VERSION 5.8 ;
BUSBITCHARS "[]" ;
DIVIDERCHAR "/" ;
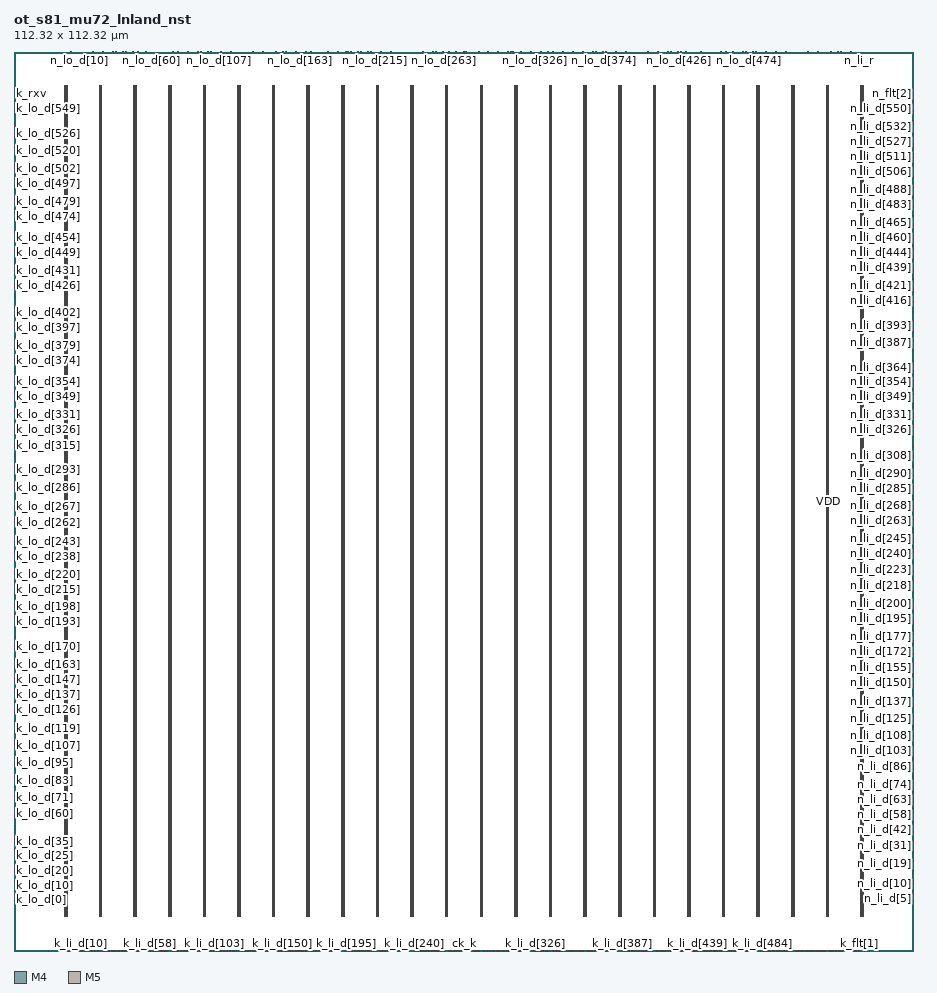
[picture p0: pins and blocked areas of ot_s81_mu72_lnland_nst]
MACRO ot_s81_mu72_lnland_nst
 CLASS BLOCK ;
 ORIGIN 0 0 ;
 SIZE 112.32 BY 112.32 ;
 SYMMETRY X Y ;
 PIN k_lo_v
  DIRECTION INPUT ;
  USE SIGNAL ;
  PORT
   LAYER M4 ;
   RECT 0.000000 6.240000 0.084000 6.264000 ;
  END
 END k_lo_v
 PIN k_lo_d[0]
  DIRECTION INPUT ;
  USE SIGNAL ;
  PORT
   LAYER M4 ;
   RECT 0.000000 6.384000 0.084000 6.408000 ;
  END
 END k_lo_d[0]
 PIN k_lo_d[1]
  DIRECTION INPUT ;
  USE SIGNAL ;
  PORT
   LAYER M4 ;
   RECT 0.000000 6.576000 0.084000 6.600000 ;
  END
 END k_lo_d[1]
 PIN k_lo_d[2]
  DIRECTION INPUT ;
  USE SIGNAL ;
  PORT
   LAYER M4 ;
   RECT 0.000000 6.768000 0.084000 6.792000 ;
  END
 END k_lo_d[2]
 PIN k_lo_d[3]
  DIRECTION INPUT ;
  USE SIGNAL ;
  PORT
   LAYER M4 ;
   RECT 0.000000 6.960000 0.084000 6.984000 ;
  END
 END k_lo_d[3]
 PIN k_lo_d[4]
  DIRECTION INPUT ;
  USE SIGNAL ;
  PORT
   LAYER M4 ;
   RECT 0.000000 7.104000 0.084000 7.128000 ;
  END
 END k_lo_d[4]
 PIN k_lo_d[5]
  DIRECTION INPUT ;
  USE SIGNAL ;
  PORT
   LAYER M4 ;
   RECT 0.000000 7.296000 0.084000 7.320000 ;
  END
 END k_lo_d[5]
 PIN k_lo_d[6]
  DIRECTION INPUT ;
  USE SIGNAL ;
  PORT
   LAYER M4 ;
   RECT 0.000000 7.488000 0.084000 7.512000 ;
  END
 END k_lo_d[6]
 PIN k_lo_d[7]
  DIRECTION INPUT ;
  USE SIGNAL ;
  PORT
   LAYER M4 ;
   RECT 0.000000 7.680000 0.084000 7.704000 ;
  END
 END k_lo_d[7]
 PIN k_lo_d[8]
  DIRECTION INPUT ;
  USE SIGNAL ;
  PORT
   LAYER M4 ;
   RECT 0.000000 7.824000 0.084000 7.848000 ;
  END
 END k_lo_d[8]
 PIN k_lo_d[9]
  DIRECTION INPUT ;
  USE SIGNAL ;
  PORT
   LAYER M4 ;
   RECT 0.000000 8.016000 0.084000 8.040000 ;
  END
 END k_lo_d[9]
 PIN k_lo_d[10]
  DIRECTION INPUT ;
  USE SIGNAL ;
  PORT
   LAYER M4 ;
   RECT 0.000000 8.208000 0.084000 8.232000 ;
  END
 END k_lo_d[10]
 PIN k_lo_d[11]
  DIRECTION INPUT ;
  USE SIGNAL ;
  PORT
   LAYER M4 ;
   RECT 0.000000 8.400000 0.084000 8.424000 ;
  END
 END k_lo_d[11]
 PIN k_lo_d[12]
  DIRECTION INPUT ;
  USE SIGNAL ;
  PORT
   LAYER M4 ;
   RECT 0.000000 8.544000 0.084000 8.568000 ;
  END
 END k_lo_d[12]
 PIN k_lo_d[13]
  DIRECTION INPUT ;
  USE SIGNAL ;
  PORT
   LAYER M4 ;
   RECT 0.000000 8.736000 0.084000 8.760000 ;
  END
 END k_lo_d[13]
 PIN k_lo_d[14]
  DIRECTION INPUT ;
  USE SIGNAL ;
  PORT
   LAYER M4 ;
   RECT 0.000000 8.928000 0.084000 8.952000 ;
  END
 END k_lo_d[14]
 PIN k_lo_d[15]
  DIRECTION INPUT ;
  USE SIGNAL ;
  PORT
   LAYER M4 ;
   RECT 0.000000 9.120000 0.084000 9.144000 ;
  END
 END k_lo_d[15]
 PIN k_lo_d[16]
  DIRECTION INPUT ;
  USE SIGNAL ;
  PORT
   LAYER M4 ;
   RECT 0.000000 9.264000 0.084000 9.288000 ;
  END
 END k_lo_d[16]
 PIN k_lo_d[17]
  DIRECTION INPUT ;
  USE SIGNAL ;
  PORT
   LAYER M4 ;
   RECT 0.000000 9.456000 0.084000 9.480000 ;
  END
 END k_lo_d[17]
 PIN k_lo_d[18]
  DIRECTION INPUT ;
  USE SIGNAL ;
  PORT
   LAYER M4 ;
   RECT 0.000000 9.648000 0.084000 9.672000 ;
  END
 END k_lo_d[18]
 PIN k_lo_d[19]
  DIRECTION INPUT ;
  USE SIGNAL ;
  PORT
   LAYER M4 ;
   RECT 0.000000 9.840000 0.084000 9.864000 ;
  END
 END k_lo_d[19]
 PIN k_lo_d[20]
  DIRECTION INPUT ;
  USE SIGNAL ;
  PORT
   LAYER M4 ;
   RECT 0.000000 9.984000 0.084000 10.008000 ;
  END
 END k_lo_d[20]
 PIN k_lo_d[21]
  DIRECTION INPUT ;
  USE SIGNAL ;
  PORT
   LAYER M4 ;
   RECT 0.000000 10.176000 0.084000 10.200000 ;
  END
 END k_lo_d[21]
 PIN k_lo_d[22]
  DIRECTION INPUT ;
  USE SIGNAL ;
  PORT
   LAYER M4 ;
   RECT 0.000000 10.368000 0.084000 10.392000 ;
  END
 END k_lo_d[22]
 PIN k_lo_d[23]
  DIRECTION INPUT ;
  USE SIGNAL ;
  PORT
   LAYER M4 ;
   RECT 0.000000 10.560000 0.084000 10.584000 ;
  END
 END k_lo_d[23]
 PIN k_lo_d[24]
  DIRECTION INPUT ;
  USE SIGNAL ;
  PORT
   LAYER M4 ;
   RECT 0.000000 10.704000 0.084000 10.728000 ;
  END
 END k_lo_d[24]
 PIN k_lo_d[25]
  DIRECTION INPUT ;
  USE SIGNAL ;
  PORT
   LAYER M4 ;
   RECT 0.000000 10.896000 0.084000 10.920000 ;
  END
 END k_lo_d[25]
 PIN k_lo_d[26]
  DIRECTION INPUT ;
  USE SIGNAL ;
  PORT
   LAYER M4 ;
   RECT 0.000000 11.088000 0.084000 11.112000 ;
  END
 END k_lo_d[26]
 PIN k_lo_d[27]
  DIRECTION INPUT ;
  USE SIGNAL ;
  PORT
   LAYER M4 ;
   RECT 0.000000 11.280000 0.084000 11.304000 ;
  END
 END k_lo_d[27]
 PIN k_lo_d[28]
  DIRECTION INPUT ;
  USE SIGNAL ;
  PORT
   LAYER M4 ;
   RECT 0.000000 11.424000 0.084000 11.448000 ;
  END
 END k_lo_d[28]
 PIN k_lo_d[29]
  DIRECTION INPUT ;
  USE SIGNAL ;
  PORT
   LAYER M4 ;
   RECT 0.000000 11.616000 0.084000 11.640000 ;
  END
 END k_lo_d[29]
 PIN k_lo_d[30]
  DIRECTION INPUT ;
  USE SIGNAL ;
  PORT
   LAYER M4 ;
   RECT 0.000000 11.808000 0.084000 11.832000 ;
  END
 END k_lo_d[30]
 PIN k_lo_d[31]
  DIRECTION INPUT ;
  USE SIGNAL ;
  PORT
   LAYER M4 ;
   RECT 0.000000 12.000000 0.084000 12.024000 ;
  END
 END k_lo_d[31]
 PIN k_lo_d[32]
  DIRECTION INPUT ;
  USE SIGNAL ;
  PORT
   LAYER M4 ;
   RECT 0.000000 12.144000 0.084000 12.168000 ;
  END
 END k_lo_d[32]
 PIN k_lo_d[33]
  DIRECTION INPUT ;
  USE SIGNAL ;
  PORT
   LAYER M4 ;
   RECT 0.000000 12.336000 0.084000 12.360000 ;
  END
 END k_lo_d[33]
 PIN k_lo_d[34]
  DIRECTION INPUT ;
  USE SIGNAL ;
  PORT
   LAYER M4 ;
   RECT 0.000000 12.528000 0.084000 12.552000 ;
  END
 END k_lo_d[34]
 PIN k_lo_d[35]
  DIRECTION INPUT ;
  USE SIGNAL ;
  PORT
   LAYER M4 ;
   RECT 0.000000 12.720000 0.084000 12.744000 ;
  END
 END k_lo_d[35]
 PIN k_lo_d[36]
  DIRECTION INPUT ;
  USE SIGNAL ;
  PORT
   LAYER M4 ;
   RECT 0.000000 12.864000 0.084000 12.888000 ;
  END
 END k_lo_d[36]
 PIN k_lo_d[37]
  DIRECTION INPUT ;
  USE SIGNAL ;
  PORT
   LAYER M4 ;
   RECT 0.000000 13.056000 0.084000 13.080000 ;
  END
 END k_lo_d[37]
 PIN k_lo_d[38]
  DIRECTION INPUT ;
  USE SIGNAL ;
  PORT
   LAYER M4 ;
   RECT 0.000000 13.248000 0.084000 13.272000 ;
  END
 END k_lo_d[38]
 PIN k_lo_d[39]
  DIRECTION INPUT ;
  USE SIGNAL ;
  PORT
   LAYER M4 ;
   RECT 0.000000 13.440000 0.084000 13.464000 ;
  END
 END k_lo_d[39]
 PIN k_lo_d[40]
  DIRECTION INPUT ;
  USE SIGNAL ;
  PORT
   LAYER M4 ;
   RECT 0.000000 13.584000 0.084000 13.608000 ;
  END
 END k_lo_d[40]
 PIN k_lo_d[41]
  DIRECTION INPUT ;
  USE SIGNAL ;
  PORT
   LAYER M4 ;
   RECT 0.000000 13.776000 0.084000 13.800000 ;
  END
 END k_lo_d[41]
 PIN k_lo_d[42]
  DIRECTION INPUT ;
  USE SIGNAL ;
  PORT
   LAYER M4 ;
   RECT 0.000000 13.968000 0.084000 13.992000 ;
  END
 END k_lo_d[42]
 PIN k_lo_d[43]
  DIRECTION INPUT ;
  USE SIGNAL ;
  PORT
   LAYER M4 ;
   RECT 0.000000 14.160000 0.084000 14.184000 ;
  END
 END k_lo_d[43]
 PIN k_lo_d[44]
  DIRECTION INPUT ;
  USE SIGNAL ;
  PORT
   LAYER M4 ;
   RECT 0.000000 14.304000 0.084000 14.328000 ;
  END
 END k_lo_d[44]
 PIN k_lo_d[45]
  DIRECTION INPUT ;
  USE SIGNAL ;
  PORT
   LAYER M4 ;
   RECT 0.000000 14.496000 0.084000 14.520000 ;
  END
 END k_lo_d[45]
 PIN k_lo_d[46]
  DIRECTION INPUT ;
  USE SIGNAL ;
  PORT
   LAYER M4 ;
   RECT 0.000000 14.688000 0.084000 14.712000 ;
  END
 END k_lo_d[46]
 PIN k_lo_d[47]
  DIRECTION INPUT ;
  USE SIGNAL ;
  PORT
   LAYER M4 ;
   RECT 0.000000 14.880000 0.084000 14.904000 ;
  END
 END k_lo_d[47]
 PIN k_lo_d[48]
  DIRECTION INPUT ;
  USE SIGNAL ;
  PORT
   LAYER M4 ;
   RECT 0.000000 15.024000 0.084000 15.048000 ;
  END
 END k_lo_d[48]
 PIN k_lo_d[49]
  DIRECTION INPUT ;
  USE SIGNAL ;
  PORT
   LAYER M4 ;
   RECT 0.000000 15.216000 0.084000 15.240000 ;
  END
 END k_lo_d[49]
 PIN k_lo_d[50]
  DIRECTION INPUT ;
  USE SIGNAL ;
  PORT
   LAYER M4 ;
   RECT 0.000000 15.408000 0.084000 15.432000 ;
  END
 END k_lo_d[50]
 PIN k_lo_d[51]
  DIRECTION INPUT ;
  USE SIGNAL ;
  PORT
   LAYER M4 ;
   RECT 0.000000 15.600000 0.084000 15.624000 ;
  END
 END k_lo_d[51]
 PIN k_lo_d[52]
  DIRECTION INPUT ;
  USE SIGNAL ;
  PORT
   LAYER M4 ;
   RECT 0.000000 15.744000 0.084000 15.768000 ;
  END
 END k_lo_d[52]
 PIN k_lo_d[53]
  DIRECTION INPUT ;
  USE SIGNAL ;
  PORT
   LAYER M4 ;
   RECT 0.000000 15.936000 0.084000 15.960000 ;
  END
 END k_lo_d[53]
 PIN k_lo_d[54]
  DIRECTION INPUT ;
  USE SIGNAL ;
  PORT
   LAYER M4 ;
   RECT 0.000000 16.128000 0.084000 16.152000 ;
  END
 END k_lo_d[54]
 PIN k_lo_d[55]
  DIRECTION INPUT ;
  USE SIGNAL ;
  PORT
   LAYER M4 ;
   RECT 0.000000 16.320000 0.084000 16.344000 ;
  END
 END k_lo_d[55]
 PIN k_lo_d[56]
  DIRECTION INPUT ;
  USE SIGNAL ;
  PORT
   LAYER M4 ;
   RECT 0.000000 16.464000 0.084000 16.488000 ;
  END
 END k_lo_d[56]
 PIN k_lo_d[57]
  DIRECTION INPUT ;
  USE SIGNAL ;
  PORT
   LAYER M4 ;
   RECT 0.000000 16.656000 0.084000 16.680000 ;
  END
 END k_lo_d[57]
 PIN k_lo_d[58]
  DIRECTION INPUT ;
  USE SIGNAL ;
  PORT
   LAYER M4 ;
   RECT 0.000000 16.848000 0.084000 16.872000 ;
  END
 END k_lo_d[58]
 PIN k_lo_d[59]
  DIRECTION INPUT ;
  USE SIGNAL ;
  PORT
   LAYER M4 ;
   RECT 0.000000 17.040000 0.084000 17.064000 ;
  END
 END k_lo_d[59]
 PIN k_lo_d[60]
  DIRECTION INPUT ;
  USE SIGNAL ;
  PORT
   LAYER M4 ;
   RECT 0.000000 17.184000 0.084000 17.208000 ;
  END
 END k_lo_d[60]
 PIN k_lo_d[61]
  DIRECTION INPUT ;
  USE SIGNAL ;
  PORT
   LAYER M4 ;
   RECT 0.000000 17.376000 0.084000 17.400000 ;
  END
 END k_lo_d[61]
 PIN k_lo_d[62]
  DIRECTION INPUT ;
  USE SIGNAL ;
  PORT
   LAYER M4 ;
   RECT 0.000000 17.568000 0.084000 17.592000 ;
  END
 END k_lo_d[62]
 PIN k_lo_d[63]
  DIRECTION INPUT ;
  USE SIGNAL ;
  PORT
   LAYER M4 ;
   RECT 0.000000 17.760000 0.084000 17.784000 ;
  END
 END k_lo_d[63]
 PIN k_lo_d[64]
  DIRECTION INPUT ;
  USE SIGNAL ;
  PORT
   LAYER M4 ;
   RECT 0.000000 17.904000 0.084000 17.928000 ;
  END
 END k_lo_d[64]
 PIN k_lo_d[65]
  DIRECTION INPUT ;
  USE SIGNAL ;
  PORT
   LAYER M4 ;
   RECT 0.000000 18.096000 0.084000 18.120000 ;
  END
 END k_lo_d[65]
 PIN k_lo_d[66]
  DIRECTION INPUT ;
  USE SIGNAL ;
  PORT
   LAYER M4 ;
   RECT 0.000000 18.288000 0.084000 18.312000 ;
  END
 END k_lo_d[66]
 PIN k_lo_d[67]
  DIRECTION INPUT ;
  USE SIGNAL ;
  PORT
   LAYER M4 ;
   RECT 0.000000 18.480000 0.084000 18.504000 ;
  END
 END k_lo_d[67]
 PIN k_lo_d[68]
  DIRECTION INPUT ;
  USE SIGNAL ;
  PORT
   LAYER M4 ;
   RECT 0.000000 18.624000 0.084000 18.648000 ;
  END
 END k_lo_d[68]
 PIN k_lo_d[69]
  DIRECTION INPUT ;
  USE SIGNAL ;
  PORT
   LAYER M4 ;
   RECT 0.000000 18.816000 0.084000 18.840000 ;
  END
 END k_lo_d[69]
 PIN k_lo_d[70]
  DIRECTION INPUT ;
  USE SIGNAL ;
  PORT
   LAYER M4 ;
   RECT 0.000000 19.008000 0.084000 19.032000 ;
  END
 END k_lo_d[70]
 PIN k_lo_d[71]
  DIRECTION INPUT ;
  USE SIGNAL ;
  PORT
   LAYER M4 ;
   RECT 0.000000 19.152000 0.084000 19.176000 ;
  END
 END k_lo_d[71]
 PIN k_lo_d[72]
  DIRECTION INPUT ;
  USE SIGNAL ;
  PORT
   LAYER M4 ;
   RECT 0.000000 19.344000 0.084000 19.368000 ;
  END
 END k_lo_d[72]
 PIN k_lo_d[73]
  DIRECTION INPUT ;
  USE SIGNAL ;
  PORT
   LAYER M4 ;
   RECT 0.000000 19.536000 0.084000 19.560000 ;
  END
 END k_lo_d[73]
 PIN k_lo_d[74]
  DIRECTION INPUT ;
  USE SIGNAL ;
  PORT
   LAYER M4 ;
   RECT 0.000000 19.728000 0.084000 19.752000 ;
  END
 END k_lo_d[74]
 PIN k_lo_d[75]
  DIRECTION INPUT ;
  USE SIGNAL ;
  PORT
   LAYER M4 ;
   RECT 0.000000 19.872000 0.084000 19.896000 ;
  END
 END k_lo_d[75]
 PIN k_lo_d[76]
  DIRECTION INPUT ;
  USE SIGNAL ;
  PORT
   LAYER M4 ;
   RECT 0.000000 20.064000 0.084000 20.088000 ;
  END
 END k_lo_d[76]
 PIN k_lo_d[77]
  DIRECTION INPUT ;
  USE SIGNAL ;
  PORT
   LAYER M4 ;
   RECT 0.000000 20.256000 0.084000 20.280000 ;
  END
 END k_lo_d[77]
 PIN k_lo_d[78]
  DIRECTION INPUT ;
  USE SIGNAL ;
  PORT
   LAYER M4 ;
   RECT 0.000000 20.448000 0.084000 20.472000 ;
  END
 END k_lo_d[78]
 PIN k_lo_d[79]
  DIRECTION INPUT ;
  USE SIGNAL ;
  PORT
   LAYER M4 ;
   RECT 0.000000 20.592000 0.084000 20.616000 ;
  END
 END k_lo_d[79]
 PIN k_lo_d[80]
  DIRECTION INPUT ;
  USE SIGNAL ;
  PORT
   LAYER M4 ;
   RECT 0.000000 20.784000 0.084000 20.808000 ;
  END
 END k_lo_d[80]
 PIN k_lo_d[81]
  DIRECTION INPUT ;
  USE SIGNAL ;
  PORT
   LAYER M4 ;
   RECT 0.000000 20.976000 0.084000 21.000000 ;
  END
 END k_lo_d[81]
 PIN k_lo_d[82]
  DIRECTION INPUT ;
  USE SIGNAL ;
  PORT
   LAYER M4 ;
   RECT 0.000000 21.168000 0.084000 21.192000 ;
  END
 END k_lo_d[82]
 PIN k_lo_d[83]
  DIRECTION INPUT ;
  USE SIGNAL ;
  PORT
   LAYER M4 ;
   RECT 0.000000 21.312000 0.084000 21.336000 ;
  END
 END k_lo_d[83]
 PIN k_lo_d[84]
  DIRECTION INPUT ;
  USE SIGNAL ;
  PORT
   LAYER M4 ;
   RECT 0.000000 21.504000 0.084000 21.528000 ;
  END
 END k_lo_d[84]
 PIN k_lo_d[85]
  DIRECTION INPUT ;
  USE SIGNAL ;
  PORT
   LAYER M4 ;
   RECT 0.000000 21.696000 0.084000 21.720000 ;
  END
 END k_lo_d[85]
 PIN k_lo_d[86]
  DIRECTION INPUT ;
  USE SIGNAL ;
  PORT
   LAYER M4 ;
   RECT 0.000000 21.888000 0.084000 21.912000 ;
  END
 END k_lo_d[86]
 PIN k_lo_d[87]
  DIRECTION INPUT ;
  USE SIGNAL ;
  PORT
   LAYER M4 ;
   RECT 0.000000 22.032000 0.084000 22.056000 ;
  END
 END k_lo_d[87]
 PIN k_lo_d[88]
  DIRECTION INPUT ;
  USE SIGNAL ;
  PORT
   LAYER M4 ;
   RECT 0.000000 22.224000 0.084000 22.248000 ;
  END
 END k_lo_d[88]
 PIN k_lo_d[89]
  DIRECTION INPUT ;
  USE SIGNAL ;
  PORT
   LAYER M4 ;
   RECT 0.000000 22.416000 0.084000 22.440000 ;
  END
 END k_lo_d[89]
 PIN k_lo_d[90]
  DIRECTION INPUT ;
  USE SIGNAL ;
  PORT
   LAYER M4 ;
   RECT 0.000000 22.608000 0.084000 22.632000 ;
  END
 END k_lo_d[90]
 PIN k_lo_d[91]
  DIRECTION INPUT ;
  USE SIGNAL ;
  PORT
   LAYER M4 ;
   RECT 0.000000 22.752000 0.084000 22.776000 ;
  END
 END k_lo_d[91]
 PIN k_lo_d[92]
  DIRECTION INPUT ;
  USE SIGNAL ;
  PORT
   LAYER M4 ;
   RECT 0.000000 22.944000 0.084000 22.968000 ;
  END
 END k_lo_d[92]
 PIN k_lo_d[93]
  DIRECTION INPUT ;
  USE SIGNAL ;
  PORT
   LAYER M4 ;
   RECT 0.000000 23.136000 0.084000 23.160000 ;
  END
 END k_lo_d[93]
 PIN k_lo_d[94]
  DIRECTION INPUT ;
  USE SIGNAL ;
  PORT
   LAYER M4 ;
   RECT 0.000000 23.328000 0.084000 23.352000 ;
  END
 END k_lo_d[94]
 PIN k_lo_d[95]
  DIRECTION INPUT ;
  USE SIGNAL ;
  PORT
   LAYER M4 ;
   RECT 0.000000 23.472000 0.084000 23.496000 ;
  END
 END k_lo_d[95]
 PIN k_lo_d[96]
  DIRECTION INPUT ;
  USE SIGNAL ;
  PORT
   LAYER M4 ;
   RECT 0.000000 23.664000 0.084000 23.688000 ;
  END
 END k_lo_d[96]
 PIN k_lo_d[97]
  DIRECTION INPUT ;
  USE SIGNAL ;
  PORT
   LAYER M4 ;
   RECT 0.000000 23.856000 0.084000 23.880000 ;
  END
 END k_lo_d[97]
 PIN k_lo_d[98]
  DIRECTION INPUT ;
  USE SIGNAL ;
  PORT
   LAYER M4 ;
   RECT 0.000000 24.048000 0.084000 24.072000 ;
  END
 END k_lo_d[98]
 PIN k_lo_d[99]
  DIRECTION INPUT ;
  USE SIGNAL ;
  PORT
   LAYER M4 ;
   RECT 0.000000 24.192000 0.084000 24.216000 ;
  END
 END k_lo_d[99]
 PIN k_lo_d[100]
  DIRECTION INPUT ;
  USE SIGNAL ;
  PORT
   LAYER M4 ;
   RECT 0.000000 24.384000 0.084000 24.408000 ;
  END
 END k_lo_d[100]
 PIN k_lo_d[101]
  DIRECTION INPUT ;
  USE SIGNAL ;
  PORT
   LAYER M4 ;
   RECT 0.000000 24.576000 0.084000 24.600000 ;
  END
 END k_lo_d[101]
 PIN k_lo_d[102]
  DIRECTION INPUT ;
  USE SIGNAL ;
  PORT
   LAYER M4 ;
   RECT 0.000000 24.768000 0.084000 24.792000 ;
  END
 END k_lo_d[102]
 PIN k_lo_d[103]
  DIRECTION INPUT ;
  USE SIGNAL ;
  PORT
   LAYER M4 ;
   RECT 0.000000 24.912000 0.084000 24.936000 ;
  END
 END k_lo_d[103]
 PIN k_lo_d[104]
  DIRECTION INPUT ;
  USE SIGNAL ;
  PORT
   LAYER M4 ;
   RECT 0.000000 25.104000 0.084000 25.128000 ;
  END
 END k_lo_d[104]
 PIN k_lo_d[105]
  DIRECTION INPUT ;
  USE SIGNAL ;
  PORT
   LAYER M4 ;
   RECT 0.000000 25.296000 0.084000 25.320000 ;
  END
 END k_lo_d[105]
 PIN k_lo_d[106]
  DIRECTION INPUT ;
  USE SIGNAL ;
  PORT
   LAYER M4 ;
   RECT 0.000000 25.488000 0.084000 25.512000 ;
  END
 END k_lo_d[106]
 PIN k_lo_d[107]
  DIRECTION INPUT ;
  USE SIGNAL ;
  PORT
   LAYER M4 ;
   RECT 0.000000 25.632000 0.084000 25.656000 ;
  END
 END k_lo_d[107]
 PIN k_lo_d[108]
  DIRECTION INPUT ;
  USE SIGNAL ;
  PORT
   LAYER M4 ;
   RECT 0.000000 25.824000 0.084000 25.848000 ;
  END
 END k_lo_d[108]
 PIN k_lo_d[109]
  DIRECTION INPUT ;
  USE SIGNAL ;
  PORT
   LAYER M4 ;
   RECT 0.000000 26.016000 0.084000 26.040000 ;
  END
 END k_lo_d[109]
 PIN k_lo_d[110]
  DIRECTION INPUT ;
  USE SIGNAL ;
  PORT
   LAYER M4 ;
   RECT 0.000000 26.208000 0.084000 26.232000 ;
  END
 END k_lo_d[110]
 PIN k_lo_d[111]
  DIRECTION INPUT ;
  USE SIGNAL ;
  PORT
   LAYER M4 ;
   RECT 0.000000 26.352000 0.084000 26.376000 ;
  END
 END k_lo_d[111]
 PIN k_lo_d[112]
  DIRECTION INPUT ;
  USE SIGNAL ;
  PORT
   LAYER M4 ;
   RECT 0.000000 26.544000 0.084000 26.568000 ;
  END
 END k_lo_d[112]
 PIN k_lo_d[113]
  DIRECTION INPUT ;
  USE SIGNAL ;
  PORT
   LAYER M4 ;
   RECT 0.000000 26.736000 0.084000 26.760000 ;
  END
 END k_lo_d[113]
 PIN k_lo_d[114]
  DIRECTION INPUT ;
  USE SIGNAL ;
  PORT
   LAYER M4 ;
   RECT 0.000000 26.928000 0.084000 26.952000 ;
  END
 END k_lo_d[114]
 PIN k_lo_d[115]
  DIRECTION INPUT ;
  USE SIGNAL ;
  PORT
   LAYER M4 ;
   RECT 0.000000 27.072000 0.084000 27.096000 ;
  END
 END k_lo_d[115]
 PIN k_lo_d[116]
  DIRECTION INPUT ;
  USE SIGNAL ;
  PORT
   LAYER M4 ;
   RECT 0.000000 27.264000 0.084000 27.288000 ;
  END
 END k_lo_d[116]
 PIN k_lo_d[117]
  DIRECTION INPUT ;
  USE SIGNAL ;
  PORT
   LAYER M4 ;
   RECT 0.000000 27.456000 0.084000 27.480000 ;
  END
 END k_lo_d[117]
 PIN k_lo_d[118]
  DIRECTION INPUT ;
  USE SIGNAL ;
  PORT
   LAYER M4 ;
   RECT 0.000000 27.648000 0.084000 27.672000 ;
  END
 END k_lo_d[118]
 PIN k_lo_d[119]
  DIRECTION INPUT ;
  USE SIGNAL ;
  PORT
   LAYER M4 ;
   RECT 0.000000 27.792000 0.084000 27.816000 ;
  END
 END k_lo_d[119]
 PIN k_lo_d[120]
  DIRECTION INPUT ;
  USE SIGNAL ;
  PORT
   LAYER M4 ;
   RECT 0.000000 27.984000 0.084000 28.008000 ;
  END
 END k_lo_d[120]
 PIN k_lo_d[121]
  DIRECTION INPUT ;
  USE SIGNAL ;
  PORT
   LAYER M4 ;
   RECT 0.000000 28.176000 0.084000 28.200000 ;
  END
 END k_lo_d[121]
 PIN k_lo_d[122]
  DIRECTION INPUT ;
  USE SIGNAL ;
  PORT
   LAYER M4 ;
   RECT 0.000000 28.368000 0.084000 28.392000 ;
  END
 END k_lo_d[122]
 PIN k_lo_d[123]
  DIRECTION INPUT ;
  USE SIGNAL ;
  PORT
   LAYER M4 ;
   RECT 0.000000 28.512000 0.084000 28.536000 ;
  END
 END k_lo_d[123]
 PIN k_lo_d[124]
  DIRECTION INPUT ;
  USE SIGNAL ;
  PORT
   LAYER M4 ;
   RECT 0.000000 28.704000 0.084000 28.728000 ;
  END
 END k_lo_d[124]
 PIN k_lo_d[125]
  DIRECTION INPUT ;
  USE SIGNAL ;
  PORT
   LAYER M4 ;
   RECT 0.000000 28.896000 0.084000 28.920000 ;
  END
 END k_lo_d[125]
 PIN k_lo_d[126]
  DIRECTION INPUT ;
  USE SIGNAL ;
  PORT
   LAYER M4 ;
   RECT 0.000000 29.088000 0.084000 29.112000 ;
  END
 END k_lo_d[126]
 PIN k_lo_d[127]
  DIRECTION INPUT ;
  USE SIGNAL ;
  PORT
   LAYER M4 ;
   RECT 0.000000 29.232000 0.084000 29.256000 ;
  END
 END k_lo_d[127]
 PIN k_lo_d[128]
  DIRECTION INPUT ;
  USE SIGNAL ;
  PORT
   LAYER M4 ;
   RECT 0.000000 29.424000 0.084000 29.448000 ;
  END
 END k_lo_d[128]
 PIN k_lo_d[129]
  DIRECTION INPUT ;
  USE SIGNAL ;
  PORT
   LAYER M4 ;
   RECT 0.000000 29.616000 0.084000 29.640000 ;
  END
 END k_lo_d[129]
 PIN k_lo_d[130]
  DIRECTION INPUT ;
  USE SIGNAL ;
  PORT
   LAYER M4 ;
   RECT 0.000000 29.808000 0.084000 29.832000 ;
  END
 END k_lo_d[130]
 PIN k_lo_d[131]
  DIRECTION INPUT ;
  USE SIGNAL ;
  PORT
   LAYER M4 ;
   RECT 0.000000 29.952000 0.084000 29.976000 ;
  END
 END k_lo_d[131]
 PIN k_lo_d[132]
  DIRECTION INPUT ;
  USE SIGNAL ;
  PORT
   LAYER M4 ;
   RECT 0.000000 30.144000 0.084000 30.168000 ;
  END
 END k_lo_d[132]
 PIN k_lo_d[133]
  DIRECTION INPUT ;
  USE SIGNAL ;
  PORT
   LAYER M4 ;
   RECT 0.000000 30.336000 0.084000 30.360000 ;
  END
 END k_lo_d[133]
 PIN k_lo_d[134]
  DIRECTION INPUT ;
  USE SIGNAL ;
  PORT
   LAYER M4 ;
   RECT 0.000000 30.528000 0.084000 30.552000 ;
  END
 END k_lo_d[134]
 PIN k_lo_d[135]
  DIRECTION INPUT ;
  USE SIGNAL ;
  PORT
   LAYER M4 ;
   RECT 0.000000 30.672000 0.084000 30.696000 ;
  END
 END k_lo_d[135]
 PIN k_lo_d[136]
  DIRECTION INPUT ;
  USE SIGNAL ;
  PORT
   LAYER M4 ;
   RECT 0.000000 30.864000 0.084000 30.888000 ;
  END
 END k_lo_d[136]
 PIN k_lo_d[137]
  DIRECTION INPUT ;
  USE SIGNAL ;
  PORT
   LAYER M4 ;
   RECT 0.000000 31.056000 0.084000 31.080000 ;
  END
 END k_lo_d[137]
 PIN k_lo_d[138]
  DIRECTION INPUT ;
  USE SIGNAL ;
  PORT
   LAYER M4 ;
   RECT 0.000000 31.248000 0.084000 31.272000 ;
  END
 END k_lo_d[138]
 PIN k_lo_d[139]
  DIRECTION INPUT ;
  USE SIGNAL ;
  PORT
   LAYER M4 ;
   RECT 0.000000 31.392000 0.084000 31.416000 ;
  END
 END k_lo_d[139]
 PIN k_lo_d[140]
  DIRECTION INPUT ;
  USE SIGNAL ;
  PORT
   LAYER M4 ;
   RECT 0.000000 31.584000 0.084000 31.608000 ;
  END
 END k_lo_d[140]
 PIN k_lo_d[141]
  DIRECTION INPUT ;
  USE SIGNAL ;
  PORT
   LAYER M4 ;
   RECT 0.000000 31.776000 0.084000 31.800000 ;
  END
 END k_lo_d[141]
 PIN k_lo_d[142]
  DIRECTION INPUT ;
  USE SIGNAL ;
  PORT
   LAYER M4 ;
   RECT 0.000000 31.968000 0.084000 31.992000 ;
  END
 END k_lo_d[142]
 PIN k_lo_d[143]
  DIRECTION INPUT ;
  USE SIGNAL ;
  PORT
   LAYER M4 ;
   RECT 0.000000 32.112000 0.084000 32.136000 ;
  END
 END k_lo_d[143]
 PIN k_lo_d[144]
  DIRECTION INPUT ;
  USE SIGNAL ;
  PORT
   LAYER M4 ;
   RECT 0.000000 32.304000 0.084000 32.328000 ;
  END
 END k_lo_d[144]
 PIN k_lo_d[145]
  DIRECTION INPUT ;
  USE SIGNAL ;
  PORT
   LAYER M4 ;
   RECT 0.000000 32.496000 0.084000 32.520000 ;
  END
 END k_lo_d[145]
 PIN k_lo_d[146]
  DIRECTION INPUT ;
  USE SIGNAL ;
  PORT
   LAYER M4 ;
   RECT 0.000000 32.688000 0.084000 32.712000 ;
  END
 END k_lo_d[146]
 PIN k_lo_d[147]
  DIRECTION INPUT ;
  USE SIGNAL ;
  PORT
   LAYER M4 ;
   RECT 0.000000 32.832000 0.084000 32.856000 ;
  END
 END k_lo_d[147]
 PIN k_lo_d[148]
  DIRECTION INPUT ;
  USE SIGNAL ;
  PORT
   LAYER M4 ;
   RECT 0.000000 33.024000 0.084000 33.048000 ;
  END
 END k_lo_d[148]
 PIN k_lo_d[149]
  DIRECTION INPUT ;
  USE SIGNAL ;
  PORT
   LAYER M4 ;
   RECT 0.000000 33.216000 0.084000 33.240000 ;
  END
 END k_lo_d[149]
 PIN k_lo_d[150]
  DIRECTION INPUT ;
  USE SIGNAL ;
  PORT
   LAYER M4 ;
   RECT 0.000000 33.408000 0.084000 33.432000 ;
  END
 END k_lo_d[150]
 PIN k_lo_d[151]
  DIRECTION INPUT ;
  USE SIGNAL ;
  PORT
   LAYER M4 ;
   RECT 0.000000 33.552000 0.084000 33.576000 ;
  END
 END k_lo_d[151]
 PIN k_lo_d[152]
  DIRECTION INPUT ;
  USE SIGNAL ;
  PORT
   LAYER M4 ;
   RECT 0.000000 33.744000 0.084000 33.768000 ;
  END
 END k_lo_d[152]
 PIN k_lo_d[153]
  DIRECTION INPUT ;
  USE SIGNAL ;
  PORT
   LAYER M4 ;
   RECT 0.000000 33.936000 0.084000 33.960000 ;
  END
 END k_lo_d[153]
 PIN k_lo_d[154]
  DIRECTION INPUT ;
  USE SIGNAL ;
  PORT
   LAYER M4 ;
   RECT 0.000000 34.128000 0.084000 34.152000 ;
  END
 END k_lo_d[154]
 PIN k_lo_d[155]
  DIRECTION INPUT ;
  USE SIGNAL ;
  PORT
   LAYER M4 ;
   RECT 0.000000 34.272000 0.084000 34.296000 ;
  END
 END k_lo_d[155]
 PIN k_lo_d[156]
  DIRECTION INPUT ;
  USE SIGNAL ;
  PORT
   LAYER M4 ;
   RECT 0.000000 34.464000 0.084000 34.488000 ;
  END
 END k_lo_d[156]
 PIN k_lo_d[157]
  DIRECTION INPUT ;
  USE SIGNAL ;
  PORT
   LAYER M4 ;
   RECT 0.000000 34.656000 0.084000 34.680000 ;
  END
 END k_lo_d[157]
 PIN k_lo_d[158]
  DIRECTION INPUT ;
  USE SIGNAL ;
  PORT
   LAYER M4 ;
   RECT 0.000000 34.848000 0.084000 34.872000 ;
  END
 END k_lo_d[158]
 PIN k_lo_d[159]
  DIRECTION INPUT ;
  USE SIGNAL ;
  PORT
   LAYER M4 ;
   RECT 0.000000 34.992000 0.084000 35.016000 ;
  END
 END k_lo_d[159]
 PIN k_lo_d[160]
  DIRECTION INPUT ;
  USE SIGNAL ;
  PORT
   LAYER M4 ;
   RECT 0.000000 35.184000 0.084000 35.208000 ;
  END
 END k_lo_d[160]
 PIN k_lo_d[161]
  DIRECTION INPUT ;
  USE SIGNAL ;
  PORT
   LAYER M4 ;
   RECT 0.000000 35.376000 0.084000 35.400000 ;
  END
 END k_lo_d[161]
 PIN k_lo_d[162]
  DIRECTION INPUT ;
  USE SIGNAL ;
  PORT
   LAYER M4 ;
   RECT 0.000000 35.568000 0.084000 35.592000 ;
  END
 END k_lo_d[162]
 PIN k_lo_d[163]
  DIRECTION INPUT ;
  USE SIGNAL ;
  PORT
   LAYER M4 ;
   RECT 0.000000 35.712000 0.084000 35.736000 ;
  END
 END k_lo_d[163]
 PIN k_lo_d[164]
  DIRECTION INPUT ;
  USE SIGNAL ;
  PORT
   LAYER M4 ;
   RECT 0.000000 35.904000 0.084000 35.928000 ;
  END
 END k_lo_d[164]
 PIN k_lo_d[165]
  DIRECTION INPUT ;
  USE SIGNAL ;
  PORT
   LAYER M4 ;
   RECT 0.000000 36.096000 0.084000 36.120000 ;
  END
 END k_lo_d[165]
 PIN k_lo_d[166]
  DIRECTION INPUT ;
  USE SIGNAL ;
  PORT
   LAYER M4 ;
   RECT 0.000000 36.288000 0.084000 36.312000 ;
  END
 END k_lo_d[166]
 PIN k_lo_d[167]
  DIRECTION INPUT ;
  USE SIGNAL ;
  PORT
   LAYER M4 ;
   RECT 0.000000 36.432000 0.084000 36.456000 ;
  END
 END k_lo_d[167]
 PIN k_lo_d[168]
  DIRECTION INPUT ;
  USE SIGNAL ;
  PORT
   LAYER M4 ;
   RECT 0.000000 36.624000 0.084000 36.648000 ;
  END
 END k_lo_d[168]
 PIN k_lo_d[169]
  DIRECTION INPUT ;
  USE SIGNAL ;
  PORT
   LAYER M4 ;
   RECT 0.000000 36.816000 0.084000 36.840000 ;
  END
 END k_lo_d[169]
 PIN k_lo_d[170]
  DIRECTION INPUT ;
  USE SIGNAL ;
  PORT
   LAYER M4 ;
   RECT 0.000000 37.008000 0.084000 37.032000 ;
  END
 END k_lo_d[170]
 PIN k_lo_d[171]
  DIRECTION INPUT ;
  USE SIGNAL ;
  PORT
   LAYER M4 ;
   RECT 0.000000 37.152000 0.084000 37.176000 ;
  END
 END k_lo_d[171]
 PIN k_lo_d[172]
  DIRECTION INPUT ;
  USE SIGNAL ;
  PORT
   LAYER M4 ;
   RECT 0.000000 37.344000 0.084000 37.368000 ;
  END
 END k_lo_d[172]
 PIN k_lo_d[173]
  DIRECTION INPUT ;
  USE SIGNAL ;
  PORT
   LAYER M4 ;
   RECT 0.000000 37.536000 0.084000 37.560000 ;
  END
 END k_lo_d[173]
 PIN k_lo_d[174]
  DIRECTION INPUT ;
  USE SIGNAL ;
  PORT
   LAYER M4 ;
   RECT 0.000000 37.728000 0.084000 37.752000 ;
  END
 END k_lo_d[174]
 PIN k_lo_d[175]
  DIRECTION INPUT ;
  USE SIGNAL ;
  PORT
   LAYER M4 ;
   RECT 0.000000 37.872000 0.084000 37.896000 ;
  END
 END k_lo_d[175]
 PIN k_lo_d[176]
  DIRECTION INPUT ;
  USE SIGNAL ;
  PORT
   LAYER M4 ;
   RECT 0.000000 38.064000 0.084000 38.088000 ;
  END
 END k_lo_d[176]
 PIN k_lo_d[177]
  DIRECTION INPUT ;
  USE SIGNAL ;
  PORT
   LAYER M4 ;
   RECT 0.000000 38.256000 0.084000 38.280000 ;
  END
 END k_lo_d[177]
 PIN k_lo_d[178]
  DIRECTION INPUT ;
  USE SIGNAL ;
  PORT
   LAYER M4 ;
   RECT 0.000000 38.448000 0.084000 38.472000 ;
  END
 END k_lo_d[178]
 PIN k_lo_d[179]
  DIRECTION INPUT ;
  USE SIGNAL ;
  PORT
   LAYER M4 ;
   RECT 0.000000 38.592000 0.084000 38.616000 ;
  END
 END k_lo_d[179]
 PIN k_lo_d[180]
  DIRECTION INPUT ;
  USE SIGNAL ;
  PORT
   LAYER M4 ;
   RECT 0.000000 38.784000 0.084000 38.808000 ;
  END
 END k_lo_d[180]
 PIN k_lo_d[181]
  DIRECTION INPUT ;
  USE SIGNAL ;
  PORT
   LAYER M4 ;
   RECT 0.000000 38.976000 0.084000 39.000000 ;
  END
 END k_lo_d[181]
 PIN k_lo_d[182]
  DIRECTION INPUT ;
  USE SIGNAL ;
  PORT
   LAYER M4 ;
   RECT 0.000000 39.168000 0.084000 39.192000 ;
  END
 END k_lo_d[182]
 PIN k_lo_d[183]
  DIRECTION INPUT ;
  USE SIGNAL ;
  PORT
   LAYER M4 ;
   RECT 0.000000 39.312000 0.084000 39.336000 ;
  END
 END k_lo_d[183]
 PIN k_lo_d[184]
  DIRECTION INPUT ;
  USE SIGNAL ;
  PORT
   LAYER M4 ;
   RECT 0.000000 39.504000 0.084000 39.528000 ;
  END
 END k_lo_d[184]
 PIN k_lo_d[185]
  DIRECTION INPUT ;
  USE SIGNAL ;
  PORT
   LAYER M4 ;
   RECT 0.000000 39.696000 0.084000 39.720000 ;
  END
 END k_lo_d[185]
 PIN k_lo_d[186]
  DIRECTION INPUT ;
  USE SIGNAL ;
  PORT
   LAYER M4 ;
   RECT 0.000000 39.888000 0.084000 39.912000 ;
  END
 END k_lo_d[186]
 PIN k_lo_d[187]
  DIRECTION INPUT ;
  USE SIGNAL ;
  PORT
   LAYER M4 ;
   RECT 0.000000 40.032000 0.084000 40.056000 ;
  END
 END k_lo_d[187]
 PIN k_lo_d[188]
  DIRECTION INPUT ;
  USE SIGNAL ;
  PORT
   LAYER M4 ;
   RECT 0.000000 40.224000 0.084000 40.248000 ;
  END
 END k_lo_d[188]
 PIN k_lo_d[189]
  DIRECTION INPUT ;
  USE SIGNAL ;
  PORT
   LAYER M4 ;
   RECT 0.000000 40.416000 0.084000 40.440000 ;
  END
 END k_lo_d[189]
 PIN k_lo_d[190]
  DIRECTION INPUT ;
  USE SIGNAL ;
  PORT
   LAYER M4 ;
   RECT 0.000000 40.608000 0.084000 40.632000 ;
  END
 END k_lo_d[190]
 PIN k_lo_d[191]
  DIRECTION INPUT ;
  USE SIGNAL ;
  PORT
   LAYER M4 ;
   RECT 0.000000 40.752000 0.084000 40.776000 ;
  END
 END k_lo_d[191]
 PIN k_lo_d[192]
  DIRECTION INPUT ;
  USE SIGNAL ;
  PORT
   LAYER M4 ;
   RECT 0.000000 40.944000 0.084000 40.968000 ;
  END
 END k_lo_d[192]
 PIN k_lo_d[193]
  DIRECTION INPUT ;
  USE SIGNAL ;
  PORT
   LAYER M4 ;
   RECT 0.000000 41.136000 0.084000 41.160000 ;
  END
 END k_lo_d[193]
 PIN k_lo_d[194]
  DIRECTION INPUT ;
  USE SIGNAL ;
  PORT
   LAYER M4 ;
   RECT 0.000000 41.328000 0.084000 41.352000 ;
  END
 END k_lo_d[194]
 PIN k_lo_d[195]
  DIRECTION INPUT ;
  USE SIGNAL ;
  PORT
   LAYER M4 ;
   RECT 0.000000 41.472000 0.084000 41.496000 ;
  END
 END k_lo_d[195]
 PIN k_lo_d[196]
  DIRECTION INPUT ;
  USE SIGNAL ;
  PORT
   LAYER M4 ;
   RECT 0.000000 41.664000 0.084000 41.688000 ;
  END
 END k_lo_d[196]
 PIN k_lo_d[197]
  DIRECTION INPUT ;
  USE SIGNAL ;
  PORT
   LAYER M4 ;
   RECT 0.000000 41.856000 0.084000 41.880000 ;
  END
 END k_lo_d[197]
 PIN k_lo_d[198]
  DIRECTION INPUT ;
  USE SIGNAL ;
  PORT
   LAYER M4 ;
   RECT 0.000000 42.048000 0.084000 42.072000 ;
  END
 END k_lo_d[198]
 PIN k_lo_d[199]
  DIRECTION INPUT ;
  USE SIGNAL ;
  PORT
   LAYER M4 ;
   RECT 0.000000 42.192000 0.084000 42.216000 ;
  END
 END k_lo_d[199]
 PIN k_lo_d[200]
  DIRECTION INPUT ;
  USE SIGNAL ;
  PORT
   LAYER M4 ;
   RECT 0.000000 42.384000 0.084000 42.408000 ;
  END
 END k_lo_d[200]
 PIN k_lo_d[201]
  DIRECTION INPUT ;
  USE SIGNAL ;
  PORT
   LAYER M4 ;
   RECT 0.000000 42.576000 0.084000 42.600000 ;
  END
 END k_lo_d[201]
 PIN k_lo_d[202]
  DIRECTION INPUT ;
  USE SIGNAL ;
  PORT
   LAYER M4 ;
   RECT 0.000000 42.768000 0.084000 42.792000 ;
  END
 END k_lo_d[202]
 PIN k_lo_d[203]
  DIRECTION INPUT ;
  USE SIGNAL ;
  PORT
   LAYER M4 ;
   RECT 0.000000 42.912000 0.084000 42.936000 ;
  END
 END k_lo_d[203]
 PIN k_lo_d[204]
  DIRECTION INPUT ;
  USE SIGNAL ;
  PORT
   LAYER M4 ;
   RECT 0.000000 43.104000 0.084000 43.128000 ;
  END
 END k_lo_d[204]
 PIN k_lo_d[205]
  DIRECTION INPUT ;
  USE SIGNAL ;
  PORT
   LAYER M4 ;
   RECT 0.000000 43.296000 0.084000 43.320000 ;
  END
 END k_lo_d[205]
 PIN k_lo_d[206]
  DIRECTION INPUT ;
  USE SIGNAL ;
  PORT
   LAYER M4 ;
   RECT 0.000000 43.488000 0.084000 43.512000 ;
  END
 END k_lo_d[206]
 PIN k_lo_d[207]
  DIRECTION INPUT ;
  USE SIGNAL ;
  PORT
   LAYER M4 ;
   RECT 0.000000 43.632000 0.084000 43.656000 ;
  END
 END k_lo_d[207]
 PIN k_lo_d[208]
  DIRECTION INPUT ;
  USE SIGNAL ;
  PORT
   LAYER M4 ;
   RECT 0.000000 43.824000 0.084000 43.848000 ;
  END
 END k_lo_d[208]
 PIN k_lo_d[209]
  DIRECTION INPUT ;
  USE SIGNAL ;
  PORT
   LAYER M4 ;
   RECT 0.000000 44.016000 0.084000 44.040000 ;
  END
 END k_lo_d[209]
 PIN k_lo_d[210]
  DIRECTION INPUT ;
  USE SIGNAL ;
  PORT
   LAYER M4 ;
   RECT 0.000000 44.160000 0.084000 44.184000 ;
  END
 END k_lo_d[210]
 PIN k_lo_d[211]
  DIRECTION INPUT ;
  USE SIGNAL ;
  PORT
   LAYER M4 ;
   RECT 0.000000 44.352000 0.084000 44.376000 ;
  END
 END k_lo_d[211]
 PIN k_lo_d[212]
  DIRECTION INPUT ;
  USE SIGNAL ;
  PORT
   LAYER M4 ;
   RECT 0.000000 44.544000 0.084000 44.568000 ;
  END
 END k_lo_d[212]
 PIN k_lo_d[213]
  DIRECTION INPUT ;
  USE SIGNAL ;
  PORT
   LAYER M4 ;
   RECT 0.000000 44.736000 0.084000 44.760000 ;
  END
 END k_lo_d[213]
 PIN k_lo_d[214]
  DIRECTION INPUT ;
  USE SIGNAL ;
  PORT
   LAYER M4 ;
   RECT 0.000000 44.880000 0.084000 44.904000 ;
  END
 END k_lo_d[214]
 PIN k_lo_d[215]
  DIRECTION INPUT ;
  USE SIGNAL ;
  PORT
   LAYER M4 ;
   RECT 0.000000 45.072000 0.084000 45.096000 ;
  END
 END k_lo_d[215]
 PIN k_lo_d[216]
  DIRECTION INPUT ;
  USE SIGNAL ;
  PORT
   LAYER M4 ;
   RECT 0.000000 45.264000 0.084000 45.288000 ;
  END
 END k_lo_d[216]
 PIN k_lo_d[217]
  DIRECTION INPUT ;
  USE SIGNAL ;
  PORT
   LAYER M4 ;
   RECT 0.000000 45.456000 0.084000 45.480000 ;
  END
 END k_lo_d[217]
 PIN k_lo_d[218]
  DIRECTION INPUT ;
  USE SIGNAL ;
  PORT
   LAYER M4 ;
   RECT 0.000000 45.600000 0.084000 45.624000 ;
  END
 END k_lo_d[218]
 PIN k_lo_d[219]
  DIRECTION INPUT ;
  USE SIGNAL ;
  PORT
   LAYER M4 ;
   RECT 0.000000 45.792000 0.084000 45.816000 ;
  END
 END k_lo_d[219]
 PIN k_lo_d[220]
  DIRECTION INPUT ;
  USE SIGNAL ;
  PORT
   LAYER M4 ;
   RECT 0.000000 45.984000 0.084000 46.008000 ;
  END
 END k_lo_d[220]
 PIN k_lo_d[221]
  DIRECTION INPUT ;
  USE SIGNAL ;
  PORT
   LAYER M4 ;
   RECT 0.000000 46.176000 0.084000 46.200000 ;
  END
 END k_lo_d[221]
 PIN k_lo_d[222]
  DIRECTION INPUT ;
  USE SIGNAL ;
  PORT
   LAYER M4 ;
   RECT 0.000000 46.320000 0.084000 46.344000 ;
  END
 END k_lo_d[222]
 PIN k_lo_d[223]
  DIRECTION INPUT ;
  USE SIGNAL ;
  PORT
   LAYER M4 ;
   RECT 0.000000 46.512000 0.084000 46.536000 ;
  END
 END k_lo_d[223]
 PIN k_lo_d[224]
  DIRECTION INPUT ;
  USE SIGNAL ;
  PORT
   LAYER M4 ;
   RECT 0.000000 46.704000 0.084000 46.728000 ;
  END
 END k_lo_d[224]
 PIN k_lo_d[225]
  DIRECTION INPUT ;
  USE SIGNAL ;
  PORT
   LAYER M4 ;
   RECT 0.000000 46.896000 0.084000 46.920000 ;
  END
 END k_lo_d[225]
 PIN k_lo_d[226]
  DIRECTION INPUT ;
  USE SIGNAL ;
  PORT
   LAYER M4 ;
   RECT 0.000000 47.040000 0.084000 47.064000 ;
  END
 END k_lo_d[226]
 PIN k_lo_d[227]
  DIRECTION INPUT ;
  USE SIGNAL ;
  PORT
   LAYER M4 ;
   RECT 0.000000 47.232000 0.084000 47.256000 ;
  END
 END k_lo_d[227]
 PIN k_lo_d[228]
  DIRECTION INPUT ;
  USE SIGNAL ;
  PORT
   LAYER M4 ;
   RECT 0.000000 47.424000 0.084000 47.448000 ;
  END
 END k_lo_d[228]
 PIN k_lo_d[229]
  DIRECTION INPUT ;
  USE SIGNAL ;
  PORT
   LAYER M4 ;
   RECT 0.000000 47.616000 0.084000 47.640000 ;
  END
 END k_lo_d[229]
 PIN k_lo_d[230]
  DIRECTION INPUT ;
  USE SIGNAL ;
  PORT
   LAYER M4 ;
   RECT 0.000000 47.760000 0.084000 47.784000 ;
  END
 END k_lo_d[230]
 PIN k_lo_d[231]
  DIRECTION INPUT ;
  USE SIGNAL ;
  PORT
   LAYER M4 ;
   RECT 0.000000 47.952000 0.084000 47.976000 ;
  END
 END k_lo_d[231]
 PIN k_lo_d[232]
  DIRECTION INPUT ;
  USE SIGNAL ;
  PORT
   LAYER M4 ;
   RECT 0.000000 48.144000 0.084000 48.168000 ;
  END
 END k_lo_d[232]
 PIN k_lo_d[233]
  DIRECTION INPUT ;
  USE SIGNAL ;
  PORT
   LAYER M4 ;
   RECT 0.000000 48.336000 0.084000 48.360000 ;
  END
 END k_lo_d[233]
 PIN k_lo_d[234]
  DIRECTION INPUT ;
  USE SIGNAL ;
  PORT
   LAYER M4 ;
   RECT 0.000000 48.480000 0.084000 48.504000 ;
  END
 END k_lo_d[234]
 PIN k_lo_d[235]
  DIRECTION INPUT ;
  USE SIGNAL ;
  PORT
   LAYER M4 ;
   RECT 0.000000 48.672000 0.084000 48.696000 ;
  END
 END k_lo_d[235]
 PIN k_lo_d[236]
  DIRECTION INPUT ;
  USE SIGNAL ;
  PORT
   LAYER M4 ;
   RECT 0.000000 48.864000 0.084000 48.888000 ;
  END
 END k_lo_d[236]
 PIN k_lo_d[237]
  DIRECTION INPUT ;
  USE SIGNAL ;
  PORT
   LAYER M4 ;
   RECT 0.000000 49.056000 0.084000 49.080000 ;
  END
 END k_lo_d[237]
 PIN k_lo_d[238]
  DIRECTION INPUT ;
  USE SIGNAL ;
  PORT
   LAYER M4 ;
   RECT 0.000000 49.200000 0.084000 49.224000 ;
  END
 END k_lo_d[238]
 PIN k_lo_d[239]
  DIRECTION INPUT ;
  USE SIGNAL ;
  PORT
   LAYER M4 ;
   RECT 0.000000 49.392000 0.084000 49.416000 ;
  END
 END k_lo_d[239]
 PIN k_lo_d[240]
  DIRECTION INPUT ;
  USE SIGNAL ;
  PORT
   LAYER M4 ;
   RECT 0.000000 49.584000 0.084000 49.608000 ;
  END
 END k_lo_d[240]
 PIN k_lo_d[241]
  DIRECTION INPUT ;
  USE SIGNAL ;
  PORT
   LAYER M4 ;
   RECT 0.000000 49.776000 0.084000 49.800000 ;
  END
 END k_lo_d[241]
 PIN k_lo_d[242]
  DIRECTION INPUT ;
  USE SIGNAL ;
  PORT
   LAYER M4 ;
   RECT 0.000000 49.920000 0.084000 49.944000 ;
  END
 END k_lo_d[242]
 PIN k_lo_d[243]
  DIRECTION INPUT ;
  USE SIGNAL ;
  PORT
   LAYER M4 ;
   RECT 0.000000 50.112000 0.084000 50.136000 ;
  END
 END k_lo_d[243]
 PIN k_lo_d[244]
  DIRECTION INPUT ;
  USE SIGNAL ;
  PORT
   LAYER M4 ;
   RECT 0.000000 50.304000 0.084000 50.328000 ;
  END
 END k_lo_d[244]
 PIN k_lo_d[245]
  DIRECTION INPUT ;
  USE SIGNAL ;
  PORT
   LAYER M4 ;
   RECT 0.000000 50.496000 0.084000 50.520000 ;
  END
 END k_lo_d[245]
 PIN k_lo_d[246]
  DIRECTION INPUT ;
  USE SIGNAL ;
  PORT
   LAYER M4 ;
   RECT 0.000000 50.640000 0.084000 50.664000 ;
  END
 END k_lo_d[246]
 PIN k_lo_d[247]
  DIRECTION INPUT ;
  USE SIGNAL ;
  PORT
   LAYER M4 ;
   RECT 0.000000 50.832000 0.084000 50.856000 ;
  END
 END k_lo_d[247]
 PIN k_lo_d[248]
  DIRECTION INPUT ;
  USE SIGNAL ;
  PORT
   LAYER M4 ;
   RECT 0.000000 51.024000 0.084000 51.048000 ;
  END
 END k_lo_d[248]
 PIN k_lo_d[249]
  DIRECTION INPUT ;
  USE SIGNAL ;
  PORT
   LAYER M4 ;
   RECT 0.000000 51.216000 0.084000 51.240000 ;
  END
 END k_lo_d[249]
 PIN k_lo_d[250]
  DIRECTION INPUT ;
  USE SIGNAL ;
  PORT
   LAYER M4 ;
   RECT 0.000000 51.360000 0.084000 51.384000 ;
  END
 END k_lo_d[250]
 PIN k_lo_d[251]
  DIRECTION INPUT ;
  USE SIGNAL ;
  PORT
   LAYER M4 ;
   RECT 0.000000 51.552000 0.084000 51.576000 ;
  END
 END k_lo_d[251]
 PIN k_lo_d[252]
  DIRECTION INPUT ;
  USE SIGNAL ;
  PORT
   LAYER M4 ;
   RECT 0.000000 51.744000 0.084000 51.768000 ;
  END
 END k_lo_d[252]
 PIN k_lo_d[253]
  DIRECTION INPUT ;
  USE SIGNAL ;
  PORT
   LAYER M4 ;
   RECT 0.000000 51.936000 0.084000 51.960000 ;
  END
 END k_lo_d[253]
 PIN k_lo_d[254]
  DIRECTION INPUT ;
  USE SIGNAL ;
  PORT
   LAYER M4 ;
   RECT 0.000000 52.080000 0.084000 52.104000 ;
  END
 END k_lo_d[254]
 PIN k_lo_d[255]
  DIRECTION INPUT ;
  USE SIGNAL ;
  PORT
   LAYER M4 ;
   RECT 0.000000 52.272000 0.084000 52.296000 ;
  END
 END k_lo_d[255]
 PIN k_lo_d[256]
  DIRECTION INPUT ;
  USE SIGNAL ;
  PORT
   LAYER M4 ;
   RECT 0.000000 52.464000 0.084000 52.488000 ;
  END
 END k_lo_d[256]
 PIN k_lo_d[257]
  DIRECTION INPUT ;
  USE SIGNAL ;
  PORT
   LAYER M4 ;
   RECT 0.000000 52.656000 0.084000 52.680000 ;
  END
 END k_lo_d[257]
 PIN k_lo_d[258]
  DIRECTION INPUT ;
  USE SIGNAL ;
  PORT
   LAYER M4 ;
   RECT 0.000000 52.800000 0.084000 52.824000 ;
  END
 END k_lo_d[258]
 PIN k_lo_d[259]
  DIRECTION INPUT ;
  USE SIGNAL ;
  PORT
   LAYER M4 ;
   RECT 0.000000 52.992000 0.084000 53.016000 ;
  END
 END k_lo_d[259]
 PIN k_lo_d[260]
  DIRECTION INPUT ;
  USE SIGNAL ;
  PORT
   LAYER M4 ;
   RECT 0.000000 53.184000 0.084000 53.208000 ;
  END
 END k_lo_d[260]
 PIN k_lo_d[261]
  DIRECTION INPUT ;
  USE SIGNAL ;
  PORT
   LAYER M4 ;
   RECT 0.000000 53.376000 0.084000 53.400000 ;
  END
 END k_lo_d[261]
 PIN k_lo_d[262]
  DIRECTION INPUT ;
  USE SIGNAL ;
  PORT
   LAYER M4 ;
   RECT 0.000000 53.520000 0.084000 53.544000 ;
  END
 END k_lo_d[262]
 PIN k_lo_d[263]
  DIRECTION INPUT ;
  USE SIGNAL ;
  PORT
   LAYER M4 ;
   RECT 0.000000 53.712000 0.084000 53.736000 ;
  END
 END k_lo_d[263]
 PIN k_lo_d[264]
  DIRECTION INPUT ;
  USE SIGNAL ;
  PORT
   LAYER M4 ;
   RECT 0.000000 53.904000 0.084000 53.928000 ;
  END
 END k_lo_d[264]
 PIN k_lo_d[265]
  DIRECTION INPUT ;
  USE SIGNAL ;
  PORT
   LAYER M4 ;
   RECT 0.000000 54.096000 0.084000 54.120000 ;
  END
 END k_lo_d[265]
 PIN k_lo_d[266]
  DIRECTION INPUT ;
  USE SIGNAL ;
  PORT
   LAYER M4 ;
   RECT 0.000000 54.240000 0.084000 54.264000 ;
  END
 END k_lo_d[266]
 PIN k_lo_d[267]
  DIRECTION INPUT ;
  USE SIGNAL ;
  PORT
   LAYER M4 ;
   RECT 0.000000 54.432000 0.084000 54.456000 ;
  END
 END k_lo_d[267]
 PIN k_lo_d[268]
  DIRECTION INPUT ;
  USE SIGNAL ;
  PORT
   LAYER M4 ;
   RECT 0.000000 54.624000 0.084000 54.648000 ;
  END
 END k_lo_d[268]
 PIN k_lo_d[269]
  DIRECTION INPUT ;
  USE SIGNAL ;
  PORT
   LAYER M4 ;
   RECT 0.000000 54.816000 0.084000 54.840000 ;
  END
 END k_lo_d[269]
 PIN k_lo_d[270]
  DIRECTION INPUT ;
  USE SIGNAL ;
  PORT
   LAYER M4 ;
   RECT 0.000000 54.960000 0.084000 54.984000 ;
  END
 END k_lo_d[270]
 PIN k_lo_d[271]
  DIRECTION INPUT ;
  USE SIGNAL ;
  PORT
   LAYER M4 ;
   RECT 0.000000 55.152000 0.084000 55.176000 ;
  END
 END k_lo_d[271]
 PIN k_lo_d[272]
  DIRECTION INPUT ;
  USE SIGNAL ;
  PORT
   LAYER M4 ;
   RECT 0.000000 55.344000 0.084000 55.368000 ;
  END
 END k_lo_d[272]
 PIN k_lo_d[273]
  DIRECTION INPUT ;
  USE SIGNAL ;
  PORT
   LAYER M4 ;
   RECT 0.000000 55.536000 0.084000 55.560000 ;
  END
 END k_lo_d[273]
 PIN k_lo_d[274]
  DIRECTION INPUT ;
  USE SIGNAL ;
  PORT
   LAYER M4 ;
   RECT 0.000000 55.680000 0.084000 55.704000 ;
  END
 END k_lo_d[274]
 PIN k_lo_d[275]
  DIRECTION INPUT ;
  USE SIGNAL ;
  PORT
   LAYER M4 ;
   RECT 0.000000 55.872000 0.084000 55.896000 ;
  END
 END k_lo_d[275]
 PIN k_lo_d[276]
  DIRECTION INPUT ;
  USE SIGNAL ;
  PORT
   LAYER M4 ;
   RECT 0.000000 56.064000 0.084000 56.088000 ;
  END
 END k_lo_d[276]
 PIN k_lo_d[277]
  DIRECTION INPUT ;
  USE SIGNAL ;
  PORT
   LAYER M4 ;
   RECT 0.000000 56.256000 0.084000 56.280000 ;
  END
 END k_lo_d[277]
 PIN k_lo_d[278]
  DIRECTION INPUT ;
  USE SIGNAL ;
  PORT
   LAYER M4 ;
   RECT 0.000000 56.400000 0.084000 56.424000 ;
  END
 END k_lo_d[278]
 PIN k_lo_d[279]
  DIRECTION INPUT ;
  USE SIGNAL ;
  PORT
   LAYER M4 ;
   RECT 0.000000 56.592000 0.084000 56.616000 ;
  END
 END k_lo_d[279]
 PIN k_lo_d[280]
  DIRECTION INPUT ;
  USE SIGNAL ;
  PORT
   LAYER M4 ;
   RECT 0.000000 56.784000 0.084000 56.808000 ;
  END
 END k_lo_d[280]
 PIN k_lo_d[281]
  DIRECTION INPUT ;
  USE SIGNAL ;
  PORT
   LAYER M4 ;
   RECT 0.000000 56.976000 0.084000 57.000000 ;
  END
 END k_lo_d[281]
 PIN k_lo_d[282]
  DIRECTION INPUT ;
  USE SIGNAL ;
  PORT
   LAYER M4 ;
   RECT 0.000000 57.120000 0.084000 57.144000 ;
  END
 END k_lo_d[282]
 PIN k_lo_d[283]
  DIRECTION INPUT ;
  USE SIGNAL ;
  PORT
   LAYER M4 ;
   RECT 0.000000 57.312000 0.084000 57.336000 ;
  END
 END k_lo_d[283]
 PIN k_lo_d[284]
  DIRECTION INPUT ;
  USE SIGNAL ;
  PORT
   LAYER M4 ;
   RECT 0.000000 57.504000 0.084000 57.528000 ;
  END
 END k_lo_d[284]
 PIN k_lo_d[285]
  DIRECTION INPUT ;
  USE SIGNAL ;
  PORT
   LAYER M4 ;
   RECT 0.000000 57.696000 0.084000 57.720000 ;
  END
 END k_lo_d[285]
 PIN k_lo_d[286]
  DIRECTION INPUT ;
  USE SIGNAL ;
  PORT
   LAYER M4 ;
   RECT 0.000000 57.840000 0.084000 57.864000 ;
  END
 END k_lo_d[286]
 PIN k_lo_d[287]
  DIRECTION INPUT ;
  USE SIGNAL ;
  PORT
   LAYER M4 ;
   RECT 0.000000 58.032000 0.084000 58.056000 ;
  END
 END k_lo_d[287]
 PIN k_lo_d[288]
  DIRECTION INPUT ;
  USE SIGNAL ;
  PORT
   LAYER M4 ;
   RECT 0.000000 58.224000 0.084000 58.248000 ;
  END
 END k_lo_d[288]
 PIN k_lo_d[289]
  DIRECTION INPUT ;
  USE SIGNAL ;
  PORT
   LAYER M4 ;
   RECT 0.000000 58.416000 0.084000 58.440000 ;
  END
 END k_lo_d[289]
 PIN k_lo_d[290]
  DIRECTION INPUT ;
  USE SIGNAL ;
  PORT
   LAYER M4 ;
   RECT 0.000000 58.560000 0.084000 58.584000 ;
  END
 END k_lo_d[290]
 PIN k_lo_d[291]
  DIRECTION INPUT ;
  USE SIGNAL ;
  PORT
   LAYER M4 ;
   RECT 0.000000 58.752000 0.084000 58.776000 ;
  END
 END k_lo_d[291]
 PIN k_lo_d[292]
  DIRECTION INPUT ;
  USE SIGNAL ;
  PORT
   LAYER M4 ;
   RECT 0.000000 58.944000 0.084000 58.968000 ;
  END
 END k_lo_d[292]
 PIN k_lo_d[293]
  DIRECTION INPUT ;
  USE SIGNAL ;
  PORT
   LAYER M4 ;
   RECT 0.000000 59.136000 0.084000 59.160000 ;
  END
 END k_lo_d[293]
 PIN k_lo_d[294]
  DIRECTION INPUT ;
  USE SIGNAL ;
  PORT
   LAYER M4 ;
   RECT 0.000000 59.280000 0.084000 59.304000 ;
  END
 END k_lo_d[294]
 PIN k_lo_d[295]
  DIRECTION INPUT ;
  USE SIGNAL ;
  PORT
   LAYER M4 ;
   RECT 0.000000 59.472000 0.084000 59.496000 ;
  END
 END k_lo_d[295]
 PIN k_lo_d[296]
  DIRECTION INPUT ;
  USE SIGNAL ;
  PORT
   LAYER M4 ;
   RECT 0.000000 59.664000 0.084000 59.688000 ;
  END
 END k_lo_d[296]
 PIN k_lo_d[297]
  DIRECTION INPUT ;
  USE SIGNAL ;
  PORT
   LAYER M4 ;
   RECT 0.000000 59.856000 0.084000 59.880000 ;
  END
 END k_lo_d[297]
 PIN k_lo_d[298]
  DIRECTION INPUT ;
  USE SIGNAL ;
  PORT
   LAYER M4 ;
   RECT 0.000000 60.000000 0.084000 60.024000 ;
  END
 END k_lo_d[298]
 PIN k_lo_d[299]
  DIRECTION INPUT ;
  USE SIGNAL ;
  PORT
   LAYER M4 ;
   RECT 0.000000 60.192000 0.084000 60.216000 ;
  END
 END k_lo_d[299]
 PIN k_lo_d[300]
  DIRECTION INPUT ;
  USE SIGNAL ;
  PORT
   LAYER M4 ;
   RECT 0.000000 60.384000 0.084000 60.408000 ;
  END
 END k_lo_d[300]
 PIN k_lo_d[301]
  DIRECTION INPUT ;
  USE SIGNAL ;
  PORT
   LAYER M4 ;
   RECT 0.000000 60.576000 0.084000 60.600000 ;
  END
 END k_lo_d[301]
 PIN k_lo_d[302]
  DIRECTION INPUT ;
  USE SIGNAL ;
  PORT
   LAYER M4 ;
   RECT 0.000000 60.720000 0.084000 60.744000 ;
  END
 END k_lo_d[302]
 PIN k_lo_d[303]
  DIRECTION INPUT ;
  USE SIGNAL ;
  PORT
   LAYER M4 ;
   RECT 0.000000 60.912000 0.084000 60.936000 ;
  END
 END k_lo_d[303]
 PIN k_lo_d[304]
  DIRECTION INPUT ;
  USE SIGNAL ;
  PORT
   LAYER M4 ;
   RECT 0.000000 61.104000 0.084000 61.128000 ;
  END
 END k_lo_d[304]
 PIN k_lo_d[305]
  DIRECTION INPUT ;
  USE SIGNAL ;
  PORT
   LAYER M4 ;
   RECT 0.000000 61.296000 0.084000 61.320000 ;
  END
 END k_lo_d[305]
 PIN k_lo_d[306]
  DIRECTION INPUT ;
  USE SIGNAL ;
  PORT
   LAYER M4 ;
   RECT 0.000000 61.440000 0.084000 61.464000 ;
  END
 END k_lo_d[306]
 PIN k_lo_d[307]
  DIRECTION INPUT ;
  USE SIGNAL ;
  PORT
   LAYER M4 ;
   RECT 0.000000 61.632000 0.084000 61.656000 ;
  END
 END k_lo_d[307]
 PIN k_lo_d[308]
  DIRECTION INPUT ;
  USE SIGNAL ;
  PORT
   LAYER M4 ;
   RECT 0.000000 61.824000 0.084000 61.848000 ;
  END
 END k_lo_d[308]
 PIN k_lo_d[309]
  DIRECTION INPUT ;
  USE SIGNAL ;
  PORT
   LAYER M4 ;
   RECT 0.000000 62.016000 0.084000 62.040000 ;
  END
 END k_lo_d[309]
 PIN k_lo_d[310]
  DIRECTION INPUT ;
  USE SIGNAL ;
  PORT
   LAYER M4 ;
   RECT 0.000000 62.160000 0.084000 62.184000 ;
  END
 END k_lo_d[310]
 PIN k_lo_d[311]
  DIRECTION INPUT ;
  USE SIGNAL ;
  PORT
   LAYER M4 ;
   RECT 0.000000 62.352000 0.084000 62.376000 ;
  END
 END k_lo_d[311]
 PIN k_lo_d[312]
  DIRECTION INPUT ;
  USE SIGNAL ;
  PORT
   LAYER M4 ;
   RECT 0.000000 62.544000 0.084000 62.568000 ;
  END
 END k_lo_d[312]
 PIN k_lo_d[313]
  DIRECTION INPUT ;
  USE SIGNAL ;
  PORT
   LAYER M4 ;
   RECT 0.000000 62.736000 0.084000 62.760000 ;
  END
 END k_lo_d[313]
 PIN k_lo_d[314]
  DIRECTION INPUT ;
  USE SIGNAL ;
  PORT
   LAYER M4 ;
   RECT 0.000000 62.880000 0.084000 62.904000 ;
  END
 END k_lo_d[314]
 PIN k_lo_d[315]
  DIRECTION INPUT ;
  USE SIGNAL ;
  PORT
   LAYER M4 ;
   RECT 0.000000 63.072000 0.084000 63.096000 ;
  END
 END k_lo_d[315]
 PIN k_lo_d[316]
  DIRECTION INPUT ;
  USE SIGNAL ;
  PORT
   LAYER M4 ;
   RECT 0.000000 63.264000 0.084000 63.288000 ;
  END
 END k_lo_d[316]
 PIN k_lo_d[317]
  DIRECTION INPUT ;
  USE SIGNAL ;
  PORT
   LAYER M4 ;
   RECT 0.000000 63.456000 0.084000 63.480000 ;
  END
 END k_lo_d[317]
 PIN k_lo_d[318]
  DIRECTION INPUT ;
  USE SIGNAL ;
  PORT
   LAYER M4 ;
   RECT 0.000000 63.600000 0.084000 63.624000 ;
  END
 END k_lo_d[318]
 PIN k_lo_d[319]
  DIRECTION INPUT ;
  USE SIGNAL ;
  PORT
   LAYER M4 ;
   RECT 0.000000 63.792000 0.084000 63.816000 ;
  END
 END k_lo_d[319]
 PIN k_lo_d[320]
  DIRECTION INPUT ;
  USE SIGNAL ;
  PORT
   LAYER M4 ;
   RECT 0.000000 63.984000 0.084000 64.008000 ;
  END
 END k_lo_d[320]
 PIN k_lo_d[321]
  DIRECTION INPUT ;
  USE SIGNAL ;
  PORT
   LAYER M4 ;
   RECT 0.000000 64.176000 0.084000 64.200000 ;
  END
 END k_lo_d[321]
 PIN k_lo_d[322]
  DIRECTION INPUT ;
  USE SIGNAL ;
  PORT
   LAYER M4 ;
   RECT 0.000000 64.320000 0.084000 64.344000 ;
  END
 END k_lo_d[322]
 PIN k_lo_d[323]
  DIRECTION INPUT ;
  USE SIGNAL ;
  PORT
   LAYER M4 ;
   RECT 0.000000 64.512000 0.084000 64.536000 ;
  END
 END k_lo_d[323]
 PIN k_lo_d[324]
  DIRECTION INPUT ;
  USE SIGNAL ;
  PORT
   LAYER M4 ;
   RECT 0.000000 64.704000 0.084000 64.728000 ;
  END
 END k_lo_d[324]
 PIN k_lo_d[325]
  DIRECTION INPUT ;
  USE SIGNAL ;
  PORT
   LAYER M4 ;
   RECT 0.000000 64.896000 0.084000 64.920000 ;
  END
 END k_lo_d[325]
 PIN k_lo_d[326]
  DIRECTION INPUT ;
  USE SIGNAL ;
  PORT
   LAYER M4 ;
   RECT 0.000000 65.040000 0.084000 65.064000 ;
  END
 END k_lo_d[326]
 PIN k_lo_d[327]
  DIRECTION INPUT ;
  USE SIGNAL ;
  PORT
   LAYER M4 ;
   RECT 0.000000 65.232000 0.084000 65.256000 ;
  END
 END k_lo_d[327]
 PIN k_lo_d[328]
  DIRECTION INPUT ;
  USE SIGNAL ;
  PORT
   LAYER M4 ;
   RECT 0.000000 65.424000 0.084000 65.448000 ;
  END
 END k_lo_d[328]
 PIN k_lo_d[329]
  DIRECTION INPUT ;
  USE SIGNAL ;
  PORT
   LAYER M4 ;
   RECT 0.000000 65.616000 0.084000 65.640000 ;
  END
 END k_lo_d[329]
 PIN k_lo_d[330]
  DIRECTION INPUT ;
  USE SIGNAL ;
  PORT
   LAYER M4 ;
   RECT 0.000000 65.760000 0.084000 65.784000 ;
  END
 END k_lo_d[330]
 PIN k_lo_d[331]
  DIRECTION INPUT ;
  USE SIGNAL ;
  PORT
   LAYER M4 ;
   RECT 0.000000 65.952000 0.084000 65.976000 ;
  END
 END k_lo_d[331]
 PIN k_lo_d[332]
  DIRECTION INPUT ;
  USE SIGNAL ;
  PORT
   LAYER M4 ;
   RECT 0.000000 66.144000 0.084000 66.168000 ;
  END
 END k_lo_d[332]
 PIN k_lo_d[333]
  DIRECTION INPUT ;
  USE SIGNAL ;
  PORT
   LAYER M4 ;
   RECT 0.000000 66.336000 0.084000 66.360000 ;
  END
 END k_lo_d[333]
 PIN k_lo_d[334]
  DIRECTION INPUT ;
  USE SIGNAL ;
  PORT
   LAYER M4 ;
   RECT 0.000000 66.480000 0.084000 66.504000 ;
  END
 END k_lo_d[334]
 PIN k_lo_d[335]
  DIRECTION INPUT ;
  USE SIGNAL ;
  PORT
   LAYER M4 ;
   RECT 0.000000 66.672000 0.084000 66.696000 ;
  END
 END k_lo_d[335]
 PIN k_lo_d[336]
  DIRECTION INPUT ;
  USE SIGNAL ;
  PORT
   LAYER M4 ;
   RECT 0.000000 66.864000 0.084000 66.888000 ;
  END
 END k_lo_d[336]
 PIN k_lo_d[337]
  DIRECTION INPUT ;
  USE SIGNAL ;
  PORT
   LAYER M4 ;
   RECT 0.000000 67.056000 0.084000 67.080000 ;
  END
 END k_lo_d[337]
 PIN k_lo_d[338]
  DIRECTION INPUT ;
  USE SIGNAL ;
  PORT
   LAYER M4 ;
   RECT 0.000000 67.200000 0.084000 67.224000 ;
  END
 END k_lo_d[338]
 PIN k_lo_d[339]
  DIRECTION INPUT ;
  USE SIGNAL ;
  PORT
   LAYER M4 ;
   RECT 0.000000 67.392000 0.084000 67.416000 ;
  END
 END k_lo_d[339]
 PIN k_lo_d[340]
  DIRECTION INPUT ;
  USE SIGNAL ;
  PORT
   LAYER M4 ;
   RECT 0.000000 67.584000 0.084000 67.608000 ;
  END
 END k_lo_d[340]
 PIN k_lo_d[341]
  DIRECTION INPUT ;
  USE SIGNAL ;
  PORT
   LAYER M4 ;
   RECT 0.000000 67.776000 0.084000 67.800000 ;
  END
 END k_lo_d[341]
 PIN k_lo_d[342]
  DIRECTION INPUT ;
  USE SIGNAL ;
  PORT
   LAYER M4 ;
   RECT 0.000000 67.920000 0.084000 67.944000 ;
  END
 END k_lo_d[342]
 PIN k_lo_d[343]
  DIRECTION INPUT ;
  USE SIGNAL ;
  PORT
   LAYER M4 ;
   RECT 0.000000 68.112000 0.084000 68.136000 ;
  END
 END k_lo_d[343]
 PIN k_lo_d[344]
  DIRECTION INPUT ;
  USE SIGNAL ;
  PORT
   LAYER M4 ;
   RECT 0.000000 68.304000 0.084000 68.328000 ;
  END
 END k_lo_d[344]
 PIN k_lo_d[345]
  DIRECTION INPUT ;
  USE SIGNAL ;
  PORT
   LAYER M4 ;
   RECT 0.000000 68.496000 0.084000 68.520000 ;
  END
 END k_lo_d[345]
 PIN k_lo_d[346]
  DIRECTION INPUT ;
  USE SIGNAL ;
  PORT
   LAYER M4 ;
   RECT 0.000000 68.640000 0.084000 68.664000 ;
  END
 END k_lo_d[346]
 PIN k_lo_d[347]
  DIRECTION INPUT ;
  USE SIGNAL ;
  PORT
   LAYER M4 ;
   RECT 0.000000 68.832000 0.084000 68.856000 ;
  END
 END k_lo_d[347]
 PIN k_lo_d[348]
  DIRECTION INPUT ;
  USE SIGNAL ;
  PORT
   LAYER M4 ;
   RECT 0.000000 69.024000 0.084000 69.048000 ;
  END
 END k_lo_d[348]
 PIN k_lo_d[349]
  DIRECTION INPUT ;
  USE SIGNAL ;
  PORT
   LAYER M4 ;
   RECT 0.000000 69.168000 0.084000 69.192000 ;
  END
 END k_lo_d[349]
 PIN k_lo_d[350]
  DIRECTION INPUT ;
  USE SIGNAL ;
  PORT
   LAYER M4 ;
   RECT 0.000000 69.360000 0.084000 69.384000 ;
  END
 END k_lo_d[350]
 PIN k_lo_d[351]
  DIRECTION INPUT ;
  USE SIGNAL ;
  PORT
   LAYER M4 ;
   RECT 0.000000 69.552000 0.084000 69.576000 ;
  END
 END k_lo_d[351]
 PIN k_lo_d[352]
  DIRECTION INPUT ;
  USE SIGNAL ;
  PORT
   LAYER M4 ;
   RECT 0.000000 69.744000 0.084000 69.768000 ;
  END
 END k_lo_d[352]
 PIN k_lo_d[353]
  DIRECTION INPUT ;
  USE SIGNAL ;
  PORT
   LAYER M4 ;
   RECT 0.000000 69.888000 0.084000 69.912000 ;
  END
 END k_lo_d[353]
 PIN k_lo_d[354]
  DIRECTION INPUT ;
  USE SIGNAL ;
  PORT
   LAYER M4 ;
   RECT 0.000000 70.080000 0.084000 70.104000 ;
  END
 END k_lo_d[354]
 PIN k_lo_d[355]
  DIRECTION INPUT ;
  USE SIGNAL ;
  PORT
   LAYER M4 ;
   RECT 0.000000 70.272000 0.084000 70.296000 ;
  END
 END k_lo_d[355]
 PIN k_lo_d[356]
  DIRECTION INPUT ;
  USE SIGNAL ;
  PORT
   LAYER M4 ;
   RECT 0.000000 70.464000 0.084000 70.488000 ;
  END
 END k_lo_d[356]
 PIN k_lo_d[357]
  DIRECTION INPUT ;
  USE SIGNAL ;
  PORT
   LAYER M4 ;
   RECT 0.000000 70.608000 0.084000 70.632000 ;
  END
 END k_lo_d[357]
 PIN k_lo_d[358]
  DIRECTION INPUT ;
  USE SIGNAL ;
  PORT
   LAYER M4 ;
   RECT 0.000000 70.800000 0.084000 70.824000 ;
  END
 END k_lo_d[358]
 PIN k_lo_d[359]
  DIRECTION INPUT ;
  USE SIGNAL ;
  PORT
   LAYER M4 ;
   RECT 0.000000 70.992000 0.084000 71.016000 ;
  END
 END k_lo_d[359]
 PIN k_lo_d[360]
  DIRECTION INPUT ;
  USE SIGNAL ;
  PORT
   LAYER M4 ;
   RECT 0.000000 71.184000 0.084000 71.208000 ;
  END
 END k_lo_d[360]
 PIN k_lo_d[361]
  DIRECTION INPUT ;
  USE SIGNAL ;
  PORT
   LAYER M4 ;
   RECT 0.000000 71.328000 0.084000 71.352000 ;
  END
 END k_lo_d[361]
 PIN k_lo_d[362]
  DIRECTION INPUT ;
  USE SIGNAL ;
  PORT
   LAYER M4 ;
   RECT 0.000000 71.520000 0.084000 71.544000 ;
  END
 END k_lo_d[362]
 PIN k_lo_d[363]
  DIRECTION INPUT ;
  USE SIGNAL ;
  PORT
   LAYER M4 ;
   RECT 0.000000 71.712000 0.084000 71.736000 ;
  END
 END k_lo_d[363]
 PIN k_lo_d[364]
  DIRECTION INPUT ;
  USE SIGNAL ;
  PORT
   LAYER M4 ;
   RECT 0.000000 71.904000 0.084000 71.928000 ;
  END
 END k_lo_d[364]
 PIN k_lo_d[365]
  DIRECTION INPUT ;
  USE SIGNAL ;
  PORT
   LAYER M4 ;
   RECT 0.000000 72.048000 0.084000 72.072000 ;
  END
 END k_lo_d[365]
 PIN k_lo_d[366]
  DIRECTION INPUT ;
  USE SIGNAL ;
  PORT
   LAYER M4 ;
   RECT 0.000000 72.240000 0.084000 72.264000 ;
  END
 END k_lo_d[366]
 PIN k_lo_d[367]
  DIRECTION INPUT ;
  USE SIGNAL ;
  PORT
   LAYER M4 ;
   RECT 0.000000 72.432000 0.084000 72.456000 ;
  END
 END k_lo_d[367]
 PIN k_lo_d[368]
  DIRECTION INPUT ;
  USE SIGNAL ;
  PORT
   LAYER M4 ;
   RECT 0.000000 72.624000 0.084000 72.648000 ;
  END
 END k_lo_d[368]
 PIN k_lo_d[369]
  DIRECTION INPUT ;
  USE SIGNAL ;
  PORT
   LAYER M4 ;
   RECT 0.000000 72.768000 0.084000 72.792000 ;
  END
 END k_lo_d[369]
 PIN k_lo_d[370]
  DIRECTION INPUT ;
  USE SIGNAL ;
  PORT
   LAYER M4 ;
   RECT 0.000000 72.960000 0.084000 72.984000 ;
  END
 END k_lo_d[370]
 PIN k_lo_d[371]
  DIRECTION INPUT ;
  USE SIGNAL ;
  PORT
   LAYER M4 ;
   RECT 0.000000 73.152000 0.084000 73.176000 ;
  END
 END k_lo_d[371]
 PIN k_lo_d[372]
  DIRECTION INPUT ;
  USE SIGNAL ;
  PORT
   LAYER M4 ;
   RECT 0.000000 73.344000 0.084000 73.368000 ;
  END
 END k_lo_d[372]
 PIN k_lo_d[373]
  DIRECTION INPUT ;
  USE SIGNAL ;
  PORT
   LAYER M4 ;
   RECT 0.000000 73.488000 0.084000 73.512000 ;
  END
 END k_lo_d[373]
 PIN k_lo_d[374]
  DIRECTION INPUT ;
  USE SIGNAL ;
  PORT
   LAYER M4 ;
   RECT 0.000000 73.680000 0.084000 73.704000 ;
  END
 END k_lo_d[374]
 PIN k_lo_d[375]
  DIRECTION INPUT ;
  USE SIGNAL ;
  PORT
   LAYER M4 ;
   RECT 0.000000 73.872000 0.084000 73.896000 ;
  END
 END k_lo_d[375]
 PIN k_lo_d[376]
  DIRECTION INPUT ;
  USE SIGNAL ;
  PORT
   LAYER M4 ;
   RECT 0.000000 74.064000 0.084000 74.088000 ;
  END
 END k_lo_d[376]
 PIN k_lo_d[377]
  DIRECTION INPUT ;
  USE SIGNAL ;
  PORT
   LAYER M4 ;
   RECT 0.000000 74.208000 0.084000 74.232000 ;
  END
 END k_lo_d[377]
 PIN k_lo_d[378]
  DIRECTION INPUT ;
  USE SIGNAL ;
  PORT
   LAYER M4 ;
   RECT 0.000000 74.400000 0.084000 74.424000 ;
  END
 END k_lo_d[378]
 PIN k_lo_d[379]
  DIRECTION INPUT ;
  USE SIGNAL ;
  PORT
   LAYER M4 ;
   RECT 0.000000 74.592000 0.084000 74.616000 ;
  END
 END k_lo_d[379]
 PIN k_lo_d[380]
  DIRECTION INPUT ;
  USE SIGNAL ;
  PORT
   LAYER M4 ;
   RECT 0.000000 74.784000 0.084000 74.808000 ;
  END
 END k_lo_d[380]
 PIN k_lo_d[381]
  DIRECTION INPUT ;
  USE SIGNAL ;
  PORT
   LAYER M4 ;
   RECT 0.000000 74.928000 0.084000 74.952000 ;
  END
 END k_lo_d[381]
 PIN k_lo_d[382]
  DIRECTION INPUT ;
  USE SIGNAL ;
  PORT
   LAYER M4 ;
   RECT 0.000000 75.120000 0.084000 75.144000 ;
  END
 END k_lo_d[382]
 PIN k_lo_d[383]
  DIRECTION INPUT ;
  USE SIGNAL ;
  PORT
   LAYER M4 ;
   RECT 0.000000 75.312000 0.084000 75.336000 ;
  END
 END k_lo_d[383]
 PIN k_lo_d[384]
  DIRECTION INPUT ;
  USE SIGNAL ;
  PORT
   LAYER M4 ;
   RECT 0.000000 75.504000 0.084000 75.528000 ;
  END
 END k_lo_d[384]
 PIN k_lo_d[385]
  DIRECTION INPUT ;
  USE SIGNAL ;
  PORT
   LAYER M4 ;
   RECT 0.000000 75.648000 0.084000 75.672000 ;
  END
 END k_lo_d[385]
 PIN k_lo_d[386]
  DIRECTION INPUT ;
  USE SIGNAL ;
  PORT
   LAYER M4 ;
   RECT 0.000000 75.840000 0.084000 75.864000 ;
  END
 END k_lo_d[386]
 PIN k_lo_d[387]
  DIRECTION INPUT ;
  USE SIGNAL ;
  PORT
   LAYER M4 ;
   RECT 0.000000 76.032000 0.084000 76.056000 ;
  END
 END k_lo_d[387]
 PIN k_lo_d[388]
  DIRECTION INPUT ;
  USE SIGNAL ;
  PORT
   LAYER M4 ;
   RECT 0.000000 76.224000 0.084000 76.248000 ;
  END
 END k_lo_d[388]
 PIN k_lo_d[389]
  DIRECTION INPUT ;
  USE SIGNAL ;
  PORT
   LAYER M4 ;
   RECT 0.000000 76.368000 0.084000 76.392000 ;
  END
 END k_lo_d[389]
 PIN k_lo_d[390]
  DIRECTION INPUT ;
  USE SIGNAL ;
  PORT
   LAYER M4 ;
   RECT 0.000000 76.560000 0.084000 76.584000 ;
  END
 END k_lo_d[390]
 PIN k_lo_d[391]
  DIRECTION INPUT ;
  USE SIGNAL ;
  PORT
   LAYER M4 ;
   RECT 0.000000 76.752000 0.084000 76.776000 ;
  END
 END k_lo_d[391]
 PIN k_lo_d[392]
  DIRECTION INPUT ;
  USE SIGNAL ;
  PORT
   LAYER M4 ;
   RECT 0.000000 76.944000 0.084000 76.968000 ;
  END
 END k_lo_d[392]
 PIN k_lo_d[393]
  DIRECTION INPUT ;
  USE SIGNAL ;
  PORT
   LAYER M4 ;
   RECT 0.000000 77.088000 0.084000 77.112000 ;
  END
 END k_lo_d[393]
 PIN k_lo_d[394]
  DIRECTION INPUT ;
  USE SIGNAL ;
  PORT
   LAYER M4 ;
   RECT 0.000000 77.280000 0.084000 77.304000 ;
  END
 END k_lo_d[394]
 PIN k_lo_d[395]
  DIRECTION INPUT ;
  USE SIGNAL ;
  PORT
   LAYER M4 ;
   RECT 0.000000 77.472000 0.084000 77.496000 ;
  END
 END k_lo_d[395]
 PIN k_lo_d[396]
  DIRECTION INPUT ;
  USE SIGNAL ;
  PORT
   LAYER M4 ;
   RECT 0.000000 77.664000 0.084000 77.688000 ;
  END
 END k_lo_d[396]
 PIN k_lo_d[397]
  DIRECTION INPUT ;
  USE SIGNAL ;
  PORT
   LAYER M4 ;
   RECT 0.000000 77.808000 0.084000 77.832000 ;
  END
 END k_lo_d[397]
 PIN k_lo_d[398]
  DIRECTION INPUT ;
  USE SIGNAL ;
  PORT
   LAYER M4 ;
   RECT 0.000000 78.000000 0.084000 78.024000 ;
  END
 END k_lo_d[398]
 PIN k_lo_d[399]
  DIRECTION INPUT ;
  USE SIGNAL ;
  PORT
   LAYER M4 ;
   RECT 0.000000 78.192000 0.084000 78.216000 ;
  END
 END k_lo_d[399]
 PIN k_lo_d[400]
  DIRECTION INPUT ;
  USE SIGNAL ;
  PORT
   LAYER M4 ;
   RECT 0.000000 78.384000 0.084000 78.408000 ;
  END
 END k_lo_d[400]
 PIN k_lo_d[401]
  DIRECTION INPUT ;
  USE SIGNAL ;
  PORT
   LAYER M4 ;
   RECT 0.000000 78.528000 0.084000 78.552000 ;
  END
 END k_lo_d[401]
 PIN k_lo_d[402]
  DIRECTION INPUT ;
  USE SIGNAL ;
  PORT
   LAYER M4 ;
   RECT 0.000000 78.720000 0.084000 78.744000 ;
  END
 END k_lo_d[402]
 PIN k_lo_d[403]
  DIRECTION INPUT ;
  USE SIGNAL ;
  PORT
   LAYER M4 ;
   RECT 0.000000 78.912000 0.084000 78.936000 ;
  END
 END k_lo_d[403]
 PIN k_lo_d[404]
  DIRECTION INPUT ;
  USE SIGNAL ;
  PORT
   LAYER M4 ;
   RECT 0.000000 79.104000 0.084000 79.128000 ;
  END
 END k_lo_d[404]
 PIN k_lo_d[405]
  DIRECTION INPUT ;
  USE SIGNAL ;
  PORT
   LAYER M4 ;
   RECT 0.000000 79.248000 0.084000 79.272000 ;
  END
 END k_lo_d[405]
 PIN k_lo_d[406]
  DIRECTION INPUT ;
  USE SIGNAL ;
  PORT
   LAYER M4 ;
   RECT 0.000000 79.440000 0.084000 79.464000 ;
  END
 END k_lo_d[406]
 PIN k_lo_d[407]
  DIRECTION INPUT ;
  USE SIGNAL ;
  PORT
   LAYER M4 ;
   RECT 0.000000 79.632000 0.084000 79.656000 ;
  END
 END k_lo_d[407]
 PIN k_lo_d[408]
  DIRECTION INPUT ;
  USE SIGNAL ;
  PORT
   LAYER M4 ;
   RECT 0.000000 79.824000 0.084000 79.848000 ;
  END
 END k_lo_d[408]
 PIN k_lo_d[409]
  DIRECTION INPUT ;
  USE SIGNAL ;
  PORT
   LAYER M4 ;
   RECT 0.000000 79.968000 0.084000 79.992000 ;
  END
 END k_lo_d[409]
 PIN k_lo_d[410]
  DIRECTION INPUT ;
  USE SIGNAL ;
  PORT
   LAYER M4 ;
   RECT 0.000000 80.160000 0.084000 80.184000 ;
  END
 END k_lo_d[410]
 PIN k_lo_d[411]
  DIRECTION INPUT ;
  USE SIGNAL ;
  PORT
   LAYER M4 ;
   RECT 0.000000 80.352000 0.084000 80.376000 ;
  END
 END k_lo_d[411]
 PIN k_lo_d[412]
  DIRECTION INPUT ;
  USE SIGNAL ;
  PORT
   LAYER M4 ;
   RECT 0.000000 80.544000 0.084000 80.568000 ;
  END
 END k_lo_d[412]
 PIN k_lo_d[413]
  DIRECTION INPUT ;
  USE SIGNAL ;
  PORT
   LAYER M4 ;
   RECT 0.000000 80.688000 0.084000 80.712000 ;
  END
 END k_lo_d[413]
 PIN k_lo_d[414]
  DIRECTION INPUT ;
  USE SIGNAL ;
  PORT
   LAYER M4 ;
   RECT 0.000000 80.880000 0.084000 80.904000 ;
  END
 END k_lo_d[414]
 PIN k_lo_d[415]
  DIRECTION INPUT ;
  USE SIGNAL ;
  PORT
   LAYER M4 ;
   RECT 0.000000 81.072000 0.084000 81.096000 ;
  END
 END k_lo_d[415]
 PIN k_lo_d[416]
  DIRECTION INPUT ;
  USE SIGNAL ;
  PORT
   LAYER M4 ;
   RECT 0.000000 81.264000 0.084000 81.288000 ;
  END
 END k_lo_d[416]
 PIN k_lo_d[417]
  DIRECTION INPUT ;
  USE SIGNAL ;
  PORT
   LAYER M4 ;
   RECT 0.000000 81.408000 0.084000 81.432000 ;
  END
 END k_lo_d[417]
 PIN k_lo_d[418]
  DIRECTION INPUT ;
  USE SIGNAL ;
  PORT
   LAYER M4 ;
   RECT 0.000000 81.600000 0.084000 81.624000 ;
  END
 END k_lo_d[418]
 PIN k_lo_d[419]
  DIRECTION INPUT ;
  USE SIGNAL ;
  PORT
   LAYER M4 ;
   RECT 0.000000 81.792000 0.084000 81.816000 ;
  END
 END k_lo_d[419]
 PIN k_lo_d[420]
  DIRECTION INPUT ;
  USE SIGNAL ;
  PORT
   LAYER M4 ;
   RECT 0.000000 81.984000 0.084000 82.008000 ;
  END
 END k_lo_d[420]
 PIN k_lo_d[421]
  DIRECTION INPUT ;
  USE SIGNAL ;
  PORT
   LAYER M4 ;
   RECT 0.000000 82.128000 0.084000 82.152000 ;
  END
 END k_lo_d[421]
 PIN k_lo_d[422]
  DIRECTION INPUT ;
  USE SIGNAL ;
  PORT
   LAYER M4 ;
   RECT 0.000000 82.320000 0.084000 82.344000 ;
  END
 END k_lo_d[422]
 PIN k_lo_d[423]
  DIRECTION INPUT ;
  USE SIGNAL ;
  PORT
   LAYER M4 ;
   RECT 0.000000 82.512000 0.084000 82.536000 ;
  END
 END k_lo_d[423]
 PIN k_lo_d[424]
  DIRECTION INPUT ;
  USE SIGNAL ;
  PORT
   LAYER M4 ;
   RECT 0.000000 82.704000 0.084000 82.728000 ;
  END
 END k_lo_d[424]
 PIN k_lo_d[425]
  DIRECTION INPUT ;
  USE SIGNAL ;
  PORT
   LAYER M4 ;
   RECT 0.000000 82.848000 0.084000 82.872000 ;
  END
 END k_lo_d[425]
 PIN k_lo_d[426]
  DIRECTION INPUT ;
  USE SIGNAL ;
  PORT
   LAYER M4 ;
   RECT 0.000000 83.040000 0.084000 83.064000 ;
  END
 END k_lo_d[426]
 PIN k_lo_d[427]
  DIRECTION INPUT ;
  USE SIGNAL ;
  PORT
   LAYER M4 ;
   RECT 0.000000 83.232000 0.084000 83.256000 ;
  END
 END k_lo_d[427]
 PIN k_lo_d[428]
  DIRECTION INPUT ;
  USE SIGNAL ;
  PORT
   LAYER M4 ;
   RECT 0.000000 83.424000 0.084000 83.448000 ;
  END
 END k_lo_d[428]
 PIN k_lo_d[429]
  DIRECTION INPUT ;
  USE SIGNAL ;
  PORT
   LAYER M4 ;
   RECT 0.000000 83.568000 0.084000 83.592000 ;
  END
 END k_lo_d[429]
 PIN k_lo_d[430]
  DIRECTION INPUT ;
  USE SIGNAL ;
  PORT
   LAYER M4 ;
   RECT 0.000000 83.760000 0.084000 83.784000 ;
  END
 END k_lo_d[430]
 PIN k_lo_d[431]
  DIRECTION INPUT ;
  USE SIGNAL ;
  PORT
   LAYER M4 ;
   RECT 0.000000 83.952000 0.084000 83.976000 ;
  END
 END k_lo_d[431]
 PIN k_lo_d[432]
  DIRECTION INPUT ;
  USE SIGNAL ;
  PORT
   LAYER M4 ;
   RECT 0.000000 84.144000 0.084000 84.168000 ;
  END
 END k_lo_d[432]
 PIN k_lo_d[433]
  DIRECTION INPUT ;
  USE SIGNAL ;
  PORT
   LAYER M4 ;
   RECT 0.000000 84.288000 0.084000 84.312000 ;
  END
 END k_lo_d[433]
 PIN k_lo_d[434]
  DIRECTION INPUT ;
  USE SIGNAL ;
  PORT
   LAYER M4 ;
   RECT 0.000000 84.480000 0.084000 84.504000 ;
  END
 END k_lo_d[434]
 PIN k_lo_d[435]
  DIRECTION INPUT ;
  USE SIGNAL ;
  PORT
   LAYER M4 ;
   RECT 0.000000 84.672000 0.084000 84.696000 ;
  END
 END k_lo_d[435]
 PIN k_lo_d[436]
  DIRECTION INPUT ;
  USE SIGNAL ;
  PORT
   LAYER M4 ;
   RECT 0.000000 84.864000 0.084000 84.888000 ;
  END
 END k_lo_d[436]
 PIN k_lo_d[437]
  DIRECTION INPUT ;
  USE SIGNAL ;
  PORT
   LAYER M4 ;
   RECT 0.000000 85.008000 0.084000 85.032000 ;
  END
 END k_lo_d[437]
 PIN k_lo_d[438]
  DIRECTION INPUT ;
  USE SIGNAL ;
  PORT
   LAYER M4 ;
   RECT 0.000000 85.200000 0.084000 85.224000 ;
  END
 END k_lo_d[438]
 PIN k_lo_d[439]
  DIRECTION INPUT ;
  USE SIGNAL ;
  PORT
   LAYER M4 ;
   RECT 0.000000 85.392000 0.084000 85.416000 ;
  END
 END k_lo_d[439]
 PIN k_lo_d[440]
  DIRECTION INPUT ;
  USE SIGNAL ;
  PORT
   LAYER M4 ;
   RECT 0.000000 85.584000 0.084000 85.608000 ;
  END
 END k_lo_d[440]
 PIN k_lo_d[441]
  DIRECTION INPUT ;
  USE SIGNAL ;
  PORT
   LAYER M4 ;
   RECT 0.000000 85.728000 0.084000 85.752000 ;
  END
 END k_lo_d[441]
 PIN k_lo_d[442]
  DIRECTION INPUT ;
  USE SIGNAL ;
  PORT
   LAYER M4 ;
   RECT 0.000000 85.920000 0.084000 85.944000 ;
  END
 END k_lo_d[442]
 PIN k_lo_d[443]
  DIRECTION INPUT ;
  USE SIGNAL ;
  PORT
   LAYER M4 ;
   RECT 0.000000 86.112000 0.084000 86.136000 ;
  END
 END k_lo_d[443]
 PIN k_lo_d[444]
  DIRECTION INPUT ;
  USE SIGNAL ;
  PORT
   LAYER M4 ;
   RECT 0.000000 86.304000 0.084000 86.328000 ;
  END
 END k_lo_d[444]
 PIN k_lo_d[445]
  DIRECTION INPUT ;
  USE SIGNAL ;
  PORT
   LAYER M4 ;
   RECT 0.000000 86.448000 0.084000 86.472000 ;
  END
 END k_lo_d[445]
 PIN k_lo_d[446]
  DIRECTION INPUT ;
  USE SIGNAL ;
  PORT
   LAYER M4 ;
   RECT 0.000000 86.640000 0.084000 86.664000 ;
  END
 END k_lo_d[446]
 PIN k_lo_d[447]
  DIRECTION INPUT ;
  USE SIGNAL ;
  PORT
   LAYER M4 ;
   RECT 0.000000 86.832000 0.084000 86.856000 ;
  END
 END k_lo_d[447]
 PIN k_lo_d[448]
  DIRECTION INPUT ;
  USE SIGNAL ;
  PORT
   LAYER M4 ;
   RECT 0.000000 87.024000 0.084000 87.048000 ;
  END
 END k_lo_d[448]
 PIN k_lo_d[449]
  DIRECTION INPUT ;
  USE SIGNAL ;
  PORT
   LAYER M4 ;
   RECT 0.000000 87.168000 0.084000 87.192000 ;
  END
 END k_lo_d[449]
 PIN k_lo_d[450]
  DIRECTION INPUT ;
  USE SIGNAL ;
  PORT
   LAYER M4 ;
   RECT 0.000000 87.360000 0.084000 87.384000 ;
  END
 END k_lo_d[450]
 PIN k_lo_d[451]
  DIRECTION INPUT ;
  USE SIGNAL ;
  PORT
   LAYER M4 ;
   RECT 0.000000 87.552000 0.084000 87.576000 ;
  END
 END k_lo_d[451]
 PIN k_lo_d[452]
  DIRECTION INPUT ;
  USE SIGNAL ;
  PORT
   LAYER M4 ;
   RECT 0.000000 87.744000 0.084000 87.768000 ;
  END
 END k_lo_d[452]
 PIN k_lo_d[453]
  DIRECTION INPUT ;
  USE SIGNAL ;
  PORT
   LAYER M4 ;
   RECT 0.000000 87.888000 0.084000 87.912000 ;
  END
 END k_lo_d[453]
 PIN k_lo_d[454]
  DIRECTION INPUT ;
  USE SIGNAL ;
  PORT
   LAYER M4 ;
   RECT 0.000000 88.080000 0.084000 88.104000 ;
  END
 END k_lo_d[454]
 PIN k_lo_d[455]
  DIRECTION INPUT ;
  USE SIGNAL ;
  PORT
   LAYER M4 ;
   RECT 0.000000 88.272000 0.084000 88.296000 ;
  END
 END k_lo_d[455]
 PIN k_lo_d[456]
  DIRECTION INPUT ;
  USE SIGNAL ;
  PORT
   LAYER M4 ;
   RECT 0.000000 88.464000 0.084000 88.488000 ;
  END
 END k_lo_d[456]
 PIN k_lo_d[457]
  DIRECTION INPUT ;
  USE SIGNAL ;
  PORT
   LAYER M4 ;
   RECT 0.000000 88.608000 0.084000 88.632000 ;
  END
 END k_lo_d[457]
 PIN k_lo_d[458]
  DIRECTION INPUT ;
  USE SIGNAL ;
  PORT
   LAYER M4 ;
   RECT 0.000000 88.800000 0.084000 88.824000 ;
  END
 END k_lo_d[458]
 PIN k_lo_d[459]
  DIRECTION INPUT ;
  USE SIGNAL ;
  PORT
   LAYER M4 ;
   RECT 0.000000 88.992000 0.084000 89.016000 ;
  END
 END k_lo_d[459]
 PIN k_lo_d[460]
  DIRECTION INPUT ;
  USE SIGNAL ;
  PORT
   LAYER M4 ;
   RECT 0.000000 89.184000 0.084000 89.208000 ;
  END
 END k_lo_d[460]
 PIN k_lo_d[461]
  DIRECTION INPUT ;
  USE SIGNAL ;
  PORT
   LAYER M4 ;
   RECT 0.000000 89.328000 0.084000 89.352000 ;
  END
 END k_lo_d[461]
 PIN k_lo_d[462]
  DIRECTION INPUT ;
  USE SIGNAL ;
  PORT
   LAYER M4 ;
   RECT 0.000000 89.520000 0.084000 89.544000 ;
  END
 END k_lo_d[462]
 PIN k_lo_d[463]
  DIRECTION INPUT ;
  USE SIGNAL ;
  PORT
   LAYER M4 ;
   RECT 0.000000 89.712000 0.084000 89.736000 ;
  END
 END k_lo_d[463]
 PIN k_lo_d[464]
  DIRECTION INPUT ;
  USE SIGNAL ;
  PORT
   LAYER M4 ;
   RECT 0.000000 89.904000 0.084000 89.928000 ;
  END
 END k_lo_d[464]
 PIN k_lo_d[465]
  DIRECTION INPUT ;
  USE SIGNAL ;
  PORT
   LAYER M4 ;
   RECT 0.000000 90.048000 0.084000 90.072000 ;
  END
 END k_lo_d[465]
 PIN k_lo_d[466]
  DIRECTION INPUT ;
  USE SIGNAL ;
  PORT
   LAYER M4 ;
   RECT 0.000000 90.240000 0.084000 90.264000 ;
  END
 END k_lo_d[466]
 PIN k_lo_d[467]
  DIRECTION INPUT ;
  USE SIGNAL ;
  PORT
   LAYER M4 ;
   RECT 0.000000 90.432000 0.084000 90.456000 ;
  END
 END k_lo_d[467]
 PIN k_lo_d[468]
  DIRECTION INPUT ;
  USE SIGNAL ;
  PORT
   LAYER M4 ;
   RECT 0.000000 90.624000 0.084000 90.648000 ;
  END
 END k_lo_d[468]
 PIN k_lo_d[469]
  DIRECTION INPUT ;
  USE SIGNAL ;
  PORT
   LAYER M4 ;
   RECT 0.000000 90.768000 0.084000 90.792000 ;
  END
 END k_lo_d[469]
 PIN k_lo_d[470]
  DIRECTION INPUT ;
  USE SIGNAL ;
  PORT
   LAYER M4 ;
   RECT 0.000000 90.960000 0.084000 90.984000 ;
  END
 END k_lo_d[470]
 PIN k_lo_d[471]
  DIRECTION INPUT ;
  USE SIGNAL ;
  PORT
   LAYER M4 ;
   RECT 0.000000 91.152000 0.084000 91.176000 ;
  END
 END k_lo_d[471]
 PIN k_lo_d[472]
  DIRECTION INPUT ;
  USE SIGNAL ;
  PORT
   LAYER M4 ;
   RECT 0.000000 91.344000 0.084000 91.368000 ;
  END
 END k_lo_d[472]
 PIN k_lo_d[473]
  DIRECTION INPUT ;
  USE SIGNAL ;
  PORT
   LAYER M4 ;
   RECT 0.000000 91.488000 0.084000 91.512000 ;
  END
 END k_lo_d[473]
 PIN k_lo_d[474]
  DIRECTION INPUT ;
  USE SIGNAL ;
  PORT
   LAYER M4 ;
   RECT 0.000000 91.680000 0.084000 91.704000 ;
  END
 END k_lo_d[474]
 PIN k_lo_d[475]
  DIRECTION INPUT ;
  USE SIGNAL ;
  PORT
   LAYER M4 ;
   RECT 0.000000 91.872000 0.084000 91.896000 ;
  END
 END k_lo_d[475]
 PIN k_lo_d[476]
  DIRECTION INPUT ;
  USE SIGNAL ;
  PORT
   LAYER M4 ;
   RECT 0.000000 92.064000 0.084000 92.088000 ;
  END
 END k_lo_d[476]
 PIN k_lo_d[477]
  DIRECTION INPUT ;
  USE SIGNAL ;
  PORT
   LAYER M4 ;
   RECT 0.000000 92.208000 0.084000 92.232000 ;
  END
 END k_lo_d[477]
 PIN k_lo_d[478]
  DIRECTION INPUT ;
  USE SIGNAL ;
  PORT
   LAYER M4 ;
   RECT 0.000000 92.400000 0.084000 92.424000 ;
  END
 END k_lo_d[478]
 PIN k_lo_d[479]
  DIRECTION INPUT ;
  USE SIGNAL ;
  PORT
   LAYER M4 ;
   RECT 0.000000 92.592000 0.084000 92.616000 ;
  END
 END k_lo_d[479]
 PIN k_lo_d[480]
  DIRECTION INPUT ;
  USE SIGNAL ;
  PORT
   LAYER M4 ;
   RECT 0.000000 92.784000 0.084000 92.808000 ;
  END
 END k_lo_d[480]
 PIN k_lo_d[481]
  DIRECTION INPUT ;
  USE SIGNAL ;
  PORT
   LAYER M4 ;
   RECT 0.000000 92.928000 0.084000 92.952000 ;
  END
 END k_lo_d[481]
 PIN k_lo_d[482]
  DIRECTION INPUT ;
  USE SIGNAL ;
  PORT
   LAYER M4 ;
   RECT 0.000000 93.120000 0.084000 93.144000 ;
  END
 END k_lo_d[482]
 PIN k_lo_d[483]
  DIRECTION INPUT ;
  USE SIGNAL ;
  PORT
   LAYER M4 ;
   RECT 0.000000 93.312000 0.084000 93.336000 ;
  END
 END k_lo_d[483]
 PIN k_lo_d[484]
  DIRECTION INPUT ;
  USE SIGNAL ;
  PORT
   LAYER M4 ;
   RECT 0.000000 93.504000 0.084000 93.528000 ;
  END
 END k_lo_d[484]
 PIN k_lo_d[485]
  DIRECTION INPUT ;
  USE SIGNAL ;
  PORT
   LAYER M4 ;
   RECT 0.000000 93.648000 0.084000 93.672000 ;
  END
 END k_lo_d[485]
 PIN k_lo_d[486]
  DIRECTION INPUT ;
  USE SIGNAL ;
  PORT
   LAYER M4 ;
   RECT 0.000000 93.840000 0.084000 93.864000 ;
  END
 END k_lo_d[486]
 PIN k_lo_d[487]
  DIRECTION INPUT ;
  USE SIGNAL ;
  PORT
   LAYER M4 ;
   RECT 0.000000 94.032000 0.084000 94.056000 ;
  END
 END k_lo_d[487]
 PIN k_lo_d[488]
  DIRECTION INPUT ;
  USE SIGNAL ;
  PORT
   LAYER M4 ;
   RECT 0.000000 94.176000 0.084000 94.200000 ;
  END
 END k_lo_d[488]
 PIN k_lo_d[489]
  DIRECTION INPUT ;
  USE SIGNAL ;
  PORT
   LAYER M4 ;
   RECT 0.000000 94.368000 0.084000 94.392000 ;
  END
 END k_lo_d[489]
 PIN k_lo_d[490]
  DIRECTION INPUT ;
  USE SIGNAL ;
  PORT
   LAYER M4 ;
   RECT 0.000000 94.560000 0.084000 94.584000 ;
  END
 END k_lo_d[490]
 PIN k_lo_d[491]
  DIRECTION INPUT ;
  USE SIGNAL ;
  PORT
   LAYER M4 ;
   RECT 0.000000 94.752000 0.084000 94.776000 ;
  END
 END k_lo_d[491]
 PIN k_lo_d[492]
  DIRECTION INPUT ;
  USE SIGNAL ;
  PORT
   LAYER M4 ;
   RECT 0.000000 94.896000 0.084000 94.920000 ;
  END
 END k_lo_d[492]
 PIN k_lo_d[493]
  DIRECTION INPUT ;
  USE SIGNAL ;
  PORT
   LAYER M4 ;
   RECT 0.000000 95.088000 0.084000 95.112000 ;
  END
 END k_lo_d[493]
 PIN k_lo_d[494]
  DIRECTION INPUT ;
  USE SIGNAL ;
  PORT
   LAYER M4 ;
   RECT 0.000000 95.280000 0.084000 95.304000 ;
  END
 END k_lo_d[494]
 PIN k_lo_d[495]
  DIRECTION INPUT ;
  USE SIGNAL ;
  PORT
   LAYER M4 ;
   RECT 0.000000 95.472000 0.084000 95.496000 ;
  END
 END k_lo_d[495]
 PIN k_lo_d[496]
  DIRECTION INPUT ;
  USE SIGNAL ;
  PORT
   LAYER M4 ;
   RECT 0.000000 95.616000 0.084000 95.640000 ;
  END
 END k_lo_d[496]
 PIN k_lo_d[497]
  DIRECTION INPUT ;
  USE SIGNAL ;
  PORT
   LAYER M4 ;
   RECT 0.000000 95.808000 0.084000 95.832000 ;
  END
 END k_lo_d[497]
 PIN k_lo_d[498]
  DIRECTION INPUT ;
  USE SIGNAL ;
  PORT
   LAYER M4 ;
   RECT 0.000000 96.000000 0.084000 96.024000 ;
  END
 END k_lo_d[498]
 PIN k_lo_d[499]
  DIRECTION INPUT ;
  USE SIGNAL ;
  PORT
   LAYER M4 ;
   RECT 0.000000 96.192000 0.084000 96.216000 ;
  END
 END k_lo_d[499]
 PIN k_lo_d[500]
  DIRECTION INPUT ;
  USE SIGNAL ;
  PORT
   LAYER M4 ;
   RECT 0.000000 96.336000 0.084000 96.360000 ;
  END
 END k_lo_d[500]
 PIN k_lo_d[501]
  DIRECTION INPUT ;
  USE SIGNAL ;
  PORT
   LAYER M4 ;
   RECT 0.000000 96.528000 0.084000 96.552000 ;
  END
 END k_lo_d[501]
 PIN k_lo_d[502]
  DIRECTION INPUT ;
  USE SIGNAL ;
  PORT
   LAYER M4 ;
   RECT 0.000000 96.720000 0.084000 96.744000 ;
  END
 END k_lo_d[502]
 PIN k_lo_d[503]
  DIRECTION INPUT ;
  USE SIGNAL ;
  PORT
   LAYER M4 ;
   RECT 0.000000 96.912000 0.084000 96.936000 ;
  END
 END k_lo_d[503]
 PIN k_lo_d[504]
  DIRECTION INPUT ;
  USE SIGNAL ;
  PORT
   LAYER M4 ;
   RECT 0.000000 97.056000 0.084000 97.080000 ;
  END
 END k_lo_d[504]
 PIN k_lo_d[505]
  DIRECTION INPUT ;
  USE SIGNAL ;
  PORT
   LAYER M4 ;
   RECT 0.000000 97.248000 0.084000 97.272000 ;
  END
 END k_lo_d[505]
 PIN k_lo_d[506]
  DIRECTION INPUT ;
  USE SIGNAL ;
  PORT
   LAYER M4 ;
   RECT 0.000000 97.440000 0.084000 97.464000 ;
  END
 END k_lo_d[506]
 PIN k_lo_d[507]
  DIRECTION INPUT ;
  USE SIGNAL ;
  PORT
   LAYER M4 ;
   RECT 0.000000 97.632000 0.084000 97.656000 ;
  END
 END k_lo_d[507]
 PIN k_lo_d[508]
  DIRECTION INPUT ;
  USE SIGNAL ;
  PORT
   LAYER M4 ;
   RECT 0.000000 97.776000 0.084000 97.800000 ;
  END
 END k_lo_d[508]
 PIN k_lo_d[509]
  DIRECTION INPUT ;
  USE SIGNAL ;
  PORT
   LAYER M4 ;
   RECT 0.000000 97.968000 0.084000 97.992000 ;
  END
 END k_lo_d[509]
 PIN k_lo_d[510]
  DIRECTION INPUT ;
  USE SIGNAL ;
  PORT
   LAYER M4 ;
   RECT 0.000000 98.160000 0.084000 98.184000 ;
  END
 END k_lo_d[510]
 PIN k_lo_d[511]
  DIRECTION INPUT ;
  USE SIGNAL ;
  PORT
   LAYER M4 ;
   RECT 0.000000 98.352000 0.084000 98.376000 ;
  END
 END k_lo_d[511]
 PIN k_lo_d[512]
  DIRECTION INPUT ;
  USE SIGNAL ;
  PORT
   LAYER M4 ;
   RECT 0.000000 98.496000 0.084000 98.520000 ;
  END
 END k_lo_d[512]
 PIN k_lo_d[513]
  DIRECTION INPUT ;
  USE SIGNAL ;
  PORT
   LAYER M4 ;
   RECT 0.000000 98.688000 0.084000 98.712000 ;
  END
 END k_lo_d[513]
 PIN k_lo_d[514]
  DIRECTION INPUT ;
  USE SIGNAL ;
  PORT
   LAYER M4 ;
   RECT 0.000000 98.880000 0.084000 98.904000 ;
  END
 END k_lo_d[514]
 PIN k_lo_d[515]
  DIRECTION INPUT ;
  USE SIGNAL ;
  PORT
   LAYER M4 ;
   RECT 0.000000 99.072000 0.084000 99.096000 ;
  END
 END k_lo_d[515]
 PIN k_lo_d[516]
  DIRECTION INPUT ;
  USE SIGNAL ;
  PORT
   LAYER M4 ;
   RECT 0.000000 99.216000 0.084000 99.240000 ;
  END
 END k_lo_d[516]
 PIN k_lo_d[517]
  DIRECTION INPUT ;
  USE SIGNAL ;
  PORT
   LAYER M4 ;
   RECT 0.000000 99.408000 0.084000 99.432000 ;
  END
 END k_lo_d[517]
 PIN k_lo_d[518]
  DIRECTION INPUT ;
  USE SIGNAL ;
  PORT
   LAYER M4 ;
   RECT 0.000000 99.600000 0.084000 99.624000 ;
  END
 END k_lo_d[518]
 PIN k_lo_d[519]
  DIRECTION INPUT ;
  USE SIGNAL ;
  PORT
   LAYER M4 ;
   RECT 0.000000 99.792000 0.084000 99.816000 ;
  END
 END k_lo_d[519]
 PIN k_lo_d[520]
  DIRECTION INPUT ;
  USE SIGNAL ;
  PORT
   LAYER M4 ;
   RECT 0.000000 99.936000 0.084000 99.960000 ;
  END
 END k_lo_d[520]
 PIN k_lo_d[521]
  DIRECTION INPUT ;
  USE SIGNAL ;
  PORT
   LAYER M4 ;
   RECT 0.000000 100.128000 0.084000 100.152000 ;
  END
 END k_lo_d[521]
 PIN k_lo_d[522]
  DIRECTION INPUT ;
  USE SIGNAL ;
  PORT
   LAYER M4 ;
   RECT 0.000000 100.320000 0.084000 100.344000 ;
  END
 END k_lo_d[522]
 PIN k_lo_d[523]
  DIRECTION INPUT ;
  USE SIGNAL ;
  PORT
   LAYER M4 ;
   RECT 0.000000 100.512000 0.084000 100.536000 ;
  END
 END k_lo_d[523]
 PIN k_lo_d[524]
  DIRECTION INPUT ;
  USE SIGNAL ;
  PORT
   LAYER M4 ;
   RECT 0.000000 100.656000 0.084000 100.680000 ;
  END
 END k_lo_d[524]
 PIN k_lo_d[525]
  DIRECTION INPUT ;
  USE SIGNAL ;
  PORT
   LAYER M4 ;
   RECT 0.000000 100.848000 0.084000 100.872000 ;
  END
 END k_lo_d[525]
 PIN k_lo_d[526]
  DIRECTION INPUT ;
  USE SIGNAL ;
  PORT
   LAYER M4 ;
   RECT 0.000000 101.040000 0.084000 101.064000 ;
  END
 END k_lo_d[526]
 PIN k_lo_d[527]
  DIRECTION INPUT ;
  USE SIGNAL ;
  PORT
   LAYER M4 ;
   RECT 0.000000 101.232000 0.084000 101.256000 ;
  END
 END k_lo_d[527]
 PIN k_lo_d[528]
  DIRECTION INPUT ;
  USE SIGNAL ;
  PORT
   LAYER M4 ;
   RECT 0.000000 101.376000 0.084000 101.400000 ;
  END
 END k_lo_d[528]
 PIN k_lo_d[529]
  DIRECTION INPUT ;
  USE SIGNAL ;
  PORT
   LAYER M4 ;
   RECT 0.000000 101.568000 0.084000 101.592000 ;
  END
 END k_lo_d[529]
 PIN k_lo_d[530]
  DIRECTION INPUT ;
  USE SIGNAL ;
  PORT
   LAYER M4 ;
   RECT 0.000000 101.760000 0.084000 101.784000 ;
  END
 END k_lo_d[530]
 PIN k_lo_d[531]
  DIRECTION INPUT ;
  USE SIGNAL ;
  PORT
   LAYER M4 ;
   RECT 0.000000 101.952000 0.084000 101.976000 ;
  END
 END k_lo_d[531]
 PIN k_lo_d[532]
  DIRECTION INPUT ;
  USE SIGNAL ;
  PORT
   LAYER M4 ;
   RECT 0.000000 102.096000 0.084000 102.120000 ;
  END
 END k_lo_d[532]
 PIN k_lo_d[533]
  DIRECTION INPUT ;
  USE SIGNAL ;
  PORT
   LAYER M4 ;
   RECT 0.000000 102.288000 0.084000 102.312000 ;
  END
 END k_lo_d[533]
 PIN k_lo_d[534]
  DIRECTION INPUT ;
  USE SIGNAL ;
  PORT
   LAYER M4 ;
   RECT 0.000000 102.480000 0.084000 102.504000 ;
  END
 END k_lo_d[534]
 PIN k_lo_d[535]
  DIRECTION INPUT ;
  USE SIGNAL ;
  PORT
   LAYER M4 ;
   RECT 0.000000 102.672000 0.084000 102.696000 ;
  END
 END k_lo_d[535]
 PIN k_lo_d[536]
  DIRECTION INPUT ;
  USE SIGNAL ;
  PORT
   LAYER M4 ;
   RECT 0.000000 102.816000 0.084000 102.840000 ;
  END
 END k_lo_d[536]
 PIN k_lo_d[537]
  DIRECTION INPUT ;
  USE SIGNAL ;
  PORT
   LAYER M4 ;
   RECT 0.000000 103.008000 0.084000 103.032000 ;
  END
 END k_lo_d[537]
 PIN k_lo_d[538]
  DIRECTION INPUT ;
  USE SIGNAL ;
  PORT
   LAYER M4 ;
   RECT 0.000000 103.200000 0.084000 103.224000 ;
  END
 END k_lo_d[538]
 PIN k_lo_d[539]
  DIRECTION INPUT ;
  USE SIGNAL ;
  PORT
   LAYER M4 ;
   RECT 0.000000 103.392000 0.084000 103.416000 ;
  END
 END k_lo_d[539]
 PIN k_lo_d[540]
  DIRECTION INPUT ;
  USE SIGNAL ;
  PORT
   LAYER M4 ;
   RECT 0.000000 103.536000 0.084000 103.560000 ;
  END
 END k_lo_d[540]
 PIN k_lo_d[541]
  DIRECTION INPUT ;
  USE SIGNAL ;
  PORT
   LAYER M4 ;
   RECT 0.000000 103.728000 0.084000 103.752000 ;
  END
 END k_lo_d[541]
 PIN k_lo_d[542]
  DIRECTION INPUT ;
  USE SIGNAL ;
  PORT
   LAYER M4 ;
   RECT 0.000000 103.920000 0.084000 103.944000 ;
  END
 END k_lo_d[542]
 PIN k_lo_d[543]
  DIRECTION INPUT ;
  USE SIGNAL ;
  PORT
   LAYER M4 ;
   RECT 0.000000 104.112000 0.084000 104.136000 ;
  END
 END k_lo_d[543]
 PIN k_lo_d[544]
  DIRECTION INPUT ;
  USE SIGNAL ;
  PORT
   LAYER M4 ;
   RECT 0.000000 104.256000 0.084000 104.280000 ;
  END
 END k_lo_d[544]
 PIN k_lo_d[545]
  DIRECTION INPUT ;
  USE SIGNAL ;
  PORT
   LAYER M4 ;
   RECT 0.000000 104.448000 0.084000 104.472000 ;
  END
 END k_lo_d[545]
 PIN k_lo_d[546]
  DIRECTION INPUT ;
  USE SIGNAL ;
  PORT
   LAYER M4 ;
   RECT 0.000000 104.640000 0.084000 104.664000 ;
  END
 END k_lo_d[546]
 PIN k_lo_d[547]
  DIRECTION INPUT ;
  USE SIGNAL ;
  PORT
   LAYER M4 ;
   RECT 0.000000 104.832000 0.084000 104.856000 ;
  END
 END k_lo_d[547]
 PIN k_lo_d[548]
  DIRECTION INPUT ;
  USE SIGNAL ;
  PORT
   LAYER M4 ;
   RECT 0.000000 104.976000 0.084000 105.000000 ;
  END
 END k_lo_d[548]
 PIN k_lo_d[549]
  DIRECTION INPUT ;
  USE SIGNAL ;
  PORT
   LAYER M4 ;
   RECT 0.000000 105.168000 0.084000 105.192000 ;
  END
 END k_lo_d[549]
 PIN k_lo_d[550]
  DIRECTION INPUT ;
  USE SIGNAL ;
  PORT
   LAYER M4 ;
   RECT 0.000000 105.360000 0.084000 105.384000 ;
  END
 END k_lo_d[550]
 PIN k_lo_d[551]
  DIRECTION INPUT ;
  USE SIGNAL ;
  PORT
   LAYER M4 ;
   RECT 0.000000 105.552000 0.084000 105.576000 ;
  END
 END k_lo_d[551]
 PIN k_lo_d[552]
  DIRECTION INPUT ;
  USE SIGNAL ;
  PORT
   LAYER M4 ;
   RECT 0.000000 105.696000 0.084000 105.720000 ;
  END
 END k_lo_d[552]
 PIN k_li_r
  DIRECTION INPUT ;
  USE SIGNAL ;
  PORT
   LAYER M4 ;
   RECT 0.000000 105.888000 0.084000 105.912000 ;
  END
 END k_li_r
 PIN k_rxv
  DIRECTION INPUT ;
  USE SIGNAL ;
  PORT
   LAYER M4 ;
   RECT 0.000000 106.080000 0.084000 106.104000 ;
  END
 END k_rxv
 PIN k_lo_r
  DIRECTION OUTPUT ;
  USE SIGNAL ;
  PORT
   LAYER M5 ;
   RECT 6.192000 0.000000 6.216000 0.084000 ;
  END
 END k_lo_r
 PIN k_li_v
  DIRECTION OUTPUT ;
  USE SIGNAL ;
  PORT
   LAYER M5 ;
   RECT 6.768000 0.000000 6.792000 0.084000 ;
  END
 END k_li_v
 PIN k_li_d[0]
  DIRECTION OUTPUT ;
  USE SIGNAL ;
  PORT
   LAYER M5 ;
   RECT 6.816000 0.000000 6.840000 0.084000 ;
  END
 END k_li_d[0]
 PIN k_li_d[1]
  DIRECTION OUTPUT ;
  USE SIGNAL ;
  PORT
   LAYER M5 ;
   RECT 6.864000 0.000000 6.888000 0.084000 ;
  END
 END k_li_d[1]
 PIN k_li_d[2]
  DIRECTION OUTPUT ;
  USE SIGNAL ;
  PORT
   LAYER M5 ;
   RECT 6.960000 0.000000 6.984000 0.084000 ;
  END
 END k_li_d[2]
 PIN k_li_d[3]
  DIRECTION OUTPUT ;
  USE SIGNAL ;
  PORT
   LAYER M5 ;
   RECT 7.104000 0.000000 7.128000 0.084000 ;
  END
 END k_li_d[3]
 PIN k_li_d[4]
  DIRECTION OUTPUT ;
  USE SIGNAL ;
  PORT
   LAYER M5 ;
   RECT 7.296000 0.000000 7.320000 0.084000 ;
  END
 END k_li_d[4]
 PIN k_li_d[5]
  DIRECTION OUTPUT ;
  USE SIGNAL ;
  PORT
   LAYER M5 ;
   RECT 7.488000 0.000000 7.512000 0.084000 ;
  END
 END k_li_d[5]
 PIN k_li_d[6]
  DIRECTION OUTPUT ;
  USE SIGNAL ;
  PORT
   LAYER M5 ;
   RECT 7.632000 0.000000 7.656000 0.084000 ;
  END
 END k_li_d[6]
 PIN k_li_d[7]
  DIRECTION OUTPUT ;
  USE SIGNAL ;
  PORT
   LAYER M5 ;
   RECT 7.824000 0.000000 7.848000 0.084000 ;
  END
 END k_li_d[7]
 PIN k_li_d[8]
  DIRECTION OUTPUT ;
  USE SIGNAL ;
  PORT
   LAYER M5 ;
   RECT 8.016000 0.000000 8.040000 0.084000 ;
  END
 END k_li_d[8]
 PIN k_li_d[9]
  DIRECTION OUTPUT ;
  USE SIGNAL ;
  PORT
   LAYER M5 ;
   RECT 8.208000 0.000000 8.232000 0.084000 ;
  END
 END k_li_d[9]
 PIN k_li_d[10]
  DIRECTION OUTPUT ;
  USE SIGNAL ;
  PORT
   LAYER M5 ;
   RECT 8.352000 0.000000 8.376000 0.084000 ;
  END
 END k_li_d[10]
 PIN k_li_d[11]
  DIRECTION OUTPUT ;
  USE SIGNAL ;
  PORT
   LAYER M5 ;
   RECT 8.544000 0.000000 8.568000 0.084000 ;
  END
 END k_li_d[11]
 PIN k_li_d[12]
  DIRECTION OUTPUT ;
  USE SIGNAL ;
  PORT
   LAYER M5 ;
   RECT 8.736000 0.000000 8.760000 0.084000 ;
  END
 END k_li_d[12]
 PIN k_li_d[13]
  DIRECTION OUTPUT ;
  USE SIGNAL ;
  PORT
   LAYER M5 ;
   RECT 8.928000 0.000000 8.952000 0.084000 ;
  END
 END k_li_d[13]
 PIN k_li_d[14]
  DIRECTION OUTPUT ;
  USE SIGNAL ;
  PORT
   LAYER M5 ;
   RECT 9.072000 0.000000 9.096000 0.084000 ;
  END
 END k_li_d[14]
 PIN k_li_d[15]
  DIRECTION OUTPUT ;
  USE SIGNAL ;
  PORT
   LAYER M5 ;
   RECT 9.264000 0.000000 9.288000 0.084000 ;
  END
 END k_li_d[15]
 PIN k_li_d[16]
  DIRECTION OUTPUT ;
  USE SIGNAL ;
  PORT
   LAYER M5 ;
   RECT 9.456000 0.000000 9.480000 0.084000 ;
  END
 END k_li_d[16]
 PIN k_li_d[17]
  DIRECTION OUTPUT ;
  USE SIGNAL ;
  PORT
   LAYER M5 ;
   RECT 9.648000 0.000000 9.672000 0.084000 ;
  END
 END k_li_d[17]
 PIN k_li_d[18]
  DIRECTION OUTPUT ;
  USE SIGNAL ;
  PORT
   LAYER M5 ;
   RECT 9.792000 0.000000 9.816000 0.084000 ;
  END
 END k_li_d[18]
 PIN k_li_d[19]
  DIRECTION OUTPUT ;
  USE SIGNAL ;
  PORT
   LAYER M5 ;
   RECT 9.984000 0.000000 10.008000 0.084000 ;
  END
 END k_li_d[19]
 PIN k_li_d[20]
  DIRECTION OUTPUT ;
  USE SIGNAL ;
  PORT
   LAYER M5 ;
   RECT 10.176000 0.000000 10.200000 0.084000 ;
  END
 END k_li_d[20]
 PIN k_li_d[21]
  DIRECTION OUTPUT ;
  USE SIGNAL ;
  PORT
   LAYER M5 ;
   RECT 10.368000 0.000000 10.392000 0.084000 ;
  END
 END k_li_d[21]
 PIN k_li_d[22]
  DIRECTION OUTPUT ;
  USE SIGNAL ;
  PORT
   LAYER M5 ;
   RECT 10.512000 0.000000 10.536000 0.084000 ;
  END
 END k_li_d[22]
 PIN k_li_d[23]
  DIRECTION OUTPUT ;
  USE SIGNAL ;
  PORT
   LAYER M5 ;
   RECT 11.088000 0.000000 11.112000 0.084000 ;
  END
 END k_li_d[23]
 PIN k_li_d[24]
  DIRECTION OUTPUT ;
  USE SIGNAL ;
  PORT
   LAYER M5 ;
   RECT 11.136000 0.000000 11.160000 0.084000 ;
  END
 END k_li_d[24]
 PIN k_li_d[25]
  DIRECTION OUTPUT ;
  USE SIGNAL ;
  PORT
   LAYER M5 ;
   RECT 11.184000 0.000000 11.208000 0.084000 ;
  END
 END k_li_d[25]
 PIN k_li_d[26]
  DIRECTION OUTPUT ;
  USE SIGNAL ;
  PORT
   LAYER M5 ;
   RECT 11.232000 0.000000 11.256000 0.084000 ;
  END
 END k_li_d[26]
 PIN k_li_d[27]
  DIRECTION OUTPUT ;
  USE SIGNAL ;
  PORT
   LAYER M5 ;
   RECT 11.424000 0.000000 11.448000 0.084000 ;
  END
 END k_li_d[27]
 PIN k_li_d[28]
  DIRECTION OUTPUT ;
  USE SIGNAL ;
  PORT
   LAYER M5 ;
   RECT 11.616000 0.000000 11.640000 0.084000 ;
  END
 END k_li_d[28]
 PIN k_li_d[29]
  DIRECTION OUTPUT ;
  USE SIGNAL ;
  PORT
   LAYER M5 ;
   RECT 11.760000 0.000000 11.784000 0.084000 ;
  END
 END k_li_d[29]
 PIN k_li_d[30]
  DIRECTION OUTPUT ;
  USE SIGNAL ;
  PORT
   LAYER M5 ;
   RECT 11.952000 0.000000 11.976000 0.084000 ;
  END
 END k_li_d[30]
 PIN k_li_d[31]
  DIRECTION OUTPUT ;
  USE SIGNAL ;
  PORT
   LAYER M5 ;
   RECT 12.144000 0.000000 12.168000 0.084000 ;
  END
 END k_li_d[31]
 PIN k_li_d[32]
  DIRECTION OUTPUT ;
  USE SIGNAL ;
  PORT
   LAYER M5 ;
   RECT 12.336000 0.000000 12.360000 0.084000 ;
  END
 END k_li_d[32]
 PIN k_li_d[33]
  DIRECTION OUTPUT ;
  USE SIGNAL ;
  PORT
   LAYER M5 ;
   RECT 12.480000 0.000000 12.504000 0.084000 ;
  END
 END k_li_d[33]
 PIN k_li_d[34]
  DIRECTION OUTPUT ;
  USE SIGNAL ;
  PORT
   LAYER M5 ;
   RECT 12.672000 0.000000 12.696000 0.084000 ;
  END
 END k_li_d[34]
 PIN k_li_d[35]
  DIRECTION OUTPUT ;
  USE SIGNAL ;
  PORT
   LAYER M5 ;
   RECT 12.864000 0.000000 12.888000 0.084000 ;
  END
 END k_li_d[35]
 PIN k_li_d[36]
  DIRECTION OUTPUT ;
  USE SIGNAL ;
  PORT
   LAYER M5 ;
   RECT 13.056000 0.000000 13.080000 0.084000 ;
  END
 END k_li_d[36]
 PIN k_li_d[37]
  DIRECTION OUTPUT ;
  USE SIGNAL ;
  PORT
   LAYER M5 ;
   RECT 13.200000 0.000000 13.224000 0.084000 ;
  END
 END k_li_d[37]
 PIN k_li_d[38]
  DIRECTION OUTPUT ;
  USE SIGNAL ;
  PORT
   LAYER M5 ;
   RECT 13.392000 0.000000 13.416000 0.084000 ;
  END
 END k_li_d[38]
 PIN k_li_d[39]
  DIRECTION OUTPUT ;
  USE SIGNAL ;
  PORT
   LAYER M5 ;
   RECT 13.584000 0.000000 13.608000 0.084000 ;
  END
 END k_li_d[39]
 PIN k_li_d[40]
  DIRECTION OUTPUT ;
  USE SIGNAL ;
  PORT
   LAYER M5 ;
   RECT 13.728000 0.000000 13.752000 0.084000 ;
  END
 END k_li_d[40]
 PIN k_li_d[41]
  DIRECTION OUTPUT ;
  USE SIGNAL ;
  PORT
   LAYER M5 ;
   RECT 13.920000 0.000000 13.944000 0.084000 ;
  END
 END k_li_d[41]
 PIN k_li_d[42]
  DIRECTION OUTPUT ;
  USE SIGNAL ;
  PORT
   LAYER M5 ;
   RECT 14.112000 0.000000 14.136000 0.084000 ;
  END
 END k_li_d[42]
 PIN k_li_d[43]
  DIRECTION OUTPUT ;
  USE SIGNAL ;
  PORT
   LAYER M5 ;
   RECT 14.304000 0.000000 14.328000 0.084000 ;
  END
 END k_li_d[43]
 PIN k_li_d[44]
  DIRECTION OUTPUT ;
  USE SIGNAL ;
  PORT
   LAYER M5 ;
   RECT 14.448000 0.000000 14.472000 0.084000 ;
  END
 END k_li_d[44]
 PIN k_li_d[45]
  DIRECTION OUTPUT ;
  USE SIGNAL ;
  PORT
   LAYER M5 ;
   RECT 14.640000 0.000000 14.664000 0.084000 ;
  END
 END k_li_d[45]
 PIN k_li_d[46]
  DIRECTION OUTPUT ;
  USE SIGNAL ;
  PORT
   LAYER M5 ;
   RECT 14.832000 0.000000 14.856000 0.084000 ;
  END
 END k_li_d[46]
 PIN k_li_d[47]
  DIRECTION OUTPUT ;
  USE SIGNAL ;
  PORT
   LAYER M5 ;
   RECT 15.408000 0.000000 15.432000 0.084000 ;
  END
 END k_li_d[47]
 PIN k_li_d[48]
  DIRECTION OUTPUT ;
  USE SIGNAL ;
  PORT
   LAYER M5 ;
   RECT 15.456000 0.000000 15.480000 0.084000 ;
  END
 END k_li_d[48]
 PIN k_li_d[49]
  DIRECTION OUTPUT ;
  USE SIGNAL ;
  PORT
   LAYER M5 ;
   RECT 15.504000 0.000000 15.528000 0.084000 ;
  END
 END k_li_d[49]
 PIN k_li_d[50]
  DIRECTION OUTPUT ;
  USE SIGNAL ;
  PORT
   LAYER M5 ;
   RECT 15.552000 0.000000 15.576000 0.084000 ;
  END
 END k_li_d[50]
 PIN k_li_d[51]
  DIRECTION OUTPUT ;
  USE SIGNAL ;
  PORT
   LAYER M5 ;
   RECT 15.744000 0.000000 15.768000 0.084000 ;
  END
 END k_li_d[51]
 PIN k_li_d[52]
  DIRECTION OUTPUT ;
  USE SIGNAL ;
  PORT
   LAYER M5 ;
   RECT 15.888000 0.000000 15.912000 0.084000 ;
  END
 END k_li_d[52]
 PIN k_li_d[53]
  DIRECTION OUTPUT ;
  USE SIGNAL ;
  PORT
   LAYER M5 ;
   RECT 16.080000 0.000000 16.104000 0.084000 ;
  END
 END k_li_d[53]
 PIN k_li_d[54]
  DIRECTION OUTPUT ;
  USE SIGNAL ;
  PORT
   LAYER M5 ;
   RECT 16.272000 0.000000 16.296000 0.084000 ;
  END
 END k_li_d[54]
 PIN k_li_d[55]
  DIRECTION OUTPUT ;
  USE SIGNAL ;
  PORT
   LAYER M5 ;
   RECT 16.416000 0.000000 16.440000 0.084000 ;
  END
 END k_li_d[55]
 PIN k_li_d[56]
  DIRECTION OUTPUT ;
  USE SIGNAL ;
  PORT
   LAYER M5 ;
   RECT 16.608000 0.000000 16.632000 0.084000 ;
  END
 END k_li_d[56]
 PIN k_li_d[57]
  DIRECTION OUTPUT ;
  USE SIGNAL ;
  PORT
   LAYER M5 ;
   RECT 16.800000 0.000000 16.824000 0.084000 ;
  END
 END k_li_d[57]
 PIN k_li_d[58]
  DIRECTION OUTPUT ;
  USE SIGNAL ;
  PORT
   LAYER M5 ;
   RECT 16.992000 0.000000 17.016000 0.084000 ;
  END
 END k_li_d[58]
 PIN k_li_d[59]
  DIRECTION OUTPUT ;
  USE SIGNAL ;
  PORT
   LAYER M5 ;
   RECT 17.136000 0.000000 17.160000 0.084000 ;
  END
 END k_li_d[59]
 PIN k_li_d[60]
  DIRECTION OUTPUT ;
  USE SIGNAL ;
  PORT
   LAYER M5 ;
   RECT 17.328000 0.000000 17.352000 0.084000 ;
  END
 END k_li_d[60]
 PIN k_li_d[61]
  DIRECTION OUTPUT ;
  USE SIGNAL ;
  PORT
   LAYER M5 ;
   RECT 17.520000 0.000000 17.544000 0.084000 ;
  END
 END k_li_d[61]
 PIN k_li_d[62]
  DIRECTION OUTPUT ;
  USE SIGNAL ;
  PORT
   LAYER M5 ;
   RECT 17.712000 0.000000 17.736000 0.084000 ;
  END
 END k_li_d[62]
 PIN k_li_d[63]
  DIRECTION OUTPUT ;
  USE SIGNAL ;
  PORT
   LAYER M5 ;
   RECT 17.856000 0.000000 17.880000 0.084000 ;
  END
 END k_li_d[63]
 PIN k_li_d[64]
  DIRECTION OUTPUT ;
  USE SIGNAL ;
  PORT
   LAYER M5 ;
   RECT 18.048000 0.000000 18.072000 0.084000 ;
  END
 END k_li_d[64]
 PIN k_li_d[65]
  DIRECTION OUTPUT ;
  USE SIGNAL ;
  PORT
   LAYER M5 ;
   RECT 18.240000 0.000000 18.264000 0.084000 ;
  END
 END k_li_d[65]
 PIN k_li_d[66]
  DIRECTION OUTPUT ;
  USE SIGNAL ;
  PORT
   LAYER M5 ;
   RECT 18.432000 0.000000 18.456000 0.084000 ;
  END
 END k_li_d[66]
 PIN k_li_d[67]
  DIRECTION OUTPUT ;
  USE SIGNAL ;
  PORT
   LAYER M5 ;
   RECT 18.576000 0.000000 18.600000 0.084000 ;
  END
 END k_li_d[67]
 PIN k_li_d[68]
  DIRECTION OUTPUT ;
  USE SIGNAL ;
  PORT
   LAYER M5 ;
   RECT 18.768000 0.000000 18.792000 0.084000 ;
  END
 END k_li_d[68]
 PIN k_li_d[69]
  DIRECTION OUTPUT ;
  USE SIGNAL ;
  PORT
   LAYER M5 ;
   RECT 18.960000 0.000000 18.984000 0.084000 ;
  END
 END k_li_d[69]
 PIN k_li_d[70]
  DIRECTION OUTPUT ;
  USE SIGNAL ;
  PORT
   LAYER M5 ;
   RECT 19.152000 0.000000 19.176000 0.084000 ;
  END
 END k_li_d[70]
 PIN k_li_d[71]
  DIRECTION OUTPUT ;
  USE SIGNAL ;
  PORT
   LAYER M5 ;
   RECT 19.728000 0.000000 19.752000 0.084000 ;
  END
 END k_li_d[71]
 PIN k_li_d[72]
  DIRECTION OUTPUT ;
  USE SIGNAL ;
  PORT
   LAYER M5 ;
   RECT 19.776000 0.000000 19.800000 0.084000 ;
  END
 END k_li_d[72]
 PIN k_li_d[73]
  DIRECTION OUTPUT ;
  USE SIGNAL ;
  PORT
   LAYER M5 ;
   RECT 19.824000 0.000000 19.848000 0.084000 ;
  END
 END k_li_d[73]
 PIN k_li_d[74]
  DIRECTION OUTPUT ;
  USE SIGNAL ;
  PORT
   LAYER M5 ;
   RECT 19.872000 0.000000 19.896000 0.084000 ;
  END
 END k_li_d[74]
 PIN k_li_d[75]
  DIRECTION OUTPUT ;
  USE SIGNAL ;
  PORT
   LAYER M5 ;
   RECT 20.016000 0.000000 20.040000 0.084000 ;
  END
 END k_li_d[75]
 PIN k_li_d[76]
  DIRECTION OUTPUT ;
  USE SIGNAL ;
  PORT
   LAYER M5 ;
   RECT 20.208000 0.000000 20.232000 0.084000 ;
  END
 END k_li_d[76]
 PIN k_li_d[77]
  DIRECTION OUTPUT ;
  USE SIGNAL ;
  PORT
   LAYER M5 ;
   RECT 20.400000 0.000000 20.424000 0.084000 ;
  END
 END k_li_d[77]
 PIN k_li_d[78]
  DIRECTION OUTPUT ;
  USE SIGNAL ;
  PORT
   LAYER M5 ;
   RECT 20.544000 0.000000 20.568000 0.084000 ;
  END
 END k_li_d[78]
 PIN k_li_d[79]
  DIRECTION OUTPUT ;
  USE SIGNAL ;
  PORT
   LAYER M5 ;
   RECT 20.736000 0.000000 20.760000 0.084000 ;
  END
 END k_li_d[79]
 PIN k_li_d[80]
  DIRECTION OUTPUT ;
  USE SIGNAL ;
  PORT
   LAYER M5 ;
   RECT 20.928000 0.000000 20.952000 0.084000 ;
  END
 END k_li_d[80]
 PIN k_li_d[81]
  DIRECTION OUTPUT ;
  USE SIGNAL ;
  PORT
   LAYER M5 ;
   RECT 21.120000 0.000000 21.144000 0.084000 ;
  END
 END k_li_d[81]
 PIN k_li_d[82]
  DIRECTION OUTPUT ;
  USE SIGNAL ;
  PORT
   LAYER M5 ;
   RECT 21.264000 0.000000 21.288000 0.084000 ;
  END
 END k_li_d[82]
 PIN k_li_d[83]
  DIRECTION OUTPUT ;
  USE SIGNAL ;
  PORT
   LAYER M5 ;
   RECT 21.456000 0.000000 21.480000 0.084000 ;
  END
 END k_li_d[83]
 PIN k_li_d[84]
  DIRECTION OUTPUT ;
  USE SIGNAL ;
  PORT
   LAYER M5 ;
   RECT 21.648000 0.000000 21.672000 0.084000 ;
  END
 END k_li_d[84]
 PIN k_li_d[85]
  DIRECTION OUTPUT ;
  USE SIGNAL ;
  PORT
   LAYER M5 ;
   RECT 21.840000 0.000000 21.864000 0.084000 ;
  END
 END k_li_d[85]
 PIN k_li_d[86]
  DIRECTION OUTPUT ;
  USE SIGNAL ;
  PORT
   LAYER M5 ;
   RECT 21.984000 0.000000 22.008000 0.084000 ;
  END
 END k_li_d[86]
 PIN k_li_d[87]
  DIRECTION OUTPUT ;
  USE SIGNAL ;
  PORT
   LAYER M5 ;
   RECT 22.176000 0.000000 22.200000 0.084000 ;
  END
 END k_li_d[87]
 PIN k_li_d[88]
  DIRECTION OUTPUT ;
  USE SIGNAL ;
  PORT
   LAYER M5 ;
   RECT 22.368000 0.000000 22.392000 0.084000 ;
  END
 END k_li_d[88]
 PIN k_li_d[89]
  DIRECTION OUTPUT ;
  USE SIGNAL ;
  PORT
   LAYER M5 ;
   RECT 22.512000 0.000000 22.536000 0.084000 ;
  END
 END k_li_d[89]
 PIN k_li_d[90]
  DIRECTION OUTPUT ;
  USE SIGNAL ;
  PORT
   LAYER M5 ;
   RECT 22.704000 0.000000 22.728000 0.084000 ;
  END
 END k_li_d[90]
 PIN k_li_d[91]
  DIRECTION OUTPUT ;
  USE SIGNAL ;
  PORT
   LAYER M5 ;
   RECT 22.896000 0.000000 22.920000 0.084000 ;
  END
 END k_li_d[91]
 PIN k_li_d[92]
  DIRECTION OUTPUT ;
  USE SIGNAL ;
  PORT
   LAYER M5 ;
   RECT 23.088000 0.000000 23.112000 0.084000 ;
  END
 END k_li_d[92]
 PIN k_li_d[93]
  DIRECTION OUTPUT ;
  USE SIGNAL ;
  PORT
   LAYER M5 ;
   RECT 23.232000 0.000000 23.256000 0.084000 ;
  END
 END k_li_d[93]
 PIN k_li_d[94]
  DIRECTION OUTPUT ;
  USE SIGNAL ;
  PORT
   LAYER M5 ;
   RECT 23.424000 0.000000 23.448000 0.084000 ;
  END
 END k_li_d[94]
 PIN k_li_d[95]
  DIRECTION OUTPUT ;
  USE SIGNAL ;
  PORT
   LAYER M5 ;
   RECT 23.472000 0.000000 23.496000 0.084000 ;
  END
 END k_li_d[95]
 PIN k_li_d[96]
  DIRECTION OUTPUT ;
  USE SIGNAL ;
  PORT
   LAYER M5 ;
   RECT 24.048000 0.000000 24.072000 0.084000 ;
  END
 END k_li_d[96]
 PIN k_li_d[97]
  DIRECTION OUTPUT ;
  USE SIGNAL ;
  PORT
   LAYER M5 ;
   RECT 24.096000 0.000000 24.120000 0.084000 ;
  END
 END k_li_d[97]
 PIN k_li_d[98]
  DIRECTION OUTPUT ;
  USE SIGNAL ;
  PORT
   LAYER M5 ;
   RECT 24.144000 0.000000 24.168000 0.084000 ;
  END
 END k_li_d[98]
 PIN k_li_d[99]
  DIRECTION OUTPUT ;
  USE SIGNAL ;
  PORT
   LAYER M5 ;
   RECT 24.336000 0.000000 24.360000 0.084000 ;
  END
 END k_li_d[99]
 PIN k_li_d[100]
  DIRECTION OUTPUT ;
  USE SIGNAL ;
  PORT
   LAYER M5 ;
   RECT 24.528000 0.000000 24.552000 0.084000 ;
  END
 END k_li_d[100]
 PIN k_li_d[101]
  DIRECTION OUTPUT ;
  USE SIGNAL ;
  PORT
   LAYER M5 ;
   RECT 24.672000 0.000000 24.696000 0.084000 ;
  END
 END k_li_d[101]
 PIN k_li_d[102]
  DIRECTION OUTPUT ;
  USE SIGNAL ;
  PORT
   LAYER M5 ;
   RECT 24.864000 0.000000 24.888000 0.084000 ;
  END
 END k_li_d[102]
 PIN k_li_d[103]
  DIRECTION OUTPUT ;
  USE SIGNAL ;
  PORT
   LAYER M5 ;
   RECT 25.056000 0.000000 25.080000 0.084000 ;
  END
 END k_li_d[103]
 PIN k_li_d[104]
  DIRECTION OUTPUT ;
  USE SIGNAL ;
  PORT
   LAYER M5 ;
   RECT 25.248000 0.000000 25.272000 0.084000 ;
  END
 END k_li_d[104]
 PIN k_li_d[105]
  DIRECTION OUTPUT ;
  USE SIGNAL ;
  PORT
   LAYER M5 ;
   RECT 25.392000 0.000000 25.416000 0.084000 ;
  END
 END k_li_d[105]
 PIN k_li_d[106]
  DIRECTION OUTPUT ;
  USE SIGNAL ;
  PORT
   LAYER M5 ;
   RECT 25.584000 0.000000 25.608000 0.084000 ;
  END
 END k_li_d[106]
 PIN k_li_d[107]
  DIRECTION OUTPUT ;
  USE SIGNAL ;
  PORT
   LAYER M5 ;
   RECT 25.776000 0.000000 25.800000 0.084000 ;
  END
 END k_li_d[107]
 PIN k_li_d[108]
  DIRECTION OUTPUT ;
  USE SIGNAL ;
  PORT
   LAYER M5 ;
   RECT 25.920000 0.000000 25.944000 0.084000 ;
  END
 END k_li_d[108]
 PIN k_li_d[109]
  DIRECTION OUTPUT ;
  USE SIGNAL ;
  PORT
   LAYER M5 ;
   RECT 26.112000 0.000000 26.136000 0.084000 ;
  END
 END k_li_d[109]
 PIN k_li_d[110]
  DIRECTION OUTPUT ;
  USE SIGNAL ;
  PORT
   LAYER M5 ;
   RECT 26.304000 0.000000 26.328000 0.084000 ;
  END
 END k_li_d[110]
 PIN k_li_d[111]
  DIRECTION OUTPUT ;
  USE SIGNAL ;
  PORT
   LAYER M5 ;
   RECT 26.496000 0.000000 26.520000 0.084000 ;
  END
 END k_li_d[111]
 PIN k_li_d[112]
  DIRECTION OUTPUT ;
  USE SIGNAL ;
  PORT
   LAYER M5 ;
   RECT 26.640000 0.000000 26.664000 0.084000 ;
  END
 END k_li_d[112]
 PIN k_li_d[113]
  DIRECTION OUTPUT ;
  USE SIGNAL ;
  PORT
   LAYER M5 ;
   RECT 26.832000 0.000000 26.856000 0.084000 ;
  END
 END k_li_d[113]
 PIN k_li_d[114]
  DIRECTION OUTPUT ;
  USE SIGNAL ;
  PORT
   LAYER M5 ;
   RECT 27.024000 0.000000 27.048000 0.084000 ;
  END
 END k_li_d[114]
 PIN k_li_d[115]
  DIRECTION OUTPUT ;
  USE SIGNAL ;
  PORT
   LAYER M5 ;
   RECT 27.216000 0.000000 27.240000 0.084000 ;
  END
 END k_li_d[115]
 PIN k_li_d[116]
  DIRECTION OUTPUT ;
  USE SIGNAL ;
  PORT
   LAYER M5 ;
   RECT 27.360000 0.000000 27.384000 0.084000 ;
  END
 END k_li_d[116]
 PIN k_li_d[117]
  DIRECTION OUTPUT ;
  USE SIGNAL ;
  PORT
   LAYER M5 ;
   RECT 27.552000 0.000000 27.576000 0.084000 ;
  END
 END k_li_d[117]
 PIN k_li_d[118]
  DIRECTION OUTPUT ;
  USE SIGNAL ;
  PORT
   LAYER M5 ;
   RECT 27.744000 0.000000 27.768000 0.084000 ;
  END
 END k_li_d[118]
 PIN k_li_d[119]
  DIRECTION OUTPUT ;
  USE SIGNAL ;
  PORT
   LAYER M5 ;
   RECT 27.792000 0.000000 27.816000 0.084000 ;
  END
 END k_li_d[119]
 PIN k_li_d[120]
  DIRECTION OUTPUT ;
  USE SIGNAL ;
  PORT
   LAYER M5 ;
   RECT 28.368000 0.000000 28.392000 0.084000 ;
  END
 END k_li_d[120]
 PIN k_li_d[121]
  DIRECTION OUTPUT ;
  USE SIGNAL ;
  PORT
   LAYER M5 ;
   RECT 28.416000 0.000000 28.440000 0.084000 ;
  END
 END k_li_d[121]
 PIN k_li_d[122]
  DIRECTION OUTPUT ;
  USE SIGNAL ;
  PORT
   LAYER M5 ;
   RECT 28.464000 0.000000 28.488000 0.084000 ;
  END
 END k_li_d[122]
 PIN k_li_d[123]
  DIRECTION OUTPUT ;
  USE SIGNAL ;
  PORT
   LAYER M5 ;
   RECT 28.608000 0.000000 28.632000 0.084000 ;
  END
 END k_li_d[123]
 PIN k_li_d[124]
  DIRECTION OUTPUT ;
  USE SIGNAL ;
  PORT
   LAYER M5 ;
   RECT 28.800000 0.000000 28.824000 0.084000 ;
  END
 END k_li_d[124]
 PIN k_li_d[125]
  DIRECTION OUTPUT ;
  USE SIGNAL ;
  PORT
   LAYER M5 ;
   RECT 28.992000 0.000000 29.016000 0.084000 ;
  END
 END k_li_d[125]
 PIN k_li_d[126]
  DIRECTION OUTPUT ;
  USE SIGNAL ;
  PORT
   LAYER M5 ;
   RECT 29.184000 0.000000 29.208000 0.084000 ;
  END
 END k_li_d[126]
 PIN k_li_d[127]
  DIRECTION OUTPUT ;
  USE SIGNAL ;
  PORT
   LAYER M5 ;
   RECT 29.328000 0.000000 29.352000 0.084000 ;
  END
 END k_li_d[127]
 PIN k_li_d[128]
  DIRECTION OUTPUT ;
  USE SIGNAL ;
  PORT
   LAYER M5 ;
   RECT 29.520000 0.000000 29.544000 0.084000 ;
  END
 END k_li_d[128]
 PIN k_li_d[129]
  DIRECTION OUTPUT ;
  USE SIGNAL ;
  PORT
   LAYER M5 ;
   RECT 29.712000 0.000000 29.736000 0.084000 ;
  END
 END k_li_d[129]
 PIN k_li_d[130]
  DIRECTION OUTPUT ;
  USE SIGNAL ;
  PORT
   LAYER M5 ;
   RECT 29.904000 0.000000 29.928000 0.084000 ;
  END
 END k_li_d[130]
 PIN k_li_d[131]
  DIRECTION OUTPUT ;
  USE SIGNAL ;
  PORT
   LAYER M5 ;
   RECT 30.048000 0.000000 30.072000 0.084000 ;
  END
 END k_li_d[131]
 PIN k_li_d[132]
  DIRECTION OUTPUT ;
  USE SIGNAL ;
  PORT
   LAYER M5 ;
   RECT 30.240000 0.000000 30.264000 0.084000 ;
  END
 END k_li_d[132]
 PIN k_li_d[133]
  DIRECTION OUTPUT ;
  USE SIGNAL ;
  PORT
   LAYER M5 ;
   RECT 30.432000 0.000000 30.456000 0.084000 ;
  END
 END k_li_d[133]
 PIN k_li_d[134]
  DIRECTION OUTPUT ;
  USE SIGNAL ;
  PORT
   LAYER M5 ;
   RECT 30.624000 0.000000 30.648000 0.084000 ;
  END
 END k_li_d[134]
 PIN k_li_d[135]
  DIRECTION OUTPUT ;
  USE SIGNAL ;
  PORT
   LAYER M5 ;
   RECT 30.768000 0.000000 30.792000 0.084000 ;
  END
 END k_li_d[135]
 PIN k_li_d[136]
  DIRECTION OUTPUT ;
  USE SIGNAL ;
  PORT
   LAYER M5 ;
   RECT 30.960000 0.000000 30.984000 0.084000 ;
  END
 END k_li_d[136]
 PIN k_li_d[137]
  DIRECTION OUTPUT ;
  USE SIGNAL ;
  PORT
   LAYER M5 ;
   RECT 31.152000 0.000000 31.176000 0.084000 ;
  END
 END k_li_d[137]
 PIN k_li_d[138]
  DIRECTION OUTPUT ;
  USE SIGNAL ;
  PORT
   LAYER M5 ;
   RECT 31.296000 0.000000 31.320000 0.084000 ;
  END
 END k_li_d[138]
 PIN k_li_d[139]
  DIRECTION OUTPUT ;
  USE SIGNAL ;
  PORT
   LAYER M5 ;
   RECT 31.488000 0.000000 31.512000 0.084000 ;
  END
 END k_li_d[139]
 PIN k_li_d[140]
  DIRECTION OUTPUT ;
  USE SIGNAL ;
  PORT
   LAYER M5 ;
   RECT 31.680000 0.000000 31.704000 0.084000 ;
  END
 END k_li_d[140]
 PIN k_li_d[141]
  DIRECTION OUTPUT ;
  USE SIGNAL ;
  PORT
   LAYER M5 ;
   RECT 31.872000 0.000000 31.896000 0.084000 ;
  END
 END k_li_d[141]
 PIN k_li_d[142]
  DIRECTION OUTPUT ;
  USE SIGNAL ;
  PORT
   LAYER M5 ;
   RECT 32.016000 0.000000 32.040000 0.084000 ;
  END
 END k_li_d[142]
 PIN k_li_d[143]
  DIRECTION OUTPUT ;
  USE SIGNAL ;
  PORT
   LAYER M5 ;
   RECT 32.112000 0.000000 32.136000 0.084000 ;
  END
 END k_li_d[143]
 PIN k_li_d[144]
  DIRECTION OUTPUT ;
  USE SIGNAL ;
  PORT
   LAYER M5 ;
   RECT 32.688000 0.000000 32.712000 0.084000 ;
  END
 END k_li_d[144]
 PIN k_li_d[145]
  DIRECTION OUTPUT ;
  USE SIGNAL ;
  PORT
   LAYER M5 ;
   RECT 32.736000 0.000000 32.760000 0.084000 ;
  END
 END k_li_d[145]
 PIN k_li_d[146]
  DIRECTION OUTPUT ;
  USE SIGNAL ;
  PORT
   LAYER M5 ;
   RECT 32.784000 0.000000 32.808000 0.084000 ;
  END
 END k_li_d[146]
 PIN k_li_d[147]
  DIRECTION OUTPUT ;
  USE SIGNAL ;
  PORT
   LAYER M5 ;
   RECT 32.928000 0.000000 32.952000 0.084000 ;
  END
 END k_li_d[147]
 PIN k_li_d[148]
  DIRECTION OUTPUT ;
  USE SIGNAL ;
  PORT
   LAYER M5 ;
   RECT 33.120000 0.000000 33.144000 0.084000 ;
  END
 END k_li_d[148]
 PIN k_li_d[149]
  DIRECTION OUTPUT ;
  USE SIGNAL ;
  PORT
   LAYER M5 ;
   RECT 33.312000 0.000000 33.336000 0.084000 ;
  END
 END k_li_d[149]
 PIN k_li_d[150]
  DIRECTION OUTPUT ;
  USE SIGNAL ;
  PORT
   LAYER M5 ;
   RECT 33.456000 0.000000 33.480000 0.084000 ;
  END
 END k_li_d[150]
 PIN k_li_d[151]
  DIRECTION OUTPUT ;
  USE SIGNAL ;
  PORT
   LAYER M5 ;
   RECT 33.648000 0.000000 33.672000 0.084000 ;
  END
 END k_li_d[151]
 PIN k_li_d[152]
  DIRECTION OUTPUT ;
  USE SIGNAL ;
  PORT
   LAYER M5 ;
   RECT 33.840000 0.000000 33.864000 0.084000 ;
  END
 END k_li_d[152]
 PIN k_li_d[153]
  DIRECTION OUTPUT ;
  USE SIGNAL ;
  PORT
   LAYER M5 ;
   RECT 34.032000 0.000000 34.056000 0.084000 ;
  END
 END k_li_d[153]
 PIN k_li_d[154]
  DIRECTION OUTPUT ;
  USE SIGNAL ;
  PORT
   LAYER M5 ;
   RECT 34.176000 0.000000 34.200000 0.084000 ;
  END
 END k_li_d[154]
 PIN k_li_d[155]
  DIRECTION OUTPUT ;
  USE SIGNAL ;
  PORT
   LAYER M5 ;
   RECT 34.368000 0.000000 34.392000 0.084000 ;
  END
 END k_li_d[155]
 PIN k_li_d[156]
  DIRECTION OUTPUT ;
  USE SIGNAL ;
  PORT
   LAYER M5 ;
   RECT 34.560000 0.000000 34.584000 0.084000 ;
  END
 END k_li_d[156]
 PIN k_li_d[157]
  DIRECTION OUTPUT ;
  USE SIGNAL ;
  PORT
   LAYER M5 ;
   RECT 34.704000 0.000000 34.728000 0.084000 ;
  END
 END k_li_d[157]
 PIN k_li_d[158]
  DIRECTION OUTPUT ;
  USE SIGNAL ;
  PORT
   LAYER M5 ;
   RECT 34.896000 0.000000 34.920000 0.084000 ;
  END
 END k_li_d[158]
 PIN k_li_d[159]
  DIRECTION OUTPUT ;
  USE SIGNAL ;
  PORT
   LAYER M5 ;
   RECT 35.088000 0.000000 35.112000 0.084000 ;
  END
 END k_li_d[159]
 PIN k_li_d[160]
  DIRECTION OUTPUT ;
  USE SIGNAL ;
  PORT
   LAYER M5 ;
   RECT 35.280000 0.000000 35.304000 0.084000 ;
  END
 END k_li_d[160]
 PIN k_li_d[161]
  DIRECTION OUTPUT ;
  USE SIGNAL ;
  PORT
   LAYER M5 ;
   RECT 35.424000 0.000000 35.448000 0.084000 ;
  END
 END k_li_d[161]
 PIN k_li_d[162]
  DIRECTION OUTPUT ;
  USE SIGNAL ;
  PORT
   LAYER M5 ;
   RECT 35.616000 0.000000 35.640000 0.084000 ;
  END
 END k_li_d[162]
 PIN k_li_d[163]
  DIRECTION OUTPUT ;
  USE SIGNAL ;
  PORT
   LAYER M5 ;
   RECT 35.808000 0.000000 35.832000 0.084000 ;
  END
 END k_li_d[163]
 PIN k_li_d[164]
  DIRECTION OUTPUT ;
  USE SIGNAL ;
  PORT
   LAYER M5 ;
   RECT 36.000000 0.000000 36.024000 0.084000 ;
  END
 END k_li_d[164]
 PIN k_li_d[165]
  DIRECTION OUTPUT ;
  USE SIGNAL ;
  PORT
   LAYER M5 ;
   RECT 36.144000 0.000000 36.168000 0.084000 ;
  END
 END k_li_d[165]
 PIN k_li_d[166]
  DIRECTION OUTPUT ;
  USE SIGNAL ;
  PORT
   LAYER M5 ;
   RECT 36.336000 0.000000 36.360000 0.084000 ;
  END
 END k_li_d[166]
 PIN k_li_d[167]
  DIRECTION OUTPUT ;
  USE SIGNAL ;
  PORT
   LAYER M5 ;
   RECT 36.432000 0.000000 36.456000 0.084000 ;
  END
 END k_li_d[167]
 PIN k_li_d[168]
  DIRECTION OUTPUT ;
  USE SIGNAL ;
  PORT
   LAYER M5 ;
   RECT 37.008000 0.000000 37.032000 0.084000 ;
  END
 END k_li_d[168]
 PIN k_li_d[169]
  DIRECTION OUTPUT ;
  USE SIGNAL ;
  PORT
   LAYER M5 ;
   RECT 37.056000 0.000000 37.080000 0.084000 ;
  END
 END k_li_d[169]
 PIN k_li_d[170]
  DIRECTION OUTPUT ;
  USE SIGNAL ;
  PORT
   LAYER M5 ;
   RECT 37.104000 0.000000 37.128000 0.084000 ;
  END
 END k_li_d[170]
 PIN k_li_d[171]
  DIRECTION OUTPUT ;
  USE SIGNAL ;
  PORT
   LAYER M5 ;
   RECT 37.248000 0.000000 37.272000 0.084000 ;
  END
 END k_li_d[171]
 PIN k_li_d[172]
  DIRECTION OUTPUT ;
  USE SIGNAL ;
  PORT
   LAYER M5 ;
   RECT 37.392000 0.000000 37.416000 0.084000 ;
  END
 END k_li_d[172]
 PIN k_li_d[173]
  DIRECTION OUTPUT ;
  USE SIGNAL ;
  PORT
   LAYER M5 ;
   RECT 37.584000 0.000000 37.608000 0.084000 ;
  END
 END k_li_d[173]
 PIN k_li_d[174]
  DIRECTION OUTPUT ;
  USE SIGNAL ;
  PORT
   LAYER M5 ;
   RECT 37.776000 0.000000 37.800000 0.084000 ;
  END
 END k_li_d[174]
 PIN k_li_d[175]
  DIRECTION OUTPUT ;
  USE SIGNAL ;
  PORT
   LAYER M5 ;
   RECT 37.968000 0.000000 37.992000 0.084000 ;
  END
 END k_li_d[175]
 PIN k_li_d[176]
  DIRECTION OUTPUT ;
  USE SIGNAL ;
  PORT
   LAYER M5 ;
   RECT 38.112000 0.000000 38.136000 0.084000 ;
  END
 END k_li_d[176]
 PIN k_li_d[177]
  DIRECTION OUTPUT ;
  USE SIGNAL ;
  PORT
   LAYER M5 ;
   RECT 38.304000 0.000000 38.328000 0.084000 ;
  END
 END k_li_d[177]
 PIN k_li_d[178]
  DIRECTION OUTPUT ;
  USE SIGNAL ;
  PORT
   LAYER M5 ;
   RECT 38.496000 0.000000 38.520000 0.084000 ;
  END
 END k_li_d[178]
 PIN k_li_d[179]
  DIRECTION OUTPUT ;
  USE SIGNAL ;
  PORT
   LAYER M5 ;
   RECT 38.688000 0.000000 38.712000 0.084000 ;
  END
 END k_li_d[179]
 PIN k_li_d[180]
  DIRECTION OUTPUT ;
  USE SIGNAL ;
  PORT
   LAYER M5 ;
   RECT 38.832000 0.000000 38.856000 0.084000 ;
  END
 END k_li_d[180]
 PIN k_li_d[181]
  DIRECTION OUTPUT ;
  USE SIGNAL ;
  PORT
   LAYER M5 ;
   RECT 39.024000 0.000000 39.048000 0.084000 ;
  END
 END k_li_d[181]
 PIN k_li_d[182]
  DIRECTION OUTPUT ;
  USE SIGNAL ;
  PORT
   LAYER M5 ;
   RECT 39.216000 0.000000 39.240000 0.084000 ;
  END
 END k_li_d[182]
 PIN k_li_d[183]
  DIRECTION OUTPUT ;
  USE SIGNAL ;
  PORT
   LAYER M5 ;
   RECT 39.408000 0.000000 39.432000 0.084000 ;
  END
 END k_li_d[183]
 PIN k_li_d[184]
  DIRECTION OUTPUT ;
  USE SIGNAL ;
  PORT
   LAYER M5 ;
   RECT 39.552000 0.000000 39.576000 0.084000 ;
  END
 END k_li_d[184]
 PIN k_li_d[185]
  DIRECTION OUTPUT ;
  USE SIGNAL ;
  PORT
   LAYER M5 ;
   RECT 39.744000 0.000000 39.768000 0.084000 ;
  END
 END k_li_d[185]
 PIN k_li_d[186]
  DIRECTION OUTPUT ;
  USE SIGNAL ;
  PORT
   LAYER M5 ;
   RECT 39.936000 0.000000 39.960000 0.084000 ;
  END
 END k_li_d[186]
 PIN k_li_d[187]
  DIRECTION OUTPUT ;
  USE SIGNAL ;
  PORT
   LAYER M5 ;
   RECT 40.080000 0.000000 40.104000 0.084000 ;
  END
 END k_li_d[187]
 PIN k_li_d[188]
  DIRECTION OUTPUT ;
  USE SIGNAL ;
  PORT
   LAYER M5 ;
   RECT 40.272000 0.000000 40.296000 0.084000 ;
  END
 END k_li_d[188]
 PIN k_li_d[189]
  DIRECTION OUTPUT ;
  USE SIGNAL ;
  PORT
   LAYER M5 ;
   RECT 40.464000 0.000000 40.488000 0.084000 ;
  END
 END k_li_d[189]
 PIN k_li_d[190]
  DIRECTION OUTPUT ;
  USE SIGNAL ;
  PORT
   LAYER M5 ;
   RECT 40.656000 0.000000 40.680000 0.084000 ;
  END
 END k_li_d[190]
 PIN k_li_d[191]
  DIRECTION OUTPUT ;
  USE SIGNAL ;
  PORT
   LAYER M5 ;
   RECT 40.752000 0.000000 40.776000 0.084000 ;
  END
 END k_li_d[191]
 PIN k_li_d[192]
  DIRECTION OUTPUT ;
  USE SIGNAL ;
  PORT
   LAYER M5 ;
   RECT 41.328000 0.000000 41.352000 0.084000 ;
  END
 END k_li_d[192]
 PIN k_li_d[193]
  DIRECTION OUTPUT ;
  USE SIGNAL ;
  PORT
   LAYER M5 ;
   RECT 41.376000 0.000000 41.400000 0.084000 ;
  END
 END k_li_d[193]
 PIN k_li_d[194]
  DIRECTION OUTPUT ;
  USE SIGNAL ;
  PORT
   LAYER M5 ;
   RECT 41.424000 0.000000 41.448000 0.084000 ;
  END
 END k_li_d[194]
 PIN k_li_d[195]
  DIRECTION OUTPUT ;
  USE SIGNAL ;
  PORT
   LAYER M5 ;
   RECT 41.520000 0.000000 41.544000 0.084000 ;
  END
 END k_li_d[195]
 PIN k_li_d[196]
  DIRECTION OUTPUT ;
  USE SIGNAL ;
  PORT
   LAYER M5 ;
   RECT 41.712000 0.000000 41.736000 0.084000 ;
  END
 END k_li_d[196]
 PIN k_li_d[197]
  DIRECTION OUTPUT ;
  USE SIGNAL ;
  PORT
   LAYER M5 ;
   RECT 41.904000 0.000000 41.928000 0.084000 ;
  END
 END k_li_d[197]
 PIN k_li_d[198]
  DIRECTION OUTPUT ;
  USE SIGNAL ;
  PORT
   LAYER M5 ;
   RECT 42.096000 0.000000 42.120000 0.084000 ;
  END
 END k_li_d[198]
 PIN k_li_d[199]
  DIRECTION OUTPUT ;
  USE SIGNAL ;
  PORT
   LAYER M5 ;
   RECT 42.240000 0.000000 42.264000 0.084000 ;
  END
 END k_li_d[199]
 PIN k_li_d[200]
  DIRECTION OUTPUT ;
  USE SIGNAL ;
  PORT
   LAYER M5 ;
   RECT 42.432000 0.000000 42.456000 0.084000 ;
  END
 END k_li_d[200]
 PIN k_li_d[201]
  DIRECTION OUTPUT ;
  USE SIGNAL ;
  PORT
   LAYER M5 ;
   RECT 42.624000 0.000000 42.648000 0.084000 ;
  END
 END k_li_d[201]
 PIN k_li_d[202]
  DIRECTION OUTPUT ;
  USE SIGNAL ;
  PORT
   LAYER M5 ;
   RECT 42.816000 0.000000 42.840000 0.084000 ;
  END
 END k_li_d[202]
 PIN k_li_d[203]
  DIRECTION OUTPUT ;
  USE SIGNAL ;
  PORT
   LAYER M5 ;
   RECT 42.960000 0.000000 42.984000 0.084000 ;
  END
 END k_li_d[203]
 PIN k_li_d[204]
  DIRECTION OUTPUT ;
  USE SIGNAL ;
  PORT
   LAYER M5 ;
   RECT 43.152000 0.000000 43.176000 0.084000 ;
  END
 END k_li_d[204]
 PIN k_li_d[205]
  DIRECTION OUTPUT ;
  USE SIGNAL ;
  PORT
   LAYER M5 ;
   RECT 43.344000 0.000000 43.368000 0.084000 ;
  END
 END k_li_d[205]
 PIN k_li_d[206]
  DIRECTION OUTPUT ;
  USE SIGNAL ;
  PORT
   LAYER M5 ;
   RECT 43.488000 0.000000 43.512000 0.084000 ;
  END
 END k_li_d[206]
 PIN k_li_d[207]
  DIRECTION OUTPUT ;
  USE SIGNAL ;
  PORT
   LAYER M5 ;
   RECT 43.680000 0.000000 43.704000 0.084000 ;
  END
 END k_li_d[207]
 PIN k_li_d[208]
  DIRECTION OUTPUT ;
  USE SIGNAL ;
  PORT
   LAYER M5 ;
   RECT 43.872000 0.000000 43.896000 0.084000 ;
  END
 END k_li_d[208]
 PIN k_li_d[209]
  DIRECTION OUTPUT ;
  USE SIGNAL ;
  PORT
   LAYER M5 ;
   RECT 44.064000 0.000000 44.088000 0.084000 ;
  END
 END k_li_d[209]
 PIN k_li_d[210]
  DIRECTION OUTPUT ;
  USE SIGNAL ;
  PORT
   LAYER M5 ;
   RECT 44.208000 0.000000 44.232000 0.084000 ;
  END
 END k_li_d[210]
 PIN k_li_d[211]
  DIRECTION OUTPUT ;
  USE SIGNAL ;
  PORT
   LAYER M5 ;
   RECT 44.400000 0.000000 44.424000 0.084000 ;
  END
 END k_li_d[211]
 PIN k_li_d[212]
  DIRECTION OUTPUT ;
  USE SIGNAL ;
  PORT
   LAYER M5 ;
   RECT 44.592000 0.000000 44.616000 0.084000 ;
  END
 END k_li_d[212]
 PIN k_li_d[213]
  DIRECTION OUTPUT ;
  USE SIGNAL ;
  PORT
   LAYER M5 ;
   RECT 44.784000 0.000000 44.808000 0.084000 ;
  END
 END k_li_d[213]
 PIN k_li_d[214]
  DIRECTION OUTPUT ;
  USE SIGNAL ;
  PORT
   LAYER M5 ;
   RECT 44.928000 0.000000 44.952000 0.084000 ;
  END
 END k_li_d[214]
 PIN k_li_d[215]
  DIRECTION OUTPUT ;
  USE SIGNAL ;
  PORT
   LAYER M5 ;
   RECT 45.072000 0.000000 45.096000 0.084000 ;
  END
 END k_li_d[215]
 PIN k_li_d[216]
  DIRECTION OUTPUT ;
  USE SIGNAL ;
  PORT
   LAYER M5 ;
   RECT 45.648000 0.000000 45.672000 0.084000 ;
  END
 END k_li_d[216]
 PIN k_li_d[217]
  DIRECTION OUTPUT ;
  USE SIGNAL ;
  PORT
   LAYER M5 ;
   RECT 45.696000 0.000000 45.720000 0.084000 ;
  END
 END k_li_d[217]
 PIN k_li_d[218]
  DIRECTION OUTPUT ;
  USE SIGNAL ;
  PORT
   LAYER M5 ;
   RECT 45.744000 0.000000 45.768000 0.084000 ;
  END
 END k_li_d[218]
 PIN k_li_d[219]
  DIRECTION OUTPUT ;
  USE SIGNAL ;
  PORT
   LAYER M5 ;
   RECT 45.840000 0.000000 45.864000 0.084000 ;
  END
 END k_li_d[219]
 PIN k_li_d[220]
  DIRECTION OUTPUT ;
  USE SIGNAL ;
  PORT
   LAYER M5 ;
   RECT 46.032000 0.000000 46.056000 0.084000 ;
  END
 END k_li_d[220]
 PIN k_li_d[221]
  DIRECTION OUTPUT ;
  USE SIGNAL ;
  PORT
   LAYER M5 ;
   RECT 46.176000 0.000000 46.200000 0.084000 ;
  END
 END k_li_d[221]
 PIN k_li_d[222]
  DIRECTION OUTPUT ;
  USE SIGNAL ;
  PORT
   LAYER M5 ;
   RECT 46.368000 0.000000 46.392000 0.084000 ;
  END
 END k_li_d[222]
 PIN k_li_d[223]
  DIRECTION OUTPUT ;
  USE SIGNAL ;
  PORT
   LAYER M5 ;
   RECT 46.560000 0.000000 46.584000 0.084000 ;
  END
 END k_li_d[223]
 PIN k_li_d[224]
  DIRECTION OUTPUT ;
  USE SIGNAL ;
  PORT
   LAYER M5 ;
   RECT 46.752000 0.000000 46.776000 0.084000 ;
  END
 END k_li_d[224]
 PIN k_li_d[225]
  DIRECTION OUTPUT ;
  USE SIGNAL ;
  PORT
   LAYER M5 ;
   RECT 46.896000 0.000000 46.920000 0.084000 ;
  END
 END k_li_d[225]
 PIN k_li_d[226]
  DIRECTION OUTPUT ;
  USE SIGNAL ;
  PORT
   LAYER M5 ;
   RECT 47.088000 0.000000 47.112000 0.084000 ;
  END
 END k_li_d[226]
 PIN k_li_d[227]
  DIRECTION OUTPUT ;
  USE SIGNAL ;
  PORT
   LAYER M5 ;
   RECT 47.280000 0.000000 47.304000 0.084000 ;
  END
 END k_li_d[227]
 PIN k_li_d[228]
  DIRECTION OUTPUT ;
  USE SIGNAL ;
  PORT
   LAYER M5 ;
   RECT 47.472000 0.000000 47.496000 0.084000 ;
  END
 END k_li_d[228]
 PIN k_li_d[229]
  DIRECTION OUTPUT ;
  USE SIGNAL ;
  PORT
   LAYER M5 ;
   RECT 47.616000 0.000000 47.640000 0.084000 ;
  END
 END k_li_d[229]
 PIN k_li_d[230]
  DIRECTION OUTPUT ;
  USE SIGNAL ;
  PORT
   LAYER M5 ;
   RECT 47.808000 0.000000 47.832000 0.084000 ;
  END
 END k_li_d[230]
 PIN k_li_d[231]
  DIRECTION OUTPUT ;
  USE SIGNAL ;
  PORT
   LAYER M5 ;
   RECT 48.000000 0.000000 48.024000 0.084000 ;
  END
 END k_li_d[231]
 PIN k_li_d[232]
  DIRECTION OUTPUT ;
  USE SIGNAL ;
  PORT
   LAYER M5 ;
   RECT 48.192000 0.000000 48.216000 0.084000 ;
  END
 END k_li_d[232]
 PIN k_li_d[233]
  DIRECTION OUTPUT ;
  USE SIGNAL ;
  PORT
   LAYER M5 ;
   RECT 48.336000 0.000000 48.360000 0.084000 ;
  END
 END k_li_d[233]
 PIN k_li_d[234]
  DIRECTION OUTPUT ;
  USE SIGNAL ;
  PORT
   LAYER M5 ;
   RECT 48.528000 0.000000 48.552000 0.084000 ;
  END
 END k_li_d[234]
 PIN k_li_d[235]
  DIRECTION OUTPUT ;
  USE SIGNAL ;
  PORT
   LAYER M5 ;
   RECT 48.720000 0.000000 48.744000 0.084000 ;
  END
 END k_li_d[235]
 PIN k_li_d[236]
  DIRECTION OUTPUT ;
  USE SIGNAL ;
  PORT
   LAYER M5 ;
   RECT 48.864000 0.000000 48.888000 0.084000 ;
  END
 END k_li_d[236]
 PIN k_li_d[237]
  DIRECTION OUTPUT ;
  USE SIGNAL ;
  PORT
   LAYER M5 ;
   RECT 49.056000 0.000000 49.080000 0.084000 ;
  END
 END k_li_d[237]
 PIN k_li_d[238]
  DIRECTION OUTPUT ;
  USE SIGNAL ;
  PORT
   LAYER M5 ;
   RECT 49.248000 0.000000 49.272000 0.084000 ;
  END
 END k_li_d[238]
 PIN k_li_d[239]
  DIRECTION OUTPUT ;
  USE SIGNAL ;
  PORT
   LAYER M5 ;
   RECT 49.392000 0.000000 49.416000 0.084000 ;
  END
 END k_li_d[239]
 PIN k_li_d[240]
  DIRECTION OUTPUT ;
  USE SIGNAL ;
  PORT
   LAYER M5 ;
   RECT 49.968000 0.000000 49.992000 0.084000 ;
  END
 END k_li_d[240]
 PIN k_li_d[241]
  DIRECTION OUTPUT ;
  USE SIGNAL ;
  PORT
   LAYER M5 ;
   RECT 50.016000 0.000000 50.040000 0.084000 ;
  END
 END k_li_d[241]
 PIN k_li_d[242]
  DIRECTION OUTPUT ;
  USE SIGNAL ;
  PORT
   LAYER M5 ;
   RECT 50.064000 0.000000 50.088000 0.084000 ;
  END
 END k_li_d[242]
 PIN k_li_d[243]
  DIRECTION OUTPUT ;
  USE SIGNAL ;
  PORT
   LAYER M5 ;
   RECT 50.160000 0.000000 50.184000 0.084000 ;
  END
 END k_li_d[243]
 PIN k_li_d[244]
  DIRECTION OUTPUT ;
  USE SIGNAL ;
  PORT
   LAYER M5 ;
   RECT 50.304000 0.000000 50.328000 0.084000 ;
  END
 END k_li_d[244]
 PIN k_li_d[245]
  DIRECTION OUTPUT ;
  USE SIGNAL ;
  PORT
   LAYER M5 ;
   RECT 50.496000 0.000000 50.520000 0.084000 ;
  END
 END k_li_d[245]
 PIN k_li_d[246]
  DIRECTION OUTPUT ;
  USE SIGNAL ;
  PORT
   LAYER M5 ;
   RECT 50.688000 0.000000 50.712000 0.084000 ;
  END
 END k_li_d[246]
 PIN k_li_d[247]
  DIRECTION OUTPUT ;
  USE SIGNAL ;
  PORT
   LAYER M5 ;
   RECT 50.880000 0.000000 50.904000 0.084000 ;
  END
 END k_li_d[247]
 PIN k_li_d[248]
  DIRECTION OUTPUT ;
  USE SIGNAL ;
  PORT
   LAYER M5 ;
   RECT 51.024000 0.000000 51.048000 0.084000 ;
  END
 END k_li_d[248]
 PIN k_li_d[249]
  DIRECTION OUTPUT ;
  USE SIGNAL ;
  PORT
   LAYER M5 ;
   RECT 51.216000 0.000000 51.240000 0.084000 ;
  END
 END k_li_d[249]
 PIN k_li_d[250]
  DIRECTION OUTPUT ;
  USE SIGNAL ;
  PORT
   LAYER M5 ;
   RECT 51.408000 0.000000 51.432000 0.084000 ;
  END
 END k_li_d[250]
 PIN k_li_d[251]
  DIRECTION OUTPUT ;
  USE SIGNAL ;
  PORT
   LAYER M5 ;
   RECT 51.600000 0.000000 51.624000 0.084000 ;
  END
 END k_li_d[251]
 PIN k_li_d[252]
  DIRECTION OUTPUT ;
  USE SIGNAL ;
  PORT
   LAYER M5 ;
   RECT 51.744000 0.000000 51.768000 0.084000 ;
  END
 END k_li_d[252]
 PIN k_li_d[253]
  DIRECTION OUTPUT ;
  USE SIGNAL ;
  PORT
   LAYER M5 ;
   RECT 51.936000 0.000000 51.960000 0.084000 ;
  END
 END k_li_d[253]
 PIN k_li_d[254]
  DIRECTION OUTPUT ;
  USE SIGNAL ;
  PORT
   LAYER M5 ;
   RECT 52.128000 0.000000 52.152000 0.084000 ;
  END
 END k_li_d[254]
 PIN k_li_d[255]
  DIRECTION OUTPUT ;
  USE SIGNAL ;
  PORT
   LAYER M5 ;
   RECT 52.272000 0.000000 52.296000 0.084000 ;
  END
 END k_li_d[255]
 PIN k_li_d[256]
  DIRECTION OUTPUT ;
  USE SIGNAL ;
  PORT
   LAYER M5 ;
   RECT 52.464000 0.000000 52.488000 0.084000 ;
  END
 END k_li_d[256]
 PIN k_li_d[257]
  DIRECTION OUTPUT ;
  USE SIGNAL ;
  PORT
   LAYER M5 ;
   RECT 52.656000 0.000000 52.680000 0.084000 ;
  END
 END k_li_d[257]
 PIN k_li_d[258]
  DIRECTION OUTPUT ;
  USE SIGNAL ;
  PORT
   LAYER M5 ;
   RECT 52.848000 0.000000 52.872000 0.084000 ;
  END
 END k_li_d[258]
 PIN k_li_d[259]
  DIRECTION OUTPUT ;
  USE SIGNAL ;
  PORT
   LAYER M5 ;
   RECT 52.992000 0.000000 53.016000 0.084000 ;
  END
 END k_li_d[259]
 PIN k_li_d[260]
  DIRECTION OUTPUT ;
  USE SIGNAL ;
  PORT
   LAYER M5 ;
   RECT 53.184000 0.000000 53.208000 0.084000 ;
  END
 END k_li_d[260]
 PIN k_li_d[261]
  DIRECTION OUTPUT ;
  USE SIGNAL ;
  PORT
   LAYER M5 ;
   RECT 53.376000 0.000000 53.400000 0.084000 ;
  END
 END k_li_d[261]
 PIN k_li_d[262]
  DIRECTION OUTPUT ;
  USE SIGNAL ;
  PORT
   LAYER M5 ;
   RECT 53.568000 0.000000 53.592000 0.084000 ;
  END
 END k_li_d[262]
 PIN k_li_d[263]
  DIRECTION OUTPUT ;
  USE SIGNAL ;
  PORT
   LAYER M5 ;
   RECT 53.712000 0.000000 53.736000 0.084000 ;
  END
 END k_li_d[263]
 PIN k_li_d[264]
  DIRECTION OUTPUT ;
  USE SIGNAL ;
  PORT
   LAYER M5 ;
   RECT 54.288000 0.000000 54.312000 0.084000 ;
  END
 END k_li_d[264]
 PIN k_li_d[265]
  DIRECTION OUTPUT ;
  USE SIGNAL ;
  PORT
   LAYER M5 ;
   RECT 54.336000 0.000000 54.360000 0.084000 ;
  END
 END k_li_d[265]
 PIN k_li_d[266]
  DIRECTION OUTPUT ;
  USE SIGNAL ;
  PORT
   LAYER M5 ;
   RECT 54.384000 0.000000 54.408000 0.084000 ;
  END
 END k_li_d[266]
 PIN k_li_d[267]
  DIRECTION OUTPUT ;
  USE SIGNAL ;
  PORT
   LAYER M5 ;
   RECT 54.432000 0.000000 54.456000 0.084000 ;
  END
 END k_li_d[267]
 PIN k_li_d[268]
  DIRECTION OUTPUT ;
  USE SIGNAL ;
  PORT
   LAYER M5 ;
   RECT 54.624000 0.000000 54.648000 0.084000 ;
  END
 END k_li_d[268]
 PIN k_li_d[269]
  DIRECTION OUTPUT ;
  USE SIGNAL ;
  PORT
   LAYER M5 ;
   RECT 54.816000 0.000000 54.840000 0.084000 ;
  END
 END k_li_d[269]
 PIN k_li_d[270]
  DIRECTION OUTPUT ;
  USE SIGNAL ;
  PORT
   LAYER M5 ;
   RECT 54.960000 0.000000 54.984000 0.084000 ;
  END
 END k_li_d[270]
 PIN k_li_d[271]
  DIRECTION OUTPUT ;
  USE SIGNAL ;
  PORT
   LAYER M5 ;
   RECT 55.152000 0.000000 55.176000 0.084000 ;
  END
 END k_li_d[271]
 PIN k_li_d[272]
  DIRECTION OUTPUT ;
  USE SIGNAL ;
  PORT
   LAYER M5 ;
   RECT 55.344000 0.000000 55.368000 0.084000 ;
  END
 END k_li_d[272]
 PIN k_li_d[273]
  DIRECTION OUTPUT ;
  USE SIGNAL ;
  PORT
   LAYER M5 ;
   RECT 55.536000 0.000000 55.560000 0.084000 ;
  END
 END k_li_d[273]
 PIN k_li_d[274]
  DIRECTION OUTPUT ;
  USE SIGNAL ;
  PORT
   LAYER M5 ;
   RECT 55.680000 0.000000 55.704000 0.084000 ;
  END
 END k_li_d[274]
 PIN k_li_d[275]
  DIRECTION OUTPUT ;
  USE SIGNAL ;
  PORT
   LAYER M5 ;
   RECT 55.872000 0.000000 55.896000 0.084000 ;
  END
 END k_li_d[275]
 PIN k_li_d[276]
  DIRECTION OUTPUT ;
  USE SIGNAL ;
  PORT
   LAYER M5 ;
   RECT 56.064000 0.000000 56.088000 0.084000 ;
  END
 END k_li_d[276]
 PIN k_li_d[277]
  DIRECTION OUTPUT ;
  USE SIGNAL ;
  PORT
   LAYER M5 ;
   RECT 56.256000 0.000000 56.280000 0.084000 ;
  END
 END k_li_d[277]
 PIN k_li_d[278]
  DIRECTION OUTPUT ;
  USE SIGNAL ;
  PORT
   LAYER M5 ;
   RECT 56.400000 0.000000 56.424000 0.084000 ;
  END
 END k_li_d[278]
 PIN k_li_d[279]
  DIRECTION OUTPUT ;
  USE SIGNAL ;
  PORT
   LAYER M5 ;
   RECT 56.592000 0.000000 56.616000 0.084000 ;
  END
 END k_li_d[279]
 PIN k_li_d[280]
  DIRECTION OUTPUT ;
  USE SIGNAL ;
  PORT
   LAYER M5 ;
   RECT 56.784000 0.000000 56.808000 0.084000 ;
  END
 END k_li_d[280]
 PIN k_li_d[281]
  DIRECTION OUTPUT ;
  USE SIGNAL ;
  PORT
   LAYER M5 ;
   RECT 56.976000 0.000000 57.000000 0.084000 ;
  END
 END k_li_d[281]
 PIN k_li_d[282]
  DIRECTION OUTPUT ;
  USE SIGNAL ;
  PORT
   LAYER M5 ;
   RECT 57.120000 0.000000 57.144000 0.084000 ;
  END
 END k_li_d[282]
 PIN k_li_d[283]
  DIRECTION OUTPUT ;
  USE SIGNAL ;
  PORT
   LAYER M5 ;
   RECT 57.312000 0.000000 57.336000 0.084000 ;
  END
 END k_li_d[283]
 PIN k_li_d[284]
  DIRECTION OUTPUT ;
  USE SIGNAL ;
  PORT
   LAYER M5 ;
   RECT 57.504000 0.000000 57.528000 0.084000 ;
  END
 END k_li_d[284]
 PIN k_li_d[285]
  DIRECTION OUTPUT ;
  USE SIGNAL ;
  PORT
   LAYER M5 ;
   RECT 57.648000 0.000000 57.672000 0.084000 ;
  END
 END k_li_d[285]
 PIN k_li_d[286]
  DIRECTION OUTPUT ;
  USE SIGNAL ;
  PORT
   LAYER M5 ;
   RECT 57.840000 0.000000 57.864000 0.084000 ;
  END
 END k_li_d[286]
 PIN k_li_d[287]
  DIRECTION OUTPUT ;
  USE SIGNAL ;
  PORT
   LAYER M5 ;
   RECT 57.936000 0.000000 57.960000 0.084000 ;
  END
 END k_li_d[287]
 PIN k_li_d[288]
  DIRECTION OUTPUT ;
  USE SIGNAL ;
  PORT
   LAYER M5 ;
   RECT 57.984000 0.000000 58.008000 0.084000 ;
  END
 END k_li_d[288]
 PIN k_li_d[289]
  DIRECTION OUTPUT ;
  USE SIGNAL ;
  PORT
   LAYER M5 ;
   RECT 58.032000 0.000000 58.056000 0.084000 ;
  END
 END k_li_d[289]
 PIN k_li_d[290]
  DIRECTION OUTPUT ;
  USE SIGNAL ;
  PORT
   LAYER M5 ;
   RECT 58.608000 0.000000 58.632000 0.084000 ;
  END
 END k_li_d[290]
 PIN k_li_d[291]
  DIRECTION OUTPUT ;
  USE SIGNAL ;
  PORT
   LAYER M5 ;
   RECT 58.752000 0.000000 58.776000 0.084000 ;
  END
 END k_li_d[291]
 PIN k_li_d[292]
  DIRECTION OUTPUT ;
  USE SIGNAL ;
  PORT
   LAYER M5 ;
   RECT 58.944000 0.000000 58.968000 0.084000 ;
  END
 END k_li_d[292]
 PIN k_li_d[293]
  DIRECTION OUTPUT ;
  USE SIGNAL ;
  PORT
   LAYER M5 ;
   RECT 59.088000 0.000000 59.112000 0.084000 ;
  END
 END k_li_d[293]
 PIN k_li_d[294]
  DIRECTION OUTPUT ;
  USE SIGNAL ;
  PORT
   LAYER M5 ;
   RECT 59.280000 0.000000 59.304000 0.084000 ;
  END
 END k_li_d[294]
 PIN k_li_d[295]
  DIRECTION OUTPUT ;
  USE SIGNAL ;
  PORT
   LAYER M5 ;
   RECT 59.472000 0.000000 59.496000 0.084000 ;
  END
 END k_li_d[295]
 PIN k_li_d[296]
  DIRECTION OUTPUT ;
  USE SIGNAL ;
  PORT
   LAYER M5 ;
   RECT 59.664000 0.000000 59.688000 0.084000 ;
  END
 END k_li_d[296]
 PIN k_li_d[297]
  DIRECTION OUTPUT ;
  USE SIGNAL ;
  PORT
   LAYER M5 ;
   RECT 59.808000 0.000000 59.832000 0.084000 ;
  END
 END k_li_d[297]
 PIN k_li_d[298]
  DIRECTION OUTPUT ;
  USE SIGNAL ;
  PORT
   LAYER M5 ;
   RECT 60.000000 0.000000 60.024000 0.084000 ;
  END
 END k_li_d[298]
 PIN k_li_d[299]
  DIRECTION OUTPUT ;
  USE SIGNAL ;
  PORT
   LAYER M5 ;
   RECT 60.192000 0.000000 60.216000 0.084000 ;
  END
 END k_li_d[299]
 PIN k_li_d[300]
  DIRECTION OUTPUT ;
  USE SIGNAL ;
  PORT
   LAYER M5 ;
   RECT 60.384000 0.000000 60.408000 0.084000 ;
  END
 END k_li_d[300]
 PIN k_li_d[301]
  DIRECTION OUTPUT ;
  USE SIGNAL ;
  PORT
   LAYER M5 ;
   RECT 60.528000 0.000000 60.552000 0.084000 ;
  END
 END k_li_d[301]
 PIN k_li_d[302]
  DIRECTION OUTPUT ;
  USE SIGNAL ;
  PORT
   LAYER M5 ;
   RECT 60.720000 0.000000 60.744000 0.084000 ;
  END
 END k_li_d[302]
 PIN k_li_d[303]
  DIRECTION OUTPUT ;
  USE SIGNAL ;
  PORT
   LAYER M5 ;
   RECT 60.912000 0.000000 60.936000 0.084000 ;
  END
 END k_li_d[303]
 PIN k_li_d[304]
  DIRECTION OUTPUT ;
  USE SIGNAL ;
  PORT
   LAYER M5 ;
   RECT 61.056000 0.000000 61.080000 0.084000 ;
  END
 END k_li_d[304]
 PIN k_li_d[305]
  DIRECTION OUTPUT ;
  USE SIGNAL ;
  PORT
   LAYER M5 ;
   RECT 61.248000 0.000000 61.272000 0.084000 ;
  END
 END k_li_d[305]
 PIN k_li_d[306]
  DIRECTION OUTPUT ;
  USE SIGNAL ;
  PORT
   LAYER M5 ;
   RECT 61.440000 0.000000 61.464000 0.084000 ;
  END
 END k_li_d[306]
 PIN k_li_d[307]
  DIRECTION OUTPUT ;
  USE SIGNAL ;
  PORT
   LAYER M5 ;
   RECT 61.632000 0.000000 61.656000 0.084000 ;
  END
 END k_li_d[307]
 PIN k_li_d[308]
  DIRECTION OUTPUT ;
  USE SIGNAL ;
  PORT
   LAYER M5 ;
   RECT 61.776000 0.000000 61.800000 0.084000 ;
  END
 END k_li_d[308]
 PIN k_li_d[309]
  DIRECTION OUTPUT ;
  USE SIGNAL ;
  PORT
   LAYER M5 ;
   RECT 61.968000 0.000000 61.992000 0.084000 ;
  END
 END k_li_d[309]
 PIN k_li_d[310]
  DIRECTION OUTPUT ;
  USE SIGNAL ;
  PORT
   LAYER M5 ;
   RECT 62.160000 0.000000 62.184000 0.084000 ;
  END
 END k_li_d[310]
 PIN k_li_d[311]
  DIRECTION OUTPUT ;
  USE SIGNAL ;
  PORT
   LAYER M5 ;
   RECT 62.256000 0.000000 62.280000 0.084000 ;
  END
 END k_li_d[311]
 PIN k_li_d[312]
  DIRECTION OUTPUT ;
  USE SIGNAL ;
  PORT
   LAYER M5 ;
   RECT 62.304000 0.000000 62.328000 0.084000 ;
  END
 END k_li_d[312]
 PIN k_li_d[313]
  DIRECTION OUTPUT ;
  USE SIGNAL ;
  PORT
   LAYER M5 ;
   RECT 62.352000 0.000000 62.376000 0.084000 ;
  END
 END k_li_d[313]
 PIN k_li_d[314]
  DIRECTION OUTPUT ;
  USE SIGNAL ;
  PORT
   LAYER M5 ;
   RECT 62.928000 0.000000 62.952000 0.084000 ;
  END
 END k_li_d[314]
 PIN k_li_d[315]
  DIRECTION OUTPUT ;
  USE SIGNAL ;
  PORT
   LAYER M5 ;
   RECT 63.072000 0.000000 63.096000 0.084000 ;
  END
 END k_li_d[315]
 PIN k_li_d[316]
  DIRECTION OUTPUT ;
  USE SIGNAL ;
  PORT
   LAYER M5 ;
   RECT 63.216000 0.000000 63.240000 0.084000 ;
  END
 END k_li_d[316]
 PIN k_li_d[317]
  DIRECTION OUTPUT ;
  USE SIGNAL ;
  PORT
   LAYER M5 ;
   RECT 63.408000 0.000000 63.432000 0.084000 ;
  END
 END k_li_d[317]
 PIN k_li_d[318]
  DIRECTION OUTPUT ;
  USE SIGNAL ;
  PORT
   LAYER M5 ;
   RECT 63.600000 0.000000 63.624000 0.084000 ;
  END
 END k_li_d[318]
 PIN k_li_d[319]
  DIRECTION OUTPUT ;
  USE SIGNAL ;
  PORT
   LAYER M5 ;
   RECT 63.744000 0.000000 63.768000 0.084000 ;
  END
 END k_li_d[319]
 PIN k_li_d[320]
  DIRECTION OUTPUT ;
  USE SIGNAL ;
  PORT
   LAYER M5 ;
   RECT 63.936000 0.000000 63.960000 0.084000 ;
  END
 END k_li_d[320]
 PIN k_li_d[321]
  DIRECTION OUTPUT ;
  USE SIGNAL ;
  PORT
   LAYER M5 ;
   RECT 64.128000 0.000000 64.152000 0.084000 ;
  END
 END k_li_d[321]
 PIN k_li_d[322]
  DIRECTION OUTPUT ;
  USE SIGNAL ;
  PORT
   LAYER M5 ;
   RECT 64.320000 0.000000 64.344000 0.084000 ;
  END
 END k_li_d[322]
 PIN k_li_d[323]
  DIRECTION OUTPUT ;
  USE SIGNAL ;
  PORT
   LAYER M5 ;
   RECT 64.464000 0.000000 64.488000 0.084000 ;
  END
 END k_li_d[323]
 PIN k_li_d[324]
  DIRECTION OUTPUT ;
  USE SIGNAL ;
  PORT
   LAYER M5 ;
   RECT 64.656000 0.000000 64.680000 0.084000 ;
  END
 END k_li_d[324]
 PIN k_li_d[325]
  DIRECTION OUTPUT ;
  USE SIGNAL ;
  PORT
   LAYER M5 ;
   RECT 64.848000 0.000000 64.872000 0.084000 ;
  END
 END k_li_d[325]
 PIN k_li_d[326]
  DIRECTION OUTPUT ;
  USE SIGNAL ;
  PORT
   LAYER M5 ;
   RECT 65.040000 0.000000 65.064000 0.084000 ;
  END
 END k_li_d[326]
 PIN k_li_d[327]
  DIRECTION OUTPUT ;
  USE SIGNAL ;
  PORT
   LAYER M5 ;
   RECT 65.184000 0.000000 65.208000 0.084000 ;
  END
 END k_li_d[327]
 PIN k_li_d[328]
  DIRECTION OUTPUT ;
  USE SIGNAL ;
  PORT
   LAYER M5 ;
   RECT 65.376000 0.000000 65.400000 0.084000 ;
  END
 END k_li_d[328]
 PIN k_li_d[329]
  DIRECTION OUTPUT ;
  USE SIGNAL ;
  PORT
   LAYER M5 ;
   RECT 65.568000 0.000000 65.592000 0.084000 ;
  END
 END k_li_d[329]
 PIN k_li_d[330]
  DIRECTION OUTPUT ;
  USE SIGNAL ;
  PORT
   LAYER M5 ;
   RECT 65.760000 0.000000 65.784000 0.084000 ;
  END
 END k_li_d[330]
 PIN k_li_d[331]
  DIRECTION OUTPUT ;
  USE SIGNAL ;
  PORT
   LAYER M5 ;
   RECT 65.904000 0.000000 65.928000 0.084000 ;
  END
 END k_li_d[331]
 PIN k_li_d[332]
  DIRECTION OUTPUT ;
  USE SIGNAL ;
  PORT
   LAYER M5 ;
   RECT 66.096000 0.000000 66.120000 0.084000 ;
  END
 END k_li_d[332]
 PIN k_li_d[333]
  DIRECTION OUTPUT ;
  USE SIGNAL ;
  PORT
   LAYER M5 ;
   RECT 66.288000 0.000000 66.312000 0.084000 ;
  END
 END k_li_d[333]
 PIN k_li_d[334]
  DIRECTION OUTPUT ;
  USE SIGNAL ;
  PORT
   LAYER M5 ;
   RECT 66.432000 0.000000 66.456000 0.084000 ;
  END
 END k_li_d[334]
 PIN k_li_d[335]
  DIRECTION OUTPUT ;
  USE SIGNAL ;
  PORT
   LAYER M5 ;
   RECT 66.576000 0.000000 66.600000 0.084000 ;
  END
 END k_li_d[335]
 PIN k_li_d[336]
  DIRECTION OUTPUT ;
  USE SIGNAL ;
  PORT
   LAYER M5 ;
   RECT 66.624000 0.000000 66.648000 0.084000 ;
  END
 END k_li_d[336]
 PIN k_li_d[337]
  DIRECTION OUTPUT ;
  USE SIGNAL ;
  PORT
   LAYER M5 ;
   RECT 66.672000 0.000000 66.696000 0.084000 ;
  END
 END k_li_d[337]
 PIN k_li_d[338]
  DIRECTION OUTPUT ;
  USE SIGNAL ;
  PORT
   LAYER M5 ;
   RECT 67.248000 0.000000 67.272000 0.084000 ;
  END
 END k_li_d[338]
 PIN k_li_d[339]
  DIRECTION OUTPUT ;
  USE SIGNAL ;
  PORT
   LAYER M5 ;
   RECT 67.344000 0.000000 67.368000 0.084000 ;
  END
 END k_li_d[339]
 PIN k_li_d[340]
  DIRECTION OUTPUT ;
  USE SIGNAL ;
  PORT
   LAYER M5 ;
   RECT 67.536000 0.000000 67.560000 0.084000 ;
  END
 END k_li_d[340]
 PIN k_li_d[341]
  DIRECTION OUTPUT ;
  USE SIGNAL ;
  PORT
   LAYER M5 ;
   RECT 67.728000 0.000000 67.752000 0.084000 ;
  END
 END k_li_d[341]
 PIN k_li_d[342]
  DIRECTION OUTPUT ;
  USE SIGNAL ;
  PORT
   LAYER M5 ;
   RECT 67.872000 0.000000 67.896000 0.084000 ;
  END
 END k_li_d[342]
 PIN k_li_d[343]
  DIRECTION OUTPUT ;
  USE SIGNAL ;
  PORT
   LAYER M5 ;
   RECT 68.064000 0.000000 68.088000 0.084000 ;
  END
 END k_li_d[343]
 PIN k_li_d[344]
  DIRECTION OUTPUT ;
  USE SIGNAL ;
  PORT
   LAYER M5 ;
   RECT 68.256000 0.000000 68.280000 0.084000 ;
  END
 END k_li_d[344]
 PIN k_li_d[345]
  DIRECTION OUTPUT ;
  USE SIGNAL ;
  PORT
   LAYER M5 ;
   RECT 68.448000 0.000000 68.472000 0.084000 ;
  END
 END k_li_d[345]
 PIN k_li_d[346]
  DIRECTION OUTPUT ;
  USE SIGNAL ;
  PORT
   LAYER M5 ;
   RECT 68.592000 0.000000 68.616000 0.084000 ;
  END
 END k_li_d[346]
 PIN k_li_d[347]
  DIRECTION OUTPUT ;
  USE SIGNAL ;
  PORT
   LAYER M5 ;
   RECT 68.784000 0.000000 68.808000 0.084000 ;
  END
 END k_li_d[347]
 PIN k_li_d[348]
  DIRECTION OUTPUT ;
  USE SIGNAL ;
  PORT
   LAYER M5 ;
   RECT 68.976000 0.000000 69.000000 0.084000 ;
  END
 END k_li_d[348]
 PIN k_li_d[349]
  DIRECTION OUTPUT ;
  USE SIGNAL ;
  PORT
   LAYER M5 ;
   RECT 69.168000 0.000000 69.192000 0.084000 ;
  END
 END k_li_d[349]
 PIN k_li_d[350]
  DIRECTION OUTPUT ;
  USE SIGNAL ;
  PORT
   LAYER M5 ;
   RECT 69.312000 0.000000 69.336000 0.084000 ;
  END
 END k_li_d[350]
 PIN k_li_d[351]
  DIRECTION OUTPUT ;
  USE SIGNAL ;
  PORT
   LAYER M5 ;
   RECT 69.504000 0.000000 69.528000 0.084000 ;
  END
 END k_li_d[351]
 PIN k_li_d[352]
  DIRECTION OUTPUT ;
  USE SIGNAL ;
  PORT
   LAYER M5 ;
   RECT 69.696000 0.000000 69.720000 0.084000 ;
  END
 END k_li_d[352]
 PIN k_li_d[353]
  DIRECTION OUTPUT ;
  USE SIGNAL ;
  PORT
   LAYER M5 ;
   RECT 69.840000 0.000000 69.864000 0.084000 ;
  END
 END k_li_d[353]
 PIN k_li_d[354]
  DIRECTION OUTPUT ;
  USE SIGNAL ;
  PORT
   LAYER M5 ;
   RECT 70.032000 0.000000 70.056000 0.084000 ;
  END
 END k_li_d[354]
 PIN k_li_d[355]
  DIRECTION OUTPUT ;
  USE SIGNAL ;
  PORT
   LAYER M5 ;
   RECT 70.224000 0.000000 70.248000 0.084000 ;
  END
 END k_li_d[355]
 PIN k_li_d[356]
  DIRECTION OUTPUT ;
  USE SIGNAL ;
  PORT
   LAYER M5 ;
   RECT 70.416000 0.000000 70.440000 0.084000 ;
  END
 END k_li_d[356]
 PIN k_li_d[357]
  DIRECTION OUTPUT ;
  USE SIGNAL ;
  PORT
   LAYER M5 ;
   RECT 70.560000 0.000000 70.584000 0.084000 ;
  END
 END k_li_d[357]
 PIN k_li_d[358]
  DIRECTION OUTPUT ;
  USE SIGNAL ;
  PORT
   LAYER M5 ;
   RECT 70.752000 0.000000 70.776000 0.084000 ;
  END
 END k_li_d[358]
 PIN k_li_d[359]
  DIRECTION OUTPUT ;
  USE SIGNAL ;
  PORT
   LAYER M5 ;
   RECT 70.896000 0.000000 70.920000 0.084000 ;
  END
 END k_li_d[359]
 PIN k_li_d[360]
  DIRECTION OUTPUT ;
  USE SIGNAL ;
  PORT
   LAYER M5 ;
   RECT 70.944000 0.000000 70.968000 0.084000 ;
  END
 END k_li_d[360]
 PIN k_li_d[361]
  DIRECTION OUTPUT ;
  USE SIGNAL ;
  PORT
   LAYER M5 ;
   RECT 70.992000 0.000000 71.016000 0.084000 ;
  END
 END k_li_d[361]
 PIN k_li_d[362]
  DIRECTION OUTPUT ;
  USE SIGNAL ;
  PORT
   LAYER M5 ;
   RECT 71.568000 0.000000 71.592000 0.084000 ;
  END
 END k_li_d[362]
 PIN k_li_d[363]
  DIRECTION OUTPUT ;
  USE SIGNAL ;
  PORT
   LAYER M5 ;
   RECT 71.664000 0.000000 71.688000 0.084000 ;
  END
 END k_li_d[363]
 PIN k_li_d[364]
  DIRECTION OUTPUT ;
  USE SIGNAL ;
  PORT
   LAYER M5 ;
   RECT 71.856000 0.000000 71.880000 0.084000 ;
  END
 END k_li_d[364]
 PIN k_li_d[365]
  DIRECTION OUTPUT ;
  USE SIGNAL ;
  PORT
   LAYER M5 ;
   RECT 72.000000 0.000000 72.024000 0.084000 ;
  END
 END k_li_d[365]
 PIN k_li_d[366]
  DIRECTION OUTPUT ;
  USE SIGNAL ;
  PORT
   LAYER M5 ;
   RECT 72.192000 0.000000 72.216000 0.084000 ;
  END
 END k_li_d[366]
 PIN k_li_d[367]
  DIRECTION OUTPUT ;
  USE SIGNAL ;
  PORT
   LAYER M5 ;
   RECT 72.384000 0.000000 72.408000 0.084000 ;
  END
 END k_li_d[367]
 PIN k_li_d[368]
  DIRECTION OUTPUT ;
  USE SIGNAL ;
  PORT
   LAYER M5 ;
   RECT 72.528000 0.000000 72.552000 0.084000 ;
  END
 END k_li_d[368]
 PIN k_li_d[369]
  DIRECTION OUTPUT ;
  USE SIGNAL ;
  PORT
   LAYER M5 ;
   RECT 72.720000 0.000000 72.744000 0.084000 ;
  END
 END k_li_d[369]
 PIN k_li_d[370]
  DIRECTION OUTPUT ;
  USE SIGNAL ;
  PORT
   LAYER M5 ;
   RECT 72.912000 0.000000 72.936000 0.084000 ;
  END
 END k_li_d[370]
 PIN k_li_d[371]
  DIRECTION OUTPUT ;
  USE SIGNAL ;
  PORT
   LAYER M5 ;
   RECT 73.104000 0.000000 73.128000 0.084000 ;
  END
 END k_li_d[371]
 PIN k_li_d[372]
  DIRECTION OUTPUT ;
  USE SIGNAL ;
  PORT
   LAYER M5 ;
   RECT 73.248000 0.000000 73.272000 0.084000 ;
  END
 END k_li_d[372]
 PIN k_li_d[373]
  DIRECTION OUTPUT ;
  USE SIGNAL ;
  PORT
   LAYER M5 ;
   RECT 73.440000 0.000000 73.464000 0.084000 ;
  END
 END k_li_d[373]
 PIN k_li_d[374]
  DIRECTION OUTPUT ;
  USE SIGNAL ;
  PORT
   LAYER M5 ;
   RECT 73.632000 0.000000 73.656000 0.084000 ;
  END
 END k_li_d[374]
 PIN k_li_d[375]
  DIRECTION OUTPUT ;
  USE SIGNAL ;
  PORT
   LAYER M5 ;
   RECT 73.824000 0.000000 73.848000 0.084000 ;
  END
 END k_li_d[375]
 PIN k_li_d[376]
  DIRECTION OUTPUT ;
  USE SIGNAL ;
  PORT
   LAYER M5 ;
   RECT 73.968000 0.000000 73.992000 0.084000 ;
  END
 END k_li_d[376]
 PIN k_li_d[377]
  DIRECTION OUTPUT ;
  USE SIGNAL ;
  PORT
   LAYER M5 ;
   RECT 74.160000 0.000000 74.184000 0.084000 ;
  END
 END k_li_d[377]
 PIN k_li_d[378]
  DIRECTION OUTPUT ;
  USE SIGNAL ;
  PORT
   LAYER M5 ;
   RECT 74.352000 0.000000 74.376000 0.084000 ;
  END
 END k_li_d[378]
 PIN k_li_d[379]
  DIRECTION OUTPUT ;
  USE SIGNAL ;
  PORT
   LAYER M5 ;
   RECT 74.544000 0.000000 74.568000 0.084000 ;
  END
 END k_li_d[379]
 PIN k_li_d[380]
  DIRECTION OUTPUT ;
  USE SIGNAL ;
  PORT
   LAYER M5 ;
   RECT 74.688000 0.000000 74.712000 0.084000 ;
  END
 END k_li_d[380]
 PIN k_li_d[381]
  DIRECTION OUTPUT ;
  USE SIGNAL ;
  PORT
   LAYER M5 ;
   RECT 74.880000 0.000000 74.904000 0.084000 ;
  END
 END k_li_d[381]
 PIN k_li_d[382]
  DIRECTION OUTPUT ;
  USE SIGNAL ;
  PORT
   LAYER M5 ;
   RECT 75.072000 0.000000 75.096000 0.084000 ;
  END
 END k_li_d[382]
 PIN k_li_d[383]
  DIRECTION OUTPUT ;
  USE SIGNAL ;
  PORT
   LAYER M5 ;
   RECT 75.216000 0.000000 75.240000 0.084000 ;
  END
 END k_li_d[383]
 PIN k_li_d[384]
  DIRECTION OUTPUT ;
  USE SIGNAL ;
  PORT
   LAYER M5 ;
   RECT 75.264000 0.000000 75.288000 0.084000 ;
  END
 END k_li_d[384]
 PIN k_li_d[385]
  DIRECTION OUTPUT ;
  USE SIGNAL ;
  PORT
   LAYER M5 ;
   RECT 75.312000 0.000000 75.336000 0.084000 ;
  END
 END k_li_d[385]
 PIN k_li_d[386]
  DIRECTION OUTPUT ;
  USE SIGNAL ;
  PORT
   LAYER M5 ;
   RECT 75.888000 0.000000 75.912000 0.084000 ;
  END
 END k_li_d[386]
 PIN k_li_d[387]
  DIRECTION OUTPUT ;
  USE SIGNAL ;
  PORT
   LAYER M5 ;
   RECT 75.936000 0.000000 75.960000 0.084000 ;
  END
 END k_li_d[387]
 PIN k_li_d[388]
  DIRECTION OUTPUT ;
  USE SIGNAL ;
  PORT
   LAYER M5 ;
   RECT 76.128000 0.000000 76.152000 0.084000 ;
  END
 END k_li_d[388]
 PIN k_li_d[389]
  DIRECTION OUTPUT ;
  USE SIGNAL ;
  PORT
   LAYER M5 ;
   RECT 76.320000 0.000000 76.344000 0.084000 ;
  END
 END k_li_d[389]
 PIN k_li_d[390]
  DIRECTION OUTPUT ;
  USE SIGNAL ;
  PORT
   LAYER M5 ;
   RECT 76.512000 0.000000 76.536000 0.084000 ;
  END
 END k_li_d[390]
 PIN k_li_d[391]
  DIRECTION OUTPUT ;
  USE SIGNAL ;
  PORT
   LAYER M5 ;
   RECT 76.656000 0.000000 76.680000 0.084000 ;
  END
 END k_li_d[391]
 PIN k_li_d[392]
  DIRECTION OUTPUT ;
  USE SIGNAL ;
  PORT
   LAYER M5 ;
   RECT 76.848000 0.000000 76.872000 0.084000 ;
  END
 END k_li_d[392]
 PIN k_li_d[393]
  DIRECTION OUTPUT ;
  USE SIGNAL ;
  PORT
   LAYER M5 ;
   RECT 77.040000 0.000000 77.064000 0.084000 ;
  END
 END k_li_d[393]
 PIN k_li_d[394]
  DIRECTION OUTPUT ;
  USE SIGNAL ;
  PORT
   LAYER M5 ;
   RECT 77.232000 0.000000 77.256000 0.084000 ;
  END
 END k_li_d[394]
 PIN k_li_d[395]
  DIRECTION OUTPUT ;
  USE SIGNAL ;
  PORT
   LAYER M5 ;
   RECT 77.376000 0.000000 77.400000 0.084000 ;
  END
 END k_li_d[395]
 PIN k_li_d[396]
  DIRECTION OUTPUT ;
  USE SIGNAL ;
  PORT
   LAYER M5 ;
   RECT 77.568000 0.000000 77.592000 0.084000 ;
  END
 END k_li_d[396]
 PIN k_li_d[397]
  DIRECTION OUTPUT ;
  USE SIGNAL ;
  PORT
   LAYER M5 ;
   RECT 77.760000 0.000000 77.784000 0.084000 ;
  END
 END k_li_d[397]
 PIN k_li_d[398]
  DIRECTION OUTPUT ;
  USE SIGNAL ;
  PORT
   LAYER M5 ;
   RECT 77.952000 0.000000 77.976000 0.084000 ;
  END
 END k_li_d[398]
 PIN k_li_d[399]
  DIRECTION OUTPUT ;
  USE SIGNAL ;
  PORT
   LAYER M5 ;
   RECT 78.096000 0.000000 78.120000 0.084000 ;
  END
 END k_li_d[399]
 PIN k_li_d[400]
  DIRECTION OUTPUT ;
  USE SIGNAL ;
  PORT
   LAYER M5 ;
   RECT 78.288000 0.000000 78.312000 0.084000 ;
  END
 END k_li_d[400]
 PIN k_li_d[401]
  DIRECTION OUTPUT ;
  USE SIGNAL ;
  PORT
   LAYER M5 ;
   RECT 78.480000 0.000000 78.504000 0.084000 ;
  END
 END k_li_d[401]
 PIN k_li_d[402]
  DIRECTION OUTPUT ;
  USE SIGNAL ;
  PORT
   LAYER M5 ;
   RECT 78.624000 0.000000 78.648000 0.084000 ;
  END
 END k_li_d[402]
 PIN k_li_d[403]
  DIRECTION OUTPUT ;
  USE SIGNAL ;
  PORT
   LAYER M5 ;
   RECT 78.816000 0.000000 78.840000 0.084000 ;
  END
 END k_li_d[403]
 PIN k_li_d[404]
  DIRECTION OUTPUT ;
  USE SIGNAL ;
  PORT
   LAYER M5 ;
   RECT 79.008000 0.000000 79.032000 0.084000 ;
  END
 END k_li_d[404]
 PIN k_li_d[405]
  DIRECTION OUTPUT ;
  USE SIGNAL ;
  PORT
   LAYER M5 ;
   RECT 79.200000 0.000000 79.224000 0.084000 ;
  END
 END k_li_d[405]
 PIN k_li_d[406]
  DIRECTION OUTPUT ;
  USE SIGNAL ;
  PORT
   LAYER M5 ;
   RECT 79.344000 0.000000 79.368000 0.084000 ;
  END
 END k_li_d[406]
 PIN k_li_d[407]
  DIRECTION OUTPUT ;
  USE SIGNAL ;
  PORT
   LAYER M5 ;
   RECT 79.536000 0.000000 79.560000 0.084000 ;
  END
 END k_li_d[407]
 PIN k_li_d[408]
  DIRECTION OUTPUT ;
  USE SIGNAL ;
  PORT
   LAYER M5 ;
   RECT 79.584000 0.000000 79.608000 0.084000 ;
  END
 END k_li_d[408]
 PIN k_li_d[409]
  DIRECTION OUTPUT ;
  USE SIGNAL ;
  PORT
   LAYER M5 ;
   RECT 79.632000 0.000000 79.656000 0.084000 ;
  END
 END k_li_d[409]
 PIN k_li_d[410]
  DIRECTION OUTPUT ;
  USE SIGNAL ;
  PORT
   LAYER M5 ;
   RECT 80.208000 0.000000 80.232000 0.084000 ;
  END
 END k_li_d[410]
 PIN k_li_d[411]
  DIRECTION OUTPUT ;
  USE SIGNAL ;
  PORT
   LAYER M5 ;
   RECT 80.256000 0.000000 80.280000 0.084000 ;
  END
 END k_li_d[411]
 PIN k_li_d[412]
  DIRECTION OUTPUT ;
  USE SIGNAL ;
  PORT
   LAYER M5 ;
   RECT 80.448000 0.000000 80.472000 0.084000 ;
  END
 END k_li_d[412]
 PIN k_li_d[413]
  DIRECTION OUTPUT ;
  USE SIGNAL ;
  PORT
   LAYER M5 ;
   RECT 80.640000 0.000000 80.664000 0.084000 ;
  END
 END k_li_d[413]
 PIN k_li_d[414]
  DIRECTION OUTPUT ;
  USE SIGNAL ;
  PORT
   LAYER M5 ;
   RECT 80.784000 0.000000 80.808000 0.084000 ;
  END
 END k_li_d[414]
 PIN k_li_d[415]
  DIRECTION OUTPUT ;
  USE SIGNAL ;
  PORT
   LAYER M5 ;
   RECT 80.976000 0.000000 81.000000 0.084000 ;
  END
 END k_li_d[415]
 PIN k_li_d[416]
  DIRECTION OUTPUT ;
  USE SIGNAL ;
  PORT
   LAYER M5 ;
   RECT 81.168000 0.000000 81.192000 0.084000 ;
  END
 END k_li_d[416]
 PIN k_li_d[417]
  DIRECTION OUTPUT ;
  USE SIGNAL ;
  PORT
   LAYER M5 ;
   RECT 81.312000 0.000000 81.336000 0.084000 ;
  END
 END k_li_d[417]
 PIN k_li_d[418]
  DIRECTION OUTPUT ;
  USE SIGNAL ;
  PORT
   LAYER M5 ;
   RECT 81.504000 0.000000 81.528000 0.084000 ;
  END
 END k_li_d[418]
 PIN k_li_d[419]
  DIRECTION OUTPUT ;
  USE SIGNAL ;
  PORT
   LAYER M5 ;
   RECT 81.696000 0.000000 81.720000 0.084000 ;
  END
 END k_li_d[419]
 PIN k_li_d[420]
  DIRECTION OUTPUT ;
  USE SIGNAL ;
  PORT
   LAYER M5 ;
   RECT 81.888000 0.000000 81.912000 0.084000 ;
  END
 END k_li_d[420]
 PIN k_li_d[421]
  DIRECTION OUTPUT ;
  USE SIGNAL ;
  PORT
   LAYER M5 ;
   RECT 82.032000 0.000000 82.056000 0.084000 ;
  END
 END k_li_d[421]
 PIN k_li_d[422]
  DIRECTION OUTPUT ;
  USE SIGNAL ;
  PORT
   LAYER M5 ;
   RECT 82.224000 0.000000 82.248000 0.084000 ;
  END
 END k_li_d[422]
 PIN k_li_d[423]
  DIRECTION OUTPUT ;
  USE SIGNAL ;
  PORT
   LAYER M5 ;
   RECT 82.416000 0.000000 82.440000 0.084000 ;
  END
 END k_li_d[423]
 PIN k_li_d[424]
  DIRECTION OUTPUT ;
  USE SIGNAL ;
  PORT
   LAYER M5 ;
   RECT 82.608000 0.000000 82.632000 0.084000 ;
  END
 END k_li_d[424]
 PIN k_li_d[425]
  DIRECTION OUTPUT ;
  USE SIGNAL ;
  PORT
   LAYER M5 ;
   RECT 82.752000 0.000000 82.776000 0.084000 ;
  END
 END k_li_d[425]
 PIN k_li_d[426]
  DIRECTION OUTPUT ;
  USE SIGNAL ;
  PORT
   LAYER M5 ;
   RECT 82.944000 0.000000 82.968000 0.084000 ;
  END
 END k_li_d[426]
 PIN k_li_d[427]
  DIRECTION OUTPUT ;
  USE SIGNAL ;
  PORT
   LAYER M5 ;
   RECT 83.136000 0.000000 83.160000 0.084000 ;
  END
 END k_li_d[427]
 PIN k_li_d[428]
  DIRECTION OUTPUT ;
  USE SIGNAL ;
  PORT
   LAYER M5 ;
   RECT 83.328000 0.000000 83.352000 0.084000 ;
  END
 END k_li_d[428]
 PIN k_li_d[429]
  DIRECTION OUTPUT ;
  USE SIGNAL ;
  PORT
   LAYER M5 ;
   RECT 83.472000 0.000000 83.496000 0.084000 ;
  END
 END k_li_d[429]
 PIN k_li_d[430]
  DIRECTION OUTPUT ;
  USE SIGNAL ;
  PORT
   LAYER M5 ;
   RECT 83.664000 0.000000 83.688000 0.084000 ;
  END
 END k_li_d[430]
 PIN k_li_d[431]
  DIRECTION OUTPUT ;
  USE SIGNAL ;
  PORT
   LAYER M5 ;
   RECT 83.856000 0.000000 83.880000 0.084000 ;
  END
 END k_li_d[431]
 PIN k_li_d[432]
  DIRECTION OUTPUT ;
  USE SIGNAL ;
  PORT
   LAYER M5 ;
   RECT 83.904000 0.000000 83.928000 0.084000 ;
  END
 END k_li_d[432]
 PIN k_li_d[433]
  DIRECTION OUTPUT ;
  USE SIGNAL ;
  PORT
   LAYER M5 ;
   RECT 83.952000 0.000000 83.976000 0.084000 ;
  END
 END k_li_d[433]
 PIN k_li_d[434]
  DIRECTION OUTPUT ;
  USE SIGNAL ;
  PORT
   LAYER M5 ;
   RECT 84.528000 0.000000 84.552000 0.084000 ;
  END
 END k_li_d[434]
 PIN k_li_d[435]
  DIRECTION OUTPUT ;
  USE SIGNAL ;
  PORT
   LAYER M5 ;
   RECT 84.576000 0.000000 84.600000 0.084000 ;
  END
 END k_li_d[435]
 PIN k_li_d[436]
  DIRECTION OUTPUT ;
  USE SIGNAL ;
  PORT
   LAYER M5 ;
   RECT 84.720000 0.000000 84.744000 0.084000 ;
  END
 END k_li_d[436]
 PIN k_li_d[437]
  DIRECTION OUTPUT ;
  USE SIGNAL ;
  PORT
   LAYER M5 ;
   RECT 84.912000 0.000000 84.936000 0.084000 ;
  END
 END k_li_d[437]
 PIN k_li_d[438]
  DIRECTION OUTPUT ;
  USE SIGNAL ;
  PORT
   LAYER M5 ;
   RECT 85.104000 0.000000 85.128000 0.084000 ;
  END
 END k_li_d[438]
 PIN k_li_d[439]
  DIRECTION OUTPUT ;
  USE SIGNAL ;
  PORT
   LAYER M5 ;
   RECT 85.296000 0.000000 85.320000 0.084000 ;
  END
 END k_li_d[439]
 PIN k_li_d[440]
  DIRECTION OUTPUT ;
  USE SIGNAL ;
  PORT
   LAYER M5 ;
   RECT 85.440000 0.000000 85.464000 0.084000 ;
  END
 END k_li_d[440]
 PIN k_li_d[441]
  DIRECTION OUTPUT ;
  USE SIGNAL ;
  PORT
   LAYER M5 ;
   RECT 85.632000 0.000000 85.656000 0.084000 ;
  END
 END k_li_d[441]
 PIN k_li_d[442]
  DIRECTION OUTPUT ;
  USE SIGNAL ;
  PORT
   LAYER M5 ;
   RECT 85.824000 0.000000 85.848000 0.084000 ;
  END
 END k_li_d[442]
 PIN k_li_d[443]
  DIRECTION OUTPUT ;
  USE SIGNAL ;
  PORT
   LAYER M5 ;
   RECT 86.016000 0.000000 86.040000 0.084000 ;
  END
 END k_li_d[443]
 PIN k_li_d[444]
  DIRECTION OUTPUT ;
  USE SIGNAL ;
  PORT
   LAYER M5 ;
   RECT 86.160000 0.000000 86.184000 0.084000 ;
  END
 END k_li_d[444]
 PIN k_li_d[445]
  DIRECTION OUTPUT ;
  USE SIGNAL ;
  PORT
   LAYER M5 ;
   RECT 86.352000 0.000000 86.376000 0.084000 ;
  END
 END k_li_d[445]
 PIN k_li_d[446]
  DIRECTION OUTPUT ;
  USE SIGNAL ;
  PORT
   LAYER M5 ;
   RECT 86.544000 0.000000 86.568000 0.084000 ;
  END
 END k_li_d[446]
 PIN k_li_d[447]
  DIRECTION OUTPUT ;
  USE SIGNAL ;
  PORT
   LAYER M5 ;
   RECT 86.736000 0.000000 86.760000 0.084000 ;
  END
 END k_li_d[447]
 PIN k_li_d[448]
  DIRECTION OUTPUT ;
  USE SIGNAL ;
  PORT
   LAYER M5 ;
   RECT 86.880000 0.000000 86.904000 0.084000 ;
  END
 END k_li_d[448]
 PIN k_li_d[449]
  DIRECTION OUTPUT ;
  USE SIGNAL ;
  PORT
   LAYER M5 ;
   RECT 87.072000 0.000000 87.096000 0.084000 ;
  END
 END k_li_d[449]
 PIN k_li_d[450]
  DIRECTION OUTPUT ;
  USE SIGNAL ;
  PORT
   LAYER M5 ;
   RECT 87.264000 0.000000 87.288000 0.084000 ;
  END
 END k_li_d[450]
 PIN k_li_d[451]
  DIRECTION OUTPUT ;
  USE SIGNAL ;
  PORT
   LAYER M5 ;
   RECT 87.408000 0.000000 87.432000 0.084000 ;
  END
 END k_li_d[451]
 PIN k_li_d[452]
  DIRECTION OUTPUT ;
  USE SIGNAL ;
  PORT
   LAYER M5 ;
   RECT 87.600000 0.000000 87.624000 0.084000 ;
  END
 END k_li_d[452]
 PIN k_li_d[453]
  DIRECTION OUTPUT ;
  USE SIGNAL ;
  PORT
   LAYER M5 ;
   RECT 87.792000 0.000000 87.816000 0.084000 ;
  END
 END k_li_d[453]
 PIN k_li_d[454]
  DIRECTION OUTPUT ;
  USE SIGNAL ;
  PORT
   LAYER M5 ;
   RECT 87.984000 0.000000 88.008000 0.084000 ;
  END
 END k_li_d[454]
 PIN k_li_d[455]
  DIRECTION OUTPUT ;
  USE SIGNAL ;
  PORT
   LAYER M5 ;
   RECT 88.128000 0.000000 88.152000 0.084000 ;
  END
 END k_li_d[455]
 PIN k_li_d[456]
  DIRECTION OUTPUT ;
  USE SIGNAL ;
  PORT
   LAYER M5 ;
   RECT 88.176000 0.000000 88.200000 0.084000 ;
  END
 END k_li_d[456]
 PIN k_li_d[457]
  DIRECTION OUTPUT ;
  USE SIGNAL ;
  PORT
   LAYER M5 ;
   RECT 88.224000 0.000000 88.248000 0.084000 ;
  END
 END k_li_d[457]
 PIN k_li_d[458]
  DIRECTION OUTPUT ;
  USE SIGNAL ;
  PORT
   LAYER M5 ;
   RECT 88.272000 0.000000 88.296000 0.084000 ;
  END
 END k_li_d[458]
 PIN k_li_d[459]
  DIRECTION OUTPUT ;
  USE SIGNAL ;
  PORT
   LAYER M5 ;
   RECT 88.848000 0.000000 88.872000 0.084000 ;
  END
 END k_li_d[459]
 PIN k_li_d[460]
  DIRECTION OUTPUT ;
  USE SIGNAL ;
  PORT
   LAYER M5 ;
   RECT 89.040000 0.000000 89.064000 0.084000 ;
  END
 END k_li_d[460]
 PIN k_li_d[461]
  DIRECTION OUTPUT ;
  USE SIGNAL ;
  PORT
   LAYER M5 ;
   RECT 89.232000 0.000000 89.256000 0.084000 ;
  END
 END k_li_d[461]
 PIN k_li_d[462]
  DIRECTION OUTPUT ;
  USE SIGNAL ;
  PORT
   LAYER M5 ;
   RECT 89.424000 0.000000 89.448000 0.084000 ;
  END
 END k_li_d[462]
 PIN k_li_d[463]
  DIRECTION OUTPUT ;
  USE SIGNAL ;
  PORT
   LAYER M5 ;
   RECT 89.568000 0.000000 89.592000 0.084000 ;
  END
 END k_li_d[463]
 PIN k_li_d[464]
  DIRECTION OUTPUT ;
  USE SIGNAL ;
  PORT
   LAYER M5 ;
   RECT 89.760000 0.000000 89.784000 0.084000 ;
  END
 END k_li_d[464]
 PIN k_li_d[465]
  DIRECTION OUTPUT ;
  USE SIGNAL ;
  PORT
   LAYER M5 ;
   RECT 89.952000 0.000000 89.976000 0.084000 ;
  END
 END k_li_d[465]
 PIN k_li_d[466]
  DIRECTION OUTPUT ;
  USE SIGNAL ;
  PORT
   LAYER M5 ;
   RECT 90.096000 0.000000 90.120000 0.084000 ;
  END
 END k_li_d[466]
 PIN k_li_d[467]
  DIRECTION OUTPUT ;
  USE SIGNAL ;
  PORT
   LAYER M5 ;
   RECT 90.288000 0.000000 90.312000 0.084000 ;
  END
 END k_li_d[467]
 PIN k_li_d[468]
  DIRECTION OUTPUT ;
  USE SIGNAL ;
  PORT
   LAYER M5 ;
   RECT 90.480000 0.000000 90.504000 0.084000 ;
  END
 END k_li_d[468]
 PIN k_li_d[469]
  DIRECTION OUTPUT ;
  USE SIGNAL ;
  PORT
   LAYER M5 ;
   RECT 90.672000 0.000000 90.696000 0.084000 ;
  END
 END k_li_d[469]
 PIN k_li_d[470]
  DIRECTION OUTPUT ;
  USE SIGNAL ;
  PORT
   LAYER M5 ;
   RECT 90.816000 0.000000 90.840000 0.084000 ;
  END
 END k_li_d[470]
 PIN k_li_d[471]
  DIRECTION OUTPUT ;
  USE SIGNAL ;
  PORT
   LAYER M5 ;
   RECT 91.008000 0.000000 91.032000 0.084000 ;
  END
 END k_li_d[471]
 PIN k_li_d[472]
  DIRECTION OUTPUT ;
  USE SIGNAL ;
  PORT
   LAYER M5 ;
   RECT 91.200000 0.000000 91.224000 0.084000 ;
  END
 END k_li_d[472]
 PIN k_li_d[473]
  DIRECTION OUTPUT ;
  USE SIGNAL ;
  PORT
   LAYER M5 ;
   RECT 91.392000 0.000000 91.416000 0.084000 ;
  END
 END k_li_d[473]
 PIN k_li_d[474]
  DIRECTION OUTPUT ;
  USE SIGNAL ;
  PORT
   LAYER M5 ;
   RECT 91.536000 0.000000 91.560000 0.084000 ;
  END
 END k_li_d[474]
 PIN k_li_d[475]
  DIRECTION OUTPUT ;
  USE SIGNAL ;
  PORT
   LAYER M5 ;
   RECT 91.728000 0.000000 91.752000 0.084000 ;
  END
 END k_li_d[475]
 PIN k_li_d[476]
  DIRECTION OUTPUT ;
  USE SIGNAL ;
  PORT
   LAYER M5 ;
   RECT 91.920000 0.000000 91.944000 0.084000 ;
  END
 END k_li_d[476]
 PIN k_li_d[477]
  DIRECTION OUTPUT ;
  USE SIGNAL ;
  PORT
   LAYER M5 ;
   RECT 92.112000 0.000000 92.136000 0.084000 ;
  END
 END k_li_d[477]
 PIN k_li_d[478]
  DIRECTION OUTPUT ;
  USE SIGNAL ;
  PORT
   LAYER M5 ;
   RECT 92.256000 0.000000 92.280000 0.084000 ;
  END
 END k_li_d[478]
 PIN k_li_d[479]
  DIRECTION OUTPUT ;
  USE SIGNAL ;
  PORT
   LAYER M5 ;
   RECT 92.448000 0.000000 92.472000 0.084000 ;
  END
 END k_li_d[479]
 PIN k_li_d[480]
  DIRECTION OUTPUT ;
  USE SIGNAL ;
  PORT
   LAYER M5 ;
   RECT 92.496000 0.000000 92.520000 0.084000 ;
  END
 END k_li_d[480]
 PIN k_li_d[481]
  DIRECTION OUTPUT ;
  USE SIGNAL ;
  PORT
   LAYER M5 ;
   RECT 92.544000 0.000000 92.568000 0.084000 ;
  END
 END k_li_d[481]
 PIN k_li_d[482]
  DIRECTION OUTPUT ;
  USE SIGNAL ;
  PORT
   LAYER M5 ;
   RECT 92.592000 0.000000 92.616000 0.084000 ;
  END
 END k_li_d[482]
 PIN k_li_d[483]
  DIRECTION OUTPUT ;
  USE SIGNAL ;
  PORT
   LAYER M5 ;
   RECT 93.168000 0.000000 93.192000 0.084000 ;
  END
 END k_li_d[483]
 PIN k_li_d[484]
  DIRECTION OUTPUT ;
  USE SIGNAL ;
  PORT
   LAYER M5 ;
   RECT 93.360000 0.000000 93.384000 0.084000 ;
  END
 END k_li_d[484]
 PIN k_li_d[485]
  DIRECTION OUTPUT ;
  USE SIGNAL ;
  PORT
   LAYER M5 ;
   RECT 93.504000 0.000000 93.528000 0.084000 ;
  END
 END k_li_d[485]
 PIN k_li_d[486]
  DIRECTION OUTPUT ;
  USE SIGNAL ;
  PORT
   LAYER M5 ;
   RECT 93.696000 0.000000 93.720000 0.084000 ;
  END
 END k_li_d[486]
 PIN k_li_d[487]
  DIRECTION OUTPUT ;
  USE SIGNAL ;
  PORT
   LAYER M5 ;
   RECT 93.888000 0.000000 93.912000 0.084000 ;
  END
 END k_li_d[487]
 PIN k_li_d[488]
  DIRECTION OUTPUT ;
  USE SIGNAL ;
  PORT
   LAYER M5 ;
   RECT 94.080000 0.000000 94.104000 0.084000 ;
  END
 END k_li_d[488]
 PIN k_li_d[489]
  DIRECTION OUTPUT ;
  USE SIGNAL ;
  PORT
   LAYER M5 ;
   RECT 94.224000 0.000000 94.248000 0.084000 ;
  END
 END k_li_d[489]
 PIN k_li_d[490]
  DIRECTION OUTPUT ;
  USE SIGNAL ;
  PORT
   LAYER M5 ;
   RECT 94.416000 0.000000 94.440000 0.084000 ;
  END
 END k_li_d[490]
 PIN k_li_d[491]
  DIRECTION OUTPUT ;
  USE SIGNAL ;
  PORT
   LAYER M5 ;
   RECT 94.608000 0.000000 94.632000 0.084000 ;
  END
 END k_li_d[491]
 PIN k_li_d[492]
  DIRECTION OUTPUT ;
  USE SIGNAL ;
  PORT
   LAYER M5 ;
   RECT 94.800000 0.000000 94.824000 0.084000 ;
  END
 END k_li_d[492]
 PIN k_li_d[493]
  DIRECTION OUTPUT ;
  USE SIGNAL ;
  PORT
   LAYER M5 ;
   RECT 94.944000 0.000000 94.968000 0.084000 ;
  END
 END k_li_d[493]
 PIN k_li_d[494]
  DIRECTION OUTPUT ;
  USE SIGNAL ;
  PORT
   LAYER M5 ;
   RECT 95.136000 0.000000 95.160000 0.084000 ;
  END
 END k_li_d[494]
 PIN k_li_d[495]
  DIRECTION OUTPUT ;
  USE SIGNAL ;
  PORT
   LAYER M5 ;
   RECT 95.328000 0.000000 95.352000 0.084000 ;
  END
 END k_li_d[495]
 PIN k_li_d[496]
  DIRECTION OUTPUT ;
  USE SIGNAL ;
  PORT
   LAYER M5 ;
   RECT 95.520000 0.000000 95.544000 0.084000 ;
  END
 END k_li_d[496]
 PIN k_li_d[497]
  DIRECTION OUTPUT ;
  USE SIGNAL ;
  PORT
   LAYER M5 ;
   RECT 95.664000 0.000000 95.688000 0.084000 ;
  END
 END k_li_d[497]
 PIN k_li_d[498]
  DIRECTION OUTPUT ;
  USE SIGNAL ;
  PORT
   LAYER M5 ;
   RECT 95.856000 0.000000 95.880000 0.084000 ;
  END
 END k_li_d[498]
 PIN k_li_d[499]
  DIRECTION OUTPUT ;
  USE SIGNAL ;
  PORT
   LAYER M5 ;
   RECT 96.048000 0.000000 96.072000 0.084000 ;
  END
 END k_li_d[499]
 PIN k_li_d[500]
  DIRECTION OUTPUT ;
  USE SIGNAL ;
  PORT
   LAYER M5 ;
   RECT 96.192000 0.000000 96.216000 0.084000 ;
  END
 END k_li_d[500]
 PIN k_li_d[501]
  DIRECTION OUTPUT ;
  USE SIGNAL ;
  PORT
   LAYER M5 ;
   RECT 96.384000 0.000000 96.408000 0.084000 ;
  END
 END k_li_d[501]
 PIN k_li_d[502]
  DIRECTION OUTPUT ;
  USE SIGNAL ;
  PORT
   LAYER M5 ;
   RECT 96.576000 0.000000 96.600000 0.084000 ;
  END
 END k_li_d[502]
 PIN k_li_d[503]
  DIRECTION OUTPUT ;
  USE SIGNAL ;
  PORT
   LAYER M5 ;
   RECT 96.768000 0.000000 96.792000 0.084000 ;
  END
 END k_li_d[503]
 PIN k_li_d[504]
  DIRECTION OUTPUT ;
  USE SIGNAL ;
  PORT
   LAYER M5 ;
   RECT 96.816000 0.000000 96.840000 0.084000 ;
  END
 END k_li_d[504]
 PIN k_li_d[505]
  DIRECTION OUTPUT ;
  USE SIGNAL ;
  PORT
   LAYER M5 ;
   RECT 96.864000 0.000000 96.888000 0.084000 ;
  END
 END k_li_d[505]
 PIN k_li_d[506]
  DIRECTION OUTPUT ;
  USE SIGNAL ;
  PORT
   LAYER M5 ;
   RECT 96.912000 0.000000 96.936000 0.084000 ;
  END
 END k_li_d[506]
 PIN k_li_d[507]
  DIRECTION OUTPUT ;
  USE SIGNAL ;
  PORT
   LAYER M5 ;
   RECT 97.488000 0.000000 97.512000 0.084000 ;
  END
 END k_li_d[507]
 PIN k_li_d[508]
  DIRECTION OUTPUT ;
  USE SIGNAL ;
  PORT
   LAYER M5 ;
   RECT 97.632000 0.000000 97.656000 0.084000 ;
  END
 END k_li_d[508]
 PIN k_li_d[509]
  DIRECTION OUTPUT ;
  USE SIGNAL ;
  PORT
   LAYER M5 ;
   RECT 97.824000 0.000000 97.848000 0.084000 ;
  END
 END k_li_d[509]
 PIN k_li_d[510]
  DIRECTION OUTPUT ;
  USE SIGNAL ;
  PORT
   LAYER M5 ;
   RECT 98.016000 0.000000 98.040000 0.084000 ;
  END
 END k_li_d[510]
 PIN k_li_d[511]
  DIRECTION OUTPUT ;
  USE SIGNAL ;
  PORT
   LAYER M5 ;
   RECT 98.208000 0.000000 98.232000 0.084000 ;
  END
 END k_li_d[511]
 PIN k_li_d[512]
  DIRECTION OUTPUT ;
  USE SIGNAL ;
  PORT
   LAYER M5 ;
   RECT 98.352000 0.000000 98.376000 0.084000 ;
  END
 END k_li_d[512]
 PIN k_li_d[513]
  DIRECTION OUTPUT ;
  USE SIGNAL ;
  PORT
   LAYER M5 ;
   RECT 98.544000 0.000000 98.568000 0.084000 ;
  END
 END k_li_d[513]
 PIN k_li_d[514]
  DIRECTION OUTPUT ;
  USE SIGNAL ;
  PORT
   LAYER M5 ;
   RECT 98.736000 0.000000 98.760000 0.084000 ;
  END
 END k_li_d[514]
 PIN k_li_d[515]
  DIRECTION OUTPUT ;
  USE SIGNAL ;
  PORT
   LAYER M5 ;
   RECT 98.880000 0.000000 98.904000 0.084000 ;
  END
 END k_li_d[515]
 PIN k_li_d[516]
  DIRECTION OUTPUT ;
  USE SIGNAL ;
  PORT
   LAYER M5 ;
   RECT 99.072000 0.000000 99.096000 0.084000 ;
  END
 END k_li_d[516]
 PIN k_li_d[517]
  DIRECTION OUTPUT ;
  USE SIGNAL ;
  PORT
   LAYER M5 ;
   RECT 99.264000 0.000000 99.288000 0.084000 ;
  END
 END k_li_d[517]
 PIN k_li_d[518]
  DIRECTION OUTPUT ;
  USE SIGNAL ;
  PORT
   LAYER M5 ;
   RECT 99.456000 0.000000 99.480000 0.084000 ;
  END
 END k_li_d[518]
 PIN k_li_d[519]
  DIRECTION OUTPUT ;
  USE SIGNAL ;
  PORT
   LAYER M5 ;
   RECT 99.600000 0.000000 99.624000 0.084000 ;
  END
 END k_li_d[519]
 PIN k_li_d[520]
  DIRECTION OUTPUT ;
  USE SIGNAL ;
  PORT
   LAYER M5 ;
   RECT 99.792000 0.000000 99.816000 0.084000 ;
  END
 END k_li_d[520]
 PIN k_li_d[521]
  DIRECTION OUTPUT ;
  USE SIGNAL ;
  PORT
   LAYER M5 ;
   RECT 99.984000 0.000000 100.008000 0.084000 ;
  END
 END k_li_d[521]
 PIN k_li_d[522]
  DIRECTION OUTPUT ;
  USE SIGNAL ;
  PORT
   LAYER M5 ;
   RECT 100.176000 0.000000 100.200000 0.084000 ;
  END
 END k_li_d[522]
 PIN k_li_d[523]
  DIRECTION OUTPUT ;
  USE SIGNAL ;
  PORT
   LAYER M5 ;
   RECT 100.320000 0.000000 100.344000 0.084000 ;
  END
 END k_li_d[523]
 PIN k_li_d[524]
  DIRECTION OUTPUT ;
  USE SIGNAL ;
  PORT
   LAYER M5 ;
   RECT 100.512000 0.000000 100.536000 0.084000 ;
  END
 END k_li_d[524]
 PIN k_li_d[525]
  DIRECTION OUTPUT ;
  USE SIGNAL ;
  PORT
   LAYER M5 ;
   RECT 100.704000 0.000000 100.728000 0.084000 ;
  END
 END k_li_d[525]
 PIN k_li_d[526]
  DIRECTION OUTPUT ;
  USE SIGNAL ;
  PORT
   LAYER M5 ;
   RECT 100.896000 0.000000 100.920000 0.084000 ;
  END
 END k_li_d[526]
 PIN k_li_d[527]
  DIRECTION OUTPUT ;
  USE SIGNAL ;
  PORT
   LAYER M5 ;
   RECT 101.040000 0.000000 101.064000 0.084000 ;
  END
 END k_li_d[527]
 PIN k_li_d[528]
  DIRECTION OUTPUT ;
  USE SIGNAL ;
  PORT
   LAYER M5 ;
   RECT 101.136000 0.000000 101.160000 0.084000 ;
  END
 END k_li_d[528]
 PIN k_li_d[529]
  DIRECTION OUTPUT ;
  USE SIGNAL ;
  PORT
   LAYER M5 ;
   RECT 101.184000 0.000000 101.208000 0.084000 ;
  END
 END k_li_d[529]
 PIN k_li_d[530]
  DIRECTION OUTPUT ;
  USE SIGNAL ;
  PORT
   LAYER M5 ;
   RECT 101.232000 0.000000 101.256000 0.084000 ;
  END
 END k_li_d[530]
 PIN k_li_d[531]
  DIRECTION OUTPUT ;
  USE SIGNAL ;
  PORT
   LAYER M5 ;
   RECT 101.808000 0.000000 101.832000 0.084000 ;
  END
 END k_li_d[531]
 PIN k_li_d[532]
  DIRECTION OUTPUT ;
  USE SIGNAL ;
  PORT
   LAYER M5 ;
   RECT 101.952000 0.000000 101.976000 0.084000 ;
  END
 END k_li_d[532]
 PIN k_li_d[533]
  DIRECTION OUTPUT ;
  USE SIGNAL ;
  PORT
   LAYER M5 ;
   RECT 102.144000 0.000000 102.168000 0.084000 ;
  END
 END k_li_d[533]
 PIN k_li_d[534]
  DIRECTION OUTPUT ;
  USE SIGNAL ;
  PORT
   LAYER M5 ;
   RECT 102.288000 0.000000 102.312000 0.084000 ;
  END
 END k_li_d[534]
 PIN k_li_d[535]
  DIRECTION OUTPUT ;
  USE SIGNAL ;
  PORT
   LAYER M5 ;
   RECT 102.480000 0.000000 102.504000 0.084000 ;
  END
 END k_li_d[535]
 PIN k_li_d[536]
  DIRECTION OUTPUT ;
  USE SIGNAL ;
  PORT
   LAYER M5 ;
   RECT 102.672000 0.000000 102.696000 0.084000 ;
  END
 END k_li_d[536]
 PIN k_li_d[537]
  DIRECTION OUTPUT ;
  USE SIGNAL ;
  PORT
   LAYER M5 ;
   RECT 102.864000 0.000000 102.888000 0.084000 ;
  END
 END k_li_d[537]
 PIN k_li_d[538]
  DIRECTION OUTPUT ;
  USE SIGNAL ;
  PORT
   LAYER M5 ;
   RECT 103.008000 0.000000 103.032000 0.084000 ;
  END
 END k_li_d[538]
 PIN k_li_d[539]
  DIRECTION OUTPUT ;
  USE SIGNAL ;
  PORT
   LAYER M5 ;
   RECT 103.200000 0.000000 103.224000 0.084000 ;
  END
 END k_li_d[539]
 PIN k_li_d[540]
  DIRECTION OUTPUT ;
  USE SIGNAL ;
  PORT
   LAYER M5 ;
   RECT 103.392000 0.000000 103.416000 0.084000 ;
  END
 END k_li_d[540]
 PIN k_li_d[541]
  DIRECTION OUTPUT ;
  USE SIGNAL ;
  PORT
   LAYER M5 ;
   RECT 103.584000 0.000000 103.608000 0.084000 ;
  END
 END k_li_d[541]
 PIN k_li_d[542]
  DIRECTION OUTPUT ;
  USE SIGNAL ;
  PORT
   LAYER M5 ;
   RECT 103.728000 0.000000 103.752000 0.084000 ;
  END
 END k_li_d[542]
 PIN k_li_d[543]
  DIRECTION OUTPUT ;
  USE SIGNAL ;
  PORT
   LAYER M5 ;
   RECT 103.920000 0.000000 103.944000 0.084000 ;
  END
 END k_li_d[543]
 PIN k_li_d[544]
  DIRECTION OUTPUT ;
  USE SIGNAL ;
  PORT
   LAYER M5 ;
   RECT 104.112000 0.000000 104.136000 0.084000 ;
  END
 END k_li_d[544]
 PIN k_li_d[545]
  DIRECTION OUTPUT ;
  USE SIGNAL ;
  PORT
   LAYER M5 ;
   RECT 104.304000 0.000000 104.328000 0.084000 ;
  END
 END k_li_d[545]
 PIN k_li_d[546]
  DIRECTION OUTPUT ;
  USE SIGNAL ;
  PORT
   LAYER M5 ;
   RECT 104.448000 0.000000 104.472000 0.084000 ;
  END
 END k_li_d[546]
 PIN k_li_d[547]
  DIRECTION OUTPUT ;
  USE SIGNAL ;
  PORT
   LAYER M5 ;
   RECT 104.640000 0.000000 104.664000 0.084000 ;
  END
 END k_li_d[547]
 PIN k_li_d[548]
  DIRECTION OUTPUT ;
  USE SIGNAL ;
  PORT
   LAYER M5 ;
   RECT 104.832000 0.000000 104.856000 0.084000 ;
  END
 END k_li_d[548]
 PIN k_li_d[549]
  DIRECTION OUTPUT ;
  USE SIGNAL ;
  PORT
   LAYER M5 ;
   RECT 104.976000 0.000000 105.000000 0.084000 ;
  END
 END k_li_d[549]
 PIN k_li_d[550]
  DIRECTION OUTPUT ;
  USE SIGNAL ;
  PORT
   LAYER M5 ;
   RECT 105.168000 0.000000 105.192000 0.084000 ;
  END
 END k_li_d[550]
 PIN k_li_d[551]
  DIRECTION OUTPUT ;
  USE SIGNAL ;
  PORT
   LAYER M5 ;
   RECT 105.360000 0.000000 105.384000 0.084000 ;
  END
 END k_li_d[551]
 PIN k_li_d[552]
  DIRECTION OUTPUT ;
  USE SIGNAL ;
  PORT
   LAYER M5 ;
   RECT 105.456000 0.000000 105.480000 0.084000 ;
  END
 END k_li_d[552]
 PIN k_flt[0]
  DIRECTION OUTPUT ;
  USE SIGNAL ;
  PORT
   LAYER M5 ;
   RECT 105.504000 0.000000 105.528000 0.084000 ;
  END
 END k_flt[0]
 PIN k_flt[1]
  DIRECTION OUTPUT ;
  USE SIGNAL ;
  PORT
   LAYER M5 ;
   RECT 105.552000 0.000000 105.576000 0.084000 ;
  END
 END k_flt[1]
 PIN k_flt[2]
  DIRECTION OUTPUT ;
  USE SIGNAL ;
  PORT
   LAYER M5 ;
   RECT 106.128000 0.000000 106.152000 0.084000 ;
  END
 END k_flt[2]
 PIN n_lo_r
  DIRECTION INPUT ;
  USE SIGNAL ;
  PORT
   LAYER M4 ;
   RECT 112.236000 6.240000 112.320000 6.264000 ;
  END
 END n_lo_r
 PIN n_li_v
  DIRECTION INPUT ;
  USE SIGNAL ;
  PORT
   LAYER M4 ;
   RECT 112.236000 6.384000 112.320000 6.408000 ;
  END
 END n_li_v
 PIN n_li_d[0]
  DIRECTION INPUT ;
  USE SIGNAL ;
  PORT
   LAYER M4 ;
   RECT 112.236000 6.576000 112.320000 6.600000 ;
  END
 END n_li_d[0]
 PIN n_li_d[1]
  DIRECTION INPUT ;
  USE SIGNAL ;
  PORT
   LAYER M4 ;
   RECT 112.236000 6.768000 112.320000 6.792000 ;
  END
 END n_li_d[1]
 PIN n_li_d[2]
  DIRECTION INPUT ;
  USE SIGNAL ;
  PORT
   LAYER M4 ;
   RECT 112.236000 6.960000 112.320000 6.984000 ;
  END
 END n_li_d[2]
 PIN n_li_d[3]
  DIRECTION INPUT ;
  USE SIGNAL ;
  PORT
   LAYER M4 ;
   RECT 112.236000 7.104000 112.320000 7.128000 ;
  END
 END n_li_d[3]
 PIN n_li_d[4]
  DIRECTION INPUT ;
  USE SIGNAL ;
  PORT
   LAYER M4 ;
   RECT 112.236000 7.296000 112.320000 7.320000 ;
  END
 END n_li_d[4]
 PIN n_li_d[5]
  DIRECTION INPUT ;
  USE SIGNAL ;
  PORT
   LAYER M4 ;
   RECT 112.236000 7.488000 112.320000 7.512000 ;
  END
 END n_li_d[5]
 PIN n_li_d[6]
  DIRECTION INPUT ;
  USE SIGNAL ;
  PORT
   LAYER M4 ;
   RECT 112.236000 7.632000 112.320000 7.656000 ;
  END
 END n_li_d[6]
 PIN n_li_d[7]
  DIRECTION INPUT ;
  USE SIGNAL ;
  PORT
   LAYER M4 ;
   RECT 112.236000 7.824000 112.320000 7.848000 ;
  END
 END n_li_d[7]
 PIN n_li_d[8]
  DIRECTION INPUT ;
  USE SIGNAL ;
  PORT
   LAYER M4 ;
   RECT 112.236000 8.016000 112.320000 8.040000 ;
  END
 END n_li_d[8]
 PIN n_li_d[9]
  DIRECTION INPUT ;
  USE SIGNAL ;
  PORT
   LAYER M4 ;
   RECT 112.236000 8.208000 112.320000 8.232000 ;
  END
 END n_li_d[9]
 PIN n_li_d[10]
  DIRECTION INPUT ;
  USE SIGNAL ;
  PORT
   LAYER M4 ;
   RECT 112.236000 8.352000 112.320000 8.376000 ;
  END
 END n_li_d[10]
 PIN n_li_d[11]
  DIRECTION INPUT ;
  USE SIGNAL ;
  PORT
   LAYER M4 ;
   RECT 112.236000 8.544000 112.320000 8.568000 ;
  END
 END n_li_d[11]
 PIN n_li_d[12]
  DIRECTION INPUT ;
  USE SIGNAL ;
  PORT
   LAYER M4 ;
   RECT 112.236000 8.736000 112.320000 8.760000 ;
  END
 END n_li_d[12]
 PIN n_li_d[13]
  DIRECTION INPUT ;
  USE SIGNAL ;
  PORT
   LAYER M4 ;
   RECT 112.236000 8.928000 112.320000 8.952000 ;
  END
 END n_li_d[13]
 PIN n_li_d[14]
  DIRECTION INPUT ;
  USE SIGNAL ;
  PORT
   LAYER M4 ;
   RECT 112.236000 9.072000 112.320000 9.096000 ;
  END
 END n_li_d[14]
 PIN n_li_d[15]
  DIRECTION INPUT ;
  USE SIGNAL ;
  PORT
   LAYER M4 ;
   RECT 112.236000 9.264000 112.320000 9.288000 ;
  END
 END n_li_d[15]
 PIN n_li_d[16]
  DIRECTION INPUT ;
  USE SIGNAL ;
  PORT
   LAYER M4 ;
   RECT 112.236000 9.456000 112.320000 9.480000 ;
  END
 END n_li_d[16]
 PIN n_li_d[17]
  DIRECTION INPUT ;
  USE SIGNAL ;
  PORT
   LAYER M4 ;
   RECT 112.236000 9.648000 112.320000 9.672000 ;
  END
 END n_li_d[17]
 PIN n_li_d[18]
  DIRECTION INPUT ;
  USE SIGNAL ;
  PORT
   LAYER M4 ;
   RECT 112.236000 9.792000 112.320000 9.816000 ;
  END
 END n_li_d[18]
 PIN n_li_d[19]
  DIRECTION INPUT ;
  USE SIGNAL ;
  PORT
   LAYER M4 ;
   RECT 112.236000 9.984000 112.320000 10.008000 ;
  END
 END n_li_d[19]
 PIN n_li_d[20]
  DIRECTION INPUT ;
  USE SIGNAL ;
  PORT
   LAYER M4 ;
   RECT 112.236000 10.176000 112.320000 10.200000 ;
  END
 END n_li_d[20]
 PIN n_li_d[21]
  DIRECTION INPUT ;
  USE SIGNAL ;
  PORT
   LAYER M4 ;
   RECT 112.236000 10.368000 112.320000 10.392000 ;
  END
 END n_li_d[21]
 PIN n_li_d[22]
  DIRECTION INPUT ;
  USE SIGNAL ;
  PORT
   LAYER M4 ;
   RECT 112.236000 10.512000 112.320000 10.536000 ;
  END
 END n_li_d[22]
 PIN n_li_d[23]
  DIRECTION INPUT ;
  USE SIGNAL ;
  PORT
   LAYER M4 ;
   RECT 112.236000 10.704000 112.320000 10.728000 ;
  END
 END n_li_d[23]
 PIN n_li_d[24]
  DIRECTION INPUT ;
  USE SIGNAL ;
  PORT
   LAYER M4 ;
   RECT 112.236000 10.896000 112.320000 10.920000 ;
  END
 END n_li_d[24]
 PIN n_li_d[25]
  DIRECTION INPUT ;
  USE SIGNAL ;
  PORT
   LAYER M4 ;
   RECT 112.236000 11.040000 112.320000 11.064000 ;
  END
 END n_li_d[25]
 PIN n_li_d[26]
  DIRECTION INPUT ;
  USE SIGNAL ;
  PORT
   LAYER M4 ;
   RECT 112.236000 11.232000 112.320000 11.256000 ;
  END
 END n_li_d[26]
 PIN n_li_d[27]
  DIRECTION INPUT ;
  USE SIGNAL ;
  PORT
   LAYER M4 ;
   RECT 112.236000 11.424000 112.320000 11.448000 ;
  END
 END n_li_d[27]
 PIN n_li_d[28]
  DIRECTION INPUT ;
  USE SIGNAL ;
  PORT
   LAYER M4 ;
   RECT 112.236000 11.616000 112.320000 11.640000 ;
  END
 END n_li_d[28]
 PIN n_li_d[29]
  DIRECTION INPUT ;
  USE SIGNAL ;
  PORT
   LAYER M4 ;
   RECT 112.236000 11.760000 112.320000 11.784000 ;
  END
 END n_li_d[29]
 PIN n_li_d[30]
  DIRECTION INPUT ;
  USE SIGNAL ;
  PORT
   LAYER M4 ;
   RECT 112.236000 11.952000 112.320000 11.976000 ;
  END
 END n_li_d[30]
 PIN n_li_d[31]
  DIRECTION INPUT ;
  USE SIGNAL ;
  PORT
   LAYER M4 ;
   RECT 112.236000 12.144000 112.320000 12.168000 ;
  END
 END n_li_d[31]
 PIN n_li_d[32]
  DIRECTION INPUT ;
  USE SIGNAL ;
  PORT
   LAYER M4 ;
   RECT 112.236000 12.336000 112.320000 12.360000 ;
  END
 END n_li_d[32]
 PIN n_li_d[33]
  DIRECTION INPUT ;
  USE SIGNAL ;
  PORT
   LAYER M4 ;
   RECT 112.236000 12.480000 112.320000 12.504000 ;
  END
 END n_li_d[33]
 PIN n_li_d[34]
  DIRECTION INPUT ;
  USE SIGNAL ;
  PORT
   LAYER M4 ;
   RECT 112.236000 12.672000 112.320000 12.696000 ;
  END
 END n_li_d[34]
 PIN n_li_d[35]
  DIRECTION INPUT ;
  USE SIGNAL ;
  PORT
   LAYER M4 ;
   RECT 112.236000 12.864000 112.320000 12.888000 ;
  END
 END n_li_d[35]
 PIN n_li_d[36]
  DIRECTION INPUT ;
  USE SIGNAL ;
  PORT
   LAYER M4 ;
   RECT 112.236000 13.056000 112.320000 13.080000 ;
  END
 END n_li_d[36]
 PIN n_li_d[37]
  DIRECTION INPUT ;
  USE SIGNAL ;
  PORT
   LAYER M4 ;
   RECT 112.236000 13.200000 112.320000 13.224000 ;
  END
 END n_li_d[37]
 PIN n_li_d[38]
  DIRECTION INPUT ;
  USE SIGNAL ;
  PORT
   LAYER M4 ;
   RECT 112.236000 13.392000 112.320000 13.416000 ;
  END
 END n_li_d[38]
 PIN n_li_d[39]
  DIRECTION INPUT ;
  USE SIGNAL ;
  PORT
   LAYER M4 ;
   RECT 112.236000 13.584000 112.320000 13.608000 ;
  END
 END n_li_d[39]
 PIN n_li_d[40]
  DIRECTION INPUT ;
  USE SIGNAL ;
  PORT
   LAYER M4 ;
   RECT 112.236000 13.728000 112.320000 13.752000 ;
  END
 END n_li_d[40]
 PIN n_li_d[41]
  DIRECTION INPUT ;
  USE SIGNAL ;
  PORT
   LAYER M4 ;
   RECT 112.236000 13.920000 112.320000 13.944000 ;
  END
 END n_li_d[41]
 PIN n_li_d[42]
  DIRECTION INPUT ;
  USE SIGNAL ;
  PORT
   LAYER M4 ;
   RECT 112.236000 14.112000 112.320000 14.136000 ;
  END
 END n_li_d[42]
 PIN n_li_d[43]
  DIRECTION INPUT ;
  USE SIGNAL ;
  PORT
   LAYER M4 ;
   RECT 112.236000 14.304000 112.320000 14.328000 ;
  END
 END n_li_d[43]
 PIN n_li_d[44]
  DIRECTION INPUT ;
  USE SIGNAL ;
  PORT
   LAYER M4 ;
   RECT 112.236000 14.448000 112.320000 14.472000 ;
  END
 END n_li_d[44]
 PIN n_li_d[45]
  DIRECTION INPUT ;
  USE SIGNAL ;
  PORT
   LAYER M4 ;
   RECT 112.236000 14.640000 112.320000 14.664000 ;
  END
 END n_li_d[45]
 PIN n_li_d[46]
  DIRECTION INPUT ;
  USE SIGNAL ;
  PORT
   LAYER M4 ;
   RECT 112.236000 14.832000 112.320000 14.856000 ;
  END
 END n_li_d[46]
 PIN n_li_d[47]
  DIRECTION INPUT ;
  USE SIGNAL ;
  PORT
   LAYER M4 ;
   RECT 112.236000 15.024000 112.320000 15.048000 ;
  END
 END n_li_d[47]
 PIN n_li_d[48]
  DIRECTION INPUT ;
  USE SIGNAL ;
  PORT
   LAYER M4 ;
   RECT 112.236000 15.168000 112.320000 15.192000 ;
  END
 END n_li_d[48]
 PIN n_li_d[49]
  DIRECTION INPUT ;
  USE SIGNAL ;
  PORT
   LAYER M4 ;
   RECT 112.236000 15.360000 112.320000 15.384000 ;
  END
 END n_li_d[49]
 PIN n_li_d[50]
  DIRECTION INPUT ;
  USE SIGNAL ;
  PORT
   LAYER M4 ;
   RECT 112.236000 15.552000 112.320000 15.576000 ;
  END
 END n_li_d[50]
 PIN n_li_d[51]
  DIRECTION INPUT ;
  USE SIGNAL ;
  PORT
   LAYER M4 ;
   RECT 112.236000 15.744000 112.320000 15.768000 ;
  END
 END n_li_d[51]
 PIN n_li_d[52]
  DIRECTION INPUT ;
  USE SIGNAL ;
  PORT
   LAYER M4 ;
   RECT 112.236000 15.888000 112.320000 15.912000 ;
  END
 END n_li_d[52]
 PIN n_li_d[53]
  DIRECTION INPUT ;
  USE SIGNAL ;
  PORT
   LAYER M4 ;
   RECT 112.236000 16.080000 112.320000 16.104000 ;
  END
 END n_li_d[53]
 PIN n_li_d[54]
  DIRECTION INPUT ;
  USE SIGNAL ;
  PORT
   LAYER M4 ;
   RECT 112.236000 16.272000 112.320000 16.296000 ;
  END
 END n_li_d[54]
 PIN n_li_d[55]
  DIRECTION INPUT ;
  USE SIGNAL ;
  PORT
   LAYER M4 ;
   RECT 112.236000 16.416000 112.320000 16.440000 ;
  END
 END n_li_d[55]
 PIN n_li_d[56]
  DIRECTION INPUT ;
  USE SIGNAL ;
  PORT
   LAYER M4 ;
   RECT 112.236000 16.608000 112.320000 16.632000 ;
  END
 END n_li_d[56]
 PIN n_li_d[57]
  DIRECTION INPUT ;
  USE SIGNAL ;
  PORT
   LAYER M4 ;
   RECT 112.236000 16.800000 112.320000 16.824000 ;
  END
 END n_li_d[57]
 PIN n_li_d[58]
  DIRECTION INPUT ;
  USE SIGNAL ;
  PORT
   LAYER M4 ;
   RECT 112.236000 16.992000 112.320000 17.016000 ;
  END
 END n_li_d[58]
 PIN n_li_d[59]
  DIRECTION INPUT ;
  USE SIGNAL ;
  PORT
   LAYER M4 ;
   RECT 112.236000 17.136000 112.320000 17.160000 ;
  END
 END n_li_d[59]
 PIN n_li_d[60]
  DIRECTION INPUT ;
  USE SIGNAL ;
  PORT
   LAYER M4 ;
   RECT 112.236000 17.328000 112.320000 17.352000 ;
  END
 END n_li_d[60]
 PIN n_li_d[61]
  DIRECTION INPUT ;
  USE SIGNAL ;
  PORT
   LAYER M4 ;
   RECT 112.236000 17.520000 112.320000 17.544000 ;
  END
 END n_li_d[61]
 PIN n_li_d[62]
  DIRECTION INPUT ;
  USE SIGNAL ;
  PORT
   LAYER M4 ;
   RECT 112.236000 17.712000 112.320000 17.736000 ;
  END
 END n_li_d[62]
 PIN n_li_d[63]
  DIRECTION INPUT ;
  USE SIGNAL ;
  PORT
   LAYER M4 ;
   RECT 112.236000 17.856000 112.320000 17.880000 ;
  END
 END n_li_d[63]
 PIN n_li_d[64]
  DIRECTION INPUT ;
  USE SIGNAL ;
  PORT
   LAYER M4 ;
   RECT 112.236000 18.048000 112.320000 18.072000 ;
  END
 END n_li_d[64]
 PIN n_li_d[65]
  DIRECTION INPUT ;
  USE SIGNAL ;
  PORT
   LAYER M4 ;
   RECT 112.236000 18.240000 112.320000 18.264000 ;
  END
 END n_li_d[65]
 PIN n_li_d[66]
  DIRECTION INPUT ;
  USE SIGNAL ;
  PORT
   LAYER M4 ;
   RECT 112.236000 18.432000 112.320000 18.456000 ;
  END
 END n_li_d[66]
 PIN n_li_d[67]
  DIRECTION INPUT ;
  USE SIGNAL ;
  PORT
   LAYER M4 ;
   RECT 112.236000 18.576000 112.320000 18.600000 ;
  END
 END n_li_d[67]
 PIN n_li_d[68]
  DIRECTION INPUT ;
  USE SIGNAL ;
  PORT
   LAYER M4 ;
   RECT 112.236000 18.768000 112.320000 18.792000 ;
  END
 END n_li_d[68]
 PIN n_li_d[69]
  DIRECTION INPUT ;
  USE SIGNAL ;
  PORT
   LAYER M4 ;
   RECT 112.236000 18.960000 112.320000 18.984000 ;
  END
 END n_li_d[69]
 PIN n_li_d[70]
  DIRECTION INPUT ;
  USE SIGNAL ;
  PORT
   LAYER M4 ;
   RECT 112.236000 19.152000 112.320000 19.176000 ;
  END
 END n_li_d[70]
 PIN n_li_d[71]
  DIRECTION INPUT ;
  USE SIGNAL ;
  PORT
   LAYER M4 ;
   RECT 112.236000 19.296000 112.320000 19.320000 ;
  END
 END n_li_d[71]
 PIN n_li_d[72]
  DIRECTION INPUT ;
  USE SIGNAL ;
  PORT
   LAYER M4 ;
   RECT 112.236000 19.488000 112.320000 19.512000 ;
  END
 END n_li_d[72]
 PIN n_li_d[73]
  DIRECTION INPUT ;
  USE SIGNAL ;
  PORT
   LAYER M4 ;
   RECT 112.236000 19.680000 112.320000 19.704000 ;
  END
 END n_li_d[73]
 PIN n_li_d[74]
  DIRECTION INPUT ;
  USE SIGNAL ;
  PORT
   LAYER M4 ;
   RECT 112.236000 19.824000 112.320000 19.848000 ;
  END
 END n_li_d[74]
 PIN n_li_d[75]
  DIRECTION INPUT ;
  USE SIGNAL ;
  PORT
   LAYER M4 ;
   RECT 112.236000 20.016000 112.320000 20.040000 ;
  END
 END n_li_d[75]
 PIN n_li_d[76]
  DIRECTION INPUT ;
  USE SIGNAL ;
  PORT
   LAYER M4 ;
   RECT 112.236000 20.208000 112.320000 20.232000 ;
  END
 END n_li_d[76]
 PIN n_li_d[77]
  DIRECTION INPUT ;
  USE SIGNAL ;
  PORT
   LAYER M4 ;
   RECT 112.236000 20.400000 112.320000 20.424000 ;
  END
 END n_li_d[77]
 PIN n_li_d[78]
  DIRECTION INPUT ;
  USE SIGNAL ;
  PORT
   LAYER M4 ;
   RECT 112.236000 20.544000 112.320000 20.568000 ;
  END
 END n_li_d[78]
 PIN n_li_d[79]
  DIRECTION INPUT ;
  USE SIGNAL ;
  PORT
   LAYER M4 ;
   RECT 112.236000 20.736000 112.320000 20.760000 ;
  END
 END n_li_d[79]
 PIN n_li_d[80]
  DIRECTION INPUT ;
  USE SIGNAL ;
  PORT
   LAYER M4 ;
   RECT 112.236000 20.928000 112.320000 20.952000 ;
  END
 END n_li_d[80]
 PIN n_li_d[81]
  DIRECTION INPUT ;
  USE SIGNAL ;
  PORT
   LAYER M4 ;
   RECT 112.236000 21.120000 112.320000 21.144000 ;
  END
 END n_li_d[81]
 PIN n_li_d[82]
  DIRECTION INPUT ;
  USE SIGNAL ;
  PORT
   LAYER M4 ;
   RECT 112.236000 21.264000 112.320000 21.288000 ;
  END
 END n_li_d[82]
 PIN n_li_d[83]
  DIRECTION INPUT ;
  USE SIGNAL ;
  PORT
   LAYER M4 ;
   RECT 112.236000 21.456000 112.320000 21.480000 ;
  END
 END n_li_d[83]
 PIN n_li_d[84]
  DIRECTION INPUT ;
  USE SIGNAL ;
  PORT
   LAYER M4 ;
   RECT 112.236000 21.648000 112.320000 21.672000 ;
  END
 END n_li_d[84]
 PIN n_li_d[85]
  DIRECTION INPUT ;
  USE SIGNAL ;
  PORT
   LAYER M4 ;
   RECT 112.236000 21.840000 112.320000 21.864000 ;
  END
 END n_li_d[85]
 PIN n_li_d[86]
  DIRECTION INPUT ;
  USE SIGNAL ;
  PORT
   LAYER M4 ;
   RECT 112.236000 21.984000 112.320000 22.008000 ;
  END
 END n_li_d[86]
 PIN n_li_d[87]
  DIRECTION INPUT ;
  USE SIGNAL ;
  PORT
   LAYER M4 ;
   RECT 112.236000 22.176000 112.320000 22.200000 ;
  END
 END n_li_d[87]
 PIN n_li_d[88]
  DIRECTION INPUT ;
  USE SIGNAL ;
  PORT
   LAYER M4 ;
   RECT 112.236000 22.368000 112.320000 22.392000 ;
  END
 END n_li_d[88]
 PIN n_li_d[89]
  DIRECTION INPUT ;
  USE SIGNAL ;
  PORT
   LAYER M4 ;
   RECT 112.236000 22.512000 112.320000 22.536000 ;
  END
 END n_li_d[89]
 PIN n_li_d[90]
  DIRECTION INPUT ;
  USE SIGNAL ;
  PORT
   LAYER M4 ;
   RECT 112.236000 22.704000 112.320000 22.728000 ;
  END
 END n_li_d[90]
 PIN n_li_d[91]
  DIRECTION INPUT ;
  USE SIGNAL ;
  PORT
   LAYER M4 ;
   RECT 112.236000 22.896000 112.320000 22.920000 ;
  END
 END n_li_d[91]
 PIN n_li_d[92]
  DIRECTION INPUT ;
  USE SIGNAL ;
  PORT
   LAYER M4 ;
   RECT 112.236000 23.088000 112.320000 23.112000 ;
  END
 END n_li_d[92]
 PIN n_li_d[93]
  DIRECTION INPUT ;
  USE SIGNAL ;
  PORT
   LAYER M4 ;
   RECT 112.236000 23.232000 112.320000 23.256000 ;
  END
 END n_li_d[93]
 PIN n_li_d[94]
  DIRECTION INPUT ;
  USE SIGNAL ;
  PORT
   LAYER M4 ;
   RECT 112.236000 23.424000 112.320000 23.448000 ;
  END
 END n_li_d[94]
 PIN n_li_d[95]
  DIRECTION INPUT ;
  USE SIGNAL ;
  PORT
   LAYER M4 ;
   RECT 112.236000 23.616000 112.320000 23.640000 ;
  END
 END n_li_d[95]
 PIN n_li_d[96]
  DIRECTION INPUT ;
  USE SIGNAL ;
  PORT
   LAYER M4 ;
   RECT 112.236000 23.808000 112.320000 23.832000 ;
  END
 END n_li_d[96]
 PIN n_li_d[97]
  DIRECTION INPUT ;
  USE SIGNAL ;
  PORT
   LAYER M4 ;
   RECT 112.236000 23.952000 112.320000 23.976000 ;
  END
 END n_li_d[97]
 PIN n_li_d[98]
  DIRECTION INPUT ;
  USE SIGNAL ;
  PORT
   LAYER M4 ;
   RECT 112.236000 24.144000 112.320000 24.168000 ;
  END
 END n_li_d[98]
 PIN n_li_d[99]
  DIRECTION INPUT ;
  USE SIGNAL ;
  PORT
   LAYER M4 ;
   RECT 112.236000 24.336000 112.320000 24.360000 ;
  END
 END n_li_d[99]
 PIN n_li_d[100]
  DIRECTION INPUT ;
  USE SIGNAL ;
  PORT
   LAYER M4 ;
   RECT 112.236000 24.528000 112.320000 24.552000 ;
  END
 END n_li_d[100]
 PIN n_li_d[101]
  DIRECTION INPUT ;
  USE SIGNAL ;
  PORT
   LAYER M4 ;
   RECT 112.236000 24.672000 112.320000 24.696000 ;
  END
 END n_li_d[101]
 PIN n_li_d[102]
  DIRECTION INPUT ;
  USE SIGNAL ;
  PORT
   LAYER M4 ;
   RECT 112.236000 24.864000 112.320000 24.888000 ;
  END
 END n_li_d[102]
 PIN n_li_d[103]
  DIRECTION INPUT ;
  USE SIGNAL ;
  PORT
   LAYER M4 ;
   RECT 112.236000 25.056000 112.320000 25.080000 ;
  END
 END n_li_d[103]
 PIN n_li_d[104]
  DIRECTION INPUT ;
  USE SIGNAL ;
  PORT
   LAYER M4 ;
   RECT 112.236000 25.248000 112.320000 25.272000 ;
  END
 END n_li_d[104]
 PIN n_li_d[105]
  DIRECTION INPUT ;
  USE SIGNAL ;
  PORT
   LAYER M4 ;
   RECT 112.236000 25.392000 112.320000 25.416000 ;
  END
 END n_li_d[105]
 PIN n_li_d[106]
  DIRECTION INPUT ;
  USE SIGNAL ;
  PORT
   LAYER M4 ;
   RECT 112.236000 25.584000 112.320000 25.608000 ;
  END
 END n_li_d[106]
 PIN n_li_d[107]
  DIRECTION INPUT ;
  USE SIGNAL ;
  PORT
   LAYER M4 ;
   RECT 112.236000 25.776000 112.320000 25.800000 ;
  END
 END n_li_d[107]
 PIN n_li_d[108]
  DIRECTION INPUT ;
  USE SIGNAL ;
  PORT
   LAYER M4 ;
   RECT 112.236000 25.920000 112.320000 25.944000 ;
  END
 END n_li_d[108]
 PIN n_li_d[109]
  DIRECTION INPUT ;
  USE SIGNAL ;
  PORT
   LAYER M4 ;
   RECT 112.236000 26.112000 112.320000 26.136000 ;
  END
 END n_li_d[109]
 PIN n_li_d[110]
  DIRECTION INPUT ;
  USE SIGNAL ;
  PORT
   LAYER M4 ;
   RECT 112.236000 26.304000 112.320000 26.328000 ;
  END
 END n_li_d[110]
 PIN n_li_d[111]
  DIRECTION INPUT ;
  USE SIGNAL ;
  PORT
   LAYER M4 ;
   RECT 112.236000 26.496000 112.320000 26.520000 ;
  END
 END n_li_d[111]
 PIN n_li_d[112]
  DIRECTION INPUT ;
  USE SIGNAL ;
  PORT
   LAYER M4 ;
   RECT 112.236000 26.640000 112.320000 26.664000 ;
  END
 END n_li_d[112]
 PIN n_li_d[113]
  DIRECTION INPUT ;
  USE SIGNAL ;
  PORT
   LAYER M4 ;
   RECT 112.236000 26.832000 112.320000 26.856000 ;
  END
 END n_li_d[113]
 PIN n_li_d[114]
  DIRECTION INPUT ;
  USE SIGNAL ;
  PORT
   LAYER M4 ;
   RECT 112.236000 27.024000 112.320000 27.048000 ;
  END
 END n_li_d[114]
 PIN n_li_d[115]
  DIRECTION INPUT ;
  USE SIGNAL ;
  PORT
   LAYER M4 ;
   RECT 112.236000 27.216000 112.320000 27.240000 ;
  END
 END n_li_d[115]
 PIN n_li_d[116]
  DIRECTION INPUT ;
  USE SIGNAL ;
  PORT
   LAYER M4 ;
   RECT 112.236000 27.360000 112.320000 27.384000 ;
  END
 END n_li_d[116]
 PIN n_li_d[117]
  DIRECTION INPUT ;
  USE SIGNAL ;
  PORT
   LAYER M4 ;
   RECT 112.236000 27.552000 112.320000 27.576000 ;
  END
 END n_li_d[117]
 PIN n_li_d[118]
  DIRECTION INPUT ;
  USE SIGNAL ;
  PORT
   LAYER M4 ;
   RECT 112.236000 27.744000 112.320000 27.768000 ;
  END
 END n_li_d[118]
 PIN n_li_d[119]
  DIRECTION INPUT ;
  USE SIGNAL ;
  PORT
   LAYER M4 ;
   RECT 112.236000 27.936000 112.320000 27.960000 ;
  END
 END n_li_d[119]
 PIN n_li_d[120]
  DIRECTION INPUT ;
  USE SIGNAL ;
  PORT
   LAYER M4 ;
   RECT 112.236000 28.080000 112.320000 28.104000 ;
  END
 END n_li_d[120]
 PIN n_li_d[121]
  DIRECTION INPUT ;
  USE SIGNAL ;
  PORT
   LAYER M4 ;
   RECT 112.236000 28.272000 112.320000 28.296000 ;
  END
 END n_li_d[121]
 PIN n_li_d[122]
  DIRECTION INPUT ;
  USE SIGNAL ;
  PORT
   LAYER M4 ;
   RECT 112.236000 28.464000 112.320000 28.488000 ;
  END
 END n_li_d[122]
 PIN n_li_d[123]
  DIRECTION INPUT ;
  USE SIGNAL ;
  PORT
   LAYER M4 ;
   RECT 112.236000 28.608000 112.320000 28.632000 ;
  END
 END n_li_d[123]
 PIN n_li_d[124]
  DIRECTION INPUT ;
  USE SIGNAL ;
  PORT
   LAYER M4 ;
   RECT 112.236000 28.800000 112.320000 28.824000 ;
  END
 END n_li_d[124]
 PIN n_li_d[125]
  DIRECTION INPUT ;
  USE SIGNAL ;
  PORT
   LAYER M4 ;
   RECT 112.236000 28.992000 112.320000 29.016000 ;
  END
 END n_li_d[125]
 PIN n_li_d[126]
  DIRECTION INPUT ;
  USE SIGNAL ;
  PORT
   LAYER M4 ;
   RECT 112.236000 29.184000 112.320000 29.208000 ;
  END
 END n_li_d[126]
 PIN n_li_d[127]
  DIRECTION INPUT ;
  USE SIGNAL ;
  PORT
   LAYER M4 ;
   RECT 112.236000 29.328000 112.320000 29.352000 ;
  END
 END n_li_d[127]
 PIN n_li_d[128]
  DIRECTION INPUT ;
  USE SIGNAL ;
  PORT
   LAYER M4 ;
   RECT 112.236000 29.520000 112.320000 29.544000 ;
  END
 END n_li_d[128]
 PIN n_li_d[129]
  DIRECTION INPUT ;
  USE SIGNAL ;
  PORT
   LAYER M4 ;
   RECT 112.236000 29.712000 112.320000 29.736000 ;
  END
 END n_li_d[129]
 PIN n_li_d[130]
  DIRECTION INPUT ;
  USE SIGNAL ;
  PORT
   LAYER M4 ;
   RECT 112.236000 29.904000 112.320000 29.928000 ;
  END
 END n_li_d[130]
 PIN n_li_d[131]
  DIRECTION INPUT ;
  USE SIGNAL ;
  PORT
   LAYER M4 ;
   RECT 112.236000 30.048000 112.320000 30.072000 ;
  END
 END n_li_d[131]
 PIN n_li_d[132]
  DIRECTION INPUT ;
  USE SIGNAL ;
  PORT
   LAYER M4 ;
   RECT 112.236000 30.240000 112.320000 30.264000 ;
  END
 END n_li_d[132]
 PIN n_li_d[133]
  DIRECTION INPUT ;
  USE SIGNAL ;
  PORT
   LAYER M4 ;
   RECT 112.236000 30.432000 112.320000 30.456000 ;
  END
 END n_li_d[133]
 PIN n_li_d[134]
  DIRECTION INPUT ;
  USE SIGNAL ;
  PORT
   LAYER M4 ;
   RECT 112.236000 30.624000 112.320000 30.648000 ;
  END
 END n_li_d[134]
 PIN n_li_d[135]
  DIRECTION INPUT ;
  USE SIGNAL ;
  PORT
   LAYER M4 ;
   RECT 112.236000 30.768000 112.320000 30.792000 ;
  END
 END n_li_d[135]
 PIN n_li_d[136]
  DIRECTION INPUT ;
  USE SIGNAL ;
  PORT
   LAYER M4 ;
   RECT 112.236000 30.960000 112.320000 30.984000 ;
  END
 END n_li_d[136]
 PIN n_li_d[137]
  DIRECTION INPUT ;
  USE SIGNAL ;
  PORT
   LAYER M4 ;
   RECT 112.236000 31.152000 112.320000 31.176000 ;
  END
 END n_li_d[137]
 PIN n_li_d[138]
  DIRECTION INPUT ;
  USE SIGNAL ;
  PORT
   LAYER M4 ;
   RECT 112.236000 31.296000 112.320000 31.320000 ;
  END
 END n_li_d[138]
 PIN n_li_d[139]
  DIRECTION INPUT ;
  USE SIGNAL ;
  PORT
   LAYER M4 ;
   RECT 112.236000 31.488000 112.320000 31.512000 ;
  END
 END n_li_d[139]
 PIN n_li_d[140]
  DIRECTION INPUT ;
  USE SIGNAL ;
  PORT
   LAYER M4 ;
   RECT 112.236000 31.680000 112.320000 31.704000 ;
  END
 END n_li_d[140]
 PIN n_li_d[141]
  DIRECTION INPUT ;
  USE SIGNAL ;
  PORT
   LAYER M4 ;
   RECT 112.236000 31.872000 112.320000 31.896000 ;
  END
 END n_li_d[141]
 PIN n_li_d[142]
  DIRECTION INPUT ;
  USE SIGNAL ;
  PORT
   LAYER M4 ;
   RECT 112.236000 32.016000 112.320000 32.040000 ;
  END
 END n_li_d[142]
 PIN n_li_d[143]
  DIRECTION INPUT ;
  USE SIGNAL ;
  PORT
   LAYER M4 ;
   RECT 112.236000 32.208000 112.320000 32.232000 ;
  END
 END n_li_d[143]
 PIN n_li_d[144]
  DIRECTION INPUT ;
  USE SIGNAL ;
  PORT
   LAYER M4 ;
   RECT 112.236000 32.400000 112.320000 32.424000 ;
  END
 END n_li_d[144]
 PIN n_li_d[145]
  DIRECTION INPUT ;
  USE SIGNAL ;
  PORT
   LAYER M4 ;
   RECT 112.236000 32.592000 112.320000 32.616000 ;
  END
 END n_li_d[145]
 PIN n_li_d[146]
  DIRECTION INPUT ;
  USE SIGNAL ;
  PORT
   LAYER M4 ;
   RECT 112.236000 32.736000 112.320000 32.760000 ;
  END
 END n_li_d[146]
 PIN n_li_d[147]
  DIRECTION INPUT ;
  USE SIGNAL ;
  PORT
   LAYER M4 ;
   RECT 112.236000 32.928000 112.320000 32.952000 ;
  END
 END n_li_d[147]
 PIN n_li_d[148]
  DIRECTION INPUT ;
  USE SIGNAL ;
  PORT
   LAYER M4 ;
   RECT 112.236000 33.120000 112.320000 33.144000 ;
  END
 END n_li_d[148]
 PIN n_li_d[149]
  DIRECTION INPUT ;
  USE SIGNAL ;
  PORT
   LAYER M4 ;
   RECT 112.236000 33.312000 112.320000 33.336000 ;
  END
 END n_li_d[149]
 PIN n_li_d[150]
  DIRECTION INPUT ;
  USE SIGNAL ;
  PORT
   LAYER M4 ;
   RECT 112.236000 33.456000 112.320000 33.480000 ;
  END
 END n_li_d[150]
 PIN n_li_d[151]
  DIRECTION INPUT ;
  USE SIGNAL ;
  PORT
   LAYER M4 ;
   RECT 112.236000 33.648000 112.320000 33.672000 ;
  END
 END n_li_d[151]
 PIN n_li_d[152]
  DIRECTION INPUT ;
  USE SIGNAL ;
  PORT
   LAYER M4 ;
   RECT 112.236000 33.840000 112.320000 33.864000 ;
  END
 END n_li_d[152]
 PIN n_li_d[153]
  DIRECTION INPUT ;
  USE SIGNAL ;
  PORT
   LAYER M4 ;
   RECT 112.236000 34.032000 112.320000 34.056000 ;
  END
 END n_li_d[153]
 PIN n_li_d[154]
  DIRECTION INPUT ;
  USE SIGNAL ;
  PORT
   LAYER M4 ;
   RECT 112.236000 34.176000 112.320000 34.200000 ;
  END
 END n_li_d[154]
 PIN n_li_d[155]
  DIRECTION INPUT ;
  USE SIGNAL ;
  PORT
   LAYER M4 ;
   RECT 112.236000 34.368000 112.320000 34.392000 ;
  END
 END n_li_d[155]
 PIN n_li_d[156]
  DIRECTION INPUT ;
  USE SIGNAL ;
  PORT
   LAYER M4 ;
   RECT 112.236000 34.560000 112.320000 34.584000 ;
  END
 END n_li_d[156]
 PIN n_li_d[157]
  DIRECTION INPUT ;
  USE SIGNAL ;
  PORT
   LAYER M4 ;
   RECT 112.236000 34.704000 112.320000 34.728000 ;
  END
 END n_li_d[157]
 PIN n_li_d[158]
  DIRECTION INPUT ;
  USE SIGNAL ;
  PORT
   LAYER M4 ;
   RECT 112.236000 34.896000 112.320000 34.920000 ;
  END
 END n_li_d[158]
 PIN n_li_d[159]
  DIRECTION INPUT ;
  USE SIGNAL ;
  PORT
   LAYER M4 ;
   RECT 112.236000 35.088000 112.320000 35.112000 ;
  END
 END n_li_d[159]
 PIN n_li_d[160]
  DIRECTION INPUT ;
  USE SIGNAL ;
  PORT
   LAYER M4 ;
   RECT 112.236000 35.280000 112.320000 35.304000 ;
  END
 END n_li_d[160]
 PIN n_li_d[161]
  DIRECTION INPUT ;
  USE SIGNAL ;
  PORT
   LAYER M4 ;
   RECT 112.236000 35.424000 112.320000 35.448000 ;
  END
 END n_li_d[161]
 PIN n_li_d[162]
  DIRECTION INPUT ;
  USE SIGNAL ;
  PORT
   LAYER M4 ;
   RECT 112.236000 35.616000 112.320000 35.640000 ;
  END
 END n_li_d[162]
 PIN n_li_d[163]
  DIRECTION INPUT ;
  USE SIGNAL ;
  PORT
   LAYER M4 ;
   RECT 112.236000 35.808000 112.320000 35.832000 ;
  END
 END n_li_d[163]
 PIN n_li_d[164]
  DIRECTION INPUT ;
  USE SIGNAL ;
  PORT
   LAYER M4 ;
   RECT 112.236000 36.000000 112.320000 36.024000 ;
  END
 END n_li_d[164]
 PIN n_li_d[165]
  DIRECTION INPUT ;
  USE SIGNAL ;
  PORT
   LAYER M4 ;
   RECT 112.236000 36.144000 112.320000 36.168000 ;
  END
 END n_li_d[165]
 PIN n_li_d[166]
  DIRECTION INPUT ;
  USE SIGNAL ;
  PORT
   LAYER M4 ;
   RECT 112.236000 36.336000 112.320000 36.360000 ;
  END
 END n_li_d[166]
 PIN n_li_d[167]
  DIRECTION INPUT ;
  USE SIGNAL ;
  PORT
   LAYER M4 ;
   RECT 112.236000 36.528000 112.320000 36.552000 ;
  END
 END n_li_d[167]
 PIN n_li_d[168]
  DIRECTION INPUT ;
  USE SIGNAL ;
  PORT
   LAYER M4 ;
   RECT 112.236000 36.720000 112.320000 36.744000 ;
  END
 END n_li_d[168]
 PIN n_li_d[169]
  DIRECTION INPUT ;
  USE SIGNAL ;
  PORT
   LAYER M4 ;
   RECT 112.236000 36.864000 112.320000 36.888000 ;
  END
 END n_li_d[169]
 PIN n_li_d[170]
  DIRECTION INPUT ;
  USE SIGNAL ;
  PORT
   LAYER M4 ;
   RECT 112.236000 37.056000 112.320000 37.080000 ;
  END
 END n_li_d[170]
 PIN n_li_d[171]
  DIRECTION INPUT ;
  USE SIGNAL ;
  PORT
   LAYER M4 ;
   RECT 112.236000 37.248000 112.320000 37.272000 ;
  END
 END n_li_d[171]
 PIN n_li_d[172]
  DIRECTION INPUT ;
  USE SIGNAL ;
  PORT
   LAYER M4 ;
   RECT 112.236000 37.392000 112.320000 37.416000 ;
  END
 END n_li_d[172]
 PIN n_li_d[173]
  DIRECTION INPUT ;
  USE SIGNAL ;
  PORT
   LAYER M4 ;
   RECT 112.236000 37.584000 112.320000 37.608000 ;
  END
 END n_li_d[173]
 PIN n_li_d[174]
  DIRECTION INPUT ;
  USE SIGNAL ;
  PORT
   LAYER M4 ;
   RECT 112.236000 37.776000 112.320000 37.800000 ;
  END
 END n_li_d[174]
 PIN n_li_d[175]
  DIRECTION INPUT ;
  USE SIGNAL ;
  PORT
   LAYER M4 ;
   RECT 112.236000 37.968000 112.320000 37.992000 ;
  END
 END n_li_d[175]
 PIN n_li_d[176]
  DIRECTION INPUT ;
  USE SIGNAL ;
  PORT
   LAYER M4 ;
   RECT 112.236000 38.112000 112.320000 38.136000 ;
  END
 END n_li_d[176]
 PIN n_li_d[177]
  DIRECTION INPUT ;
  USE SIGNAL ;
  PORT
   LAYER M4 ;
   RECT 112.236000 38.304000 112.320000 38.328000 ;
  END
 END n_li_d[177]
 PIN n_li_d[178]
  DIRECTION INPUT ;
  USE SIGNAL ;
  PORT
   LAYER M4 ;
   RECT 112.236000 38.496000 112.320000 38.520000 ;
  END
 END n_li_d[178]
 PIN n_li_d[179]
  DIRECTION INPUT ;
  USE SIGNAL ;
  PORT
   LAYER M4 ;
   RECT 112.236000 38.688000 112.320000 38.712000 ;
  END
 END n_li_d[179]
 PIN n_li_d[180]
  DIRECTION INPUT ;
  USE SIGNAL ;
  PORT
   LAYER M4 ;
   RECT 112.236000 38.832000 112.320000 38.856000 ;
  END
 END n_li_d[180]
 PIN n_li_d[181]
  DIRECTION INPUT ;
  USE SIGNAL ;
  PORT
   LAYER M4 ;
   RECT 112.236000 39.024000 112.320000 39.048000 ;
  END
 END n_li_d[181]
 PIN n_li_d[182]
  DIRECTION INPUT ;
  USE SIGNAL ;
  PORT
   LAYER M4 ;
   RECT 112.236000 39.216000 112.320000 39.240000 ;
  END
 END n_li_d[182]
 PIN n_li_d[183]
  DIRECTION INPUT ;
  USE SIGNAL ;
  PORT
   LAYER M4 ;
   RECT 112.236000 39.408000 112.320000 39.432000 ;
  END
 END n_li_d[183]
 PIN n_li_d[184]
  DIRECTION INPUT ;
  USE SIGNAL ;
  PORT
   LAYER M4 ;
   RECT 112.236000 39.552000 112.320000 39.576000 ;
  END
 END n_li_d[184]
 PIN n_li_d[185]
  DIRECTION INPUT ;
  USE SIGNAL ;
  PORT
   LAYER M4 ;
   RECT 112.236000 39.744000 112.320000 39.768000 ;
  END
 END n_li_d[185]
 PIN n_li_d[186]
  DIRECTION INPUT ;
  USE SIGNAL ;
  PORT
   LAYER M4 ;
   RECT 112.236000 39.936000 112.320000 39.960000 ;
  END
 END n_li_d[186]
 PIN n_li_d[187]
  DIRECTION INPUT ;
  USE SIGNAL ;
  PORT
   LAYER M4 ;
   RECT 112.236000 40.080000 112.320000 40.104000 ;
  END
 END n_li_d[187]
 PIN n_li_d[188]
  DIRECTION INPUT ;
  USE SIGNAL ;
  PORT
   LAYER M4 ;
   RECT 112.236000 40.272000 112.320000 40.296000 ;
  END
 END n_li_d[188]
 PIN n_li_d[189]
  DIRECTION INPUT ;
  USE SIGNAL ;
  PORT
   LAYER M4 ;
   RECT 112.236000 40.464000 112.320000 40.488000 ;
  END
 END n_li_d[189]
 PIN n_li_d[190]
  DIRECTION INPUT ;
  USE SIGNAL ;
  PORT
   LAYER M4 ;
   RECT 112.236000 40.656000 112.320000 40.680000 ;
  END
 END n_li_d[190]
 PIN n_li_d[191]
  DIRECTION INPUT ;
  USE SIGNAL ;
  PORT
   LAYER M4 ;
   RECT 112.236000 40.800000 112.320000 40.824000 ;
  END
 END n_li_d[191]
 PIN n_li_d[192]
  DIRECTION INPUT ;
  USE SIGNAL ;
  PORT
   LAYER M4 ;
   RECT 112.236000 40.992000 112.320000 41.016000 ;
  END
 END n_li_d[192]
 PIN n_li_d[193]
  DIRECTION INPUT ;
  USE SIGNAL ;
  PORT
   LAYER M4 ;
   RECT 112.236000 41.184000 112.320000 41.208000 ;
  END
 END n_li_d[193]
 PIN n_li_d[194]
  DIRECTION INPUT ;
  USE SIGNAL ;
  PORT
   LAYER M4 ;
   RECT 112.236000 41.376000 112.320000 41.400000 ;
  END
 END n_li_d[194]
 PIN n_li_d[195]
  DIRECTION INPUT ;
  USE SIGNAL ;
  PORT
   LAYER M4 ;
   RECT 112.236000 41.520000 112.320000 41.544000 ;
  END
 END n_li_d[195]
 PIN n_li_d[196]
  DIRECTION INPUT ;
  USE SIGNAL ;
  PORT
   LAYER M4 ;
   RECT 112.236000 41.712000 112.320000 41.736000 ;
  END
 END n_li_d[196]
 PIN n_li_d[197]
  DIRECTION INPUT ;
  USE SIGNAL ;
  PORT
   LAYER M4 ;
   RECT 112.236000 41.904000 112.320000 41.928000 ;
  END
 END n_li_d[197]
 PIN n_li_d[198]
  DIRECTION INPUT ;
  USE SIGNAL ;
  PORT
   LAYER M4 ;
   RECT 112.236000 42.096000 112.320000 42.120000 ;
  END
 END n_li_d[198]
 PIN n_li_d[199]
  DIRECTION INPUT ;
  USE SIGNAL ;
  PORT
   LAYER M4 ;
   RECT 112.236000 42.240000 112.320000 42.264000 ;
  END
 END n_li_d[199]
 PIN n_li_d[200]
  DIRECTION INPUT ;
  USE SIGNAL ;
  PORT
   LAYER M4 ;
   RECT 112.236000 42.432000 112.320000 42.456000 ;
  END
 END n_li_d[200]
 PIN n_li_d[201]
  DIRECTION INPUT ;
  USE SIGNAL ;
  PORT
   LAYER M4 ;
   RECT 112.236000 42.624000 112.320000 42.648000 ;
  END
 END n_li_d[201]
 PIN n_li_d[202]
  DIRECTION INPUT ;
  USE SIGNAL ;
  PORT
   LAYER M4 ;
   RECT 112.236000 42.816000 112.320000 42.840000 ;
  END
 END n_li_d[202]
 PIN n_li_d[203]
  DIRECTION INPUT ;
  USE SIGNAL ;
  PORT
   LAYER M4 ;
   RECT 112.236000 42.960000 112.320000 42.984000 ;
  END
 END n_li_d[203]
 PIN n_li_d[204]
  DIRECTION INPUT ;
  USE SIGNAL ;
  PORT
   LAYER M4 ;
   RECT 112.236000 43.152000 112.320000 43.176000 ;
  END
 END n_li_d[204]
 PIN n_li_d[205]
  DIRECTION INPUT ;
  USE SIGNAL ;
  PORT
   LAYER M4 ;
   RECT 112.236000 43.344000 112.320000 43.368000 ;
  END
 END n_li_d[205]
 PIN n_li_d[206]
  DIRECTION INPUT ;
  USE SIGNAL ;
  PORT
   LAYER M4 ;
   RECT 112.236000 43.488000 112.320000 43.512000 ;
  END
 END n_li_d[206]
 PIN n_li_d[207]
  DIRECTION INPUT ;
  USE SIGNAL ;
  PORT
   LAYER M4 ;
   RECT 112.236000 43.680000 112.320000 43.704000 ;
  END
 END n_li_d[207]
 PIN n_li_d[208]
  DIRECTION INPUT ;
  USE SIGNAL ;
  PORT
   LAYER M4 ;
   RECT 112.236000 43.872000 112.320000 43.896000 ;
  END
 END n_li_d[208]
 PIN n_li_d[209]
  DIRECTION INPUT ;
  USE SIGNAL ;
  PORT
   LAYER M4 ;
   RECT 112.236000 44.064000 112.320000 44.088000 ;
  END
 END n_li_d[209]
 PIN n_li_d[210]
  DIRECTION INPUT ;
  USE SIGNAL ;
  PORT
   LAYER M4 ;
   RECT 112.236000 44.208000 112.320000 44.232000 ;
  END
 END n_li_d[210]
 PIN n_li_d[211]
  DIRECTION INPUT ;
  USE SIGNAL ;
  PORT
   LAYER M4 ;
   RECT 112.236000 44.400000 112.320000 44.424000 ;
  END
 END n_li_d[211]
 PIN n_li_d[212]
  DIRECTION INPUT ;
  USE SIGNAL ;
  PORT
   LAYER M4 ;
   RECT 112.236000 44.592000 112.320000 44.616000 ;
  END
 END n_li_d[212]
 PIN n_li_d[213]
  DIRECTION INPUT ;
  USE SIGNAL ;
  PORT
   LAYER M4 ;
   RECT 112.236000 44.784000 112.320000 44.808000 ;
  END
 END n_li_d[213]
 PIN n_li_d[214]
  DIRECTION INPUT ;
  USE SIGNAL ;
  PORT
   LAYER M4 ;
   RECT 112.236000 44.928000 112.320000 44.952000 ;
  END
 END n_li_d[214]
 PIN n_li_d[215]
  DIRECTION INPUT ;
  USE SIGNAL ;
  PORT
   LAYER M4 ;
   RECT 112.236000 45.120000 112.320000 45.144000 ;
  END
 END n_li_d[215]
 PIN n_li_d[216]
  DIRECTION INPUT ;
  USE SIGNAL ;
  PORT
   LAYER M4 ;
   RECT 112.236000 45.312000 112.320000 45.336000 ;
  END
 END n_li_d[216]
 PIN n_li_d[217]
  DIRECTION INPUT ;
  USE SIGNAL ;
  PORT
   LAYER M4 ;
   RECT 112.236000 45.504000 112.320000 45.528000 ;
  END
 END n_li_d[217]
 PIN n_li_d[218]
  DIRECTION INPUT ;
  USE SIGNAL ;
  PORT
   LAYER M4 ;
   RECT 112.236000 45.648000 112.320000 45.672000 ;
  END
 END n_li_d[218]
 PIN n_li_d[219]
  DIRECTION INPUT ;
  USE SIGNAL ;
  PORT
   LAYER M4 ;
   RECT 112.236000 45.840000 112.320000 45.864000 ;
  END
 END n_li_d[219]
 PIN n_li_d[220]
  DIRECTION INPUT ;
  USE SIGNAL ;
  PORT
   LAYER M4 ;
   RECT 112.236000 46.032000 112.320000 46.056000 ;
  END
 END n_li_d[220]
 PIN n_li_d[221]
  DIRECTION INPUT ;
  USE SIGNAL ;
  PORT
   LAYER M4 ;
   RECT 112.236000 46.176000 112.320000 46.200000 ;
  END
 END n_li_d[221]
 PIN n_li_d[222]
  DIRECTION INPUT ;
  USE SIGNAL ;
  PORT
   LAYER M4 ;
   RECT 112.236000 46.368000 112.320000 46.392000 ;
  END
 END n_li_d[222]
 PIN n_li_d[223]
  DIRECTION INPUT ;
  USE SIGNAL ;
  PORT
   LAYER M4 ;
   RECT 112.236000 46.560000 112.320000 46.584000 ;
  END
 END n_li_d[223]
 PIN n_li_d[224]
  DIRECTION INPUT ;
  USE SIGNAL ;
  PORT
   LAYER M4 ;
   RECT 112.236000 46.752000 112.320000 46.776000 ;
  END
 END n_li_d[224]
 PIN n_li_d[225]
  DIRECTION INPUT ;
  USE SIGNAL ;
  PORT
   LAYER M4 ;
   RECT 112.236000 46.896000 112.320000 46.920000 ;
  END
 END n_li_d[225]
 PIN n_li_d[226]
  DIRECTION INPUT ;
  USE SIGNAL ;
  PORT
   LAYER M4 ;
   RECT 112.236000 47.088000 112.320000 47.112000 ;
  END
 END n_li_d[226]
 PIN n_li_d[227]
  DIRECTION INPUT ;
  USE SIGNAL ;
  PORT
   LAYER M4 ;
   RECT 112.236000 47.280000 112.320000 47.304000 ;
  END
 END n_li_d[227]
 PIN n_li_d[228]
  DIRECTION INPUT ;
  USE SIGNAL ;
  PORT
   LAYER M4 ;
   RECT 112.236000 47.472000 112.320000 47.496000 ;
  END
 END n_li_d[228]
 PIN n_li_d[229]
  DIRECTION INPUT ;
  USE SIGNAL ;
  PORT
   LAYER M4 ;
   RECT 112.236000 47.616000 112.320000 47.640000 ;
  END
 END n_li_d[229]
 PIN n_li_d[230]
  DIRECTION INPUT ;
  USE SIGNAL ;
  PORT
   LAYER M4 ;
   RECT 112.236000 47.808000 112.320000 47.832000 ;
  END
 END n_li_d[230]
 PIN n_li_d[231]
  DIRECTION INPUT ;
  USE SIGNAL ;
  PORT
   LAYER M4 ;
   RECT 112.236000 48.000000 112.320000 48.024000 ;
  END
 END n_li_d[231]
 PIN n_li_d[232]
  DIRECTION INPUT ;
  USE SIGNAL ;
  PORT
   LAYER M4 ;
   RECT 112.236000 48.192000 112.320000 48.216000 ;
  END
 END n_li_d[232]
 PIN n_li_d[233]
  DIRECTION INPUT ;
  USE SIGNAL ;
  PORT
   LAYER M4 ;
   RECT 112.236000 48.336000 112.320000 48.360000 ;
  END
 END n_li_d[233]
 PIN n_li_d[234]
  DIRECTION INPUT ;
  USE SIGNAL ;
  PORT
   LAYER M4 ;
   RECT 112.236000 48.528000 112.320000 48.552000 ;
  END
 END n_li_d[234]
 PIN n_li_d[235]
  DIRECTION INPUT ;
  USE SIGNAL ;
  PORT
   LAYER M4 ;
   RECT 112.236000 48.720000 112.320000 48.744000 ;
  END
 END n_li_d[235]
 PIN n_li_d[236]
  DIRECTION INPUT ;
  USE SIGNAL ;
  PORT
   LAYER M4 ;
   RECT 112.236000 48.864000 112.320000 48.888000 ;
  END
 END n_li_d[236]
 PIN n_li_d[237]
  DIRECTION INPUT ;
  USE SIGNAL ;
  PORT
   LAYER M4 ;
   RECT 112.236000 49.056000 112.320000 49.080000 ;
  END
 END n_li_d[237]
 PIN n_li_d[238]
  DIRECTION INPUT ;
  USE SIGNAL ;
  PORT
   LAYER M4 ;
   RECT 112.236000 49.248000 112.320000 49.272000 ;
  END
 END n_li_d[238]
 PIN n_li_d[239]
  DIRECTION INPUT ;
  USE SIGNAL ;
  PORT
   LAYER M4 ;
   RECT 112.236000 49.440000 112.320000 49.464000 ;
  END
 END n_li_d[239]
 PIN n_li_d[240]
  DIRECTION INPUT ;
  USE SIGNAL ;
  PORT
   LAYER M4 ;
   RECT 112.236000 49.584000 112.320000 49.608000 ;
  END
 END n_li_d[240]
 PIN n_li_d[241]
  DIRECTION INPUT ;
  USE SIGNAL ;
  PORT
   LAYER M4 ;
   RECT 112.236000 49.776000 112.320000 49.800000 ;
  END
 END n_li_d[241]
 PIN n_li_d[242]
  DIRECTION INPUT ;
  USE SIGNAL ;
  PORT
   LAYER M4 ;
   RECT 112.236000 49.968000 112.320000 49.992000 ;
  END
 END n_li_d[242]
 PIN n_li_d[243]
  DIRECTION INPUT ;
  USE SIGNAL ;
  PORT
   LAYER M4 ;
   RECT 112.236000 50.160000 112.320000 50.184000 ;
  END
 END n_li_d[243]
 PIN n_li_d[244]
  DIRECTION INPUT ;
  USE SIGNAL ;
  PORT
   LAYER M4 ;
   RECT 112.236000 50.304000 112.320000 50.328000 ;
  END
 END n_li_d[244]
 PIN n_li_d[245]
  DIRECTION INPUT ;
  USE SIGNAL ;
  PORT
   LAYER M4 ;
   RECT 112.236000 50.496000 112.320000 50.520000 ;
  END
 END n_li_d[245]
 PIN n_li_d[246]
  DIRECTION INPUT ;
  USE SIGNAL ;
  PORT
   LAYER M4 ;
   RECT 112.236000 50.688000 112.320000 50.712000 ;
  END
 END n_li_d[246]
 PIN n_li_d[247]
  DIRECTION INPUT ;
  USE SIGNAL ;
  PORT
   LAYER M4 ;
   RECT 112.236000 50.880000 112.320000 50.904000 ;
  END
 END n_li_d[247]
 PIN n_li_d[248]
  DIRECTION INPUT ;
  USE SIGNAL ;
  PORT
   LAYER M4 ;
   RECT 112.236000 51.024000 112.320000 51.048000 ;
  END
 END n_li_d[248]
 PIN n_li_d[249]
  DIRECTION INPUT ;
  USE SIGNAL ;
  PORT
   LAYER M4 ;
   RECT 112.236000 51.216000 112.320000 51.240000 ;
  END
 END n_li_d[249]
 PIN n_li_d[250]
  DIRECTION INPUT ;
  USE SIGNAL ;
  PORT
   LAYER M4 ;
   RECT 112.236000 51.408000 112.320000 51.432000 ;
  END
 END n_li_d[250]
 PIN n_li_d[251]
  DIRECTION INPUT ;
  USE SIGNAL ;
  PORT
   LAYER M4 ;
   RECT 112.236000 51.600000 112.320000 51.624000 ;
  END
 END n_li_d[251]
 PIN n_li_d[252]
  DIRECTION INPUT ;
  USE SIGNAL ;
  PORT
   LAYER M4 ;
   RECT 112.236000 51.744000 112.320000 51.768000 ;
  END
 END n_li_d[252]
 PIN n_li_d[253]
  DIRECTION INPUT ;
  USE SIGNAL ;
  PORT
   LAYER M4 ;
   RECT 112.236000 51.936000 112.320000 51.960000 ;
  END
 END n_li_d[253]
 PIN n_li_d[254]
  DIRECTION INPUT ;
  USE SIGNAL ;
  PORT
   LAYER M4 ;
   RECT 112.236000 52.128000 112.320000 52.152000 ;
  END
 END n_li_d[254]
 PIN n_li_d[255]
  DIRECTION INPUT ;
  USE SIGNAL ;
  PORT
   LAYER M4 ;
   RECT 112.236000 52.272000 112.320000 52.296000 ;
  END
 END n_li_d[255]
 PIN n_li_d[256]
  DIRECTION INPUT ;
  USE SIGNAL ;
  PORT
   LAYER M4 ;
   RECT 112.236000 52.464000 112.320000 52.488000 ;
  END
 END n_li_d[256]
 PIN n_li_d[257]
  DIRECTION INPUT ;
  USE SIGNAL ;
  PORT
   LAYER M4 ;
   RECT 112.236000 52.656000 112.320000 52.680000 ;
  END
 END n_li_d[257]
 PIN n_li_d[258]
  DIRECTION INPUT ;
  USE SIGNAL ;
  PORT
   LAYER M4 ;
   RECT 112.236000 52.848000 112.320000 52.872000 ;
  END
 END n_li_d[258]
 PIN n_li_d[259]
  DIRECTION INPUT ;
  USE SIGNAL ;
  PORT
   LAYER M4 ;
   RECT 112.236000 52.992000 112.320000 53.016000 ;
  END
 END n_li_d[259]
 PIN n_li_d[260]
  DIRECTION INPUT ;
  USE SIGNAL ;
  PORT
   LAYER M4 ;
   RECT 112.236000 53.184000 112.320000 53.208000 ;
  END
 END n_li_d[260]
 PIN n_li_d[261]
  DIRECTION INPUT ;
  USE SIGNAL ;
  PORT
   LAYER M4 ;
   RECT 112.236000 53.376000 112.320000 53.400000 ;
  END
 END n_li_d[261]
 PIN n_li_d[262]
  DIRECTION INPUT ;
  USE SIGNAL ;
  PORT
   LAYER M4 ;
   RECT 112.236000 53.568000 112.320000 53.592000 ;
  END
 END n_li_d[262]
 PIN n_li_d[263]
  DIRECTION INPUT ;
  USE SIGNAL ;
  PORT
   LAYER M4 ;
   RECT 112.236000 53.712000 112.320000 53.736000 ;
  END
 END n_li_d[263]
 PIN n_li_d[264]
  DIRECTION INPUT ;
  USE SIGNAL ;
  PORT
   LAYER M4 ;
   RECT 112.236000 53.904000 112.320000 53.928000 ;
  END
 END n_li_d[264]
 PIN n_li_d[265]
  DIRECTION INPUT ;
  USE SIGNAL ;
  PORT
   LAYER M4 ;
   RECT 112.236000 54.096000 112.320000 54.120000 ;
  END
 END n_li_d[265]
 PIN n_li_d[266]
  DIRECTION INPUT ;
  USE SIGNAL ;
  PORT
   LAYER M4 ;
   RECT 112.236000 54.288000 112.320000 54.312000 ;
  END
 END n_li_d[266]
 PIN n_li_d[267]
  DIRECTION INPUT ;
  USE SIGNAL ;
  PORT
   LAYER M4 ;
   RECT 112.236000 54.432000 112.320000 54.456000 ;
  END
 END n_li_d[267]
 PIN n_li_d[268]
  DIRECTION INPUT ;
  USE SIGNAL ;
  PORT
   LAYER M4 ;
   RECT 112.236000 54.624000 112.320000 54.648000 ;
  END
 END n_li_d[268]
 PIN n_li_d[269]
  DIRECTION INPUT ;
  USE SIGNAL ;
  PORT
   LAYER M4 ;
   RECT 112.236000 54.816000 112.320000 54.840000 ;
  END
 END n_li_d[269]
 PIN n_li_d[270]
  DIRECTION INPUT ;
  USE SIGNAL ;
  PORT
   LAYER M4 ;
   RECT 112.236000 54.960000 112.320000 54.984000 ;
  END
 END n_li_d[270]
 PIN n_li_d[271]
  DIRECTION INPUT ;
  USE SIGNAL ;
  PORT
   LAYER M4 ;
   RECT 112.236000 55.152000 112.320000 55.176000 ;
  END
 END n_li_d[271]
 PIN n_li_d[272]
  DIRECTION INPUT ;
  USE SIGNAL ;
  PORT
   LAYER M4 ;
   RECT 112.236000 55.344000 112.320000 55.368000 ;
  END
 END n_li_d[272]
 PIN n_li_d[273]
  DIRECTION INPUT ;
  USE SIGNAL ;
  PORT
   LAYER M4 ;
   RECT 112.236000 55.536000 112.320000 55.560000 ;
  END
 END n_li_d[273]
 PIN n_li_d[274]
  DIRECTION INPUT ;
  USE SIGNAL ;
  PORT
   LAYER M4 ;
   RECT 112.236000 55.680000 112.320000 55.704000 ;
  END
 END n_li_d[274]
 PIN n_li_d[275]
  DIRECTION INPUT ;
  USE SIGNAL ;
  PORT
   LAYER M4 ;
   RECT 112.236000 55.872000 112.320000 55.896000 ;
  END
 END n_li_d[275]
 PIN n_li_d[276]
  DIRECTION INPUT ;
  USE SIGNAL ;
  PORT
   LAYER M4 ;
   RECT 112.236000 56.064000 112.320000 56.088000 ;
  END
 END n_li_d[276]
 PIN n_li_d[277]
  DIRECTION INPUT ;
  USE SIGNAL ;
  PORT
   LAYER M4 ;
   RECT 112.236000 56.256000 112.320000 56.280000 ;
  END
 END n_li_d[277]
 PIN n_li_d[278]
  DIRECTION INPUT ;
  USE SIGNAL ;
  PORT
   LAYER M4 ;
   RECT 112.236000 56.400000 112.320000 56.424000 ;
  END
 END n_li_d[278]
 PIN n_li_d[279]
  DIRECTION INPUT ;
  USE SIGNAL ;
  PORT
   LAYER M4 ;
   RECT 112.236000 56.592000 112.320000 56.616000 ;
  END
 END n_li_d[279]
 PIN n_li_d[280]
  DIRECTION INPUT ;
  USE SIGNAL ;
  PORT
   LAYER M4 ;
   RECT 112.236000 56.784000 112.320000 56.808000 ;
  END
 END n_li_d[280]
 PIN n_li_d[281]
  DIRECTION INPUT ;
  USE SIGNAL ;
  PORT
   LAYER M4 ;
   RECT 112.236000 56.976000 112.320000 57.000000 ;
  END
 END n_li_d[281]
 PIN n_li_d[282]
  DIRECTION INPUT ;
  USE SIGNAL ;
  PORT
   LAYER M4 ;
   RECT 112.236000 57.120000 112.320000 57.144000 ;
  END
 END n_li_d[282]
 PIN n_li_d[283]
  DIRECTION INPUT ;
  USE SIGNAL ;
  PORT
   LAYER M4 ;
   RECT 112.236000 57.312000 112.320000 57.336000 ;
  END
 END n_li_d[283]
 PIN n_li_d[284]
  DIRECTION INPUT ;
  USE SIGNAL ;
  PORT
   LAYER M4 ;
   RECT 112.236000 57.504000 112.320000 57.528000 ;
  END
 END n_li_d[284]
 PIN n_li_d[285]
  DIRECTION INPUT ;
  USE SIGNAL ;
  PORT
   LAYER M4 ;
   RECT 112.236000 57.648000 112.320000 57.672000 ;
  END
 END n_li_d[285]
 PIN n_li_d[286]
  DIRECTION INPUT ;
  USE SIGNAL ;
  PORT
   LAYER M4 ;
   RECT 112.236000 57.840000 112.320000 57.864000 ;
  END
 END n_li_d[286]
 PIN n_li_d[287]
  DIRECTION INPUT ;
  USE SIGNAL ;
  PORT
   LAYER M4 ;
   RECT 112.236000 58.032000 112.320000 58.056000 ;
  END
 END n_li_d[287]
 PIN n_li_d[288]
  DIRECTION INPUT ;
  USE SIGNAL ;
  PORT
   LAYER M4 ;
   RECT 112.236000 58.224000 112.320000 58.248000 ;
  END
 END n_li_d[288]
 PIN n_li_d[289]
  DIRECTION INPUT ;
  USE SIGNAL ;
  PORT
   LAYER M4 ;
   RECT 112.236000 58.368000 112.320000 58.392000 ;
  END
 END n_li_d[289]
 PIN n_li_d[290]
  DIRECTION INPUT ;
  USE SIGNAL ;
  PORT
   LAYER M4 ;
   RECT 112.236000 58.560000 112.320000 58.584000 ;
  END
 END n_li_d[290]
 PIN n_li_d[291]
  DIRECTION INPUT ;
  USE SIGNAL ;
  PORT
   LAYER M4 ;
   RECT 112.236000 58.752000 112.320000 58.776000 ;
  END
 END n_li_d[291]
 PIN n_li_d[292]
  DIRECTION INPUT ;
  USE SIGNAL ;
  PORT
   LAYER M4 ;
   RECT 112.236000 58.944000 112.320000 58.968000 ;
  END
 END n_li_d[292]
 PIN n_li_d[293]
  DIRECTION INPUT ;
  USE SIGNAL ;
  PORT
   LAYER M4 ;
   RECT 112.236000 59.088000 112.320000 59.112000 ;
  END
 END n_li_d[293]
 PIN n_li_d[294]
  DIRECTION INPUT ;
  USE SIGNAL ;
  PORT
   LAYER M4 ;
   RECT 112.236000 59.280000 112.320000 59.304000 ;
  END
 END n_li_d[294]
 PIN n_li_d[295]
  DIRECTION INPUT ;
  USE SIGNAL ;
  PORT
   LAYER M4 ;
   RECT 112.236000 59.472000 112.320000 59.496000 ;
  END
 END n_li_d[295]
 PIN n_li_d[296]
  DIRECTION INPUT ;
  USE SIGNAL ;
  PORT
   LAYER M4 ;
   RECT 112.236000 59.664000 112.320000 59.688000 ;
  END
 END n_li_d[296]
 PIN n_li_d[297]
  DIRECTION INPUT ;
  USE SIGNAL ;
  PORT
   LAYER M4 ;
   RECT 112.236000 59.808000 112.320000 59.832000 ;
  END
 END n_li_d[297]
 PIN n_li_d[298]
  DIRECTION INPUT ;
  USE SIGNAL ;
  PORT
   LAYER M4 ;
   RECT 112.236000 60.000000 112.320000 60.024000 ;
  END
 END n_li_d[298]
 PIN n_li_d[299]
  DIRECTION INPUT ;
  USE SIGNAL ;
  PORT
   LAYER M4 ;
   RECT 112.236000 60.192000 112.320000 60.216000 ;
  END
 END n_li_d[299]
 PIN n_li_d[300]
  DIRECTION INPUT ;
  USE SIGNAL ;
  PORT
   LAYER M4 ;
   RECT 112.236000 60.384000 112.320000 60.408000 ;
  END
 END n_li_d[300]
 PIN n_li_d[301]
  DIRECTION INPUT ;
  USE SIGNAL ;
  PORT
   LAYER M4 ;
   RECT 112.236000 60.528000 112.320000 60.552000 ;
  END
 END n_li_d[301]
 PIN n_li_d[302]
  DIRECTION INPUT ;
  USE SIGNAL ;
  PORT
   LAYER M4 ;
   RECT 112.236000 60.720000 112.320000 60.744000 ;
  END
 END n_li_d[302]
 PIN n_li_d[303]
  DIRECTION INPUT ;
  USE SIGNAL ;
  PORT
   LAYER M4 ;
   RECT 112.236000 60.912000 112.320000 60.936000 ;
  END
 END n_li_d[303]
 PIN n_li_d[304]
  DIRECTION INPUT ;
  USE SIGNAL ;
  PORT
   LAYER M4 ;
   RECT 112.236000 61.056000 112.320000 61.080000 ;
  END
 END n_li_d[304]
 PIN n_li_d[305]
  DIRECTION INPUT ;
  USE SIGNAL ;
  PORT
   LAYER M4 ;
   RECT 112.236000 61.248000 112.320000 61.272000 ;
  END
 END n_li_d[305]
 PIN n_li_d[306]
  DIRECTION INPUT ;
  USE SIGNAL ;
  PORT
   LAYER M4 ;
   RECT 112.236000 61.440000 112.320000 61.464000 ;
  END
 END n_li_d[306]
 PIN n_li_d[307]
  DIRECTION INPUT ;
  USE SIGNAL ;
  PORT
   LAYER M4 ;
   RECT 112.236000 61.632000 112.320000 61.656000 ;
  END
 END n_li_d[307]
 PIN n_li_d[308]
  DIRECTION INPUT ;
  USE SIGNAL ;
  PORT
   LAYER M4 ;
   RECT 112.236000 61.776000 112.320000 61.800000 ;
  END
 END n_li_d[308]
 PIN n_li_d[309]
  DIRECTION INPUT ;
  USE SIGNAL ;
  PORT
   LAYER M4 ;
   RECT 112.236000 61.968000 112.320000 61.992000 ;
  END
 END n_li_d[309]
 PIN n_li_d[310]
  DIRECTION INPUT ;
  USE SIGNAL ;
  PORT
   LAYER M4 ;
   RECT 112.236000 62.160000 112.320000 62.184000 ;
  END
 END n_li_d[310]
 PIN n_li_d[311]
  DIRECTION INPUT ;
  USE SIGNAL ;
  PORT
   LAYER M4 ;
   RECT 112.236000 62.352000 112.320000 62.376000 ;
  END
 END n_li_d[311]
 PIN n_li_d[312]
  DIRECTION INPUT ;
  USE SIGNAL ;
  PORT
   LAYER M4 ;
   RECT 112.236000 62.496000 112.320000 62.520000 ;
  END
 END n_li_d[312]
 PIN n_li_d[313]
  DIRECTION INPUT ;
  USE SIGNAL ;
  PORT
   LAYER M4 ;
   RECT 112.236000 62.688000 112.320000 62.712000 ;
  END
 END n_li_d[313]
 PIN n_li_d[314]
  DIRECTION INPUT ;
  USE SIGNAL ;
  PORT
   LAYER M4 ;
   RECT 112.236000 62.880000 112.320000 62.904000 ;
  END
 END n_li_d[314]
 PIN n_li_d[315]
  DIRECTION INPUT ;
  USE SIGNAL ;
  PORT
   LAYER M4 ;
   RECT 112.236000 63.072000 112.320000 63.096000 ;
  END
 END n_li_d[315]
 PIN n_li_d[316]
  DIRECTION INPUT ;
  USE SIGNAL ;
  PORT
   LAYER M4 ;
   RECT 112.236000 63.216000 112.320000 63.240000 ;
  END
 END n_li_d[316]
 PIN n_li_d[317]
  DIRECTION INPUT ;
  USE SIGNAL ;
  PORT
   LAYER M4 ;
   RECT 112.236000 63.408000 112.320000 63.432000 ;
  END
 END n_li_d[317]
 PIN n_li_d[318]
  DIRECTION INPUT ;
  USE SIGNAL ;
  PORT
   LAYER M4 ;
   RECT 112.236000 63.600000 112.320000 63.624000 ;
  END
 END n_li_d[318]
 PIN n_li_d[319]
  DIRECTION INPUT ;
  USE SIGNAL ;
  PORT
   LAYER M4 ;
   RECT 112.236000 63.744000 112.320000 63.768000 ;
  END
 END n_li_d[319]
 PIN n_li_d[320]
  DIRECTION INPUT ;
  USE SIGNAL ;
  PORT
   LAYER M4 ;
   RECT 112.236000 63.936000 112.320000 63.960000 ;
  END
 END n_li_d[320]
 PIN n_li_d[321]
  DIRECTION INPUT ;
  USE SIGNAL ;
  PORT
   LAYER M4 ;
   RECT 112.236000 64.128000 112.320000 64.152000 ;
  END
 END n_li_d[321]
 PIN n_li_d[322]
  DIRECTION INPUT ;
  USE SIGNAL ;
  PORT
   LAYER M4 ;
   RECT 112.236000 64.320000 112.320000 64.344000 ;
  END
 END n_li_d[322]
 PIN n_li_d[323]
  DIRECTION INPUT ;
  USE SIGNAL ;
  PORT
   LAYER M4 ;
   RECT 112.236000 64.464000 112.320000 64.488000 ;
  END
 END n_li_d[323]
 PIN n_li_d[324]
  DIRECTION INPUT ;
  USE SIGNAL ;
  PORT
   LAYER M4 ;
   RECT 112.236000 64.656000 112.320000 64.680000 ;
  END
 END n_li_d[324]
 PIN n_li_d[325]
  DIRECTION INPUT ;
  USE SIGNAL ;
  PORT
   LAYER M4 ;
   RECT 112.236000 64.848000 112.320000 64.872000 ;
  END
 END n_li_d[325]
 PIN n_li_d[326]
  DIRECTION INPUT ;
  USE SIGNAL ;
  PORT
   LAYER M4 ;
   RECT 112.236000 65.040000 112.320000 65.064000 ;
  END
 END n_li_d[326]
 PIN n_li_d[327]
  DIRECTION INPUT ;
  USE SIGNAL ;
  PORT
   LAYER M4 ;
   RECT 112.236000 65.184000 112.320000 65.208000 ;
  END
 END n_li_d[327]
 PIN n_li_d[328]
  DIRECTION INPUT ;
  USE SIGNAL ;
  PORT
   LAYER M4 ;
   RECT 112.236000 65.376000 112.320000 65.400000 ;
  END
 END n_li_d[328]
 PIN n_li_d[329]
  DIRECTION INPUT ;
  USE SIGNAL ;
  PORT
   LAYER M4 ;
   RECT 112.236000 65.568000 112.320000 65.592000 ;
  END
 END n_li_d[329]
 PIN n_li_d[330]
  DIRECTION INPUT ;
  USE SIGNAL ;
  PORT
   LAYER M4 ;
   RECT 112.236000 65.760000 112.320000 65.784000 ;
  END
 END n_li_d[330]
 PIN n_li_d[331]
  DIRECTION INPUT ;
  USE SIGNAL ;
  PORT
   LAYER M4 ;
   RECT 112.236000 65.904000 112.320000 65.928000 ;
  END
 END n_li_d[331]
 PIN n_li_d[332]
  DIRECTION INPUT ;
  USE SIGNAL ;
  PORT
   LAYER M4 ;
   RECT 112.236000 66.096000 112.320000 66.120000 ;
  END
 END n_li_d[332]
 PIN n_li_d[333]
  DIRECTION INPUT ;
  USE SIGNAL ;
  PORT
   LAYER M4 ;
   RECT 112.236000 66.288000 112.320000 66.312000 ;
  END
 END n_li_d[333]
 PIN n_li_d[334]
  DIRECTION INPUT ;
  USE SIGNAL ;
  PORT
   LAYER M4 ;
   RECT 112.236000 66.432000 112.320000 66.456000 ;
  END
 END n_li_d[334]
 PIN n_li_d[335]
  DIRECTION INPUT ;
  USE SIGNAL ;
  PORT
   LAYER M4 ;
   RECT 112.236000 66.624000 112.320000 66.648000 ;
  END
 END n_li_d[335]
 PIN n_li_d[336]
  DIRECTION INPUT ;
  USE SIGNAL ;
  PORT
   LAYER M4 ;
   RECT 112.236000 66.816000 112.320000 66.840000 ;
  END
 END n_li_d[336]
 PIN n_li_d[337]
  DIRECTION INPUT ;
  USE SIGNAL ;
  PORT
   LAYER M4 ;
   RECT 112.236000 67.008000 112.320000 67.032000 ;
  END
 END n_li_d[337]
 PIN n_li_d[338]
  DIRECTION INPUT ;
  USE SIGNAL ;
  PORT
   LAYER M4 ;
   RECT 112.236000 67.152000 112.320000 67.176000 ;
  END
 END n_li_d[338]
 PIN n_li_d[339]
  DIRECTION INPUT ;
  USE SIGNAL ;
  PORT
   LAYER M4 ;
   RECT 112.236000 67.344000 112.320000 67.368000 ;
  END
 END n_li_d[339]
 PIN n_li_d[340]
  DIRECTION INPUT ;
  USE SIGNAL ;
  PORT
   LAYER M4 ;
   RECT 112.236000 67.536000 112.320000 67.560000 ;
  END
 END n_li_d[340]
 PIN n_li_d[341]
  DIRECTION INPUT ;
  USE SIGNAL ;
  PORT
   LAYER M4 ;
   RECT 112.236000 67.728000 112.320000 67.752000 ;
  END
 END n_li_d[341]
 PIN n_li_d[342]
  DIRECTION INPUT ;
  USE SIGNAL ;
  PORT
   LAYER M4 ;
   RECT 112.236000 67.872000 112.320000 67.896000 ;
  END
 END n_li_d[342]
 PIN n_li_d[343]
  DIRECTION INPUT ;
  USE SIGNAL ;
  PORT
   LAYER M4 ;
   RECT 112.236000 68.064000 112.320000 68.088000 ;
  END
 END n_li_d[343]
 PIN n_li_d[344]
  DIRECTION INPUT ;
  USE SIGNAL ;
  PORT
   LAYER M4 ;
   RECT 112.236000 68.256000 112.320000 68.280000 ;
  END
 END n_li_d[344]
 PIN n_li_d[345]
  DIRECTION INPUT ;
  USE SIGNAL ;
  PORT
   LAYER M4 ;
   RECT 112.236000 68.448000 112.320000 68.472000 ;
  END
 END n_li_d[345]
 PIN n_li_d[346]
  DIRECTION INPUT ;
  USE SIGNAL ;
  PORT
   LAYER M4 ;
   RECT 112.236000 68.592000 112.320000 68.616000 ;
  END
 END n_li_d[346]
 PIN n_li_d[347]
  DIRECTION INPUT ;
  USE SIGNAL ;
  PORT
   LAYER M4 ;
   RECT 112.236000 68.784000 112.320000 68.808000 ;
  END
 END n_li_d[347]
 PIN n_li_d[348]
  DIRECTION INPUT ;
  USE SIGNAL ;
  PORT
   LAYER M4 ;
   RECT 112.236000 68.976000 112.320000 69.000000 ;
  END
 END n_li_d[348]
 PIN n_li_d[349]
  DIRECTION INPUT ;
  USE SIGNAL ;
  PORT
   LAYER M4 ;
   RECT 112.236000 69.168000 112.320000 69.192000 ;
  END
 END n_li_d[349]
 PIN n_li_d[350]
  DIRECTION INPUT ;
  USE SIGNAL ;
  PORT
   LAYER M4 ;
   RECT 112.236000 69.312000 112.320000 69.336000 ;
  END
 END n_li_d[350]
 PIN n_li_d[351]
  DIRECTION INPUT ;
  USE SIGNAL ;
  PORT
   LAYER M4 ;
   RECT 112.236000 69.504000 112.320000 69.528000 ;
  END
 END n_li_d[351]
 PIN n_li_d[352]
  DIRECTION INPUT ;
  USE SIGNAL ;
  PORT
   LAYER M4 ;
   RECT 112.236000 69.696000 112.320000 69.720000 ;
  END
 END n_li_d[352]
 PIN n_li_d[353]
  DIRECTION INPUT ;
  USE SIGNAL ;
  PORT
   LAYER M4 ;
   RECT 112.236000 69.840000 112.320000 69.864000 ;
  END
 END n_li_d[353]
 PIN n_li_d[354]
  DIRECTION INPUT ;
  USE SIGNAL ;
  PORT
   LAYER M4 ;
   RECT 112.236000 70.032000 112.320000 70.056000 ;
  END
 END n_li_d[354]
 PIN n_li_d[355]
  DIRECTION INPUT ;
  USE SIGNAL ;
  PORT
   LAYER M4 ;
   RECT 112.236000 70.224000 112.320000 70.248000 ;
  END
 END n_li_d[355]
 PIN n_li_d[356]
  DIRECTION INPUT ;
  USE SIGNAL ;
  PORT
   LAYER M4 ;
   RECT 112.236000 70.416000 112.320000 70.440000 ;
  END
 END n_li_d[356]
 PIN n_li_d[357]
  DIRECTION INPUT ;
  USE SIGNAL ;
  PORT
   LAYER M4 ;
   RECT 112.236000 70.560000 112.320000 70.584000 ;
  END
 END n_li_d[357]
 PIN n_li_d[358]
  DIRECTION INPUT ;
  USE SIGNAL ;
  PORT
   LAYER M4 ;
   RECT 112.236000 70.752000 112.320000 70.776000 ;
  END
 END n_li_d[358]
 PIN n_li_d[359]
  DIRECTION INPUT ;
  USE SIGNAL ;
  PORT
   LAYER M4 ;
   RECT 112.236000 70.944000 112.320000 70.968000 ;
  END
 END n_li_d[359]
 PIN n_li_d[360]
  DIRECTION INPUT ;
  USE SIGNAL ;
  PORT
   LAYER M4 ;
   RECT 112.236000 71.136000 112.320000 71.160000 ;
  END
 END n_li_d[360]
 PIN n_li_d[361]
  DIRECTION INPUT ;
  USE SIGNAL ;
  PORT
   LAYER M4 ;
   RECT 112.236000 71.280000 112.320000 71.304000 ;
  END
 END n_li_d[361]
 PIN n_li_d[362]
  DIRECTION INPUT ;
  USE SIGNAL ;
  PORT
   LAYER M4 ;
   RECT 112.236000 71.472000 112.320000 71.496000 ;
  END
 END n_li_d[362]
 PIN n_li_d[363]
  DIRECTION INPUT ;
  USE SIGNAL ;
  PORT
   LAYER M4 ;
   RECT 112.236000 71.664000 112.320000 71.688000 ;
  END
 END n_li_d[363]
 PIN n_li_d[364]
  DIRECTION INPUT ;
  USE SIGNAL ;
  PORT
   LAYER M4 ;
   RECT 112.236000 71.856000 112.320000 71.880000 ;
  END
 END n_li_d[364]
 PIN n_li_d[365]
  DIRECTION INPUT ;
  USE SIGNAL ;
  PORT
   LAYER M4 ;
   RECT 112.236000 72.000000 112.320000 72.024000 ;
  END
 END n_li_d[365]
 PIN n_li_d[366]
  DIRECTION INPUT ;
  USE SIGNAL ;
  PORT
   LAYER M4 ;
   RECT 112.236000 72.192000 112.320000 72.216000 ;
  END
 END n_li_d[366]
 PIN n_li_d[367]
  DIRECTION INPUT ;
  USE SIGNAL ;
  PORT
   LAYER M4 ;
   RECT 112.236000 72.384000 112.320000 72.408000 ;
  END
 END n_li_d[367]
 PIN n_li_d[368]
  DIRECTION INPUT ;
  USE SIGNAL ;
  PORT
   LAYER M4 ;
   RECT 112.236000 72.528000 112.320000 72.552000 ;
  END
 END n_li_d[368]
 PIN n_li_d[369]
  DIRECTION INPUT ;
  USE SIGNAL ;
  PORT
   LAYER M4 ;
   RECT 112.236000 72.720000 112.320000 72.744000 ;
  END
 END n_li_d[369]
 PIN n_li_d[370]
  DIRECTION INPUT ;
  USE SIGNAL ;
  PORT
   LAYER M4 ;
   RECT 112.236000 72.912000 112.320000 72.936000 ;
  END
 END n_li_d[370]
 PIN n_li_d[371]
  DIRECTION INPUT ;
  USE SIGNAL ;
  PORT
   LAYER M4 ;
   RECT 112.236000 73.104000 112.320000 73.128000 ;
  END
 END n_li_d[371]
 PIN n_li_d[372]
  DIRECTION INPUT ;
  USE SIGNAL ;
  PORT
   LAYER M4 ;
   RECT 112.236000 73.248000 112.320000 73.272000 ;
  END
 END n_li_d[372]
 PIN n_li_d[373]
  DIRECTION INPUT ;
  USE SIGNAL ;
  PORT
   LAYER M4 ;
   RECT 112.236000 73.440000 112.320000 73.464000 ;
  END
 END n_li_d[373]
 PIN n_li_d[374]
  DIRECTION INPUT ;
  USE SIGNAL ;
  PORT
   LAYER M4 ;
   RECT 112.236000 73.632000 112.320000 73.656000 ;
  END
 END n_li_d[374]
 PIN n_li_d[375]
  DIRECTION INPUT ;
  USE SIGNAL ;
  PORT
   LAYER M4 ;
   RECT 112.236000 73.824000 112.320000 73.848000 ;
  END
 END n_li_d[375]
 PIN n_li_d[376]
  DIRECTION INPUT ;
  USE SIGNAL ;
  PORT
   LAYER M4 ;
   RECT 112.236000 73.968000 112.320000 73.992000 ;
  END
 END n_li_d[376]
 PIN n_li_d[377]
  DIRECTION INPUT ;
  USE SIGNAL ;
  PORT
   LAYER M4 ;
   RECT 112.236000 74.160000 112.320000 74.184000 ;
  END
 END n_li_d[377]
 PIN n_li_d[378]
  DIRECTION INPUT ;
  USE SIGNAL ;
  PORT
   LAYER M4 ;
   RECT 112.236000 74.352000 112.320000 74.376000 ;
  END
 END n_li_d[378]
 PIN n_li_d[379]
  DIRECTION INPUT ;
  USE SIGNAL ;
  PORT
   LAYER M4 ;
   RECT 112.236000 74.544000 112.320000 74.568000 ;
  END
 END n_li_d[379]
 PIN n_li_d[380]
  DIRECTION INPUT ;
  USE SIGNAL ;
  PORT
   LAYER M4 ;
   RECT 112.236000 74.688000 112.320000 74.712000 ;
  END
 END n_li_d[380]
 PIN n_li_d[381]
  DIRECTION INPUT ;
  USE SIGNAL ;
  PORT
   LAYER M4 ;
   RECT 112.236000 74.880000 112.320000 74.904000 ;
  END
 END n_li_d[381]
 PIN n_li_d[382]
  DIRECTION INPUT ;
  USE SIGNAL ;
  PORT
   LAYER M4 ;
   RECT 112.236000 75.072000 112.320000 75.096000 ;
  END
 END n_li_d[382]
 PIN n_li_d[383]
  DIRECTION INPUT ;
  USE SIGNAL ;
  PORT
   LAYER M4 ;
   RECT 112.236000 75.264000 112.320000 75.288000 ;
  END
 END n_li_d[383]
 PIN n_li_d[384]
  DIRECTION INPUT ;
  USE SIGNAL ;
  PORT
   LAYER M4 ;
   RECT 112.236000 75.408000 112.320000 75.432000 ;
  END
 END n_li_d[384]
 PIN n_li_d[385]
  DIRECTION INPUT ;
  USE SIGNAL ;
  PORT
   LAYER M4 ;
   RECT 112.236000 75.600000 112.320000 75.624000 ;
  END
 END n_li_d[385]
 PIN n_li_d[386]
  DIRECTION INPUT ;
  USE SIGNAL ;
  PORT
   LAYER M4 ;
   RECT 112.236000 75.792000 112.320000 75.816000 ;
  END
 END n_li_d[386]
 PIN n_li_d[387]
  DIRECTION INPUT ;
  USE SIGNAL ;
  PORT
   LAYER M4 ;
   RECT 112.236000 75.936000 112.320000 75.960000 ;
  END
 END n_li_d[387]
 PIN n_li_d[388]
  DIRECTION INPUT ;
  USE SIGNAL ;
  PORT
   LAYER M4 ;
   RECT 112.236000 76.128000 112.320000 76.152000 ;
  END
 END n_li_d[388]
 PIN n_li_d[389]
  DIRECTION INPUT ;
  USE SIGNAL ;
  PORT
   LAYER M4 ;
   RECT 112.236000 76.320000 112.320000 76.344000 ;
  END
 END n_li_d[389]
 PIN n_li_d[390]
  DIRECTION INPUT ;
  USE SIGNAL ;
  PORT
   LAYER M4 ;
   RECT 112.236000 76.512000 112.320000 76.536000 ;
  END
 END n_li_d[390]
 PIN n_li_d[391]
  DIRECTION INPUT ;
  USE SIGNAL ;
  PORT
   LAYER M4 ;
   RECT 112.236000 76.656000 112.320000 76.680000 ;
  END
 END n_li_d[391]
 PIN n_li_d[392]
  DIRECTION INPUT ;
  USE SIGNAL ;
  PORT
   LAYER M4 ;
   RECT 112.236000 76.848000 112.320000 76.872000 ;
  END
 END n_li_d[392]
 PIN n_li_d[393]
  DIRECTION INPUT ;
  USE SIGNAL ;
  PORT
   LAYER M4 ;
   RECT 112.236000 77.040000 112.320000 77.064000 ;
  END
 END n_li_d[393]
 PIN n_li_d[394]
  DIRECTION INPUT ;
  USE SIGNAL ;
  PORT
   LAYER M4 ;
   RECT 112.236000 77.232000 112.320000 77.256000 ;
  END
 END n_li_d[394]
 PIN n_li_d[395]
  DIRECTION INPUT ;
  USE SIGNAL ;
  PORT
   LAYER M4 ;
   RECT 112.236000 77.376000 112.320000 77.400000 ;
  END
 END n_li_d[395]
 PIN n_li_d[396]
  DIRECTION INPUT ;
  USE SIGNAL ;
  PORT
   LAYER M4 ;
   RECT 112.236000 77.568000 112.320000 77.592000 ;
  END
 END n_li_d[396]
 PIN n_li_d[397]
  DIRECTION INPUT ;
  USE SIGNAL ;
  PORT
   LAYER M4 ;
   RECT 112.236000 77.760000 112.320000 77.784000 ;
  END
 END n_li_d[397]
 PIN n_li_d[398]
  DIRECTION INPUT ;
  USE SIGNAL ;
  PORT
   LAYER M4 ;
   RECT 112.236000 77.952000 112.320000 77.976000 ;
  END
 END n_li_d[398]
 PIN n_li_d[399]
  DIRECTION INPUT ;
  USE SIGNAL ;
  PORT
   LAYER M4 ;
   RECT 112.236000 78.096000 112.320000 78.120000 ;
  END
 END n_li_d[399]
 PIN n_li_d[400]
  DIRECTION INPUT ;
  USE SIGNAL ;
  PORT
   LAYER M4 ;
   RECT 112.236000 78.288000 112.320000 78.312000 ;
  END
 END n_li_d[400]
 PIN n_li_d[401]
  DIRECTION INPUT ;
  USE SIGNAL ;
  PORT
   LAYER M4 ;
   RECT 112.236000 78.480000 112.320000 78.504000 ;
  END
 END n_li_d[401]
 PIN n_li_d[402]
  DIRECTION INPUT ;
  USE SIGNAL ;
  PORT
   LAYER M4 ;
   RECT 112.236000 78.624000 112.320000 78.648000 ;
  END
 END n_li_d[402]
 PIN n_li_d[403]
  DIRECTION INPUT ;
  USE SIGNAL ;
  PORT
   LAYER M4 ;
   RECT 112.236000 78.816000 112.320000 78.840000 ;
  END
 END n_li_d[403]
 PIN n_li_d[404]
  DIRECTION INPUT ;
  USE SIGNAL ;
  PORT
   LAYER M4 ;
   RECT 112.236000 79.008000 112.320000 79.032000 ;
  END
 END n_li_d[404]
 PIN n_li_d[405]
  DIRECTION INPUT ;
  USE SIGNAL ;
  PORT
   LAYER M4 ;
   RECT 112.236000 79.200000 112.320000 79.224000 ;
  END
 END n_li_d[405]
 PIN n_li_d[406]
  DIRECTION INPUT ;
  USE SIGNAL ;
  PORT
   LAYER M4 ;
   RECT 112.236000 79.344000 112.320000 79.368000 ;
  END
 END n_li_d[406]
 PIN n_li_d[407]
  DIRECTION INPUT ;
  USE SIGNAL ;
  PORT
   LAYER M4 ;
   RECT 112.236000 79.536000 112.320000 79.560000 ;
  END
 END n_li_d[407]
 PIN n_li_d[408]
  DIRECTION INPUT ;
  USE SIGNAL ;
  PORT
   LAYER M4 ;
   RECT 112.236000 79.728000 112.320000 79.752000 ;
  END
 END n_li_d[408]
 PIN n_li_d[409]
  DIRECTION INPUT ;
  USE SIGNAL ;
  PORT
   LAYER M4 ;
   RECT 112.236000 79.920000 112.320000 79.944000 ;
  END
 END n_li_d[409]
 PIN n_li_d[410]
  DIRECTION INPUT ;
  USE SIGNAL ;
  PORT
   LAYER M4 ;
   RECT 112.236000 80.064000 112.320000 80.088000 ;
  END
 END n_li_d[410]
 PIN n_li_d[411]
  DIRECTION INPUT ;
  USE SIGNAL ;
  PORT
   LAYER M4 ;
   RECT 112.236000 80.256000 112.320000 80.280000 ;
  END
 END n_li_d[411]
 PIN n_li_d[412]
  DIRECTION INPUT ;
  USE SIGNAL ;
  PORT
   LAYER M4 ;
   RECT 112.236000 80.448000 112.320000 80.472000 ;
  END
 END n_li_d[412]
 PIN n_li_d[413]
  DIRECTION INPUT ;
  USE SIGNAL ;
  PORT
   LAYER M4 ;
   RECT 112.236000 80.640000 112.320000 80.664000 ;
  END
 END n_li_d[413]
 PIN n_li_d[414]
  DIRECTION INPUT ;
  USE SIGNAL ;
  PORT
   LAYER M4 ;
   RECT 112.236000 80.784000 112.320000 80.808000 ;
  END
 END n_li_d[414]
 PIN n_li_d[415]
  DIRECTION INPUT ;
  USE SIGNAL ;
  PORT
   LAYER M4 ;
   RECT 112.236000 80.976000 112.320000 81.000000 ;
  END
 END n_li_d[415]
 PIN n_li_d[416]
  DIRECTION INPUT ;
  USE SIGNAL ;
  PORT
   LAYER M4 ;
   RECT 112.236000 81.168000 112.320000 81.192000 ;
  END
 END n_li_d[416]
 PIN n_li_d[417]
  DIRECTION INPUT ;
  USE SIGNAL ;
  PORT
   LAYER M4 ;
   RECT 112.236000 81.312000 112.320000 81.336000 ;
  END
 END n_li_d[417]
 PIN n_li_d[418]
  DIRECTION INPUT ;
  USE SIGNAL ;
  PORT
   LAYER M4 ;
   RECT 112.236000 81.504000 112.320000 81.528000 ;
  END
 END n_li_d[418]
 PIN n_li_d[419]
  DIRECTION INPUT ;
  USE SIGNAL ;
  PORT
   LAYER M4 ;
   RECT 112.236000 81.696000 112.320000 81.720000 ;
  END
 END n_li_d[419]
 PIN n_li_d[420]
  DIRECTION INPUT ;
  USE SIGNAL ;
  PORT
   LAYER M4 ;
   RECT 112.236000 81.888000 112.320000 81.912000 ;
  END
 END n_li_d[420]
 PIN n_li_d[421]
  DIRECTION INPUT ;
  USE SIGNAL ;
  PORT
   LAYER M4 ;
   RECT 112.236000 82.032000 112.320000 82.056000 ;
  END
 END n_li_d[421]
 PIN n_li_d[422]
  DIRECTION INPUT ;
  USE SIGNAL ;
  PORT
   LAYER M4 ;
   RECT 112.236000 82.224000 112.320000 82.248000 ;
  END
 END n_li_d[422]
 PIN n_li_d[423]
  DIRECTION INPUT ;
  USE SIGNAL ;
  PORT
   LAYER M4 ;
   RECT 112.236000 82.416000 112.320000 82.440000 ;
  END
 END n_li_d[423]
 PIN n_li_d[424]
  DIRECTION INPUT ;
  USE SIGNAL ;
  PORT
   LAYER M4 ;
   RECT 112.236000 82.608000 112.320000 82.632000 ;
  END
 END n_li_d[424]
 PIN n_li_d[425]
  DIRECTION INPUT ;
  USE SIGNAL ;
  PORT
   LAYER M4 ;
   RECT 112.236000 82.752000 112.320000 82.776000 ;
  END
 END n_li_d[425]
 PIN n_li_d[426]
  DIRECTION INPUT ;
  USE SIGNAL ;
  PORT
   LAYER M4 ;
   RECT 112.236000 82.944000 112.320000 82.968000 ;
  END
 END n_li_d[426]
 PIN n_li_d[427]
  DIRECTION INPUT ;
  USE SIGNAL ;
  PORT
   LAYER M4 ;
   RECT 112.236000 83.136000 112.320000 83.160000 ;
  END
 END n_li_d[427]
 PIN n_li_d[428]
  DIRECTION INPUT ;
  USE SIGNAL ;
  PORT
   LAYER M4 ;
   RECT 112.236000 83.328000 112.320000 83.352000 ;
  END
 END n_li_d[428]
 PIN n_li_d[429]
  DIRECTION INPUT ;
  USE SIGNAL ;
  PORT
   LAYER M4 ;
   RECT 112.236000 83.472000 112.320000 83.496000 ;
  END
 END n_li_d[429]
 PIN n_li_d[430]
  DIRECTION INPUT ;
  USE SIGNAL ;
  PORT
   LAYER M4 ;
   RECT 112.236000 83.664000 112.320000 83.688000 ;
  END
 END n_li_d[430]
 PIN n_li_d[431]
  DIRECTION INPUT ;
  USE SIGNAL ;
  PORT
   LAYER M4 ;
   RECT 112.236000 83.856000 112.320000 83.880000 ;
  END
 END n_li_d[431]
 PIN n_li_d[432]
  DIRECTION INPUT ;
  USE SIGNAL ;
  PORT
   LAYER M4 ;
   RECT 112.236000 84.048000 112.320000 84.072000 ;
  END
 END n_li_d[432]
 PIN n_li_d[433]
  DIRECTION INPUT ;
  USE SIGNAL ;
  PORT
   LAYER M4 ;
   RECT 112.236000 84.192000 112.320000 84.216000 ;
  END
 END n_li_d[433]
 PIN n_li_d[434]
  DIRECTION INPUT ;
  USE SIGNAL ;
  PORT
   LAYER M4 ;
   RECT 112.236000 84.384000 112.320000 84.408000 ;
  END
 END n_li_d[434]
 PIN n_li_d[435]
  DIRECTION INPUT ;
  USE SIGNAL ;
  PORT
   LAYER M4 ;
   RECT 112.236000 84.576000 112.320000 84.600000 ;
  END
 END n_li_d[435]
 PIN n_li_d[436]
  DIRECTION INPUT ;
  USE SIGNAL ;
  PORT
   LAYER M4 ;
   RECT 112.236000 84.720000 112.320000 84.744000 ;
  END
 END n_li_d[436]
 PIN n_li_d[437]
  DIRECTION INPUT ;
  USE SIGNAL ;
  PORT
   LAYER M4 ;
   RECT 112.236000 84.912000 112.320000 84.936000 ;
  END
 END n_li_d[437]
 PIN n_li_d[438]
  DIRECTION INPUT ;
  USE SIGNAL ;
  PORT
   LAYER M4 ;
   RECT 112.236000 85.104000 112.320000 85.128000 ;
  END
 END n_li_d[438]
 PIN n_li_d[439]
  DIRECTION INPUT ;
  USE SIGNAL ;
  PORT
   LAYER M4 ;
   RECT 112.236000 85.296000 112.320000 85.320000 ;
  END
 END n_li_d[439]
 PIN n_li_d[440]
  DIRECTION INPUT ;
  USE SIGNAL ;
  PORT
   LAYER M4 ;
   RECT 112.236000 85.440000 112.320000 85.464000 ;
  END
 END n_li_d[440]
 PIN n_li_d[441]
  DIRECTION INPUT ;
  USE SIGNAL ;
  PORT
   LAYER M4 ;
   RECT 112.236000 85.632000 112.320000 85.656000 ;
  END
 END n_li_d[441]
 PIN n_li_d[442]
  DIRECTION INPUT ;
  USE SIGNAL ;
  PORT
   LAYER M4 ;
   RECT 112.236000 85.824000 112.320000 85.848000 ;
  END
 END n_li_d[442]
 PIN n_li_d[443]
  DIRECTION INPUT ;
  USE SIGNAL ;
  PORT
   LAYER M4 ;
   RECT 112.236000 86.016000 112.320000 86.040000 ;
  END
 END n_li_d[443]
 PIN n_li_d[444]
  DIRECTION INPUT ;
  USE SIGNAL ;
  PORT
   LAYER M4 ;
   RECT 112.236000 86.160000 112.320000 86.184000 ;
  END
 END n_li_d[444]
 PIN n_li_d[445]
  DIRECTION INPUT ;
  USE SIGNAL ;
  PORT
   LAYER M4 ;
   RECT 112.236000 86.352000 112.320000 86.376000 ;
  END
 END n_li_d[445]
 PIN n_li_d[446]
  DIRECTION INPUT ;
  USE SIGNAL ;
  PORT
   LAYER M4 ;
   RECT 112.236000 86.544000 112.320000 86.568000 ;
  END
 END n_li_d[446]
 PIN n_li_d[447]
  DIRECTION INPUT ;
  USE SIGNAL ;
  PORT
   LAYER M4 ;
   RECT 112.236000 86.736000 112.320000 86.760000 ;
  END
 END n_li_d[447]
 PIN n_li_d[448]
  DIRECTION INPUT ;
  USE SIGNAL ;
  PORT
   LAYER M4 ;
   RECT 112.236000 86.880000 112.320000 86.904000 ;
  END
 END n_li_d[448]
 PIN n_li_d[449]
  DIRECTION INPUT ;
  USE SIGNAL ;
  PORT
   LAYER M4 ;
   RECT 112.236000 87.072000 112.320000 87.096000 ;
  END
 END n_li_d[449]
 PIN n_li_d[450]
  DIRECTION INPUT ;
  USE SIGNAL ;
  PORT
   LAYER M4 ;
   RECT 112.236000 87.264000 112.320000 87.288000 ;
  END
 END n_li_d[450]
 PIN n_li_d[451]
  DIRECTION INPUT ;
  USE SIGNAL ;
  PORT
   LAYER M4 ;
   RECT 112.236000 87.408000 112.320000 87.432000 ;
  END
 END n_li_d[451]
 PIN n_li_d[452]
  DIRECTION INPUT ;
  USE SIGNAL ;
  PORT
   LAYER M4 ;
   RECT 112.236000 87.600000 112.320000 87.624000 ;
  END
 END n_li_d[452]
 PIN n_li_d[453]
  DIRECTION INPUT ;
  USE SIGNAL ;
  PORT
   LAYER M4 ;
   RECT 112.236000 87.792000 112.320000 87.816000 ;
  END
 END n_li_d[453]
 PIN n_li_d[454]
  DIRECTION INPUT ;
  USE SIGNAL ;
  PORT
   LAYER M4 ;
   RECT 112.236000 87.984000 112.320000 88.008000 ;
  END
 END n_li_d[454]
 PIN n_li_d[455]
  DIRECTION INPUT ;
  USE SIGNAL ;
  PORT
   LAYER M4 ;
   RECT 112.236000 88.128000 112.320000 88.152000 ;
  END
 END n_li_d[455]
 PIN n_li_d[456]
  DIRECTION INPUT ;
  USE SIGNAL ;
  PORT
   LAYER M4 ;
   RECT 112.236000 88.320000 112.320000 88.344000 ;
  END
 END n_li_d[456]
 PIN n_li_d[457]
  DIRECTION INPUT ;
  USE SIGNAL ;
  PORT
   LAYER M4 ;
   RECT 112.236000 88.512000 112.320000 88.536000 ;
  END
 END n_li_d[457]
 PIN n_li_d[458]
  DIRECTION INPUT ;
  USE SIGNAL ;
  PORT
   LAYER M4 ;
   RECT 112.236000 88.704000 112.320000 88.728000 ;
  END
 END n_li_d[458]
 PIN n_li_d[459]
  DIRECTION INPUT ;
  USE SIGNAL ;
  PORT
   LAYER M4 ;
   RECT 112.236000 88.848000 112.320000 88.872000 ;
  END
 END n_li_d[459]
 PIN n_li_d[460]
  DIRECTION INPUT ;
  USE SIGNAL ;
  PORT
   LAYER M4 ;
   RECT 112.236000 89.040000 112.320000 89.064000 ;
  END
 END n_li_d[460]
 PIN n_li_d[461]
  DIRECTION INPUT ;
  USE SIGNAL ;
  PORT
   LAYER M4 ;
   RECT 112.236000 89.232000 112.320000 89.256000 ;
  END
 END n_li_d[461]
 PIN n_li_d[462]
  DIRECTION INPUT ;
  USE SIGNAL ;
  PORT
   LAYER M4 ;
   RECT 112.236000 89.424000 112.320000 89.448000 ;
  END
 END n_li_d[462]
 PIN n_li_d[463]
  DIRECTION INPUT ;
  USE SIGNAL ;
  PORT
   LAYER M4 ;
   RECT 112.236000 89.568000 112.320000 89.592000 ;
  END
 END n_li_d[463]
 PIN n_li_d[464]
  DIRECTION INPUT ;
  USE SIGNAL ;
  PORT
   LAYER M4 ;
   RECT 112.236000 89.760000 112.320000 89.784000 ;
  END
 END n_li_d[464]
 PIN n_li_d[465]
  DIRECTION INPUT ;
  USE SIGNAL ;
  PORT
   LAYER M4 ;
   RECT 112.236000 89.952000 112.320000 89.976000 ;
  END
 END n_li_d[465]
 PIN n_li_d[466]
  DIRECTION INPUT ;
  USE SIGNAL ;
  PORT
   LAYER M4 ;
   RECT 112.236000 90.096000 112.320000 90.120000 ;
  END
 END n_li_d[466]
 PIN n_li_d[467]
  DIRECTION INPUT ;
  USE SIGNAL ;
  PORT
   LAYER M4 ;
   RECT 112.236000 90.288000 112.320000 90.312000 ;
  END
 END n_li_d[467]
 PIN n_li_d[468]
  DIRECTION INPUT ;
  USE SIGNAL ;
  PORT
   LAYER M4 ;
   RECT 112.236000 90.480000 112.320000 90.504000 ;
  END
 END n_li_d[468]
 PIN n_li_d[469]
  DIRECTION INPUT ;
  USE SIGNAL ;
  PORT
   LAYER M4 ;
   RECT 112.236000 90.672000 112.320000 90.696000 ;
  END
 END n_li_d[469]
 PIN n_li_d[470]
  DIRECTION INPUT ;
  USE SIGNAL ;
  PORT
   LAYER M4 ;
   RECT 112.236000 90.816000 112.320000 90.840000 ;
  END
 END n_li_d[470]
 PIN n_li_d[471]
  DIRECTION INPUT ;
  USE SIGNAL ;
  PORT
   LAYER M4 ;
   RECT 112.236000 91.008000 112.320000 91.032000 ;
  END
 END n_li_d[471]
 PIN n_li_d[472]
  DIRECTION INPUT ;
  USE SIGNAL ;
  PORT
   LAYER M4 ;
   RECT 112.236000 91.200000 112.320000 91.224000 ;
  END
 END n_li_d[472]
 PIN n_li_d[473]
  DIRECTION INPUT ;
  USE SIGNAL ;
  PORT
   LAYER M4 ;
   RECT 112.236000 91.392000 112.320000 91.416000 ;
  END
 END n_li_d[473]
 PIN n_li_d[474]
  DIRECTION INPUT ;
  USE SIGNAL ;
  PORT
   LAYER M4 ;
   RECT 112.236000 91.536000 112.320000 91.560000 ;
  END
 END n_li_d[474]
 PIN n_li_d[475]
  DIRECTION INPUT ;
  USE SIGNAL ;
  PORT
   LAYER M4 ;
   RECT 112.236000 91.728000 112.320000 91.752000 ;
  END
 END n_li_d[475]
 PIN n_li_d[476]
  DIRECTION INPUT ;
  USE SIGNAL ;
  PORT
   LAYER M4 ;
   RECT 112.236000 91.920000 112.320000 91.944000 ;
  END
 END n_li_d[476]
 PIN n_li_d[477]
  DIRECTION INPUT ;
  USE SIGNAL ;
  PORT
   LAYER M4 ;
   RECT 112.236000 92.112000 112.320000 92.136000 ;
  END
 END n_li_d[477]
 PIN n_li_d[478]
  DIRECTION INPUT ;
  USE SIGNAL ;
  PORT
   LAYER M4 ;
   RECT 112.236000 92.256000 112.320000 92.280000 ;
  END
 END n_li_d[478]
 PIN n_li_d[479]
  DIRECTION INPUT ;
  USE SIGNAL ;
  PORT
   LAYER M4 ;
   RECT 112.236000 92.448000 112.320000 92.472000 ;
  END
 END n_li_d[479]
 PIN n_li_d[480]
  DIRECTION INPUT ;
  USE SIGNAL ;
  PORT
   LAYER M4 ;
   RECT 112.236000 92.640000 112.320000 92.664000 ;
  END
 END n_li_d[480]
 PIN n_li_d[481]
  DIRECTION INPUT ;
  USE SIGNAL ;
  PORT
   LAYER M4 ;
   RECT 112.236000 92.832000 112.320000 92.856000 ;
  END
 END n_li_d[481]
 PIN n_li_d[482]
  DIRECTION INPUT ;
  USE SIGNAL ;
  PORT
   LAYER M4 ;
   RECT 112.236000 92.976000 112.320000 93.000000 ;
  END
 END n_li_d[482]
 PIN n_li_d[483]
  DIRECTION INPUT ;
  USE SIGNAL ;
  PORT
   LAYER M4 ;
   RECT 112.236000 93.168000 112.320000 93.192000 ;
  END
 END n_li_d[483]
 PIN n_li_d[484]
  DIRECTION INPUT ;
  USE SIGNAL ;
  PORT
   LAYER M4 ;
   RECT 112.236000 93.360000 112.320000 93.384000 ;
  END
 END n_li_d[484]
 PIN n_li_d[485]
  DIRECTION INPUT ;
  USE SIGNAL ;
  PORT
   LAYER M4 ;
   RECT 112.236000 93.504000 112.320000 93.528000 ;
  END
 END n_li_d[485]
 PIN n_li_d[486]
  DIRECTION INPUT ;
  USE SIGNAL ;
  PORT
   LAYER M4 ;
   RECT 112.236000 93.696000 112.320000 93.720000 ;
  END
 END n_li_d[486]
 PIN n_li_d[487]
  DIRECTION INPUT ;
  USE SIGNAL ;
  PORT
   LAYER M4 ;
   RECT 112.236000 93.888000 112.320000 93.912000 ;
  END
 END n_li_d[487]
 PIN n_li_d[488]
  DIRECTION INPUT ;
  USE SIGNAL ;
  PORT
   LAYER M4 ;
   RECT 112.236000 94.080000 112.320000 94.104000 ;
  END
 END n_li_d[488]
 PIN n_li_d[489]
  DIRECTION INPUT ;
  USE SIGNAL ;
  PORT
   LAYER M4 ;
   RECT 112.236000 94.224000 112.320000 94.248000 ;
  END
 END n_li_d[489]
 PIN n_li_d[490]
  DIRECTION INPUT ;
  USE SIGNAL ;
  PORT
   LAYER M4 ;
   RECT 112.236000 94.416000 112.320000 94.440000 ;
  END
 END n_li_d[490]
 PIN n_li_d[491]
  DIRECTION INPUT ;
  USE SIGNAL ;
  PORT
   LAYER M4 ;
   RECT 112.236000 94.608000 112.320000 94.632000 ;
  END
 END n_li_d[491]
 PIN n_li_d[492]
  DIRECTION INPUT ;
  USE SIGNAL ;
  PORT
   LAYER M4 ;
   RECT 112.236000 94.800000 112.320000 94.824000 ;
  END
 END n_li_d[492]
 PIN n_li_d[493]
  DIRECTION INPUT ;
  USE SIGNAL ;
  PORT
   LAYER M4 ;
   RECT 112.236000 94.944000 112.320000 94.968000 ;
  END
 END n_li_d[493]
 PIN n_li_d[494]
  DIRECTION INPUT ;
  USE SIGNAL ;
  PORT
   LAYER M4 ;
   RECT 112.236000 95.136000 112.320000 95.160000 ;
  END
 END n_li_d[494]
 PIN n_li_d[495]
  DIRECTION INPUT ;
  USE SIGNAL ;
  PORT
   LAYER M4 ;
   RECT 112.236000 95.328000 112.320000 95.352000 ;
  END
 END n_li_d[495]
 PIN n_li_d[496]
  DIRECTION INPUT ;
  USE SIGNAL ;
  PORT
   LAYER M4 ;
   RECT 112.236000 95.520000 112.320000 95.544000 ;
  END
 END n_li_d[496]
 PIN n_li_d[497]
  DIRECTION INPUT ;
  USE SIGNAL ;
  PORT
   LAYER M4 ;
   RECT 112.236000 95.664000 112.320000 95.688000 ;
  END
 END n_li_d[497]
 PIN n_li_d[498]
  DIRECTION INPUT ;
  USE SIGNAL ;
  PORT
   LAYER M4 ;
   RECT 112.236000 95.856000 112.320000 95.880000 ;
  END
 END n_li_d[498]
 PIN n_li_d[499]
  DIRECTION INPUT ;
  USE SIGNAL ;
  PORT
   LAYER M4 ;
   RECT 112.236000 96.048000 112.320000 96.072000 ;
  END
 END n_li_d[499]
 PIN n_li_d[500]
  DIRECTION INPUT ;
  USE SIGNAL ;
  PORT
   LAYER M4 ;
   RECT 112.236000 96.192000 112.320000 96.216000 ;
  END
 END n_li_d[500]
 PIN n_li_d[501]
  DIRECTION INPUT ;
  USE SIGNAL ;
  PORT
   LAYER M4 ;
   RECT 112.236000 96.384000 112.320000 96.408000 ;
  END
 END n_li_d[501]
 PIN n_li_d[502]
  DIRECTION INPUT ;
  USE SIGNAL ;
  PORT
   LAYER M4 ;
   RECT 112.236000 96.576000 112.320000 96.600000 ;
  END
 END n_li_d[502]
 PIN n_li_d[503]
  DIRECTION INPUT ;
  USE SIGNAL ;
  PORT
   LAYER M4 ;
   RECT 112.236000 96.768000 112.320000 96.792000 ;
  END
 END n_li_d[503]
 PIN n_li_d[504]
  DIRECTION INPUT ;
  USE SIGNAL ;
  PORT
   LAYER M4 ;
   RECT 112.236000 96.912000 112.320000 96.936000 ;
  END
 END n_li_d[504]
 PIN n_li_d[505]
  DIRECTION INPUT ;
  USE SIGNAL ;
  PORT
   LAYER M4 ;
   RECT 112.236000 97.104000 112.320000 97.128000 ;
  END
 END n_li_d[505]
 PIN n_li_d[506]
  DIRECTION INPUT ;
  USE SIGNAL ;
  PORT
   LAYER M4 ;
   RECT 112.236000 97.296000 112.320000 97.320000 ;
  END
 END n_li_d[506]
 PIN n_li_d[507]
  DIRECTION INPUT ;
  USE SIGNAL ;
  PORT
   LAYER M4 ;
   RECT 112.236000 97.488000 112.320000 97.512000 ;
  END
 END n_li_d[507]
 PIN n_li_d[508]
  DIRECTION INPUT ;
  USE SIGNAL ;
  PORT
   LAYER M4 ;
   RECT 112.236000 97.632000 112.320000 97.656000 ;
  END
 END n_li_d[508]
 PIN n_li_d[509]
  DIRECTION INPUT ;
  USE SIGNAL ;
  PORT
   LAYER M4 ;
   RECT 112.236000 97.824000 112.320000 97.848000 ;
  END
 END n_li_d[509]
 PIN n_li_d[510]
  DIRECTION INPUT ;
  USE SIGNAL ;
  PORT
   LAYER M4 ;
   RECT 112.236000 98.016000 112.320000 98.040000 ;
  END
 END n_li_d[510]
 PIN n_li_d[511]
  DIRECTION INPUT ;
  USE SIGNAL ;
  PORT
   LAYER M4 ;
   RECT 112.236000 98.208000 112.320000 98.232000 ;
  END
 END n_li_d[511]
 PIN n_li_d[512]
  DIRECTION INPUT ;
  USE SIGNAL ;
  PORT
   LAYER M4 ;
   RECT 112.236000 98.352000 112.320000 98.376000 ;
  END
 END n_li_d[512]
 PIN n_li_d[513]
  DIRECTION INPUT ;
  USE SIGNAL ;
  PORT
   LAYER M4 ;
   RECT 112.236000 98.544000 112.320000 98.568000 ;
  END
 END n_li_d[513]
 PIN n_li_d[514]
  DIRECTION INPUT ;
  USE SIGNAL ;
  PORT
   LAYER M4 ;
   RECT 112.236000 98.736000 112.320000 98.760000 ;
  END
 END n_li_d[514]
 PIN n_li_d[515]
  DIRECTION INPUT ;
  USE SIGNAL ;
  PORT
   LAYER M4 ;
   RECT 112.236000 98.880000 112.320000 98.904000 ;
  END
 END n_li_d[515]
 PIN n_li_d[516]
  DIRECTION INPUT ;
  USE SIGNAL ;
  PORT
   LAYER M4 ;
   RECT 112.236000 99.072000 112.320000 99.096000 ;
  END
 END n_li_d[516]
 PIN n_li_d[517]
  DIRECTION INPUT ;
  USE SIGNAL ;
  PORT
   LAYER M4 ;
   RECT 112.236000 99.264000 112.320000 99.288000 ;
  END
 END n_li_d[517]
 PIN n_li_d[518]
  DIRECTION INPUT ;
  USE SIGNAL ;
  PORT
   LAYER M4 ;
   RECT 112.236000 99.456000 112.320000 99.480000 ;
  END
 END n_li_d[518]
 PIN n_li_d[519]
  DIRECTION INPUT ;
  USE SIGNAL ;
  PORT
   LAYER M4 ;
   RECT 112.236000 99.600000 112.320000 99.624000 ;
  END
 END n_li_d[519]
 PIN n_li_d[520]
  DIRECTION INPUT ;
  USE SIGNAL ;
  PORT
   LAYER M4 ;
   RECT 112.236000 99.792000 112.320000 99.816000 ;
  END
 END n_li_d[520]
 PIN n_li_d[521]
  DIRECTION INPUT ;
  USE SIGNAL ;
  PORT
   LAYER M4 ;
   RECT 112.236000 99.984000 112.320000 100.008000 ;
  END
 END n_li_d[521]
 PIN n_li_d[522]
  DIRECTION INPUT ;
  USE SIGNAL ;
  PORT
   LAYER M4 ;
   RECT 112.236000 100.176000 112.320000 100.200000 ;
  END
 END n_li_d[522]
 PIN n_li_d[523]
  DIRECTION INPUT ;
  USE SIGNAL ;
  PORT
   LAYER M4 ;
   RECT 112.236000 100.320000 112.320000 100.344000 ;
  END
 END n_li_d[523]
 PIN n_li_d[524]
  DIRECTION INPUT ;
  USE SIGNAL ;
  PORT
   LAYER M4 ;
   RECT 112.236000 100.512000 112.320000 100.536000 ;
  END
 END n_li_d[524]
 PIN n_li_d[525]
  DIRECTION INPUT ;
  USE SIGNAL ;
  PORT
   LAYER M4 ;
   RECT 112.236000 100.704000 112.320000 100.728000 ;
  END
 END n_li_d[525]
 PIN n_li_d[526]
  DIRECTION INPUT ;
  USE SIGNAL ;
  PORT
   LAYER M4 ;
   RECT 112.236000 100.896000 112.320000 100.920000 ;
  END
 END n_li_d[526]
 PIN n_li_d[527]
  DIRECTION INPUT ;
  USE SIGNAL ;
  PORT
   LAYER M4 ;
   RECT 112.236000 101.040000 112.320000 101.064000 ;
  END
 END n_li_d[527]
 PIN n_li_d[528]
  DIRECTION INPUT ;
  USE SIGNAL ;
  PORT
   LAYER M4 ;
   RECT 112.236000 101.232000 112.320000 101.256000 ;
  END
 END n_li_d[528]
 PIN n_li_d[529]
  DIRECTION INPUT ;
  USE SIGNAL ;
  PORT
   LAYER M4 ;
   RECT 112.236000 101.424000 112.320000 101.448000 ;
  END
 END n_li_d[529]
 PIN n_li_d[530]
  DIRECTION INPUT ;
  USE SIGNAL ;
  PORT
   LAYER M4 ;
   RECT 112.236000 101.616000 112.320000 101.640000 ;
  END
 END n_li_d[530]
 PIN n_li_d[531]
  DIRECTION INPUT ;
  USE SIGNAL ;
  PORT
   LAYER M4 ;
   RECT 112.236000 101.760000 112.320000 101.784000 ;
  END
 END n_li_d[531]
 PIN n_li_d[532]
  DIRECTION INPUT ;
  USE SIGNAL ;
  PORT
   LAYER M4 ;
   RECT 112.236000 101.952000 112.320000 101.976000 ;
  END
 END n_li_d[532]
 PIN n_li_d[533]
  DIRECTION INPUT ;
  USE SIGNAL ;
  PORT
   LAYER M4 ;
   RECT 112.236000 102.144000 112.320000 102.168000 ;
  END
 END n_li_d[533]
 PIN n_li_d[534]
  DIRECTION INPUT ;
  USE SIGNAL ;
  PORT
   LAYER M4 ;
   RECT 112.236000 102.288000 112.320000 102.312000 ;
  END
 END n_li_d[534]
 PIN n_li_d[535]
  DIRECTION INPUT ;
  USE SIGNAL ;
  PORT
   LAYER M4 ;
   RECT 112.236000 102.480000 112.320000 102.504000 ;
  END
 END n_li_d[535]
 PIN n_li_d[536]
  DIRECTION INPUT ;
  USE SIGNAL ;
  PORT
   LAYER M4 ;
   RECT 112.236000 102.672000 112.320000 102.696000 ;
  END
 END n_li_d[536]
 PIN n_li_d[537]
  DIRECTION INPUT ;
  USE SIGNAL ;
  PORT
   LAYER M4 ;
   RECT 112.236000 102.864000 112.320000 102.888000 ;
  END
 END n_li_d[537]
 PIN n_li_d[538]
  DIRECTION INPUT ;
  USE SIGNAL ;
  PORT
   LAYER M4 ;
   RECT 112.236000 103.008000 112.320000 103.032000 ;
  END
 END n_li_d[538]
 PIN n_li_d[539]
  DIRECTION INPUT ;
  USE SIGNAL ;
  PORT
   LAYER M4 ;
   RECT 112.236000 103.200000 112.320000 103.224000 ;
  END
 END n_li_d[539]
 PIN n_li_d[540]
  DIRECTION INPUT ;
  USE SIGNAL ;
  PORT
   LAYER M4 ;
   RECT 112.236000 103.392000 112.320000 103.416000 ;
  END
 END n_li_d[540]
 PIN n_li_d[541]
  DIRECTION INPUT ;
  USE SIGNAL ;
  PORT
   LAYER M4 ;
   RECT 112.236000 103.584000 112.320000 103.608000 ;
  END
 END n_li_d[541]
 PIN n_li_d[542]
  DIRECTION INPUT ;
  USE SIGNAL ;
  PORT
   LAYER M4 ;
   RECT 112.236000 103.728000 112.320000 103.752000 ;
  END
 END n_li_d[542]
 PIN n_li_d[543]
  DIRECTION INPUT ;
  USE SIGNAL ;
  PORT
   LAYER M4 ;
   RECT 112.236000 103.920000 112.320000 103.944000 ;
  END
 END n_li_d[543]
 PIN n_li_d[544]
  DIRECTION INPUT ;
  USE SIGNAL ;
  PORT
   LAYER M4 ;
   RECT 112.236000 104.112000 112.320000 104.136000 ;
  END
 END n_li_d[544]
 PIN n_li_d[545]
  DIRECTION INPUT ;
  USE SIGNAL ;
  PORT
   LAYER M4 ;
   RECT 112.236000 104.304000 112.320000 104.328000 ;
  END
 END n_li_d[545]
 PIN n_li_d[546]
  DIRECTION INPUT ;
  USE SIGNAL ;
  PORT
   LAYER M4 ;
   RECT 112.236000 104.448000 112.320000 104.472000 ;
  END
 END n_li_d[546]
 PIN n_li_d[547]
  DIRECTION INPUT ;
  USE SIGNAL ;
  PORT
   LAYER M4 ;
   RECT 112.236000 104.640000 112.320000 104.664000 ;
  END
 END n_li_d[547]
 PIN n_li_d[548]
  DIRECTION INPUT ;
  USE SIGNAL ;
  PORT
   LAYER M4 ;
   RECT 112.236000 104.832000 112.320000 104.856000 ;
  END
 END n_li_d[548]
 PIN n_li_d[549]
  DIRECTION INPUT ;
  USE SIGNAL ;
  PORT
   LAYER M4 ;
   RECT 112.236000 104.976000 112.320000 105.000000 ;
  END
 END n_li_d[549]
 PIN n_li_d[550]
  DIRECTION INPUT ;
  USE SIGNAL ;
  PORT
   LAYER M4 ;
   RECT 112.236000 105.168000 112.320000 105.192000 ;
  END
 END n_li_d[550]
 PIN n_li_d[551]
  DIRECTION INPUT ;
  USE SIGNAL ;
  PORT
   LAYER M4 ;
   RECT 112.236000 105.360000 112.320000 105.384000 ;
  END
 END n_li_d[551]
 PIN n_li_d[552]
  DIRECTION INPUT ;
  USE SIGNAL ;
  PORT
   LAYER M4 ;
   RECT 112.236000 105.552000 112.320000 105.576000 ;
  END
 END n_li_d[552]
 PIN n_flt[0]
  DIRECTION INPUT ;
  USE SIGNAL ;
  PORT
   LAYER M4 ;
   RECT 112.236000 105.696000 112.320000 105.720000 ;
  END
 END n_flt[0]
 PIN n_flt[1]
  DIRECTION INPUT ;
  USE SIGNAL ;
  PORT
   LAYER M4 ;
   RECT 112.236000 105.888000 112.320000 105.912000 ;
  END
 END n_flt[1]
 PIN n_flt[2]
  DIRECTION INPUT ;
  USE SIGNAL ;
  PORT
   LAYER M4 ;
   RECT 112.236000 106.080000 112.320000 106.104000 ;
  END
 END n_flt[2]
 PIN n_lo_v
  DIRECTION OUTPUT ;
  USE SIGNAL ;
  PORT
   LAYER M5 ;
   RECT 6.192000 112.236000 6.216000 112.320000 ;
  END
 END n_lo_v
 PIN n_lo_d[0]
  DIRECTION OUTPUT ;
  USE SIGNAL ;
  PORT
   LAYER M5 ;
   RECT 6.768000 112.236000 6.792000 112.320000 ;
  END
 END n_lo_d[0]
 PIN n_lo_d[1]
  DIRECTION OUTPUT ;
  USE SIGNAL ;
  PORT
   LAYER M5 ;
   RECT 6.816000 112.236000 6.840000 112.320000 ;
  END
 END n_lo_d[1]
 PIN n_lo_d[2]
  DIRECTION OUTPUT ;
  USE SIGNAL ;
  PORT
   LAYER M5 ;
   RECT 6.864000 112.236000 6.888000 112.320000 ;
  END
 END n_lo_d[2]
 PIN n_lo_d[3]
  DIRECTION OUTPUT ;
  USE SIGNAL ;
  PORT
   LAYER M5 ;
   RECT 6.960000 112.236000 6.984000 112.320000 ;
  END
 END n_lo_d[3]
 PIN n_lo_d[4]
  DIRECTION OUTPUT ;
  USE SIGNAL ;
  PORT
   LAYER M5 ;
   RECT 7.104000 112.236000 7.128000 112.320000 ;
  END
 END n_lo_d[4]
 PIN n_lo_d[5]
  DIRECTION OUTPUT ;
  USE SIGNAL ;
  PORT
   LAYER M5 ;
   RECT 7.296000 112.236000 7.320000 112.320000 ;
  END
 END n_lo_d[5]
 PIN n_lo_d[6]
  DIRECTION OUTPUT ;
  USE SIGNAL ;
  PORT
   LAYER M5 ;
   RECT 7.488000 112.236000 7.512000 112.320000 ;
  END
 END n_lo_d[6]
 PIN n_lo_d[7]
  DIRECTION OUTPUT ;
  USE SIGNAL ;
  PORT
   LAYER M5 ;
   RECT 7.680000 112.236000 7.704000 112.320000 ;
  END
 END n_lo_d[7]
 PIN n_lo_d[8]
  DIRECTION OUTPUT ;
  USE SIGNAL ;
  PORT
   LAYER M5 ;
   RECT 7.824000 112.236000 7.848000 112.320000 ;
  END
 END n_lo_d[8]
 PIN n_lo_d[9]
  DIRECTION OUTPUT ;
  USE SIGNAL ;
  PORT
   LAYER M5 ;
   RECT 8.016000 112.236000 8.040000 112.320000 ;
  END
 END n_lo_d[9]
 PIN n_lo_d[10]
  DIRECTION OUTPUT ;
  USE SIGNAL ;
  PORT
   LAYER M5 ;
   RECT 8.208000 112.236000 8.232000 112.320000 ;
  END
 END n_lo_d[10]
 PIN n_lo_d[11]
  DIRECTION OUTPUT ;
  USE SIGNAL ;
  PORT
   LAYER M5 ;
   RECT 8.400000 112.236000 8.424000 112.320000 ;
  END
 END n_lo_d[11]
 PIN n_lo_d[12]
  DIRECTION OUTPUT ;
  USE SIGNAL ;
  PORT
   LAYER M5 ;
   RECT 8.544000 112.236000 8.568000 112.320000 ;
  END
 END n_lo_d[12]
 PIN n_lo_d[13]
  DIRECTION OUTPUT ;
  USE SIGNAL ;
  PORT
   LAYER M5 ;
   RECT 8.736000 112.236000 8.760000 112.320000 ;
  END
 END n_lo_d[13]
 PIN n_lo_d[14]
  DIRECTION OUTPUT ;
  USE SIGNAL ;
  PORT
   LAYER M5 ;
   RECT 8.928000 112.236000 8.952000 112.320000 ;
  END
 END n_lo_d[14]
 PIN n_lo_d[15]
  DIRECTION OUTPUT ;
  USE SIGNAL ;
  PORT
   LAYER M5 ;
   RECT 9.120000 112.236000 9.144000 112.320000 ;
  END
 END n_lo_d[15]
 PIN n_lo_d[16]
  DIRECTION OUTPUT ;
  USE SIGNAL ;
  PORT
   LAYER M5 ;
   RECT 9.264000 112.236000 9.288000 112.320000 ;
  END
 END n_lo_d[16]
 PIN n_lo_d[17]
  DIRECTION OUTPUT ;
  USE SIGNAL ;
  PORT
   LAYER M5 ;
   RECT 9.456000 112.236000 9.480000 112.320000 ;
  END
 END n_lo_d[17]
 PIN n_lo_d[18]
  DIRECTION OUTPUT ;
  USE SIGNAL ;
  PORT
   LAYER M5 ;
   RECT 9.648000 112.236000 9.672000 112.320000 ;
  END
 END n_lo_d[18]
 PIN n_lo_d[19]
  DIRECTION OUTPUT ;
  USE SIGNAL ;
  PORT
   LAYER M5 ;
   RECT 9.840000 112.236000 9.864000 112.320000 ;
  END
 END n_lo_d[19]
 PIN n_lo_d[20]
  DIRECTION OUTPUT ;
  USE SIGNAL ;
  PORT
   LAYER M5 ;
   RECT 9.984000 112.236000 10.008000 112.320000 ;
  END
 END n_lo_d[20]
 PIN n_lo_d[21]
  DIRECTION OUTPUT ;
  USE SIGNAL ;
  PORT
   LAYER M5 ;
   RECT 10.176000 112.236000 10.200000 112.320000 ;
  END
 END n_lo_d[21]
 PIN n_lo_d[22]
  DIRECTION OUTPUT ;
  USE SIGNAL ;
  PORT
   LAYER M5 ;
   RECT 10.368000 112.236000 10.392000 112.320000 ;
  END
 END n_lo_d[22]
 PIN n_lo_d[23]
  DIRECTION OUTPUT ;
  USE SIGNAL ;
  PORT
   LAYER M5 ;
   RECT 10.512000 112.236000 10.536000 112.320000 ;
  END
 END n_lo_d[23]
 PIN n_lo_d[24]
  DIRECTION OUTPUT ;
  USE SIGNAL ;
  PORT
   LAYER M5 ;
   RECT 11.088000 112.236000 11.112000 112.320000 ;
  END
 END n_lo_d[24]
 PIN n_lo_d[25]
  DIRECTION OUTPUT ;
  USE SIGNAL ;
  PORT
   LAYER M5 ;
   RECT 11.136000 112.236000 11.160000 112.320000 ;
  END
 END n_lo_d[25]
 PIN n_lo_d[26]
  DIRECTION OUTPUT ;
  USE SIGNAL ;
  PORT
   LAYER M5 ;
   RECT 11.184000 112.236000 11.208000 112.320000 ;
  END
 END n_lo_d[26]
 PIN n_lo_d[27]
  DIRECTION OUTPUT ;
  USE SIGNAL ;
  PORT
   LAYER M5 ;
   RECT 11.280000 112.236000 11.304000 112.320000 ;
  END
 END n_lo_d[27]
 PIN n_lo_d[28]
  DIRECTION OUTPUT ;
  USE SIGNAL ;
  PORT
   LAYER M5 ;
   RECT 11.424000 112.236000 11.448000 112.320000 ;
  END
 END n_lo_d[28]
 PIN n_lo_d[29]
  DIRECTION OUTPUT ;
  USE SIGNAL ;
  PORT
   LAYER M5 ;
   RECT 11.616000 112.236000 11.640000 112.320000 ;
  END
 END n_lo_d[29]
 PIN n_lo_d[30]
  DIRECTION OUTPUT ;
  USE SIGNAL ;
  PORT
   LAYER M5 ;
   RECT 11.808000 112.236000 11.832000 112.320000 ;
  END
 END n_lo_d[30]
 PIN n_lo_d[31]
  DIRECTION OUTPUT ;
  USE SIGNAL ;
  PORT
   LAYER M5 ;
   RECT 12.000000 112.236000 12.024000 112.320000 ;
  END
 END n_lo_d[31]
 PIN n_lo_d[32]
  DIRECTION OUTPUT ;
  USE SIGNAL ;
  PORT
   LAYER M5 ;
   RECT 12.144000 112.236000 12.168000 112.320000 ;
  END
 END n_lo_d[32]
 PIN n_lo_d[33]
  DIRECTION OUTPUT ;
  USE SIGNAL ;
  PORT
   LAYER M5 ;
   RECT 12.336000 112.236000 12.360000 112.320000 ;
  END
 END n_lo_d[33]
 PIN n_lo_d[34]
  DIRECTION OUTPUT ;
  USE SIGNAL ;
  PORT
   LAYER M5 ;
   RECT 12.528000 112.236000 12.552000 112.320000 ;
  END
 END n_lo_d[34]
 PIN n_lo_d[35]
  DIRECTION OUTPUT ;
  USE SIGNAL ;
  PORT
   LAYER M5 ;
   RECT 12.720000 112.236000 12.744000 112.320000 ;
  END
 END n_lo_d[35]
 PIN n_lo_d[36]
  DIRECTION OUTPUT ;
  USE SIGNAL ;
  PORT
   LAYER M5 ;
   RECT 12.864000 112.236000 12.888000 112.320000 ;
  END
 END n_lo_d[36]
 PIN n_lo_d[37]
  DIRECTION OUTPUT ;
  USE SIGNAL ;
  PORT
   LAYER M5 ;
   RECT 13.056000 112.236000 13.080000 112.320000 ;
  END
 END n_lo_d[37]
 PIN n_lo_d[38]
  DIRECTION OUTPUT ;
  USE SIGNAL ;
  PORT
   LAYER M5 ;
   RECT 13.248000 112.236000 13.272000 112.320000 ;
  END
 END n_lo_d[38]
 PIN n_lo_d[39]
  DIRECTION OUTPUT ;
  USE SIGNAL ;
  PORT
   LAYER M5 ;
   RECT 13.440000 112.236000 13.464000 112.320000 ;
  END
 END n_lo_d[39]
 PIN n_lo_d[40]
  DIRECTION OUTPUT ;
  USE SIGNAL ;
  PORT
   LAYER M5 ;
   RECT 13.584000 112.236000 13.608000 112.320000 ;
  END
 END n_lo_d[40]
 PIN n_lo_d[41]
  DIRECTION OUTPUT ;
  USE SIGNAL ;
  PORT
   LAYER M5 ;
   RECT 13.776000 112.236000 13.800000 112.320000 ;
  END
 END n_lo_d[41]
 PIN n_lo_d[42]
  DIRECTION OUTPUT ;
  USE SIGNAL ;
  PORT
   LAYER M5 ;
   RECT 13.968000 112.236000 13.992000 112.320000 ;
  END
 END n_lo_d[42]
 PIN n_lo_d[43]
  DIRECTION OUTPUT ;
  USE SIGNAL ;
  PORT
   LAYER M5 ;
   RECT 14.160000 112.236000 14.184000 112.320000 ;
  END
 END n_lo_d[43]
 PIN n_lo_d[44]
  DIRECTION OUTPUT ;
  USE SIGNAL ;
  PORT
   LAYER M5 ;
   RECT 14.304000 112.236000 14.328000 112.320000 ;
  END
 END n_lo_d[44]
 PIN n_lo_d[45]
  DIRECTION OUTPUT ;
  USE SIGNAL ;
  PORT
   LAYER M5 ;
   RECT 14.496000 112.236000 14.520000 112.320000 ;
  END
 END n_lo_d[45]
 PIN n_lo_d[46]
  DIRECTION OUTPUT ;
  USE SIGNAL ;
  PORT
   LAYER M5 ;
   RECT 14.688000 112.236000 14.712000 112.320000 ;
  END
 END n_lo_d[46]
 PIN n_lo_d[47]
  DIRECTION OUTPUT ;
  USE SIGNAL ;
  PORT
   LAYER M5 ;
   RECT 14.832000 112.236000 14.856000 112.320000 ;
  END
 END n_lo_d[47]
 PIN n_lo_d[48]
  DIRECTION OUTPUT ;
  USE SIGNAL ;
  PORT
   LAYER M5 ;
   RECT 15.408000 112.236000 15.432000 112.320000 ;
  END
 END n_lo_d[48]
 PIN n_lo_d[49]
  DIRECTION OUTPUT ;
  USE SIGNAL ;
  PORT
   LAYER M5 ;
   RECT 15.456000 112.236000 15.480000 112.320000 ;
  END
 END n_lo_d[49]
 PIN n_lo_d[50]
  DIRECTION OUTPUT ;
  USE SIGNAL ;
  PORT
   LAYER M5 ;
   RECT 15.504000 112.236000 15.528000 112.320000 ;
  END
 END n_lo_d[50]
 PIN n_lo_d[51]
  DIRECTION OUTPUT ;
  USE SIGNAL ;
  PORT
   LAYER M5 ;
   RECT 15.600000 112.236000 15.624000 112.320000 ;
  END
 END n_lo_d[51]
 PIN n_lo_d[52]
  DIRECTION OUTPUT ;
  USE SIGNAL ;
  PORT
   LAYER M5 ;
   RECT 15.744000 112.236000 15.768000 112.320000 ;
  END
 END n_lo_d[52]
 PIN n_lo_d[53]
  DIRECTION OUTPUT ;
  USE SIGNAL ;
  PORT
   LAYER M5 ;
   RECT 15.936000 112.236000 15.960000 112.320000 ;
  END
 END n_lo_d[53]
 PIN n_lo_d[54]
  DIRECTION OUTPUT ;
  USE SIGNAL ;
  PORT
   LAYER M5 ;
   RECT 16.128000 112.236000 16.152000 112.320000 ;
  END
 END n_lo_d[54]
 PIN n_lo_d[55]
  DIRECTION OUTPUT ;
  USE SIGNAL ;
  PORT
   LAYER M5 ;
   RECT 16.320000 112.236000 16.344000 112.320000 ;
  END
 END n_lo_d[55]
 PIN n_lo_d[56]
  DIRECTION OUTPUT ;
  USE SIGNAL ;
  PORT
   LAYER M5 ;
   RECT 16.464000 112.236000 16.488000 112.320000 ;
  END
 END n_lo_d[56]
 PIN n_lo_d[57]
  DIRECTION OUTPUT ;
  USE SIGNAL ;
  PORT
   LAYER M5 ;
   RECT 16.656000 112.236000 16.680000 112.320000 ;
  END
 END n_lo_d[57]
 PIN n_lo_d[58]
  DIRECTION OUTPUT ;
  USE SIGNAL ;
  PORT
   LAYER M5 ;
   RECT 16.848000 112.236000 16.872000 112.320000 ;
  END
 END n_lo_d[58]
 PIN n_lo_d[59]
  DIRECTION OUTPUT ;
  USE SIGNAL ;
  PORT
   LAYER M5 ;
   RECT 17.040000 112.236000 17.064000 112.320000 ;
  END
 END n_lo_d[59]
 PIN n_lo_d[60]
  DIRECTION OUTPUT ;
  USE SIGNAL ;
  PORT
   LAYER M5 ;
   RECT 17.184000 112.236000 17.208000 112.320000 ;
  END
 END n_lo_d[60]
 PIN n_lo_d[61]
  DIRECTION OUTPUT ;
  USE SIGNAL ;
  PORT
   LAYER M5 ;
   RECT 17.376000 112.236000 17.400000 112.320000 ;
  END
 END n_lo_d[61]
 PIN n_lo_d[62]
  DIRECTION OUTPUT ;
  USE SIGNAL ;
  PORT
   LAYER M5 ;
   RECT 17.568000 112.236000 17.592000 112.320000 ;
  END
 END n_lo_d[62]
 PIN n_lo_d[63]
  DIRECTION OUTPUT ;
  USE SIGNAL ;
  PORT
   LAYER M5 ;
   RECT 17.760000 112.236000 17.784000 112.320000 ;
  END
 END n_lo_d[63]
 PIN n_lo_d[64]
  DIRECTION OUTPUT ;
  USE SIGNAL ;
  PORT
   LAYER M5 ;
   RECT 17.904000 112.236000 17.928000 112.320000 ;
  END
 END n_lo_d[64]
 PIN n_lo_d[65]
  DIRECTION OUTPUT ;
  USE SIGNAL ;
  PORT
   LAYER M5 ;
   RECT 18.096000 112.236000 18.120000 112.320000 ;
  END
 END n_lo_d[65]
 PIN n_lo_d[66]
  DIRECTION OUTPUT ;
  USE SIGNAL ;
  PORT
   LAYER M5 ;
   RECT 18.288000 112.236000 18.312000 112.320000 ;
  END
 END n_lo_d[66]
 PIN n_lo_d[67]
  DIRECTION OUTPUT ;
  USE SIGNAL ;
  PORT
   LAYER M5 ;
   RECT 18.480000 112.236000 18.504000 112.320000 ;
  END
 END n_lo_d[67]
 PIN n_lo_d[68]
  DIRECTION OUTPUT ;
  USE SIGNAL ;
  PORT
   LAYER M5 ;
   RECT 18.624000 112.236000 18.648000 112.320000 ;
  END
 END n_lo_d[68]
 PIN n_lo_d[69]
  DIRECTION OUTPUT ;
  USE SIGNAL ;
  PORT
   LAYER M5 ;
   RECT 18.816000 112.236000 18.840000 112.320000 ;
  END
 END n_lo_d[69]
 PIN n_lo_d[70]
  DIRECTION OUTPUT ;
  USE SIGNAL ;
  PORT
   LAYER M5 ;
   RECT 19.008000 112.236000 19.032000 112.320000 ;
  END
 END n_lo_d[70]
 PIN n_lo_d[71]
  DIRECTION OUTPUT ;
  USE SIGNAL ;
  PORT
   LAYER M5 ;
   RECT 19.152000 112.236000 19.176000 112.320000 ;
  END
 END n_lo_d[71]
 PIN n_lo_d[72]
  DIRECTION OUTPUT ;
  USE SIGNAL ;
  PORT
   LAYER M5 ;
   RECT 19.728000 112.236000 19.752000 112.320000 ;
  END
 END n_lo_d[72]
 PIN n_lo_d[73]
  DIRECTION OUTPUT ;
  USE SIGNAL ;
  PORT
   LAYER M5 ;
   RECT 19.776000 112.236000 19.800000 112.320000 ;
  END
 END n_lo_d[73]
 PIN n_lo_d[74]
  DIRECTION OUTPUT ;
  USE SIGNAL ;
  PORT
   LAYER M5 ;
   RECT 19.824000 112.236000 19.848000 112.320000 ;
  END
 END n_lo_d[74]
 PIN n_lo_d[75]
  DIRECTION OUTPUT ;
  USE SIGNAL ;
  PORT
   LAYER M5 ;
   RECT 19.872000 112.236000 19.896000 112.320000 ;
  END
 END n_lo_d[75]
 PIN n_lo_d[76]
  DIRECTION OUTPUT ;
  USE SIGNAL ;
  PORT
   LAYER M5 ;
   RECT 20.064000 112.236000 20.088000 112.320000 ;
  END
 END n_lo_d[76]
 PIN n_lo_d[77]
  DIRECTION OUTPUT ;
  USE SIGNAL ;
  PORT
   LAYER M5 ;
   RECT 20.256000 112.236000 20.280000 112.320000 ;
  END
 END n_lo_d[77]
 PIN n_lo_d[78]
  DIRECTION OUTPUT ;
  USE SIGNAL ;
  PORT
   LAYER M5 ;
   RECT 20.448000 112.236000 20.472000 112.320000 ;
  END
 END n_lo_d[78]
 PIN n_lo_d[79]
  DIRECTION OUTPUT ;
  USE SIGNAL ;
  PORT
   LAYER M5 ;
   RECT 20.592000 112.236000 20.616000 112.320000 ;
  END
 END n_lo_d[79]
 PIN n_lo_d[80]
  DIRECTION OUTPUT ;
  USE SIGNAL ;
  PORT
   LAYER M5 ;
   RECT 20.784000 112.236000 20.808000 112.320000 ;
  END
 END n_lo_d[80]
 PIN n_lo_d[81]
  DIRECTION OUTPUT ;
  USE SIGNAL ;
  PORT
   LAYER M5 ;
   RECT 20.976000 112.236000 21.000000 112.320000 ;
  END
 END n_lo_d[81]
 PIN n_lo_d[82]
  DIRECTION OUTPUT ;
  USE SIGNAL ;
  PORT
   LAYER M5 ;
   RECT 21.168000 112.236000 21.192000 112.320000 ;
  END
 END n_lo_d[82]
 PIN n_lo_d[83]
  DIRECTION OUTPUT ;
  USE SIGNAL ;
  PORT
   LAYER M5 ;
   RECT 21.312000 112.236000 21.336000 112.320000 ;
  END
 END n_lo_d[83]
 PIN n_lo_d[84]
  DIRECTION OUTPUT ;
  USE SIGNAL ;
  PORT
   LAYER M5 ;
   RECT 21.504000 112.236000 21.528000 112.320000 ;
  END
 END n_lo_d[84]
 PIN n_lo_d[85]
  DIRECTION OUTPUT ;
  USE SIGNAL ;
  PORT
   LAYER M5 ;
   RECT 21.696000 112.236000 21.720000 112.320000 ;
  END
 END n_lo_d[85]
 PIN n_lo_d[86]
  DIRECTION OUTPUT ;
  USE SIGNAL ;
  PORT
   LAYER M5 ;
   RECT 21.888000 112.236000 21.912000 112.320000 ;
  END
 END n_lo_d[86]
 PIN n_lo_d[87]
  DIRECTION OUTPUT ;
  USE SIGNAL ;
  PORT
   LAYER M5 ;
   RECT 22.032000 112.236000 22.056000 112.320000 ;
  END
 END n_lo_d[87]
 PIN n_lo_d[88]
  DIRECTION OUTPUT ;
  USE SIGNAL ;
  PORT
   LAYER M5 ;
   RECT 22.224000 112.236000 22.248000 112.320000 ;
  END
 END n_lo_d[88]
 PIN n_lo_d[89]
  DIRECTION OUTPUT ;
  USE SIGNAL ;
  PORT
   LAYER M5 ;
   RECT 22.416000 112.236000 22.440000 112.320000 ;
  END
 END n_lo_d[89]
 PIN n_lo_d[90]
  DIRECTION OUTPUT ;
  USE SIGNAL ;
  PORT
   LAYER M5 ;
   RECT 22.608000 112.236000 22.632000 112.320000 ;
  END
 END n_lo_d[90]
 PIN n_lo_d[91]
  DIRECTION OUTPUT ;
  USE SIGNAL ;
  PORT
   LAYER M5 ;
   RECT 22.752000 112.236000 22.776000 112.320000 ;
  END
 END n_lo_d[91]
 PIN n_lo_d[92]
  DIRECTION OUTPUT ;
  USE SIGNAL ;
  PORT
   LAYER M5 ;
   RECT 22.944000 112.236000 22.968000 112.320000 ;
  END
 END n_lo_d[92]
 PIN n_lo_d[93]
  DIRECTION OUTPUT ;
  USE SIGNAL ;
  PORT
   LAYER M5 ;
   RECT 23.136000 112.236000 23.160000 112.320000 ;
  END
 END n_lo_d[93]
 PIN n_lo_d[94]
  DIRECTION OUTPUT ;
  USE SIGNAL ;
  PORT
   LAYER M5 ;
   RECT 23.328000 112.236000 23.352000 112.320000 ;
  END
 END n_lo_d[94]
 PIN n_lo_d[95]
  DIRECTION OUTPUT ;
  USE SIGNAL ;
  PORT
   LAYER M5 ;
   RECT 23.472000 112.236000 23.496000 112.320000 ;
  END
 END n_lo_d[95]
 PIN n_lo_d[96]
  DIRECTION OUTPUT ;
  USE SIGNAL ;
  PORT
   LAYER M5 ;
   RECT 24.048000 112.236000 24.072000 112.320000 ;
  END
 END n_lo_d[96]
 PIN n_lo_d[97]
  DIRECTION OUTPUT ;
  USE SIGNAL ;
  PORT
   LAYER M5 ;
   RECT 24.096000 112.236000 24.120000 112.320000 ;
  END
 END n_lo_d[97]
 PIN n_lo_d[98]
  DIRECTION OUTPUT ;
  USE SIGNAL ;
  PORT
   LAYER M5 ;
   RECT 24.144000 112.236000 24.168000 112.320000 ;
  END
 END n_lo_d[98]
 PIN n_lo_d[99]
  DIRECTION OUTPUT ;
  USE SIGNAL ;
  PORT
   LAYER M5 ;
   RECT 24.192000 112.236000 24.216000 112.320000 ;
  END
 END n_lo_d[99]
 PIN n_lo_d[100]
  DIRECTION OUTPUT ;
  USE SIGNAL ;
  PORT
   LAYER M5 ;
   RECT 24.384000 112.236000 24.408000 112.320000 ;
  END
 END n_lo_d[100]
 PIN n_lo_d[101]
  DIRECTION OUTPUT ;
  USE SIGNAL ;
  PORT
   LAYER M5 ;
   RECT 24.576000 112.236000 24.600000 112.320000 ;
  END
 END n_lo_d[101]
 PIN n_lo_d[102]
  DIRECTION OUTPUT ;
  USE SIGNAL ;
  PORT
   LAYER M5 ;
   RECT 24.768000 112.236000 24.792000 112.320000 ;
  END
 END n_lo_d[102]
 PIN n_lo_d[103]
  DIRECTION OUTPUT ;
  USE SIGNAL ;
  PORT
   LAYER M5 ;
   RECT 24.912000 112.236000 24.936000 112.320000 ;
  END
 END n_lo_d[103]
 PIN n_lo_d[104]
  DIRECTION OUTPUT ;
  USE SIGNAL ;
  PORT
   LAYER M5 ;
   RECT 25.104000 112.236000 25.128000 112.320000 ;
  END
 END n_lo_d[104]
 PIN n_lo_d[105]
  DIRECTION OUTPUT ;
  USE SIGNAL ;
  PORT
   LAYER M5 ;
   RECT 25.296000 112.236000 25.320000 112.320000 ;
  END
 END n_lo_d[105]
 PIN n_lo_d[106]
  DIRECTION OUTPUT ;
  USE SIGNAL ;
  PORT
   LAYER M5 ;
   RECT 25.488000 112.236000 25.512000 112.320000 ;
  END
 END n_lo_d[106]
 PIN n_lo_d[107]
  DIRECTION OUTPUT ;
  USE SIGNAL ;
  PORT
   LAYER M5 ;
   RECT 25.632000 112.236000 25.656000 112.320000 ;
  END
 END n_lo_d[107]
 PIN n_lo_d[108]
  DIRECTION OUTPUT ;
  USE SIGNAL ;
  PORT
   LAYER M5 ;
   RECT 25.824000 112.236000 25.848000 112.320000 ;
  END
 END n_lo_d[108]
 PIN n_lo_d[109]
  DIRECTION OUTPUT ;
  USE SIGNAL ;
  PORT
   LAYER M5 ;
   RECT 26.016000 112.236000 26.040000 112.320000 ;
  END
 END n_lo_d[109]
 PIN n_lo_d[110]
  DIRECTION OUTPUT ;
  USE SIGNAL ;
  PORT
   LAYER M5 ;
   RECT 26.208000 112.236000 26.232000 112.320000 ;
  END
 END n_lo_d[110]
 PIN n_lo_d[111]
  DIRECTION OUTPUT ;
  USE SIGNAL ;
  PORT
   LAYER M5 ;
   RECT 26.352000 112.236000 26.376000 112.320000 ;
  END
 END n_lo_d[111]
 PIN n_lo_d[112]
  DIRECTION OUTPUT ;
  USE SIGNAL ;
  PORT
   LAYER M5 ;
   RECT 26.544000 112.236000 26.568000 112.320000 ;
  END
 END n_lo_d[112]
 PIN n_lo_d[113]
  DIRECTION OUTPUT ;
  USE SIGNAL ;
  PORT
   LAYER M5 ;
   RECT 26.736000 112.236000 26.760000 112.320000 ;
  END
 END n_lo_d[113]
 PIN n_lo_d[114]
  DIRECTION OUTPUT ;
  USE SIGNAL ;
  PORT
   LAYER M5 ;
   RECT 26.928000 112.236000 26.952000 112.320000 ;
  END
 END n_lo_d[114]
 PIN n_lo_d[115]
  DIRECTION OUTPUT ;
  USE SIGNAL ;
  PORT
   LAYER M5 ;
   RECT 27.072000 112.236000 27.096000 112.320000 ;
  END
 END n_lo_d[115]
 PIN n_lo_d[116]
  DIRECTION OUTPUT ;
  USE SIGNAL ;
  PORT
   LAYER M5 ;
   RECT 27.264000 112.236000 27.288000 112.320000 ;
  END
 END n_lo_d[116]
 PIN n_lo_d[117]
  DIRECTION OUTPUT ;
  USE SIGNAL ;
  PORT
   LAYER M5 ;
   RECT 27.456000 112.236000 27.480000 112.320000 ;
  END
 END n_lo_d[117]
 PIN n_lo_d[118]
  DIRECTION OUTPUT ;
  USE SIGNAL ;
  PORT
   LAYER M5 ;
   RECT 27.648000 112.236000 27.672000 112.320000 ;
  END
 END n_lo_d[118]
 PIN n_lo_d[119]
  DIRECTION OUTPUT ;
  USE SIGNAL ;
  PORT
   LAYER M5 ;
   RECT 27.792000 112.236000 27.816000 112.320000 ;
  END
 END n_lo_d[119]
 PIN n_lo_d[120]
  DIRECTION OUTPUT ;
  USE SIGNAL ;
  PORT
   LAYER M5 ;
   RECT 28.368000 112.236000 28.392000 112.320000 ;
  END
 END n_lo_d[120]
 PIN n_lo_d[121]
  DIRECTION OUTPUT ;
  USE SIGNAL ;
  PORT
   LAYER M5 ;
   RECT 28.416000 112.236000 28.440000 112.320000 ;
  END
 END n_lo_d[121]
 PIN n_lo_d[122]
  DIRECTION OUTPUT ;
  USE SIGNAL ;
  PORT
   LAYER M5 ;
   RECT 28.464000 112.236000 28.488000 112.320000 ;
  END
 END n_lo_d[122]
 PIN n_lo_d[123]
  DIRECTION OUTPUT ;
  USE SIGNAL ;
  PORT
   LAYER M5 ;
   RECT 28.512000 112.236000 28.536000 112.320000 ;
  END
 END n_lo_d[123]
 PIN n_lo_d[124]
  DIRECTION OUTPUT ;
  USE SIGNAL ;
  PORT
   LAYER M5 ;
   RECT 28.704000 112.236000 28.728000 112.320000 ;
  END
 END n_lo_d[124]
 PIN n_lo_d[125]
  DIRECTION OUTPUT ;
  USE SIGNAL ;
  PORT
   LAYER M5 ;
   RECT 28.896000 112.236000 28.920000 112.320000 ;
  END
 END n_lo_d[125]
 PIN n_lo_d[126]
  DIRECTION OUTPUT ;
  USE SIGNAL ;
  PORT
   LAYER M5 ;
   RECT 29.088000 112.236000 29.112000 112.320000 ;
  END
 END n_lo_d[126]
 PIN n_lo_d[127]
  DIRECTION OUTPUT ;
  USE SIGNAL ;
  PORT
   LAYER M5 ;
   RECT 29.232000 112.236000 29.256000 112.320000 ;
  END
 END n_lo_d[127]
 PIN n_lo_d[128]
  DIRECTION OUTPUT ;
  USE SIGNAL ;
  PORT
   LAYER M5 ;
   RECT 29.424000 112.236000 29.448000 112.320000 ;
  END
 END n_lo_d[128]
 PIN n_lo_d[129]
  DIRECTION OUTPUT ;
  USE SIGNAL ;
  PORT
   LAYER M5 ;
   RECT 29.616000 112.236000 29.640000 112.320000 ;
  END
 END n_lo_d[129]
 PIN n_lo_d[130]
  DIRECTION OUTPUT ;
  USE SIGNAL ;
  PORT
   LAYER M5 ;
   RECT 29.808000 112.236000 29.832000 112.320000 ;
  END
 END n_lo_d[130]
 PIN n_lo_d[131]
  DIRECTION OUTPUT ;
  USE SIGNAL ;
  PORT
   LAYER M5 ;
   RECT 29.952000 112.236000 29.976000 112.320000 ;
  END
 END n_lo_d[131]
 PIN n_lo_d[132]
  DIRECTION OUTPUT ;
  USE SIGNAL ;
  PORT
   LAYER M5 ;
   RECT 30.144000 112.236000 30.168000 112.320000 ;
  END
 END n_lo_d[132]
 PIN n_lo_d[133]
  DIRECTION OUTPUT ;
  USE SIGNAL ;
  PORT
   LAYER M5 ;
   RECT 30.336000 112.236000 30.360000 112.320000 ;
  END
 END n_lo_d[133]
 PIN n_lo_d[134]
  DIRECTION OUTPUT ;
  USE SIGNAL ;
  PORT
   LAYER M5 ;
   RECT 30.528000 112.236000 30.552000 112.320000 ;
  END
 END n_lo_d[134]
 PIN n_lo_d[135]
  DIRECTION OUTPUT ;
  USE SIGNAL ;
  PORT
   LAYER M5 ;
   RECT 30.672000 112.236000 30.696000 112.320000 ;
  END
 END n_lo_d[135]
 PIN n_lo_d[136]
  DIRECTION OUTPUT ;
  USE SIGNAL ;
  PORT
   LAYER M5 ;
   RECT 30.864000 112.236000 30.888000 112.320000 ;
  END
 END n_lo_d[136]
 PIN n_lo_d[137]
  DIRECTION OUTPUT ;
  USE SIGNAL ;
  PORT
   LAYER M5 ;
   RECT 31.056000 112.236000 31.080000 112.320000 ;
  END
 END n_lo_d[137]
 PIN n_lo_d[138]
  DIRECTION OUTPUT ;
  USE SIGNAL ;
  PORT
   LAYER M5 ;
   RECT 31.248000 112.236000 31.272000 112.320000 ;
  END
 END n_lo_d[138]
 PIN n_lo_d[139]
  DIRECTION OUTPUT ;
  USE SIGNAL ;
  PORT
   LAYER M5 ;
   RECT 31.392000 112.236000 31.416000 112.320000 ;
  END
 END n_lo_d[139]
 PIN n_lo_d[140]
  DIRECTION OUTPUT ;
  USE SIGNAL ;
  PORT
   LAYER M5 ;
   RECT 31.584000 112.236000 31.608000 112.320000 ;
  END
 END n_lo_d[140]
 PIN n_lo_d[141]
  DIRECTION OUTPUT ;
  USE SIGNAL ;
  PORT
   LAYER M5 ;
   RECT 31.776000 112.236000 31.800000 112.320000 ;
  END
 END n_lo_d[141]
 PIN n_lo_d[142]
  DIRECTION OUTPUT ;
  USE SIGNAL ;
  PORT
   LAYER M5 ;
   RECT 31.968000 112.236000 31.992000 112.320000 ;
  END
 END n_lo_d[142]
 PIN n_lo_d[143]
  DIRECTION OUTPUT ;
  USE SIGNAL ;
  PORT
   LAYER M5 ;
   RECT 32.112000 112.236000 32.136000 112.320000 ;
  END
 END n_lo_d[143]
 PIN n_lo_d[144]
  DIRECTION OUTPUT ;
  USE SIGNAL ;
  PORT
   LAYER M5 ;
   RECT 32.688000 112.236000 32.712000 112.320000 ;
  END
 END n_lo_d[144]
 PIN n_lo_d[145]
  DIRECTION OUTPUT ;
  USE SIGNAL ;
  PORT
   LAYER M5 ;
   RECT 32.736000 112.236000 32.760000 112.320000 ;
  END
 END n_lo_d[145]
 PIN n_lo_d[146]
  DIRECTION OUTPUT ;
  USE SIGNAL ;
  PORT
   LAYER M5 ;
   RECT 32.784000 112.236000 32.808000 112.320000 ;
  END
 END n_lo_d[146]
 PIN n_lo_d[147]
  DIRECTION OUTPUT ;
  USE SIGNAL ;
  PORT
   LAYER M5 ;
   RECT 32.832000 112.236000 32.856000 112.320000 ;
  END
 END n_lo_d[147]
 PIN n_lo_d[148]
  DIRECTION OUTPUT ;
  USE SIGNAL ;
  PORT
   LAYER M5 ;
   RECT 33.024000 112.236000 33.048000 112.320000 ;
  END
 END n_lo_d[148]
 PIN n_lo_d[149]
  DIRECTION OUTPUT ;
  USE SIGNAL ;
  PORT
   LAYER M5 ;
   RECT 33.216000 112.236000 33.240000 112.320000 ;
  END
 END n_lo_d[149]
 PIN n_lo_d[150]
  DIRECTION OUTPUT ;
  USE SIGNAL ;
  PORT
   LAYER M5 ;
   RECT 33.408000 112.236000 33.432000 112.320000 ;
  END
 END n_lo_d[150]
 PIN n_lo_d[151]
  DIRECTION OUTPUT ;
  USE SIGNAL ;
  PORT
   LAYER M5 ;
   RECT 33.552000 112.236000 33.576000 112.320000 ;
  END
 END n_lo_d[151]
 PIN n_lo_d[152]
  DIRECTION OUTPUT ;
  USE SIGNAL ;
  PORT
   LAYER M5 ;
   RECT 33.744000 112.236000 33.768000 112.320000 ;
  END
 END n_lo_d[152]
 PIN n_lo_d[153]
  DIRECTION OUTPUT ;
  USE SIGNAL ;
  PORT
   LAYER M5 ;
   RECT 33.936000 112.236000 33.960000 112.320000 ;
  END
 END n_lo_d[153]
 PIN n_lo_d[154]
  DIRECTION OUTPUT ;
  USE SIGNAL ;
  PORT
   LAYER M5 ;
   RECT 34.128000 112.236000 34.152000 112.320000 ;
  END
 END n_lo_d[154]
 PIN n_lo_d[155]
  DIRECTION OUTPUT ;
  USE SIGNAL ;
  PORT
   LAYER M5 ;
   RECT 34.272000 112.236000 34.296000 112.320000 ;
  END
 END n_lo_d[155]
 PIN n_lo_d[156]
  DIRECTION OUTPUT ;
  USE SIGNAL ;
  PORT
   LAYER M5 ;
   RECT 34.464000 112.236000 34.488000 112.320000 ;
  END
 END n_lo_d[156]
 PIN n_lo_d[157]
  DIRECTION OUTPUT ;
  USE SIGNAL ;
  PORT
   LAYER M5 ;
   RECT 34.656000 112.236000 34.680000 112.320000 ;
  END
 END n_lo_d[157]
 PIN n_lo_d[158]
  DIRECTION OUTPUT ;
  USE SIGNAL ;
  PORT
   LAYER M5 ;
   RECT 34.848000 112.236000 34.872000 112.320000 ;
  END
 END n_lo_d[158]
 PIN n_lo_d[159]
  DIRECTION OUTPUT ;
  USE SIGNAL ;
  PORT
   LAYER M5 ;
   RECT 34.992000 112.236000 35.016000 112.320000 ;
  END
 END n_lo_d[159]
 PIN n_lo_d[160]
  DIRECTION OUTPUT ;
  USE SIGNAL ;
  PORT
   LAYER M5 ;
   RECT 35.184000 112.236000 35.208000 112.320000 ;
  END
 END n_lo_d[160]
 PIN n_lo_d[161]
  DIRECTION OUTPUT ;
  USE SIGNAL ;
  PORT
   LAYER M5 ;
   RECT 35.376000 112.236000 35.400000 112.320000 ;
  END
 END n_lo_d[161]
 PIN n_lo_d[162]
  DIRECTION OUTPUT ;
  USE SIGNAL ;
  PORT
   LAYER M5 ;
   RECT 35.568000 112.236000 35.592000 112.320000 ;
  END
 END n_lo_d[162]
 PIN n_lo_d[163]
  DIRECTION OUTPUT ;
  USE SIGNAL ;
  PORT
   LAYER M5 ;
   RECT 35.712000 112.236000 35.736000 112.320000 ;
  END
 END n_lo_d[163]
 PIN n_lo_d[164]
  DIRECTION OUTPUT ;
  USE SIGNAL ;
  PORT
   LAYER M5 ;
   RECT 35.904000 112.236000 35.928000 112.320000 ;
  END
 END n_lo_d[164]
 PIN n_lo_d[165]
  DIRECTION OUTPUT ;
  USE SIGNAL ;
  PORT
   LAYER M5 ;
   RECT 36.096000 112.236000 36.120000 112.320000 ;
  END
 END n_lo_d[165]
 PIN n_lo_d[166]
  DIRECTION OUTPUT ;
  USE SIGNAL ;
  PORT
   LAYER M5 ;
   RECT 36.288000 112.236000 36.312000 112.320000 ;
  END
 END n_lo_d[166]
 PIN n_lo_d[167]
  DIRECTION OUTPUT ;
  USE SIGNAL ;
  PORT
   LAYER M5 ;
   RECT 36.432000 112.236000 36.456000 112.320000 ;
  END
 END n_lo_d[167]
 PIN n_lo_d[168]
  DIRECTION OUTPUT ;
  USE SIGNAL ;
  PORT
   LAYER M5 ;
   RECT 37.008000 112.236000 37.032000 112.320000 ;
  END
 END n_lo_d[168]
 PIN n_lo_d[169]
  DIRECTION OUTPUT ;
  USE SIGNAL ;
  PORT
   LAYER M5 ;
   RECT 37.056000 112.236000 37.080000 112.320000 ;
  END
 END n_lo_d[169]
 PIN n_lo_d[170]
  DIRECTION OUTPUT ;
  USE SIGNAL ;
  PORT
   LAYER M5 ;
   RECT 37.104000 112.236000 37.128000 112.320000 ;
  END
 END n_lo_d[170]
 PIN n_lo_d[171]
  DIRECTION OUTPUT ;
  USE SIGNAL ;
  PORT
   LAYER M5 ;
   RECT 37.152000 112.236000 37.176000 112.320000 ;
  END
 END n_lo_d[171]
 PIN n_lo_d[172]
  DIRECTION OUTPUT ;
  USE SIGNAL ;
  PORT
   LAYER M5 ;
   RECT 37.344000 112.236000 37.368000 112.320000 ;
  END
 END n_lo_d[172]
 PIN n_lo_d[173]
  DIRECTION OUTPUT ;
  USE SIGNAL ;
  PORT
   LAYER M5 ;
   RECT 37.536000 112.236000 37.560000 112.320000 ;
  END
 END n_lo_d[173]
 PIN n_lo_d[174]
  DIRECTION OUTPUT ;
  USE SIGNAL ;
  PORT
   LAYER M5 ;
   RECT 37.728000 112.236000 37.752000 112.320000 ;
  END
 END n_lo_d[174]
 PIN n_lo_d[175]
  DIRECTION OUTPUT ;
  USE SIGNAL ;
  PORT
   LAYER M5 ;
   RECT 37.872000 112.236000 37.896000 112.320000 ;
  END
 END n_lo_d[175]
 PIN n_lo_d[176]
  DIRECTION OUTPUT ;
  USE SIGNAL ;
  PORT
   LAYER M5 ;
   RECT 38.064000 112.236000 38.088000 112.320000 ;
  END
 END n_lo_d[176]
 PIN n_lo_d[177]
  DIRECTION OUTPUT ;
  USE SIGNAL ;
  PORT
   LAYER M5 ;
   RECT 38.256000 112.236000 38.280000 112.320000 ;
  END
 END n_lo_d[177]
 PIN n_lo_d[178]
  DIRECTION OUTPUT ;
  USE SIGNAL ;
  PORT
   LAYER M5 ;
   RECT 38.448000 112.236000 38.472000 112.320000 ;
  END
 END n_lo_d[178]
 PIN n_lo_d[179]
  DIRECTION OUTPUT ;
  USE SIGNAL ;
  PORT
   LAYER M5 ;
   RECT 38.592000 112.236000 38.616000 112.320000 ;
  END
 END n_lo_d[179]
 PIN n_lo_d[180]
  DIRECTION OUTPUT ;
  USE SIGNAL ;
  PORT
   LAYER M5 ;
   RECT 38.784000 112.236000 38.808000 112.320000 ;
  END
 END n_lo_d[180]
 PIN n_lo_d[181]
  DIRECTION OUTPUT ;
  USE SIGNAL ;
  PORT
   LAYER M5 ;
   RECT 38.976000 112.236000 39.000000 112.320000 ;
  END
 END n_lo_d[181]
 PIN n_lo_d[182]
  DIRECTION OUTPUT ;
  USE SIGNAL ;
  PORT
   LAYER M5 ;
   RECT 39.168000 112.236000 39.192000 112.320000 ;
  END
 END n_lo_d[182]
 PIN n_lo_d[183]
  DIRECTION OUTPUT ;
  USE SIGNAL ;
  PORT
   LAYER M5 ;
   RECT 39.312000 112.236000 39.336000 112.320000 ;
  END
 END n_lo_d[183]
 PIN n_lo_d[184]
  DIRECTION OUTPUT ;
  USE SIGNAL ;
  PORT
   LAYER M5 ;
   RECT 39.504000 112.236000 39.528000 112.320000 ;
  END
 END n_lo_d[184]
 PIN n_lo_d[185]
  DIRECTION OUTPUT ;
  USE SIGNAL ;
  PORT
   LAYER M5 ;
   RECT 39.696000 112.236000 39.720000 112.320000 ;
  END
 END n_lo_d[185]
 PIN n_lo_d[186]
  DIRECTION OUTPUT ;
  USE SIGNAL ;
  PORT
   LAYER M5 ;
   RECT 39.888000 112.236000 39.912000 112.320000 ;
  END
 END n_lo_d[186]
 PIN n_lo_d[187]
  DIRECTION OUTPUT ;
  USE SIGNAL ;
  PORT
   LAYER M5 ;
   RECT 40.032000 112.236000 40.056000 112.320000 ;
  END
 END n_lo_d[187]
 PIN n_lo_d[188]
  DIRECTION OUTPUT ;
  USE SIGNAL ;
  PORT
   LAYER M5 ;
   RECT 40.224000 112.236000 40.248000 112.320000 ;
  END
 END n_lo_d[188]
 PIN n_lo_d[189]
  DIRECTION OUTPUT ;
  USE SIGNAL ;
  PORT
   LAYER M5 ;
   RECT 40.416000 112.236000 40.440000 112.320000 ;
  END
 END n_lo_d[189]
 PIN n_lo_d[190]
  DIRECTION OUTPUT ;
  USE SIGNAL ;
  PORT
   LAYER M5 ;
   RECT 40.608000 112.236000 40.632000 112.320000 ;
  END
 END n_lo_d[190]
 PIN n_lo_d[191]
  DIRECTION OUTPUT ;
  USE SIGNAL ;
  PORT
   LAYER M5 ;
   RECT 40.752000 112.236000 40.776000 112.320000 ;
  END
 END n_lo_d[191]
 PIN n_lo_d[192]
  DIRECTION OUTPUT ;
  USE SIGNAL ;
  PORT
   LAYER M5 ;
   RECT 41.328000 112.236000 41.352000 112.320000 ;
  END
 END n_lo_d[192]
 PIN n_lo_d[193]
  DIRECTION OUTPUT ;
  USE SIGNAL ;
  PORT
   LAYER M5 ;
   RECT 41.376000 112.236000 41.400000 112.320000 ;
  END
 END n_lo_d[193]
 PIN n_lo_d[194]
  DIRECTION OUTPUT ;
  USE SIGNAL ;
  PORT
   LAYER M5 ;
   RECT 41.424000 112.236000 41.448000 112.320000 ;
  END
 END n_lo_d[194]
 PIN n_lo_d[195]
  DIRECTION OUTPUT ;
  USE SIGNAL ;
  PORT
   LAYER M5 ;
   RECT 41.472000 112.236000 41.496000 112.320000 ;
  END
 END n_lo_d[195]
 PIN n_lo_d[196]
  DIRECTION OUTPUT ;
  USE SIGNAL ;
  PORT
   LAYER M5 ;
   RECT 41.664000 112.236000 41.688000 112.320000 ;
  END
 END n_lo_d[196]
 PIN n_lo_d[197]
  DIRECTION OUTPUT ;
  USE SIGNAL ;
  PORT
   LAYER M5 ;
   RECT 41.856000 112.236000 41.880000 112.320000 ;
  END
 END n_lo_d[197]
 PIN n_lo_d[198]
  DIRECTION OUTPUT ;
  USE SIGNAL ;
  PORT
   LAYER M5 ;
   RECT 42.048000 112.236000 42.072000 112.320000 ;
  END
 END n_lo_d[198]
 PIN n_lo_d[199]
  DIRECTION OUTPUT ;
  USE SIGNAL ;
  PORT
   LAYER M5 ;
   RECT 42.192000 112.236000 42.216000 112.320000 ;
  END
 END n_lo_d[199]
 PIN n_lo_d[200]
  DIRECTION OUTPUT ;
  USE SIGNAL ;
  PORT
   LAYER M5 ;
   RECT 42.384000 112.236000 42.408000 112.320000 ;
  END
 END n_lo_d[200]
 PIN n_lo_d[201]
  DIRECTION OUTPUT ;
  USE SIGNAL ;
  PORT
   LAYER M5 ;
   RECT 42.576000 112.236000 42.600000 112.320000 ;
  END
 END n_lo_d[201]
 PIN n_lo_d[202]
  DIRECTION OUTPUT ;
  USE SIGNAL ;
  PORT
   LAYER M5 ;
   RECT 42.768000 112.236000 42.792000 112.320000 ;
  END
 END n_lo_d[202]
 PIN n_lo_d[203]
  DIRECTION OUTPUT ;
  USE SIGNAL ;
  PORT
   LAYER M5 ;
   RECT 42.912000 112.236000 42.936000 112.320000 ;
  END
 END n_lo_d[203]
 PIN n_lo_d[204]
  DIRECTION OUTPUT ;
  USE SIGNAL ;
  PORT
   LAYER M5 ;
   RECT 43.104000 112.236000 43.128000 112.320000 ;
  END
 END n_lo_d[204]
 PIN n_lo_d[205]
  DIRECTION OUTPUT ;
  USE SIGNAL ;
  PORT
   LAYER M5 ;
   RECT 43.296000 112.236000 43.320000 112.320000 ;
  END
 END n_lo_d[205]
 PIN n_lo_d[206]
  DIRECTION OUTPUT ;
  USE SIGNAL ;
  PORT
   LAYER M5 ;
   RECT 43.488000 112.236000 43.512000 112.320000 ;
  END
 END n_lo_d[206]
 PIN n_lo_d[207]
  DIRECTION OUTPUT ;
  USE SIGNAL ;
  PORT
   LAYER M5 ;
   RECT 43.632000 112.236000 43.656000 112.320000 ;
  END
 END n_lo_d[207]
 PIN n_lo_d[208]
  DIRECTION OUTPUT ;
  USE SIGNAL ;
  PORT
   LAYER M5 ;
   RECT 43.824000 112.236000 43.848000 112.320000 ;
  END
 END n_lo_d[208]
 PIN n_lo_d[209]
  DIRECTION OUTPUT ;
  USE SIGNAL ;
  PORT
   LAYER M5 ;
   RECT 44.016000 112.236000 44.040000 112.320000 ;
  END
 END n_lo_d[209]
 PIN n_lo_d[210]
  DIRECTION OUTPUT ;
  USE SIGNAL ;
  PORT
   LAYER M5 ;
   RECT 44.160000 112.236000 44.184000 112.320000 ;
  END
 END n_lo_d[210]
 PIN n_lo_d[211]
  DIRECTION OUTPUT ;
  USE SIGNAL ;
  PORT
   LAYER M5 ;
   RECT 44.352000 112.236000 44.376000 112.320000 ;
  END
 END n_lo_d[211]
 PIN n_lo_d[212]
  DIRECTION OUTPUT ;
  USE SIGNAL ;
  PORT
   LAYER M5 ;
   RECT 44.544000 112.236000 44.568000 112.320000 ;
  END
 END n_lo_d[212]
 PIN n_lo_d[213]
  DIRECTION OUTPUT ;
  USE SIGNAL ;
  PORT
   LAYER M5 ;
   RECT 44.736000 112.236000 44.760000 112.320000 ;
  END
 END n_lo_d[213]
 PIN n_lo_d[214]
  DIRECTION OUTPUT ;
  USE SIGNAL ;
  PORT
   LAYER M5 ;
   RECT 44.880000 112.236000 44.904000 112.320000 ;
  END
 END n_lo_d[214]
 PIN n_lo_d[215]
  DIRECTION OUTPUT ;
  USE SIGNAL ;
  PORT
   LAYER M5 ;
   RECT 45.072000 112.236000 45.096000 112.320000 ;
  END
 END n_lo_d[215]
 PIN n_lo_d[216]
  DIRECTION OUTPUT ;
  USE SIGNAL ;
  PORT
   LAYER M5 ;
   RECT 45.648000 112.236000 45.672000 112.320000 ;
  END
 END n_lo_d[216]
 PIN n_lo_d[217]
  DIRECTION OUTPUT ;
  USE SIGNAL ;
  PORT
   LAYER M5 ;
   RECT 45.696000 112.236000 45.720000 112.320000 ;
  END
 END n_lo_d[217]
 PIN n_lo_d[218]
  DIRECTION OUTPUT ;
  USE SIGNAL ;
  PORT
   LAYER M5 ;
   RECT 45.744000 112.236000 45.768000 112.320000 ;
  END
 END n_lo_d[218]
 PIN n_lo_d[219]
  DIRECTION OUTPUT ;
  USE SIGNAL ;
  PORT
   LAYER M5 ;
   RECT 45.792000 112.236000 45.816000 112.320000 ;
  END
 END n_lo_d[219]
 PIN n_lo_d[220]
  DIRECTION OUTPUT ;
  USE SIGNAL ;
  PORT
   LAYER M5 ;
   RECT 45.984000 112.236000 46.008000 112.320000 ;
  END
 END n_lo_d[220]
 PIN n_lo_d[221]
  DIRECTION OUTPUT ;
  USE SIGNAL ;
  PORT
   LAYER M5 ;
   RECT 46.176000 112.236000 46.200000 112.320000 ;
  END
 END n_lo_d[221]
 PIN n_lo_d[222]
  DIRECTION OUTPUT ;
  USE SIGNAL ;
  PORT
   LAYER M5 ;
   RECT 46.320000 112.236000 46.344000 112.320000 ;
  END
 END n_lo_d[222]
 PIN n_lo_d[223]
  DIRECTION OUTPUT ;
  USE SIGNAL ;
  PORT
   LAYER M5 ;
   RECT 46.512000 112.236000 46.536000 112.320000 ;
  END
 END n_lo_d[223]
 PIN n_lo_d[224]
  DIRECTION OUTPUT ;
  USE SIGNAL ;
  PORT
   LAYER M5 ;
   RECT 46.704000 112.236000 46.728000 112.320000 ;
  END
 END n_lo_d[224]
 PIN n_lo_d[225]
  DIRECTION OUTPUT ;
  USE SIGNAL ;
  PORT
   LAYER M5 ;
   RECT 46.896000 112.236000 46.920000 112.320000 ;
  END
 END n_lo_d[225]
 PIN n_lo_d[226]
  DIRECTION OUTPUT ;
  USE SIGNAL ;
  PORT
   LAYER M5 ;
   RECT 47.040000 112.236000 47.064000 112.320000 ;
  END
 END n_lo_d[226]
 PIN n_lo_d[227]
  DIRECTION OUTPUT ;
  USE SIGNAL ;
  PORT
   LAYER M5 ;
   RECT 47.232000 112.236000 47.256000 112.320000 ;
  END
 END n_lo_d[227]
 PIN n_lo_d[228]
  DIRECTION OUTPUT ;
  USE SIGNAL ;
  PORT
   LAYER M5 ;
   RECT 47.424000 112.236000 47.448000 112.320000 ;
  END
 END n_lo_d[228]
 PIN n_lo_d[229]
  DIRECTION OUTPUT ;
  USE SIGNAL ;
  PORT
   LAYER M5 ;
   RECT 47.616000 112.236000 47.640000 112.320000 ;
  END
 END n_lo_d[229]
 PIN n_lo_d[230]
  DIRECTION OUTPUT ;
  USE SIGNAL ;
  PORT
   LAYER M5 ;
   RECT 47.760000 112.236000 47.784000 112.320000 ;
  END
 END n_lo_d[230]
 PIN n_lo_d[231]
  DIRECTION OUTPUT ;
  USE SIGNAL ;
  PORT
   LAYER M5 ;
   RECT 47.952000 112.236000 47.976000 112.320000 ;
  END
 END n_lo_d[231]
 PIN n_lo_d[232]
  DIRECTION OUTPUT ;
  USE SIGNAL ;
  PORT
   LAYER M5 ;
   RECT 48.144000 112.236000 48.168000 112.320000 ;
  END
 END n_lo_d[232]
 PIN n_lo_d[233]
  DIRECTION OUTPUT ;
  USE SIGNAL ;
  PORT
   LAYER M5 ;
   RECT 48.336000 112.236000 48.360000 112.320000 ;
  END
 END n_lo_d[233]
 PIN n_lo_d[234]
  DIRECTION OUTPUT ;
  USE SIGNAL ;
  PORT
   LAYER M5 ;
   RECT 48.480000 112.236000 48.504000 112.320000 ;
  END
 END n_lo_d[234]
 PIN n_lo_d[235]
  DIRECTION OUTPUT ;
  USE SIGNAL ;
  PORT
   LAYER M5 ;
   RECT 48.672000 112.236000 48.696000 112.320000 ;
  END
 END n_lo_d[235]
 PIN n_lo_d[236]
  DIRECTION OUTPUT ;
  USE SIGNAL ;
  PORT
   LAYER M5 ;
   RECT 48.864000 112.236000 48.888000 112.320000 ;
  END
 END n_lo_d[236]
 PIN n_lo_d[237]
  DIRECTION OUTPUT ;
  USE SIGNAL ;
  PORT
   LAYER M5 ;
   RECT 49.056000 112.236000 49.080000 112.320000 ;
  END
 END n_lo_d[237]
 PIN n_lo_d[238]
  DIRECTION OUTPUT ;
  USE SIGNAL ;
  PORT
   LAYER M5 ;
   RECT 49.200000 112.236000 49.224000 112.320000 ;
  END
 END n_lo_d[238]
 PIN n_lo_d[239]
  DIRECTION OUTPUT ;
  USE SIGNAL ;
  PORT
   LAYER M5 ;
   RECT 49.392000 112.236000 49.416000 112.320000 ;
  END
 END n_lo_d[239]
 PIN n_lo_d[240]
  DIRECTION OUTPUT ;
  USE SIGNAL ;
  PORT
   LAYER M5 ;
   RECT 49.968000 112.236000 49.992000 112.320000 ;
  END
 END n_lo_d[240]
 PIN n_lo_d[241]
  DIRECTION OUTPUT ;
  USE SIGNAL ;
  PORT
   LAYER M5 ;
   RECT 50.016000 112.236000 50.040000 112.320000 ;
  END
 END n_lo_d[241]
 PIN n_lo_d[242]
  DIRECTION OUTPUT ;
  USE SIGNAL ;
  PORT
   LAYER M5 ;
   RECT 50.064000 112.236000 50.088000 112.320000 ;
  END
 END n_lo_d[242]
 PIN n_lo_d[243]
  DIRECTION OUTPUT ;
  USE SIGNAL ;
  PORT
   LAYER M5 ;
   RECT 50.112000 112.236000 50.136000 112.320000 ;
  END
 END n_lo_d[243]
 PIN n_lo_d[244]
  DIRECTION OUTPUT ;
  USE SIGNAL ;
  PORT
   LAYER M5 ;
   RECT 50.304000 112.236000 50.328000 112.320000 ;
  END
 END n_lo_d[244]
 PIN n_lo_d[245]
  DIRECTION OUTPUT ;
  USE SIGNAL ;
  PORT
   LAYER M5 ;
   RECT 50.496000 112.236000 50.520000 112.320000 ;
  END
 END n_lo_d[245]
 PIN n_lo_d[246]
  DIRECTION OUTPUT ;
  USE SIGNAL ;
  PORT
   LAYER M5 ;
   RECT 50.640000 112.236000 50.664000 112.320000 ;
  END
 END n_lo_d[246]
 PIN n_lo_d[247]
  DIRECTION OUTPUT ;
  USE SIGNAL ;
  PORT
   LAYER M5 ;
   RECT 50.832000 112.236000 50.856000 112.320000 ;
  END
 END n_lo_d[247]
 PIN n_lo_d[248]
  DIRECTION OUTPUT ;
  USE SIGNAL ;
  PORT
   LAYER M5 ;
   RECT 51.024000 112.236000 51.048000 112.320000 ;
  END
 END n_lo_d[248]
 PIN n_lo_d[249]
  DIRECTION OUTPUT ;
  USE SIGNAL ;
  PORT
   LAYER M5 ;
   RECT 51.216000 112.236000 51.240000 112.320000 ;
  END
 END n_lo_d[249]
 PIN n_lo_d[250]
  DIRECTION OUTPUT ;
  USE SIGNAL ;
  PORT
   LAYER M5 ;
   RECT 51.360000 112.236000 51.384000 112.320000 ;
  END
 END n_lo_d[250]
 PIN n_lo_d[251]
  DIRECTION OUTPUT ;
  USE SIGNAL ;
  PORT
   LAYER M5 ;
   RECT 51.552000 112.236000 51.576000 112.320000 ;
  END
 END n_lo_d[251]
 PIN n_lo_d[252]
  DIRECTION OUTPUT ;
  USE SIGNAL ;
  PORT
   LAYER M5 ;
   RECT 51.744000 112.236000 51.768000 112.320000 ;
  END
 END n_lo_d[252]
 PIN n_lo_d[253]
  DIRECTION OUTPUT ;
  USE SIGNAL ;
  PORT
   LAYER M5 ;
   RECT 51.936000 112.236000 51.960000 112.320000 ;
  END
 END n_lo_d[253]
 PIN n_lo_d[254]
  DIRECTION OUTPUT ;
  USE SIGNAL ;
  PORT
   LAYER M5 ;
   RECT 52.080000 112.236000 52.104000 112.320000 ;
  END
 END n_lo_d[254]
 PIN n_lo_d[255]
  DIRECTION OUTPUT ;
  USE SIGNAL ;
  PORT
   LAYER M5 ;
   RECT 52.272000 112.236000 52.296000 112.320000 ;
  END
 END n_lo_d[255]
 PIN n_lo_d[256]
  DIRECTION OUTPUT ;
  USE SIGNAL ;
  PORT
   LAYER M5 ;
   RECT 52.464000 112.236000 52.488000 112.320000 ;
  END
 END n_lo_d[256]
 PIN n_lo_d[257]
  DIRECTION OUTPUT ;
  USE SIGNAL ;
  PORT
   LAYER M5 ;
   RECT 52.656000 112.236000 52.680000 112.320000 ;
  END
 END n_lo_d[257]
 PIN n_lo_d[258]
  DIRECTION OUTPUT ;
  USE SIGNAL ;
  PORT
   LAYER M5 ;
   RECT 52.800000 112.236000 52.824000 112.320000 ;
  END
 END n_lo_d[258]
 PIN n_lo_d[259]
  DIRECTION OUTPUT ;
  USE SIGNAL ;
  PORT
   LAYER M5 ;
   RECT 52.992000 112.236000 53.016000 112.320000 ;
  END
 END n_lo_d[259]
 PIN n_lo_d[260]
  DIRECTION OUTPUT ;
  USE SIGNAL ;
  PORT
   LAYER M5 ;
   RECT 53.184000 112.236000 53.208000 112.320000 ;
  END
 END n_lo_d[260]
 PIN n_lo_d[261]
  DIRECTION OUTPUT ;
  USE SIGNAL ;
  PORT
   LAYER M5 ;
   RECT 53.376000 112.236000 53.400000 112.320000 ;
  END
 END n_lo_d[261]
 PIN n_lo_d[262]
  DIRECTION OUTPUT ;
  USE SIGNAL ;
  PORT
   LAYER M5 ;
   RECT 53.520000 112.236000 53.544000 112.320000 ;
  END
 END n_lo_d[262]
 PIN n_lo_d[263]
  DIRECTION OUTPUT ;
  USE SIGNAL ;
  PORT
   LAYER M5 ;
   RECT 53.712000 112.236000 53.736000 112.320000 ;
  END
 END n_lo_d[263]
 PIN n_lo_d[264]
  DIRECTION OUTPUT ;
  USE SIGNAL ;
  PORT
   LAYER M5 ;
   RECT 54.288000 112.236000 54.312000 112.320000 ;
  END
 END n_lo_d[264]
 PIN n_lo_d[265]
  DIRECTION OUTPUT ;
  USE SIGNAL ;
  PORT
   LAYER M5 ;
   RECT 54.336000 112.236000 54.360000 112.320000 ;
  END
 END n_lo_d[265]
 PIN n_lo_d[266]
  DIRECTION OUTPUT ;
  USE SIGNAL ;
  PORT
   LAYER M5 ;
   RECT 54.384000 112.236000 54.408000 112.320000 ;
  END
 END n_lo_d[266]
 PIN n_lo_d[267]
  DIRECTION OUTPUT ;
  USE SIGNAL ;
  PORT
   LAYER M5 ;
   RECT 54.432000 112.236000 54.456000 112.320000 ;
  END
 END n_lo_d[267]
 PIN n_lo_d[268]
  DIRECTION OUTPUT ;
  USE SIGNAL ;
  PORT
   LAYER M5 ;
   RECT 54.624000 112.236000 54.648000 112.320000 ;
  END
 END n_lo_d[268]
 PIN n_lo_d[269]
  DIRECTION OUTPUT ;
  USE SIGNAL ;
  PORT
   LAYER M5 ;
   RECT 54.816000 112.236000 54.840000 112.320000 ;
  END
 END n_lo_d[269]
 PIN n_lo_d[270]
  DIRECTION OUTPUT ;
  USE SIGNAL ;
  PORT
   LAYER M5 ;
   RECT 54.960000 112.236000 54.984000 112.320000 ;
  END
 END n_lo_d[270]
 PIN n_lo_d[271]
  DIRECTION OUTPUT ;
  USE SIGNAL ;
  PORT
   LAYER M5 ;
   RECT 55.152000 112.236000 55.176000 112.320000 ;
  END
 END n_lo_d[271]
 PIN n_lo_d[272]
  DIRECTION OUTPUT ;
  USE SIGNAL ;
  PORT
   LAYER M5 ;
   RECT 55.344000 112.236000 55.368000 112.320000 ;
  END
 END n_lo_d[272]
 PIN n_lo_d[273]
  DIRECTION OUTPUT ;
  USE SIGNAL ;
  PORT
   LAYER M5 ;
   RECT 55.536000 112.236000 55.560000 112.320000 ;
  END
 END n_lo_d[273]
 PIN n_lo_d[274]
  DIRECTION OUTPUT ;
  USE SIGNAL ;
  PORT
   LAYER M5 ;
   RECT 55.680000 112.236000 55.704000 112.320000 ;
  END
 END n_lo_d[274]
 PIN n_lo_d[275]
  DIRECTION OUTPUT ;
  USE SIGNAL ;
  PORT
   LAYER M5 ;
   RECT 55.872000 112.236000 55.896000 112.320000 ;
  END
 END n_lo_d[275]
 PIN n_lo_d[276]
  DIRECTION OUTPUT ;
  USE SIGNAL ;
  PORT
   LAYER M5 ;
   RECT 56.064000 112.236000 56.088000 112.320000 ;
  END
 END n_lo_d[276]
 PIN n_lo_d[277]
  DIRECTION OUTPUT ;
  USE SIGNAL ;
  PORT
   LAYER M5 ;
   RECT 56.256000 112.236000 56.280000 112.320000 ;
  END
 END n_lo_d[277]
 PIN n_lo_d[278]
  DIRECTION OUTPUT ;
  USE SIGNAL ;
  PORT
   LAYER M5 ;
   RECT 56.400000 112.236000 56.424000 112.320000 ;
  END
 END n_lo_d[278]
 PIN n_lo_d[279]
  DIRECTION OUTPUT ;
  USE SIGNAL ;
  PORT
   LAYER M5 ;
   RECT 56.592000 112.236000 56.616000 112.320000 ;
  END
 END n_lo_d[279]
 PIN n_lo_d[280]
  DIRECTION OUTPUT ;
  USE SIGNAL ;
  PORT
   LAYER M5 ;
   RECT 56.784000 112.236000 56.808000 112.320000 ;
  END
 END n_lo_d[280]
 PIN n_lo_d[281]
  DIRECTION OUTPUT ;
  USE SIGNAL ;
  PORT
   LAYER M5 ;
   RECT 56.976000 112.236000 57.000000 112.320000 ;
  END
 END n_lo_d[281]
 PIN n_lo_d[282]
  DIRECTION OUTPUT ;
  USE SIGNAL ;
  PORT
   LAYER M5 ;
   RECT 57.120000 112.236000 57.144000 112.320000 ;
  END
 END n_lo_d[282]
 PIN n_lo_d[283]
  DIRECTION OUTPUT ;
  USE SIGNAL ;
  PORT
   LAYER M5 ;
   RECT 57.312000 112.236000 57.336000 112.320000 ;
  END
 END n_lo_d[283]
 PIN n_lo_d[284]
  DIRECTION OUTPUT ;
  USE SIGNAL ;
  PORT
   LAYER M5 ;
   RECT 57.504000 112.236000 57.528000 112.320000 ;
  END
 END n_lo_d[284]
 PIN n_lo_d[285]
  DIRECTION OUTPUT ;
  USE SIGNAL ;
  PORT
   LAYER M5 ;
   RECT 57.696000 112.236000 57.720000 112.320000 ;
  END
 END n_lo_d[285]
 PIN n_lo_d[286]
  DIRECTION OUTPUT ;
  USE SIGNAL ;
  PORT
   LAYER M5 ;
   RECT 57.840000 112.236000 57.864000 112.320000 ;
  END
 END n_lo_d[286]
 PIN n_lo_d[287]
  DIRECTION OUTPUT ;
  USE SIGNAL ;
  PORT
   LAYER M5 ;
   RECT 57.936000 112.236000 57.960000 112.320000 ;
  END
 END n_lo_d[287]
 PIN n_lo_d[288]
  DIRECTION OUTPUT ;
  USE SIGNAL ;
  PORT
   LAYER M5 ;
   RECT 57.984000 112.236000 58.008000 112.320000 ;
  END
 END n_lo_d[288]
 PIN n_lo_d[289]
  DIRECTION OUTPUT ;
  USE SIGNAL ;
  PORT
   LAYER M5 ;
   RECT 58.032000 112.236000 58.056000 112.320000 ;
  END
 END n_lo_d[289]
 PIN n_lo_d[290]
  DIRECTION OUTPUT ;
  USE SIGNAL ;
  PORT
   LAYER M5 ;
   RECT 58.608000 112.236000 58.632000 112.320000 ;
  END
 END n_lo_d[290]
 PIN n_lo_d[291]
  DIRECTION OUTPUT ;
  USE SIGNAL ;
  PORT
   LAYER M5 ;
   RECT 58.752000 112.236000 58.776000 112.320000 ;
  END
 END n_lo_d[291]
 PIN n_lo_d[292]
  DIRECTION OUTPUT ;
  USE SIGNAL ;
  PORT
   LAYER M5 ;
   RECT 58.944000 112.236000 58.968000 112.320000 ;
  END
 END n_lo_d[292]
 PIN n_lo_d[293]
  DIRECTION OUTPUT ;
  USE SIGNAL ;
  PORT
   LAYER M5 ;
   RECT 59.136000 112.236000 59.160000 112.320000 ;
  END
 END n_lo_d[293]
 PIN n_lo_d[294]
  DIRECTION OUTPUT ;
  USE SIGNAL ;
  PORT
   LAYER M5 ;
   RECT 59.280000 112.236000 59.304000 112.320000 ;
  END
 END n_lo_d[294]
 PIN n_lo_d[295]
  DIRECTION OUTPUT ;
  USE SIGNAL ;
  PORT
   LAYER M5 ;
   RECT 59.472000 112.236000 59.496000 112.320000 ;
  END
 END n_lo_d[295]
 PIN n_lo_d[296]
  DIRECTION OUTPUT ;
  USE SIGNAL ;
  PORT
   LAYER M5 ;
   RECT 59.664000 112.236000 59.688000 112.320000 ;
  END
 END n_lo_d[296]
 PIN n_lo_d[297]
  DIRECTION OUTPUT ;
  USE SIGNAL ;
  PORT
   LAYER M5 ;
   RECT 59.856000 112.236000 59.880000 112.320000 ;
  END
 END n_lo_d[297]
 PIN n_lo_d[298]
  DIRECTION OUTPUT ;
  USE SIGNAL ;
  PORT
   LAYER M5 ;
   RECT 60.000000 112.236000 60.024000 112.320000 ;
  END
 END n_lo_d[298]
 PIN n_lo_d[299]
  DIRECTION OUTPUT ;
  USE SIGNAL ;
  PORT
   LAYER M5 ;
   RECT 60.192000 112.236000 60.216000 112.320000 ;
  END
 END n_lo_d[299]
 PIN n_lo_d[300]
  DIRECTION OUTPUT ;
  USE SIGNAL ;
  PORT
   LAYER M5 ;
   RECT 60.384000 112.236000 60.408000 112.320000 ;
  END
 END n_lo_d[300]
 PIN n_lo_d[301]
  DIRECTION OUTPUT ;
  USE SIGNAL ;
  PORT
   LAYER M5 ;
   RECT 60.576000 112.236000 60.600000 112.320000 ;
  END
 END n_lo_d[301]
 PIN n_lo_d[302]
  DIRECTION OUTPUT ;
  USE SIGNAL ;
  PORT
   LAYER M5 ;
   RECT 60.720000 112.236000 60.744000 112.320000 ;
  END
 END n_lo_d[302]
 PIN n_lo_d[303]
  DIRECTION OUTPUT ;
  USE SIGNAL ;
  PORT
   LAYER M5 ;
   RECT 60.912000 112.236000 60.936000 112.320000 ;
  END
 END n_lo_d[303]
 PIN n_lo_d[304]
  DIRECTION OUTPUT ;
  USE SIGNAL ;
  PORT
   LAYER M5 ;
   RECT 61.104000 112.236000 61.128000 112.320000 ;
  END
 END n_lo_d[304]
 PIN n_lo_d[305]
  DIRECTION OUTPUT ;
  USE SIGNAL ;
  PORT
   LAYER M5 ;
   RECT 61.296000 112.236000 61.320000 112.320000 ;
  END
 END n_lo_d[305]
 PIN n_lo_d[306]
  DIRECTION OUTPUT ;
  USE SIGNAL ;
  PORT
   LAYER M5 ;
   RECT 61.440000 112.236000 61.464000 112.320000 ;
  END
 END n_lo_d[306]
 PIN n_lo_d[307]
  DIRECTION OUTPUT ;
  USE SIGNAL ;
  PORT
   LAYER M5 ;
   RECT 61.632000 112.236000 61.656000 112.320000 ;
  END
 END n_lo_d[307]
 PIN n_lo_d[308]
  DIRECTION OUTPUT ;
  USE SIGNAL ;
  PORT
   LAYER M5 ;
   RECT 61.824000 112.236000 61.848000 112.320000 ;
  END
 END n_lo_d[308]
 PIN n_lo_d[309]
  DIRECTION OUTPUT ;
  USE SIGNAL ;
  PORT
   LAYER M5 ;
   RECT 62.016000 112.236000 62.040000 112.320000 ;
  END
 END n_lo_d[309]
 PIN n_lo_d[310]
  DIRECTION OUTPUT ;
  USE SIGNAL ;
  PORT
   LAYER M5 ;
   RECT 62.160000 112.236000 62.184000 112.320000 ;
  END
 END n_lo_d[310]
 PIN n_lo_d[311]
  DIRECTION OUTPUT ;
  USE SIGNAL ;
  PORT
   LAYER M5 ;
   RECT 62.256000 112.236000 62.280000 112.320000 ;
  END
 END n_lo_d[311]
 PIN n_lo_d[312]
  DIRECTION OUTPUT ;
  USE SIGNAL ;
  PORT
   LAYER M5 ;
   RECT 62.304000 112.236000 62.328000 112.320000 ;
  END
 END n_lo_d[312]
 PIN n_lo_d[313]
  DIRECTION OUTPUT ;
  USE SIGNAL ;
  PORT
   LAYER M5 ;
   RECT 62.352000 112.236000 62.376000 112.320000 ;
  END
 END n_lo_d[313]
 PIN n_lo_d[314]
  DIRECTION OUTPUT ;
  USE SIGNAL ;
  PORT
   LAYER M5 ;
   RECT 62.928000 112.236000 62.952000 112.320000 ;
  END
 END n_lo_d[314]
 PIN n_lo_d[315]
  DIRECTION OUTPUT ;
  USE SIGNAL ;
  PORT
   LAYER M5 ;
   RECT 63.072000 112.236000 63.096000 112.320000 ;
  END
 END n_lo_d[315]
 PIN n_lo_d[316]
  DIRECTION OUTPUT ;
  USE SIGNAL ;
  PORT
   LAYER M5 ;
   RECT 63.264000 112.236000 63.288000 112.320000 ;
  END
 END n_lo_d[316]
 PIN n_lo_d[317]
  DIRECTION OUTPUT ;
  USE SIGNAL ;
  PORT
   LAYER M5 ;
   RECT 63.456000 112.236000 63.480000 112.320000 ;
  END
 END n_lo_d[317]
 PIN n_lo_d[318]
  DIRECTION OUTPUT ;
  USE SIGNAL ;
  PORT
   LAYER M5 ;
   RECT 63.600000 112.236000 63.624000 112.320000 ;
  END
 END n_lo_d[318]
 PIN n_lo_d[319]
  DIRECTION OUTPUT ;
  USE SIGNAL ;
  PORT
   LAYER M5 ;
   RECT 63.792000 112.236000 63.816000 112.320000 ;
  END
 END n_lo_d[319]
 PIN n_lo_d[320]
  DIRECTION OUTPUT ;
  USE SIGNAL ;
  PORT
   LAYER M5 ;
   RECT 63.984000 112.236000 64.008000 112.320000 ;
  END
 END n_lo_d[320]
 PIN n_lo_d[321]
  DIRECTION OUTPUT ;
  USE SIGNAL ;
  PORT
   LAYER M5 ;
   RECT 64.176000 112.236000 64.200000 112.320000 ;
  END
 END n_lo_d[321]
 PIN n_lo_d[322]
  DIRECTION OUTPUT ;
  USE SIGNAL ;
  PORT
   LAYER M5 ;
   RECT 64.320000 112.236000 64.344000 112.320000 ;
  END
 END n_lo_d[322]
 PIN n_lo_d[323]
  DIRECTION OUTPUT ;
  USE SIGNAL ;
  PORT
   LAYER M5 ;
   RECT 64.512000 112.236000 64.536000 112.320000 ;
  END
 END n_lo_d[323]
 PIN n_lo_d[324]
  DIRECTION OUTPUT ;
  USE SIGNAL ;
  PORT
   LAYER M5 ;
   RECT 64.704000 112.236000 64.728000 112.320000 ;
  END
 END n_lo_d[324]
 PIN n_lo_d[325]
  DIRECTION OUTPUT ;
  USE SIGNAL ;
  PORT
   LAYER M5 ;
   RECT 64.896000 112.236000 64.920000 112.320000 ;
  END
 END n_lo_d[325]
 PIN n_lo_d[326]
  DIRECTION OUTPUT ;
  USE SIGNAL ;
  PORT
   LAYER M5 ;
   RECT 65.040000 112.236000 65.064000 112.320000 ;
  END
 END n_lo_d[326]
 PIN n_lo_d[327]
  DIRECTION OUTPUT ;
  USE SIGNAL ;
  PORT
   LAYER M5 ;
   RECT 65.232000 112.236000 65.256000 112.320000 ;
  END
 END n_lo_d[327]
 PIN n_lo_d[328]
  DIRECTION OUTPUT ;
  USE SIGNAL ;
  PORT
   LAYER M5 ;
   RECT 65.424000 112.236000 65.448000 112.320000 ;
  END
 END n_lo_d[328]
 PIN n_lo_d[329]
  DIRECTION OUTPUT ;
  USE SIGNAL ;
  PORT
   LAYER M5 ;
   RECT 65.616000 112.236000 65.640000 112.320000 ;
  END
 END n_lo_d[329]
 PIN n_lo_d[330]
  DIRECTION OUTPUT ;
  USE SIGNAL ;
  PORT
   LAYER M5 ;
   RECT 65.760000 112.236000 65.784000 112.320000 ;
  END
 END n_lo_d[330]
 PIN n_lo_d[331]
  DIRECTION OUTPUT ;
  USE SIGNAL ;
  PORT
   LAYER M5 ;
   RECT 65.952000 112.236000 65.976000 112.320000 ;
  END
 END n_lo_d[331]
 PIN n_lo_d[332]
  DIRECTION OUTPUT ;
  USE SIGNAL ;
  PORT
   LAYER M5 ;
   RECT 66.144000 112.236000 66.168000 112.320000 ;
  END
 END n_lo_d[332]
 PIN n_lo_d[333]
  DIRECTION OUTPUT ;
  USE SIGNAL ;
  PORT
   LAYER M5 ;
   RECT 66.336000 112.236000 66.360000 112.320000 ;
  END
 END n_lo_d[333]
 PIN n_lo_d[334]
  DIRECTION OUTPUT ;
  USE SIGNAL ;
  PORT
   LAYER M5 ;
   RECT 66.480000 112.236000 66.504000 112.320000 ;
  END
 END n_lo_d[334]
 PIN n_lo_d[335]
  DIRECTION OUTPUT ;
  USE SIGNAL ;
  PORT
   LAYER M5 ;
   RECT 66.576000 112.236000 66.600000 112.320000 ;
  END
 END n_lo_d[335]
 PIN n_lo_d[336]
  DIRECTION OUTPUT ;
  USE SIGNAL ;
  PORT
   LAYER M5 ;
   RECT 66.624000 112.236000 66.648000 112.320000 ;
  END
 END n_lo_d[336]
 PIN n_lo_d[337]
  DIRECTION OUTPUT ;
  USE SIGNAL ;
  PORT
   LAYER M5 ;
   RECT 66.672000 112.236000 66.696000 112.320000 ;
  END
 END n_lo_d[337]
 PIN n_lo_d[338]
  DIRECTION OUTPUT ;
  USE SIGNAL ;
  PORT
   LAYER M5 ;
   RECT 67.248000 112.236000 67.272000 112.320000 ;
  END
 END n_lo_d[338]
 PIN n_lo_d[339]
  DIRECTION OUTPUT ;
  USE SIGNAL ;
  PORT
   LAYER M5 ;
   RECT 67.392000 112.236000 67.416000 112.320000 ;
  END
 END n_lo_d[339]
 PIN n_lo_d[340]
  DIRECTION OUTPUT ;
  USE SIGNAL ;
  PORT
   LAYER M5 ;
   RECT 67.584000 112.236000 67.608000 112.320000 ;
  END
 END n_lo_d[340]
 PIN n_lo_d[341]
  DIRECTION OUTPUT ;
  USE SIGNAL ;
  PORT
   LAYER M5 ;
   RECT 67.776000 112.236000 67.800000 112.320000 ;
  END
 END n_lo_d[341]
 PIN n_lo_d[342]
  DIRECTION OUTPUT ;
  USE SIGNAL ;
  PORT
   LAYER M5 ;
   RECT 67.920000 112.236000 67.944000 112.320000 ;
  END
 END n_lo_d[342]
 PIN n_lo_d[343]
  DIRECTION OUTPUT ;
  USE SIGNAL ;
  PORT
   LAYER M5 ;
   RECT 68.112000 112.236000 68.136000 112.320000 ;
  END
 END n_lo_d[343]
 PIN n_lo_d[344]
  DIRECTION OUTPUT ;
  USE SIGNAL ;
  PORT
   LAYER M5 ;
   RECT 68.304000 112.236000 68.328000 112.320000 ;
  END
 END n_lo_d[344]
 PIN n_lo_d[345]
  DIRECTION OUTPUT ;
  USE SIGNAL ;
  PORT
   LAYER M5 ;
   RECT 68.496000 112.236000 68.520000 112.320000 ;
  END
 END n_lo_d[345]
 PIN n_lo_d[346]
  DIRECTION OUTPUT ;
  USE SIGNAL ;
  PORT
   LAYER M5 ;
   RECT 68.640000 112.236000 68.664000 112.320000 ;
  END
 END n_lo_d[346]
 PIN n_lo_d[347]
  DIRECTION OUTPUT ;
  USE SIGNAL ;
  PORT
   LAYER M5 ;
   RECT 68.832000 112.236000 68.856000 112.320000 ;
  END
 END n_lo_d[347]
 PIN n_lo_d[348]
  DIRECTION OUTPUT ;
  USE SIGNAL ;
  PORT
   LAYER M5 ;
   RECT 69.024000 112.236000 69.048000 112.320000 ;
  END
 END n_lo_d[348]
 PIN n_lo_d[349]
  DIRECTION OUTPUT ;
  USE SIGNAL ;
  PORT
   LAYER M5 ;
   RECT 69.168000 112.236000 69.192000 112.320000 ;
  END
 END n_lo_d[349]
 PIN n_lo_d[350]
  DIRECTION OUTPUT ;
  USE SIGNAL ;
  PORT
   LAYER M5 ;
   RECT 69.360000 112.236000 69.384000 112.320000 ;
  END
 END n_lo_d[350]
 PIN n_lo_d[351]
  DIRECTION OUTPUT ;
  USE SIGNAL ;
  PORT
   LAYER M5 ;
   RECT 69.552000 112.236000 69.576000 112.320000 ;
  END
 END n_lo_d[351]
 PIN n_lo_d[352]
  DIRECTION OUTPUT ;
  USE SIGNAL ;
  PORT
   LAYER M5 ;
   RECT 69.744000 112.236000 69.768000 112.320000 ;
  END
 END n_lo_d[352]
 PIN n_lo_d[353]
  DIRECTION OUTPUT ;
  USE SIGNAL ;
  PORT
   LAYER M5 ;
   RECT 69.888000 112.236000 69.912000 112.320000 ;
  END
 END n_lo_d[353]
 PIN n_lo_d[354]
  DIRECTION OUTPUT ;
  USE SIGNAL ;
  PORT
   LAYER M5 ;
   RECT 70.080000 112.236000 70.104000 112.320000 ;
  END
 END n_lo_d[354]
 PIN n_lo_d[355]
  DIRECTION OUTPUT ;
  USE SIGNAL ;
  PORT
   LAYER M5 ;
   RECT 70.272000 112.236000 70.296000 112.320000 ;
  END
 END n_lo_d[355]
 PIN n_lo_d[356]
  DIRECTION OUTPUT ;
  USE SIGNAL ;
  PORT
   LAYER M5 ;
   RECT 70.464000 112.236000 70.488000 112.320000 ;
  END
 END n_lo_d[356]
 PIN n_lo_d[357]
  DIRECTION OUTPUT ;
  USE SIGNAL ;
  PORT
   LAYER M5 ;
   RECT 70.608000 112.236000 70.632000 112.320000 ;
  END
 END n_lo_d[357]
 PIN n_lo_d[358]
  DIRECTION OUTPUT ;
  USE SIGNAL ;
  PORT
   LAYER M5 ;
   RECT 70.800000 112.236000 70.824000 112.320000 ;
  END
 END n_lo_d[358]
 PIN n_lo_d[359]
  DIRECTION OUTPUT ;
  USE SIGNAL ;
  PORT
   LAYER M5 ;
   RECT 70.896000 112.236000 70.920000 112.320000 ;
  END
 END n_lo_d[359]
 PIN n_lo_d[360]
  DIRECTION OUTPUT ;
  USE SIGNAL ;
  PORT
   LAYER M5 ;
   RECT 70.944000 112.236000 70.968000 112.320000 ;
  END
 END n_lo_d[360]
 PIN n_lo_d[361]
  DIRECTION OUTPUT ;
  USE SIGNAL ;
  PORT
   LAYER M5 ;
   RECT 70.992000 112.236000 71.016000 112.320000 ;
  END
 END n_lo_d[361]
 PIN n_lo_d[362]
  DIRECTION OUTPUT ;
  USE SIGNAL ;
  PORT
   LAYER M5 ;
   RECT 71.568000 112.236000 71.592000 112.320000 ;
  END
 END n_lo_d[362]
 PIN n_lo_d[363]
  DIRECTION OUTPUT ;
  USE SIGNAL ;
  PORT
   LAYER M5 ;
   RECT 71.712000 112.236000 71.736000 112.320000 ;
  END
 END n_lo_d[363]
 PIN n_lo_d[364]
  DIRECTION OUTPUT ;
  USE SIGNAL ;
  PORT
   LAYER M5 ;
   RECT 71.904000 112.236000 71.928000 112.320000 ;
  END
 END n_lo_d[364]
 PIN n_lo_d[365]
  DIRECTION OUTPUT ;
  USE SIGNAL ;
  PORT
   LAYER M5 ;
   RECT 72.048000 112.236000 72.072000 112.320000 ;
  END
 END n_lo_d[365]
 PIN n_lo_d[366]
  DIRECTION OUTPUT ;
  USE SIGNAL ;
  PORT
   LAYER M5 ;
   RECT 72.240000 112.236000 72.264000 112.320000 ;
  END
 END n_lo_d[366]
 PIN n_lo_d[367]
  DIRECTION OUTPUT ;
  USE SIGNAL ;
  PORT
   LAYER M5 ;
   RECT 72.432000 112.236000 72.456000 112.320000 ;
  END
 END n_lo_d[367]
 PIN n_lo_d[368]
  DIRECTION OUTPUT ;
  USE SIGNAL ;
  PORT
   LAYER M5 ;
   RECT 72.624000 112.236000 72.648000 112.320000 ;
  END
 END n_lo_d[368]
 PIN n_lo_d[369]
  DIRECTION OUTPUT ;
  USE SIGNAL ;
  PORT
   LAYER M5 ;
   RECT 72.768000 112.236000 72.792000 112.320000 ;
  END
 END n_lo_d[369]
 PIN n_lo_d[370]
  DIRECTION OUTPUT ;
  USE SIGNAL ;
  PORT
   LAYER M5 ;
   RECT 72.960000 112.236000 72.984000 112.320000 ;
  END
 END n_lo_d[370]
 PIN n_lo_d[371]
  DIRECTION OUTPUT ;
  USE SIGNAL ;
  PORT
   LAYER M5 ;
   RECT 73.152000 112.236000 73.176000 112.320000 ;
  END
 END n_lo_d[371]
 PIN n_lo_d[372]
  DIRECTION OUTPUT ;
  USE SIGNAL ;
  PORT
   LAYER M5 ;
   RECT 73.344000 112.236000 73.368000 112.320000 ;
  END
 END n_lo_d[372]
 PIN n_lo_d[373]
  DIRECTION OUTPUT ;
  USE SIGNAL ;
  PORT
   LAYER M5 ;
   RECT 73.488000 112.236000 73.512000 112.320000 ;
  END
 END n_lo_d[373]
 PIN n_lo_d[374]
  DIRECTION OUTPUT ;
  USE SIGNAL ;
  PORT
   LAYER M5 ;
   RECT 73.680000 112.236000 73.704000 112.320000 ;
  END
 END n_lo_d[374]
 PIN n_lo_d[375]
  DIRECTION OUTPUT ;
  USE SIGNAL ;
  PORT
   LAYER M5 ;
   RECT 73.872000 112.236000 73.896000 112.320000 ;
  END
 END n_lo_d[375]
 PIN n_lo_d[376]
  DIRECTION OUTPUT ;
  USE SIGNAL ;
  PORT
   LAYER M5 ;
   RECT 74.064000 112.236000 74.088000 112.320000 ;
  END
 END n_lo_d[376]
 PIN n_lo_d[377]
  DIRECTION OUTPUT ;
  USE SIGNAL ;
  PORT
   LAYER M5 ;
   RECT 74.208000 112.236000 74.232000 112.320000 ;
  END
 END n_lo_d[377]
 PIN n_lo_d[378]
  DIRECTION OUTPUT ;
  USE SIGNAL ;
  PORT
   LAYER M5 ;
   RECT 74.400000 112.236000 74.424000 112.320000 ;
  END
 END n_lo_d[378]
 PIN n_lo_d[379]
  DIRECTION OUTPUT ;
  USE SIGNAL ;
  PORT
   LAYER M5 ;
   RECT 74.592000 112.236000 74.616000 112.320000 ;
  END
 END n_lo_d[379]
 PIN n_lo_d[380]
  DIRECTION OUTPUT ;
  USE SIGNAL ;
  PORT
   LAYER M5 ;
   RECT 74.784000 112.236000 74.808000 112.320000 ;
  END
 END n_lo_d[380]
 PIN n_lo_d[381]
  DIRECTION OUTPUT ;
  USE SIGNAL ;
  PORT
   LAYER M5 ;
   RECT 74.928000 112.236000 74.952000 112.320000 ;
  END
 END n_lo_d[381]
 PIN n_lo_d[382]
  DIRECTION OUTPUT ;
  USE SIGNAL ;
  PORT
   LAYER M5 ;
   RECT 75.120000 112.236000 75.144000 112.320000 ;
  END
 END n_lo_d[382]
 PIN n_lo_d[383]
  DIRECTION OUTPUT ;
  USE SIGNAL ;
  PORT
   LAYER M5 ;
   RECT 75.216000 112.236000 75.240000 112.320000 ;
  END
 END n_lo_d[383]
 PIN n_lo_d[384]
  DIRECTION OUTPUT ;
  USE SIGNAL ;
  PORT
   LAYER M5 ;
   RECT 75.264000 112.236000 75.288000 112.320000 ;
  END
 END n_lo_d[384]
 PIN n_lo_d[385]
  DIRECTION OUTPUT ;
  USE SIGNAL ;
  PORT
   LAYER M5 ;
   RECT 75.312000 112.236000 75.336000 112.320000 ;
  END
 END n_lo_d[385]
 PIN n_lo_d[386]
  DIRECTION OUTPUT ;
  USE SIGNAL ;
  PORT
   LAYER M5 ;
   RECT 75.888000 112.236000 75.912000 112.320000 ;
  END
 END n_lo_d[386]
 PIN n_lo_d[387]
  DIRECTION OUTPUT ;
  USE SIGNAL ;
  PORT
   LAYER M5 ;
   RECT 76.032000 112.236000 76.056000 112.320000 ;
  END
 END n_lo_d[387]
 PIN n_lo_d[388]
  DIRECTION OUTPUT ;
  USE SIGNAL ;
  PORT
   LAYER M5 ;
   RECT 76.224000 112.236000 76.248000 112.320000 ;
  END
 END n_lo_d[388]
 PIN n_lo_d[389]
  DIRECTION OUTPUT ;
  USE SIGNAL ;
  PORT
   LAYER M5 ;
   RECT 76.368000 112.236000 76.392000 112.320000 ;
  END
 END n_lo_d[389]
 PIN n_lo_d[390]
  DIRECTION OUTPUT ;
  USE SIGNAL ;
  PORT
   LAYER M5 ;
   RECT 76.560000 112.236000 76.584000 112.320000 ;
  END
 END n_lo_d[390]
 PIN n_lo_d[391]
  DIRECTION OUTPUT ;
  USE SIGNAL ;
  PORT
   LAYER M5 ;
   RECT 76.752000 112.236000 76.776000 112.320000 ;
  END
 END n_lo_d[391]
 PIN n_lo_d[392]
  DIRECTION OUTPUT ;
  USE SIGNAL ;
  PORT
   LAYER M5 ;
   RECT 76.944000 112.236000 76.968000 112.320000 ;
  END
 END n_lo_d[392]
 PIN n_lo_d[393]
  DIRECTION OUTPUT ;
  USE SIGNAL ;
  PORT
   LAYER M5 ;
   RECT 77.088000 112.236000 77.112000 112.320000 ;
  END
 END n_lo_d[393]
 PIN n_lo_d[394]
  DIRECTION OUTPUT ;
  USE SIGNAL ;
  PORT
   LAYER M5 ;
   RECT 77.280000 112.236000 77.304000 112.320000 ;
  END
 END n_lo_d[394]
 PIN n_lo_d[395]
  DIRECTION OUTPUT ;
  USE SIGNAL ;
  PORT
   LAYER M5 ;
   RECT 77.472000 112.236000 77.496000 112.320000 ;
  END
 END n_lo_d[395]
 PIN n_lo_d[396]
  DIRECTION OUTPUT ;
  USE SIGNAL ;
  PORT
   LAYER M5 ;
   RECT 77.664000 112.236000 77.688000 112.320000 ;
  END
 END n_lo_d[396]
 PIN n_lo_d[397]
  DIRECTION OUTPUT ;
  USE SIGNAL ;
  PORT
   LAYER M5 ;
   RECT 77.808000 112.236000 77.832000 112.320000 ;
  END
 END n_lo_d[397]
 PIN n_lo_d[398]
  DIRECTION OUTPUT ;
  USE SIGNAL ;
  PORT
   LAYER M5 ;
   RECT 78.000000 112.236000 78.024000 112.320000 ;
  END
 END n_lo_d[398]
 PIN n_lo_d[399]
  DIRECTION OUTPUT ;
  USE SIGNAL ;
  PORT
   LAYER M5 ;
   RECT 78.192000 112.236000 78.216000 112.320000 ;
  END
 END n_lo_d[399]
 PIN n_lo_d[400]
  DIRECTION OUTPUT ;
  USE SIGNAL ;
  PORT
   LAYER M5 ;
   RECT 78.384000 112.236000 78.408000 112.320000 ;
  END
 END n_lo_d[400]
 PIN n_lo_d[401]
  DIRECTION OUTPUT ;
  USE SIGNAL ;
  PORT
   LAYER M5 ;
   RECT 78.528000 112.236000 78.552000 112.320000 ;
  END
 END n_lo_d[401]
 PIN n_lo_d[402]
  DIRECTION OUTPUT ;
  USE SIGNAL ;
  PORT
   LAYER M5 ;
   RECT 78.720000 112.236000 78.744000 112.320000 ;
  END
 END n_lo_d[402]
 PIN n_lo_d[403]
  DIRECTION OUTPUT ;
  USE SIGNAL ;
  PORT
   LAYER M5 ;
   RECT 78.912000 112.236000 78.936000 112.320000 ;
  END
 END n_lo_d[403]
 PIN n_lo_d[404]
  DIRECTION OUTPUT ;
  USE SIGNAL ;
  PORT
   LAYER M5 ;
   RECT 79.104000 112.236000 79.128000 112.320000 ;
  END
 END n_lo_d[404]
 PIN n_lo_d[405]
  DIRECTION OUTPUT ;
  USE SIGNAL ;
  PORT
   LAYER M5 ;
   RECT 79.248000 112.236000 79.272000 112.320000 ;
  END
 END n_lo_d[405]
 PIN n_lo_d[406]
  DIRECTION OUTPUT ;
  USE SIGNAL ;
  PORT
   LAYER M5 ;
   RECT 79.440000 112.236000 79.464000 112.320000 ;
  END
 END n_lo_d[406]
 PIN n_lo_d[407]
  DIRECTION OUTPUT ;
  USE SIGNAL ;
  PORT
   LAYER M5 ;
   RECT 79.536000 112.236000 79.560000 112.320000 ;
  END
 END n_lo_d[407]
 PIN n_lo_d[408]
  DIRECTION OUTPUT ;
  USE SIGNAL ;
  PORT
   LAYER M5 ;
   RECT 79.584000 112.236000 79.608000 112.320000 ;
  END
 END n_lo_d[408]
 PIN n_lo_d[409]
  DIRECTION OUTPUT ;
  USE SIGNAL ;
  PORT
   LAYER M5 ;
   RECT 79.632000 112.236000 79.656000 112.320000 ;
  END
 END n_lo_d[409]
 PIN n_lo_d[410]
  DIRECTION OUTPUT ;
  USE SIGNAL ;
  PORT
   LAYER M5 ;
   RECT 80.208000 112.236000 80.232000 112.320000 ;
  END
 END n_lo_d[410]
 PIN n_lo_d[411]
  DIRECTION OUTPUT ;
  USE SIGNAL ;
  PORT
   LAYER M5 ;
   RECT 80.352000 112.236000 80.376000 112.320000 ;
  END
 END n_lo_d[411]
 PIN n_lo_d[412]
  DIRECTION OUTPUT ;
  USE SIGNAL ;
  PORT
   LAYER M5 ;
   RECT 80.544000 112.236000 80.568000 112.320000 ;
  END
 END n_lo_d[412]
 PIN n_lo_d[413]
  DIRECTION OUTPUT ;
  USE SIGNAL ;
  PORT
   LAYER M5 ;
   RECT 80.688000 112.236000 80.712000 112.320000 ;
  END
 END n_lo_d[413]
 PIN n_lo_d[414]
  DIRECTION OUTPUT ;
  USE SIGNAL ;
  PORT
   LAYER M5 ;
   RECT 80.880000 112.236000 80.904000 112.320000 ;
  END
 END n_lo_d[414]
 PIN n_lo_d[415]
  DIRECTION OUTPUT ;
  USE SIGNAL ;
  PORT
   LAYER M5 ;
   RECT 81.072000 112.236000 81.096000 112.320000 ;
  END
 END n_lo_d[415]
 PIN n_lo_d[416]
  DIRECTION OUTPUT ;
  USE SIGNAL ;
  PORT
   LAYER M5 ;
   RECT 81.264000 112.236000 81.288000 112.320000 ;
  END
 END n_lo_d[416]
 PIN n_lo_d[417]
  DIRECTION OUTPUT ;
  USE SIGNAL ;
  PORT
   LAYER M5 ;
   RECT 81.408000 112.236000 81.432000 112.320000 ;
  END
 END n_lo_d[417]
 PIN n_lo_d[418]
  DIRECTION OUTPUT ;
  USE SIGNAL ;
  PORT
   LAYER M5 ;
   RECT 81.600000 112.236000 81.624000 112.320000 ;
  END
 END n_lo_d[418]
 PIN n_lo_d[419]
  DIRECTION OUTPUT ;
  USE SIGNAL ;
  PORT
   LAYER M5 ;
   RECT 81.792000 112.236000 81.816000 112.320000 ;
  END
 END n_lo_d[419]
 PIN n_lo_d[420]
  DIRECTION OUTPUT ;
  USE SIGNAL ;
  PORT
   LAYER M5 ;
   RECT 81.984000 112.236000 82.008000 112.320000 ;
  END
 END n_lo_d[420]
 PIN n_lo_d[421]
  DIRECTION OUTPUT ;
  USE SIGNAL ;
  PORT
   LAYER M5 ;
   RECT 82.128000 112.236000 82.152000 112.320000 ;
  END
 END n_lo_d[421]
 PIN n_lo_d[422]
  DIRECTION OUTPUT ;
  USE SIGNAL ;
  PORT
   LAYER M5 ;
   RECT 82.320000 112.236000 82.344000 112.320000 ;
  END
 END n_lo_d[422]
 PIN n_lo_d[423]
  DIRECTION OUTPUT ;
  USE SIGNAL ;
  PORT
   LAYER M5 ;
   RECT 82.512000 112.236000 82.536000 112.320000 ;
  END
 END n_lo_d[423]
 PIN n_lo_d[424]
  DIRECTION OUTPUT ;
  USE SIGNAL ;
  PORT
   LAYER M5 ;
   RECT 82.704000 112.236000 82.728000 112.320000 ;
  END
 END n_lo_d[424]
 PIN n_lo_d[425]
  DIRECTION OUTPUT ;
  USE SIGNAL ;
  PORT
   LAYER M5 ;
   RECT 82.848000 112.236000 82.872000 112.320000 ;
  END
 END n_lo_d[425]
 PIN n_lo_d[426]
  DIRECTION OUTPUT ;
  USE SIGNAL ;
  PORT
   LAYER M5 ;
   RECT 83.040000 112.236000 83.064000 112.320000 ;
  END
 END n_lo_d[426]
 PIN n_lo_d[427]
  DIRECTION OUTPUT ;
  USE SIGNAL ;
  PORT
   LAYER M5 ;
   RECT 83.232000 112.236000 83.256000 112.320000 ;
  END
 END n_lo_d[427]
 PIN n_lo_d[428]
  DIRECTION OUTPUT ;
  USE SIGNAL ;
  PORT
   LAYER M5 ;
   RECT 83.424000 112.236000 83.448000 112.320000 ;
  END
 END n_lo_d[428]
 PIN n_lo_d[429]
  DIRECTION OUTPUT ;
  USE SIGNAL ;
  PORT
   LAYER M5 ;
   RECT 83.568000 112.236000 83.592000 112.320000 ;
  END
 END n_lo_d[429]
 PIN n_lo_d[430]
  DIRECTION OUTPUT ;
  USE SIGNAL ;
  PORT
   LAYER M5 ;
   RECT 83.760000 112.236000 83.784000 112.320000 ;
  END
 END n_lo_d[430]
 PIN n_lo_d[431]
  DIRECTION OUTPUT ;
  USE SIGNAL ;
  PORT
   LAYER M5 ;
   RECT 83.856000 112.236000 83.880000 112.320000 ;
  END
 END n_lo_d[431]
 PIN n_lo_d[432]
  DIRECTION OUTPUT ;
  USE SIGNAL ;
  PORT
   LAYER M5 ;
   RECT 83.904000 112.236000 83.928000 112.320000 ;
  END
 END n_lo_d[432]
 PIN n_lo_d[433]
  DIRECTION OUTPUT ;
  USE SIGNAL ;
  PORT
   LAYER M5 ;
   RECT 83.952000 112.236000 83.976000 112.320000 ;
  END
 END n_lo_d[433]
 PIN n_lo_d[434]
  DIRECTION OUTPUT ;
  USE SIGNAL ;
  PORT
   LAYER M5 ;
   RECT 84.528000 112.236000 84.552000 112.320000 ;
  END
 END n_lo_d[434]
 PIN n_lo_d[435]
  DIRECTION OUTPUT ;
  USE SIGNAL ;
  PORT
   LAYER M5 ;
   RECT 84.672000 112.236000 84.696000 112.320000 ;
  END
 END n_lo_d[435]
 PIN n_lo_d[436]
  DIRECTION OUTPUT ;
  USE SIGNAL ;
  PORT
   LAYER M5 ;
   RECT 84.864000 112.236000 84.888000 112.320000 ;
  END
 END n_lo_d[436]
 PIN n_lo_d[437]
  DIRECTION OUTPUT ;
  USE SIGNAL ;
  PORT
   LAYER M5 ;
   RECT 85.008000 112.236000 85.032000 112.320000 ;
  END
 END n_lo_d[437]
 PIN n_lo_d[438]
  DIRECTION OUTPUT ;
  USE SIGNAL ;
  PORT
   LAYER M5 ;
   RECT 85.200000 112.236000 85.224000 112.320000 ;
  END
 END n_lo_d[438]
 PIN n_lo_d[439]
  DIRECTION OUTPUT ;
  USE SIGNAL ;
  PORT
   LAYER M5 ;
   RECT 85.392000 112.236000 85.416000 112.320000 ;
  END
 END n_lo_d[439]
 PIN n_lo_d[440]
  DIRECTION OUTPUT ;
  USE SIGNAL ;
  PORT
   LAYER M5 ;
   RECT 85.584000 112.236000 85.608000 112.320000 ;
  END
 END n_lo_d[440]
 PIN n_lo_d[441]
  DIRECTION OUTPUT ;
  USE SIGNAL ;
  PORT
   LAYER M5 ;
   RECT 85.728000 112.236000 85.752000 112.320000 ;
  END
 END n_lo_d[441]
 PIN n_lo_d[442]
  DIRECTION OUTPUT ;
  USE SIGNAL ;
  PORT
   LAYER M5 ;
   RECT 85.920000 112.236000 85.944000 112.320000 ;
  END
 END n_lo_d[442]
 PIN n_lo_d[443]
  DIRECTION OUTPUT ;
  USE SIGNAL ;
  PORT
   LAYER M5 ;
   RECT 86.112000 112.236000 86.136000 112.320000 ;
  END
 END n_lo_d[443]
 PIN n_lo_d[444]
  DIRECTION OUTPUT ;
  USE SIGNAL ;
  PORT
   LAYER M5 ;
   RECT 86.304000 112.236000 86.328000 112.320000 ;
  END
 END n_lo_d[444]
 PIN n_lo_d[445]
  DIRECTION OUTPUT ;
  USE SIGNAL ;
  PORT
   LAYER M5 ;
   RECT 86.448000 112.236000 86.472000 112.320000 ;
  END
 END n_lo_d[445]
 PIN n_lo_d[446]
  DIRECTION OUTPUT ;
  USE SIGNAL ;
  PORT
   LAYER M5 ;
   RECT 86.640000 112.236000 86.664000 112.320000 ;
  END
 END n_lo_d[446]
 PIN n_lo_d[447]
  DIRECTION OUTPUT ;
  USE SIGNAL ;
  PORT
   LAYER M5 ;
   RECT 86.832000 112.236000 86.856000 112.320000 ;
  END
 END n_lo_d[447]
 PIN n_lo_d[448]
  DIRECTION OUTPUT ;
  USE SIGNAL ;
  PORT
   LAYER M5 ;
   RECT 87.024000 112.236000 87.048000 112.320000 ;
  END
 END n_lo_d[448]
 PIN n_lo_d[449]
  DIRECTION OUTPUT ;
  USE SIGNAL ;
  PORT
   LAYER M5 ;
   RECT 87.168000 112.236000 87.192000 112.320000 ;
  END
 END n_lo_d[449]
 PIN n_lo_d[450]
  DIRECTION OUTPUT ;
  USE SIGNAL ;
  PORT
   LAYER M5 ;
   RECT 87.360000 112.236000 87.384000 112.320000 ;
  END
 END n_lo_d[450]
 PIN n_lo_d[451]
  DIRECTION OUTPUT ;
  USE SIGNAL ;
  PORT
   LAYER M5 ;
   RECT 87.552000 112.236000 87.576000 112.320000 ;
  END
 END n_lo_d[451]
 PIN n_lo_d[452]
  DIRECTION OUTPUT ;
  USE SIGNAL ;
  PORT
   LAYER M5 ;
   RECT 87.744000 112.236000 87.768000 112.320000 ;
  END
 END n_lo_d[452]
 PIN n_lo_d[453]
  DIRECTION OUTPUT ;
  USE SIGNAL ;
  PORT
   LAYER M5 ;
   RECT 87.888000 112.236000 87.912000 112.320000 ;
  END
 END n_lo_d[453]
 PIN n_lo_d[454]
  DIRECTION OUTPUT ;
  USE SIGNAL ;
  PORT
   LAYER M5 ;
   RECT 88.080000 112.236000 88.104000 112.320000 ;
  END
 END n_lo_d[454]
 PIN n_lo_d[455]
  DIRECTION OUTPUT ;
  USE SIGNAL ;
  PORT
   LAYER M5 ;
   RECT 88.176000 112.236000 88.200000 112.320000 ;
  END
 END n_lo_d[455]
 PIN n_lo_d[456]
  DIRECTION OUTPUT ;
  USE SIGNAL ;
  PORT
   LAYER M5 ;
   RECT 88.224000 112.236000 88.248000 112.320000 ;
  END
 END n_lo_d[456]
 PIN n_lo_d[457]
  DIRECTION OUTPUT ;
  USE SIGNAL ;
  PORT
   LAYER M5 ;
   RECT 88.272000 112.236000 88.296000 112.320000 ;
  END
 END n_lo_d[457]
 PIN n_lo_d[458]
  DIRECTION OUTPUT ;
  USE SIGNAL ;
  PORT
   LAYER M5 ;
   RECT 88.848000 112.236000 88.872000 112.320000 ;
  END
 END n_lo_d[458]
 PIN n_lo_d[459]
  DIRECTION OUTPUT ;
  USE SIGNAL ;
  PORT
   LAYER M5 ;
   RECT 88.992000 112.236000 89.016000 112.320000 ;
  END
 END n_lo_d[459]
 PIN n_lo_d[460]
  DIRECTION OUTPUT ;
  USE SIGNAL ;
  PORT
   LAYER M5 ;
   RECT 89.184000 112.236000 89.208000 112.320000 ;
  END
 END n_lo_d[460]
 PIN n_lo_d[461]
  DIRECTION OUTPUT ;
  USE SIGNAL ;
  PORT
   LAYER M5 ;
   RECT 89.328000 112.236000 89.352000 112.320000 ;
  END
 END n_lo_d[461]
 PIN n_lo_d[462]
  DIRECTION OUTPUT ;
  USE SIGNAL ;
  PORT
   LAYER M5 ;
   RECT 89.520000 112.236000 89.544000 112.320000 ;
  END
 END n_lo_d[462]
 PIN n_lo_d[463]
  DIRECTION OUTPUT ;
  USE SIGNAL ;
  PORT
   LAYER M5 ;
   RECT 89.712000 112.236000 89.736000 112.320000 ;
  END
 END n_lo_d[463]
 PIN n_lo_d[464]
  DIRECTION OUTPUT ;
  USE SIGNAL ;
  PORT
   LAYER M5 ;
   RECT 89.904000 112.236000 89.928000 112.320000 ;
  END
 END n_lo_d[464]
 PIN n_lo_d[465]
  DIRECTION OUTPUT ;
  USE SIGNAL ;
  PORT
   LAYER M5 ;
   RECT 90.048000 112.236000 90.072000 112.320000 ;
  END
 END n_lo_d[465]
 PIN n_lo_d[466]
  DIRECTION OUTPUT ;
  USE SIGNAL ;
  PORT
   LAYER M5 ;
   RECT 90.240000 112.236000 90.264000 112.320000 ;
  END
 END n_lo_d[466]
 PIN n_lo_d[467]
  DIRECTION OUTPUT ;
  USE SIGNAL ;
  PORT
   LAYER M5 ;
   RECT 90.432000 112.236000 90.456000 112.320000 ;
  END
 END n_lo_d[467]
 PIN n_lo_d[468]
  DIRECTION OUTPUT ;
  USE SIGNAL ;
  PORT
   LAYER M5 ;
   RECT 90.624000 112.236000 90.648000 112.320000 ;
  END
 END n_lo_d[468]
 PIN n_lo_d[469]
  DIRECTION OUTPUT ;
  USE SIGNAL ;
  PORT
   LAYER M5 ;
   RECT 90.768000 112.236000 90.792000 112.320000 ;
  END
 END n_lo_d[469]
 PIN n_lo_d[470]
  DIRECTION OUTPUT ;
  USE SIGNAL ;
  PORT
   LAYER M5 ;
   RECT 90.960000 112.236000 90.984000 112.320000 ;
  END
 END n_lo_d[470]
 PIN n_lo_d[471]
  DIRECTION OUTPUT ;
  USE SIGNAL ;
  PORT
   LAYER M5 ;
   RECT 91.152000 112.236000 91.176000 112.320000 ;
  END
 END n_lo_d[471]
 PIN n_lo_d[472]
  DIRECTION OUTPUT ;
  USE SIGNAL ;
  PORT
   LAYER M5 ;
   RECT 91.344000 112.236000 91.368000 112.320000 ;
  END
 END n_lo_d[472]
 PIN n_lo_d[473]
  DIRECTION OUTPUT ;
  USE SIGNAL ;
  PORT
   LAYER M5 ;
   RECT 91.488000 112.236000 91.512000 112.320000 ;
  END
 END n_lo_d[473]
 PIN n_lo_d[474]
  DIRECTION OUTPUT ;
  USE SIGNAL ;
  PORT
   LAYER M5 ;
   RECT 91.680000 112.236000 91.704000 112.320000 ;
  END
 END n_lo_d[474]
 PIN n_lo_d[475]
  DIRECTION OUTPUT ;
  USE SIGNAL ;
  PORT
   LAYER M5 ;
   RECT 91.872000 112.236000 91.896000 112.320000 ;
  END
 END n_lo_d[475]
 PIN n_lo_d[476]
  DIRECTION OUTPUT ;
  USE SIGNAL ;
  PORT
   LAYER M5 ;
   RECT 92.064000 112.236000 92.088000 112.320000 ;
  END
 END n_lo_d[476]
 PIN n_lo_d[477]
  DIRECTION OUTPUT ;
  USE SIGNAL ;
  PORT
   LAYER M5 ;
   RECT 92.208000 112.236000 92.232000 112.320000 ;
  END
 END n_lo_d[477]
 PIN n_lo_d[478]
  DIRECTION OUTPUT ;
  USE SIGNAL ;
  PORT
   LAYER M5 ;
   RECT 92.400000 112.236000 92.424000 112.320000 ;
  END
 END n_lo_d[478]
 PIN n_lo_d[479]
  DIRECTION OUTPUT ;
  USE SIGNAL ;
  PORT
   LAYER M5 ;
   RECT 92.496000 112.236000 92.520000 112.320000 ;
  END
 END n_lo_d[479]
 PIN n_lo_d[480]
  DIRECTION OUTPUT ;
  USE SIGNAL ;
  PORT
   LAYER M5 ;
   RECT 92.544000 112.236000 92.568000 112.320000 ;
  END
 END n_lo_d[480]
 PIN n_lo_d[481]
  DIRECTION OUTPUT ;
  USE SIGNAL ;
  PORT
   LAYER M5 ;
   RECT 92.592000 112.236000 92.616000 112.320000 ;
  END
 END n_lo_d[481]
 PIN n_lo_d[482]
  DIRECTION OUTPUT ;
  USE SIGNAL ;
  PORT
   LAYER M5 ;
   RECT 93.168000 112.236000 93.192000 112.320000 ;
  END
 END n_lo_d[482]
 PIN n_lo_d[483]
  DIRECTION OUTPUT ;
  USE SIGNAL ;
  PORT
   LAYER M5 ;
   RECT 93.312000 112.236000 93.336000 112.320000 ;
  END
 END n_lo_d[483]
 PIN n_lo_d[484]
  DIRECTION OUTPUT ;
  USE SIGNAL ;
  PORT
   LAYER M5 ;
   RECT 93.504000 112.236000 93.528000 112.320000 ;
  END
 END n_lo_d[484]
 PIN n_lo_d[485]
  DIRECTION OUTPUT ;
  USE SIGNAL ;
  PORT
   LAYER M5 ;
   RECT 93.648000 112.236000 93.672000 112.320000 ;
  END
 END n_lo_d[485]
 PIN n_lo_d[486]
  DIRECTION OUTPUT ;
  USE SIGNAL ;
  PORT
   LAYER M5 ;
   RECT 93.840000 112.236000 93.864000 112.320000 ;
  END
 END n_lo_d[486]
 PIN n_lo_d[487]
  DIRECTION OUTPUT ;
  USE SIGNAL ;
  PORT
   LAYER M5 ;
   RECT 94.032000 112.236000 94.056000 112.320000 ;
  END
 END n_lo_d[487]
 PIN n_lo_d[488]
  DIRECTION OUTPUT ;
  USE SIGNAL ;
  PORT
   LAYER M5 ;
   RECT 94.176000 112.236000 94.200000 112.320000 ;
  END
 END n_lo_d[488]
 PIN n_lo_d[489]
  DIRECTION OUTPUT ;
  USE SIGNAL ;
  PORT
   LAYER M5 ;
   RECT 94.368000 112.236000 94.392000 112.320000 ;
  END
 END n_lo_d[489]
 PIN n_lo_d[490]
  DIRECTION OUTPUT ;
  USE SIGNAL ;
  PORT
   LAYER M5 ;
   RECT 94.560000 112.236000 94.584000 112.320000 ;
  END
 END n_lo_d[490]
 PIN n_lo_d[491]
  DIRECTION OUTPUT ;
  USE SIGNAL ;
  PORT
   LAYER M5 ;
   RECT 94.752000 112.236000 94.776000 112.320000 ;
  END
 END n_lo_d[491]
 PIN n_lo_d[492]
  DIRECTION OUTPUT ;
  USE SIGNAL ;
  PORT
   LAYER M5 ;
   RECT 94.896000 112.236000 94.920000 112.320000 ;
  END
 END n_lo_d[492]
 PIN n_lo_d[493]
  DIRECTION OUTPUT ;
  USE SIGNAL ;
  PORT
   LAYER M5 ;
   RECT 95.088000 112.236000 95.112000 112.320000 ;
  END
 END n_lo_d[493]
 PIN n_lo_d[494]
  DIRECTION OUTPUT ;
  USE SIGNAL ;
  PORT
   LAYER M5 ;
   RECT 95.280000 112.236000 95.304000 112.320000 ;
  END
 END n_lo_d[494]
 PIN n_lo_d[495]
  DIRECTION OUTPUT ;
  USE SIGNAL ;
  PORT
   LAYER M5 ;
   RECT 95.472000 112.236000 95.496000 112.320000 ;
  END
 END n_lo_d[495]
 PIN n_lo_d[496]
  DIRECTION OUTPUT ;
  USE SIGNAL ;
  PORT
   LAYER M5 ;
   RECT 95.616000 112.236000 95.640000 112.320000 ;
  END
 END n_lo_d[496]
 PIN n_lo_d[497]
  DIRECTION OUTPUT ;
  USE SIGNAL ;
  PORT
   LAYER M5 ;
   RECT 95.808000 112.236000 95.832000 112.320000 ;
  END
 END n_lo_d[497]
 PIN n_lo_d[498]
  DIRECTION OUTPUT ;
  USE SIGNAL ;
  PORT
   LAYER M5 ;
   RECT 96.000000 112.236000 96.024000 112.320000 ;
  END
 END n_lo_d[498]
 PIN n_lo_d[499]
  DIRECTION OUTPUT ;
  USE SIGNAL ;
  PORT
   LAYER M5 ;
   RECT 96.192000 112.236000 96.216000 112.320000 ;
  END
 END n_lo_d[499]
 PIN n_lo_d[500]
  DIRECTION OUTPUT ;
  USE SIGNAL ;
  PORT
   LAYER M5 ;
   RECT 96.336000 112.236000 96.360000 112.320000 ;
  END
 END n_lo_d[500]
 PIN n_lo_d[501]
  DIRECTION OUTPUT ;
  USE SIGNAL ;
  PORT
   LAYER M5 ;
   RECT 96.528000 112.236000 96.552000 112.320000 ;
  END
 END n_lo_d[501]
 PIN n_lo_d[502]
  DIRECTION OUTPUT ;
  USE SIGNAL ;
  PORT
   LAYER M5 ;
   RECT 96.720000 112.236000 96.744000 112.320000 ;
  END
 END n_lo_d[502]
 PIN n_lo_d[503]
  DIRECTION OUTPUT ;
  USE SIGNAL ;
  PORT
   LAYER M5 ;
   RECT 96.816000 112.236000 96.840000 112.320000 ;
  END
 END n_lo_d[503]
 PIN n_lo_d[504]
  DIRECTION OUTPUT ;
  USE SIGNAL ;
  PORT
   LAYER M5 ;
   RECT 96.864000 112.236000 96.888000 112.320000 ;
  END
 END n_lo_d[504]
 PIN n_lo_d[505]
  DIRECTION OUTPUT ;
  USE SIGNAL ;
  PORT
   LAYER M5 ;
   RECT 96.912000 112.236000 96.936000 112.320000 ;
  END
 END n_lo_d[505]
 PIN n_lo_d[506]
  DIRECTION OUTPUT ;
  USE SIGNAL ;
  PORT
   LAYER M5 ;
   RECT 97.488000 112.236000 97.512000 112.320000 ;
  END
 END n_lo_d[506]
 PIN n_lo_d[507]
  DIRECTION OUTPUT ;
  USE SIGNAL ;
  PORT
   LAYER M5 ;
   RECT 97.632000 112.236000 97.656000 112.320000 ;
  END
 END n_lo_d[507]
 PIN n_lo_d[508]
  DIRECTION OUTPUT ;
  USE SIGNAL ;
  PORT
   LAYER M5 ;
   RECT 97.776000 112.236000 97.800000 112.320000 ;
  END
 END n_lo_d[508]
 PIN n_lo_d[509]
  DIRECTION OUTPUT ;
  USE SIGNAL ;
  PORT
   LAYER M5 ;
   RECT 97.968000 112.236000 97.992000 112.320000 ;
  END
 END n_lo_d[509]
 PIN n_lo_d[510]
  DIRECTION OUTPUT ;
  USE SIGNAL ;
  PORT
   LAYER M5 ;
   RECT 98.160000 112.236000 98.184000 112.320000 ;
  END
 END n_lo_d[510]
 PIN n_lo_d[511]
  DIRECTION OUTPUT ;
  USE SIGNAL ;
  PORT
   LAYER M5 ;
   RECT 98.352000 112.236000 98.376000 112.320000 ;
  END
 END n_lo_d[511]
 PIN n_lo_d[512]
  DIRECTION OUTPUT ;
  USE SIGNAL ;
  PORT
   LAYER M5 ;
   RECT 98.496000 112.236000 98.520000 112.320000 ;
  END
 END n_lo_d[512]
 PIN n_lo_d[513]
  DIRECTION OUTPUT ;
  USE SIGNAL ;
  PORT
   LAYER M5 ;
   RECT 98.688000 112.236000 98.712000 112.320000 ;
  END
 END n_lo_d[513]
 PIN n_lo_d[514]
  DIRECTION OUTPUT ;
  USE SIGNAL ;
  PORT
   LAYER M5 ;
   RECT 98.880000 112.236000 98.904000 112.320000 ;
  END
 END n_lo_d[514]
 PIN n_lo_d[515]
  DIRECTION OUTPUT ;
  USE SIGNAL ;
  PORT
   LAYER M5 ;
   RECT 99.072000 112.236000 99.096000 112.320000 ;
  END
 END n_lo_d[515]
 PIN n_lo_d[516]
  DIRECTION OUTPUT ;
  USE SIGNAL ;
  PORT
   LAYER M5 ;
   RECT 99.216000 112.236000 99.240000 112.320000 ;
  END
 END n_lo_d[516]
 PIN n_lo_d[517]
  DIRECTION OUTPUT ;
  USE SIGNAL ;
  PORT
   LAYER M5 ;
   RECT 99.408000 112.236000 99.432000 112.320000 ;
  END
 END n_lo_d[517]
 PIN n_lo_d[518]
  DIRECTION OUTPUT ;
  USE SIGNAL ;
  PORT
   LAYER M5 ;
   RECT 99.600000 112.236000 99.624000 112.320000 ;
  END
 END n_lo_d[518]
 PIN n_lo_d[519]
  DIRECTION OUTPUT ;
  USE SIGNAL ;
  PORT
   LAYER M5 ;
   RECT 99.792000 112.236000 99.816000 112.320000 ;
  END
 END n_lo_d[519]
 PIN n_lo_d[520]
  DIRECTION OUTPUT ;
  USE SIGNAL ;
  PORT
   LAYER M5 ;
   RECT 99.936000 112.236000 99.960000 112.320000 ;
  END
 END n_lo_d[520]
 PIN n_lo_d[521]
  DIRECTION OUTPUT ;
  USE SIGNAL ;
  PORT
   LAYER M5 ;
   RECT 100.128000 112.236000 100.152000 112.320000 ;
  END
 END n_lo_d[521]
 PIN n_lo_d[522]
  DIRECTION OUTPUT ;
  USE SIGNAL ;
  PORT
   LAYER M5 ;
   RECT 100.320000 112.236000 100.344000 112.320000 ;
  END
 END n_lo_d[522]
 PIN n_lo_d[523]
  DIRECTION OUTPUT ;
  USE SIGNAL ;
  PORT
   LAYER M5 ;
   RECT 100.512000 112.236000 100.536000 112.320000 ;
  END
 END n_lo_d[523]
 PIN n_lo_d[524]
  DIRECTION OUTPUT ;
  USE SIGNAL ;
  PORT
   LAYER M5 ;
   RECT 100.656000 112.236000 100.680000 112.320000 ;
  END
 END n_lo_d[524]
 PIN n_lo_d[525]
  DIRECTION OUTPUT ;
  USE SIGNAL ;
  PORT
   LAYER M5 ;
   RECT 100.848000 112.236000 100.872000 112.320000 ;
  END
 END n_lo_d[525]
 PIN n_lo_d[526]
  DIRECTION OUTPUT ;
  USE SIGNAL ;
  PORT
   LAYER M5 ;
   RECT 101.040000 112.236000 101.064000 112.320000 ;
  END
 END n_lo_d[526]
 PIN n_lo_d[527]
  DIRECTION OUTPUT ;
  USE SIGNAL ;
  PORT
   LAYER M5 ;
   RECT 101.136000 112.236000 101.160000 112.320000 ;
  END
 END n_lo_d[527]
 PIN n_lo_d[528]
  DIRECTION OUTPUT ;
  USE SIGNAL ;
  PORT
   LAYER M5 ;
   RECT 101.184000 112.236000 101.208000 112.320000 ;
  END
 END n_lo_d[528]
 PIN n_lo_d[529]
  DIRECTION OUTPUT ;
  USE SIGNAL ;
  PORT
   LAYER M5 ;
   RECT 101.232000 112.236000 101.256000 112.320000 ;
  END
 END n_lo_d[529]
 PIN n_lo_d[530]
  DIRECTION OUTPUT ;
  USE SIGNAL ;
  PORT
   LAYER M5 ;
   RECT 101.808000 112.236000 101.832000 112.320000 ;
  END
 END n_lo_d[530]
 PIN n_lo_d[531]
  DIRECTION OUTPUT ;
  USE SIGNAL ;
  PORT
   LAYER M5 ;
   RECT 101.952000 112.236000 101.976000 112.320000 ;
  END
 END n_lo_d[531]
 PIN n_lo_d[532]
  DIRECTION OUTPUT ;
  USE SIGNAL ;
  PORT
   LAYER M5 ;
   RECT 102.096000 112.236000 102.120000 112.320000 ;
  END
 END n_lo_d[532]
 PIN n_lo_d[533]
  DIRECTION OUTPUT ;
  USE SIGNAL ;
  PORT
   LAYER M5 ;
   RECT 102.288000 112.236000 102.312000 112.320000 ;
  END
 END n_lo_d[533]
 PIN n_lo_d[534]
  DIRECTION OUTPUT ;
  USE SIGNAL ;
  PORT
   LAYER M5 ;
   RECT 102.480000 112.236000 102.504000 112.320000 ;
  END
 END n_lo_d[534]
 PIN n_lo_d[535]
  DIRECTION OUTPUT ;
  USE SIGNAL ;
  PORT
   LAYER M5 ;
   RECT 102.672000 112.236000 102.696000 112.320000 ;
  END
 END n_lo_d[535]
 PIN n_lo_d[536]
  DIRECTION OUTPUT ;
  USE SIGNAL ;
  PORT
   LAYER M5 ;
   RECT 102.816000 112.236000 102.840000 112.320000 ;
  END
 END n_lo_d[536]
 PIN n_lo_d[537]
  DIRECTION OUTPUT ;
  USE SIGNAL ;
  PORT
   LAYER M5 ;
   RECT 103.008000 112.236000 103.032000 112.320000 ;
  END
 END n_lo_d[537]
 PIN n_lo_d[538]
  DIRECTION OUTPUT ;
  USE SIGNAL ;
  PORT
   LAYER M5 ;
   RECT 103.200000 112.236000 103.224000 112.320000 ;
  END
 END n_lo_d[538]
 PIN n_lo_d[539]
  DIRECTION OUTPUT ;
  USE SIGNAL ;
  PORT
   LAYER M5 ;
   RECT 103.392000 112.236000 103.416000 112.320000 ;
  END
 END n_lo_d[539]
 PIN n_lo_d[540]
  DIRECTION OUTPUT ;
  USE SIGNAL ;
  PORT
   LAYER M5 ;
   RECT 103.536000 112.236000 103.560000 112.320000 ;
  END
 END n_lo_d[540]
 PIN n_lo_d[541]
  DIRECTION OUTPUT ;
  USE SIGNAL ;
  PORT
   LAYER M5 ;
   RECT 103.728000 112.236000 103.752000 112.320000 ;
  END
 END n_lo_d[541]
 PIN n_lo_d[542]
  DIRECTION OUTPUT ;
  USE SIGNAL ;
  PORT
   LAYER M5 ;
   RECT 103.920000 112.236000 103.944000 112.320000 ;
  END
 END n_lo_d[542]
 PIN n_lo_d[543]
  DIRECTION OUTPUT ;
  USE SIGNAL ;
  PORT
   LAYER M5 ;
   RECT 104.112000 112.236000 104.136000 112.320000 ;
  END
 END n_lo_d[543]
 PIN n_lo_d[544]
  DIRECTION OUTPUT ;
  USE SIGNAL ;
  PORT
   LAYER M5 ;
   RECT 104.256000 112.236000 104.280000 112.320000 ;
  END
 END n_lo_d[544]
 PIN n_lo_d[545]
  DIRECTION OUTPUT ;
  USE SIGNAL ;
  PORT
   LAYER M5 ;
   RECT 104.448000 112.236000 104.472000 112.320000 ;
  END
 END n_lo_d[545]
 PIN n_lo_d[546]
  DIRECTION OUTPUT ;
  USE SIGNAL ;
  PORT
   LAYER M5 ;
   RECT 104.640000 112.236000 104.664000 112.320000 ;
  END
 END n_lo_d[546]
 PIN n_lo_d[547]
  DIRECTION OUTPUT ;
  USE SIGNAL ;
  PORT
   LAYER M5 ;
   RECT 104.832000 112.236000 104.856000 112.320000 ;
  END
 END n_lo_d[547]
 PIN n_lo_d[548]
  DIRECTION OUTPUT ;
  USE SIGNAL ;
  PORT
   LAYER M5 ;
   RECT 104.976000 112.236000 105.000000 112.320000 ;
  END
 END n_lo_d[548]
 PIN n_lo_d[549]
  DIRECTION OUTPUT ;
  USE SIGNAL ;
  PORT
   LAYER M5 ;
   RECT 105.168000 112.236000 105.192000 112.320000 ;
  END
 END n_lo_d[549]
 PIN n_lo_d[550]
  DIRECTION OUTPUT ;
  USE SIGNAL ;
  PORT
   LAYER M5 ;
   RECT 105.360000 112.236000 105.384000 112.320000 ;
  END
 END n_lo_d[550]
 PIN n_lo_d[551]
  DIRECTION OUTPUT ;
  USE SIGNAL ;
  PORT
   LAYER M5 ;
   RECT 105.456000 112.236000 105.480000 112.320000 ;
  END
 END n_lo_d[551]
 PIN n_lo_d[552]
  DIRECTION OUTPUT ;
  USE SIGNAL ;
  PORT
   LAYER M5 ;
   RECT 105.504000 112.236000 105.528000 112.320000 ;
  END
 END n_lo_d[552]
 PIN n_li_r
  DIRECTION OUTPUT ;
  USE SIGNAL ;
  PORT
   LAYER M5 ;
   RECT 105.552000 112.236000 105.576000 112.320000 ;
  END
 END n_li_r
 PIN n_rxv
  DIRECTION OUTPUT ;
  USE SIGNAL ;
  PORT
   LAYER M5 ;
   RECT 106.128000 112.236000 106.152000 112.320000 ;
  END
 END n_rxv
 PIN rs_k
  DIRECTION INPUT ;
  USE SIGNAL ;
  PORT
   LAYER M5 ;
   RECT 4.320000 0.000000 4.344000 0.084000 ;
  END
 END rs_k
 PIN rs_n
  DIRECTION INPUT ;
  USE SIGNAL ;
  PORT
   LAYER M5 ;
   RECT 107.952000 0.000000 107.976000 0.084000 ;
  END
 END rs_n
 PIN ck_k
  DIRECTION INPUT ;
  USE CLOCK ;
  PORT
   LAYER M5 ;
   RECT 56.148000 0.000000 56.196000 0.480000 ;
  END
 END ck_k
 PIN ck_n
  DIRECTION INPUT ;
  USE CLOCK ;
  PORT
   LAYER M5 ;
   RECT 56.148000 111.840000 56.196000 112.320000 ;
  END
 END ck_n
  PIN VSS
    DIRECTION INOUT ;
    USE GROUND ;
    PORT
      LAYER M5 ;
        RECT  105.684 4.297 105.804 108.023 ;
        RECT  101.364 4.297 101.484 108.023 ;
        RECT  97.044 4.297 97.164 108.023 ;
        RECT  92.724 4.297 92.844 108.023 ;
        RECT  88.404 4.297 88.524 108.023 ;
        RECT  84.084 4.297 84.204 108.023 ;
        RECT  79.764 4.297 79.884 108.023 ;
        RECT  75.444 4.297 75.564 108.023 ;
        RECT  71.124 4.297 71.244 108.023 ;
        RECT  66.804 4.297 66.924 108.023 ;
        RECT  62.484 4.297 62.604 108.023 ;
        RECT  58.164 4.297 58.284 108.023 ;
        RECT  53.844 4.297 53.964 108.023 ;
        RECT  49.524 4.297 49.644 108.023 ;
        RECT  45.204 4.297 45.324 108.023 ;
        RECT  40.884 4.297 41.004 108.023 ;
        RECT  36.564 4.297 36.684 108.023 ;
        RECT  32.244 4.297 32.364 108.023 ;
        RECT  27.924 4.297 28.044 108.023 ;
        RECT  23.604 4.297 23.724 108.023 ;
        RECT  19.284 4.297 19.404 108.023 ;
        RECT  14.964 4.297 15.084 108.023 ;
        RECT  10.644 4.297 10.764 108.023 ;
        RECT  6.324 4.297 6.444 108.023 ;
    END
  END VSS
  PIN VDD
    DIRECTION INOUT ;
    USE POWER ;
    PORT
      LAYER M5 ;
        RECT  105.876 4.311 105.996 108.009 ;
        RECT  101.556 4.311 101.676 108.009 ;
        RECT  97.236 4.311 97.356 108.009 ;
        RECT  92.916 4.311 93.036 108.009 ;
        RECT  88.596 4.311 88.716 108.009 ;
        RECT  84.276 4.311 84.396 108.009 ;
        RECT  79.956 4.311 80.076 108.009 ;
        RECT  75.636 4.311 75.756 108.009 ;
        RECT  71.316 4.311 71.436 108.009 ;
        RECT  66.996 4.311 67.116 108.009 ;
        RECT  62.676 4.311 62.796 108.009 ;
        RECT  58.356 4.311 58.476 108.009 ;
        RECT  54.036 4.311 54.156 108.009 ;
        RECT  49.716 4.311 49.836 108.009 ;
        RECT  45.396 4.311 45.516 108.009 ;
        RECT  41.076 4.311 41.196 108.009 ;
        RECT  36.756 4.311 36.876 108.009 ;
        RECT  32.436 4.311 32.556 108.009 ;
        RECT  28.116 4.311 28.236 108.009 ;
        RECT  23.796 4.311 23.916 108.009 ;
        RECT  19.476 4.311 19.596 108.009 ;
        RECT  15.156 4.311 15.276 108.009 ;
        RECT  10.836 4.311 10.956 108.009 ;
        RECT  6.516 4.311 6.636 108.009 ;
    END
  END VDD
END ot_s81_mu72_lnland_nst
END LIBRARY
